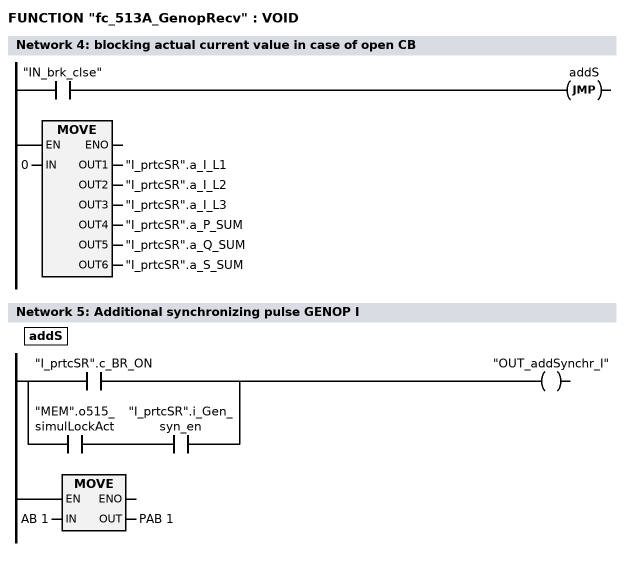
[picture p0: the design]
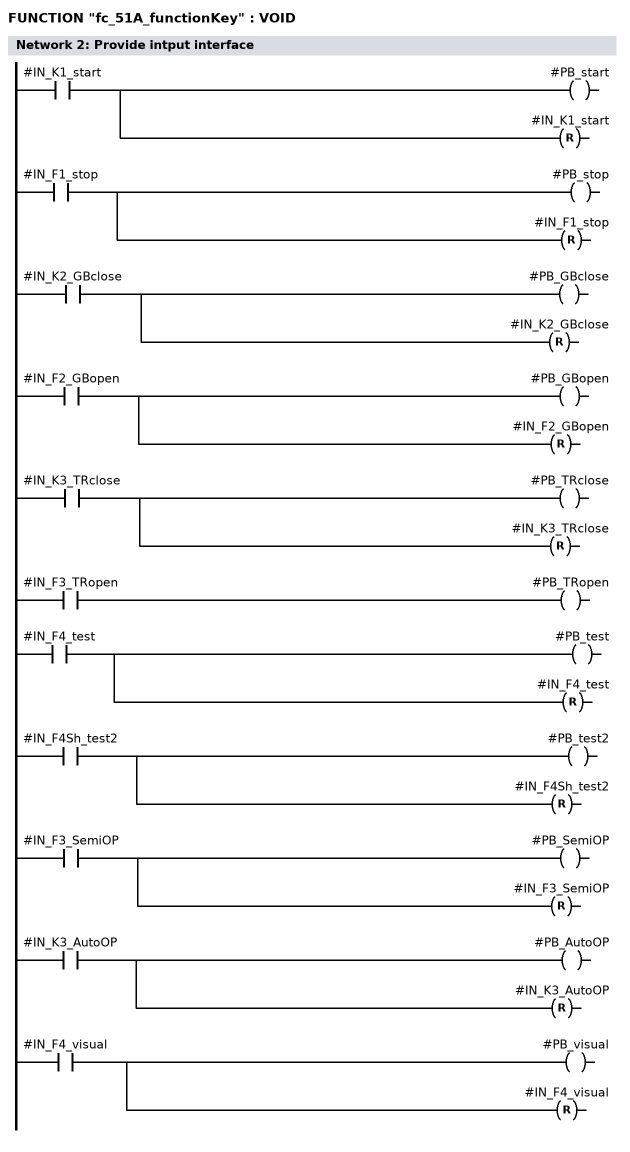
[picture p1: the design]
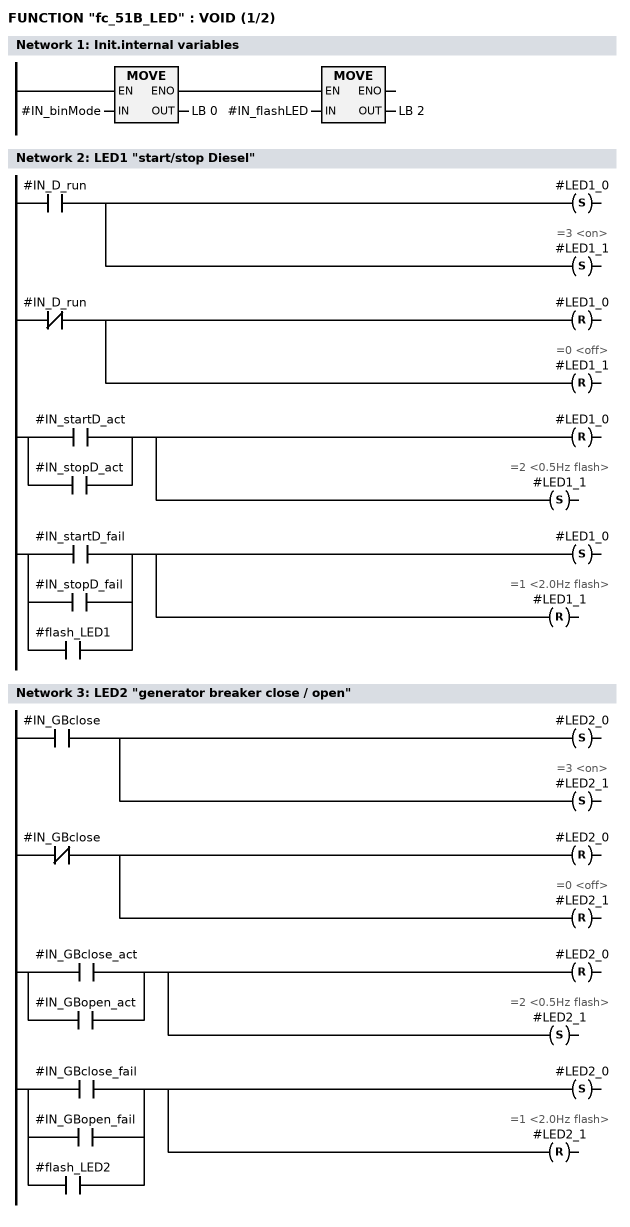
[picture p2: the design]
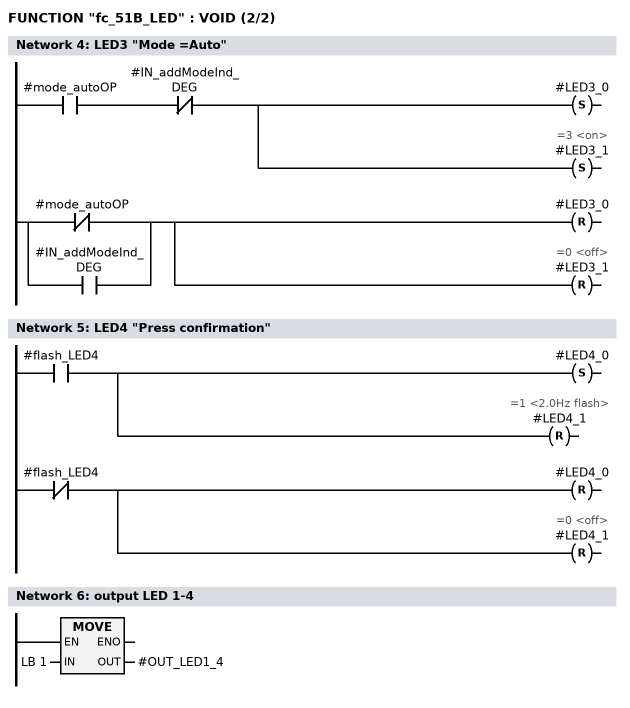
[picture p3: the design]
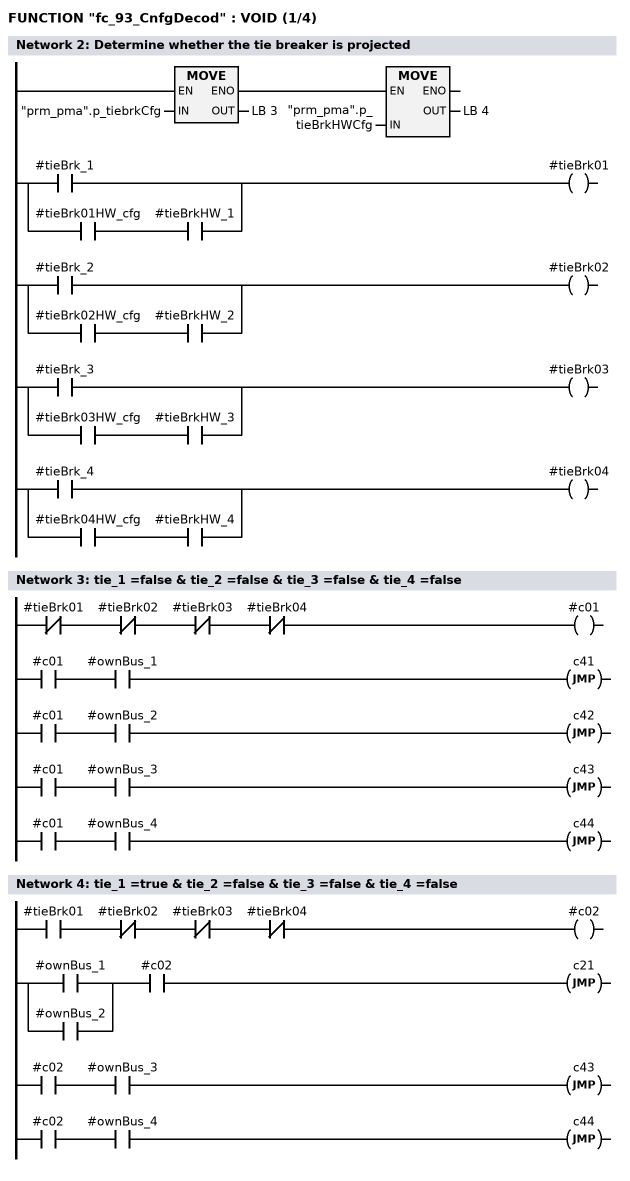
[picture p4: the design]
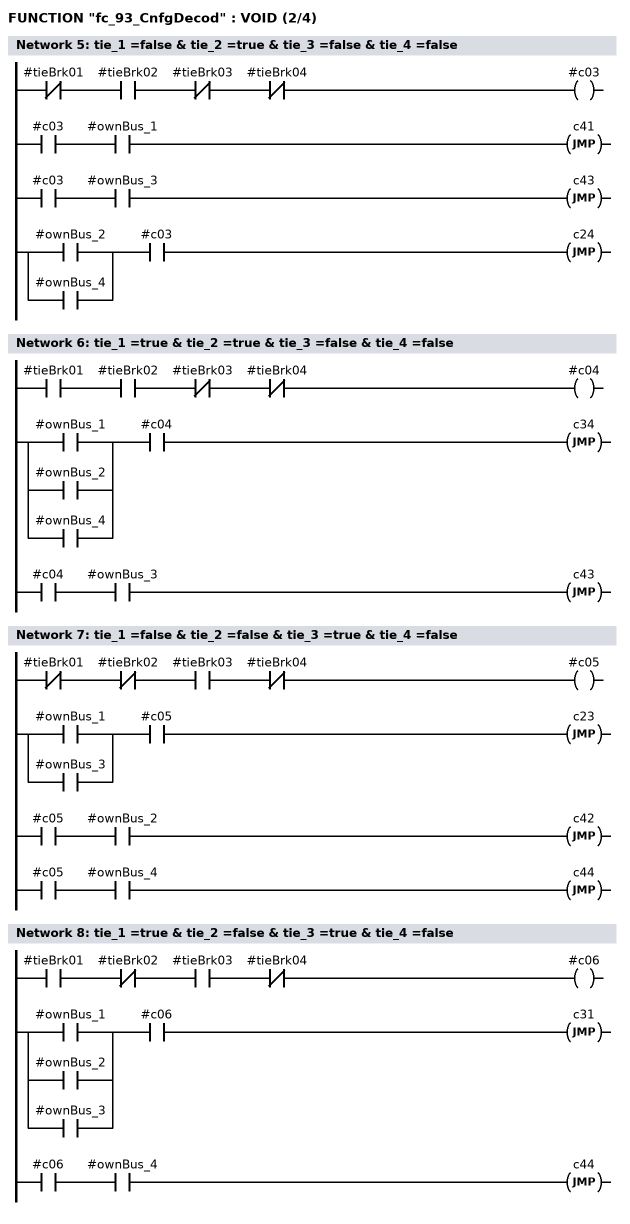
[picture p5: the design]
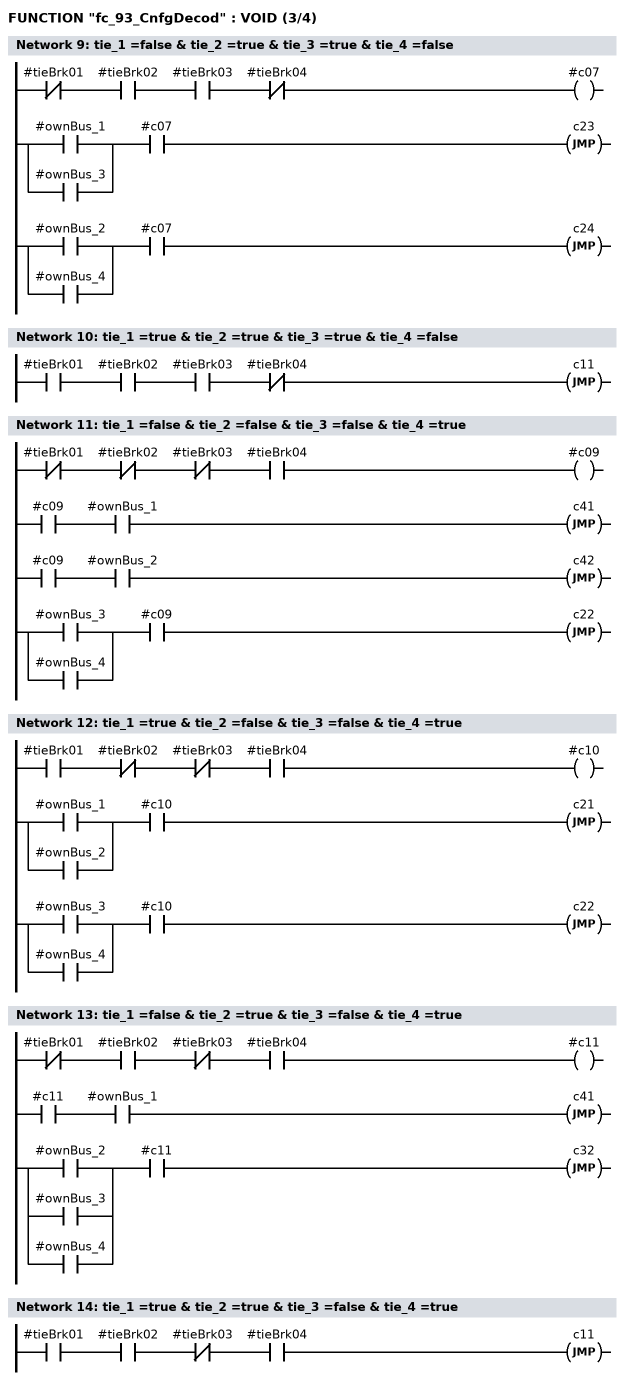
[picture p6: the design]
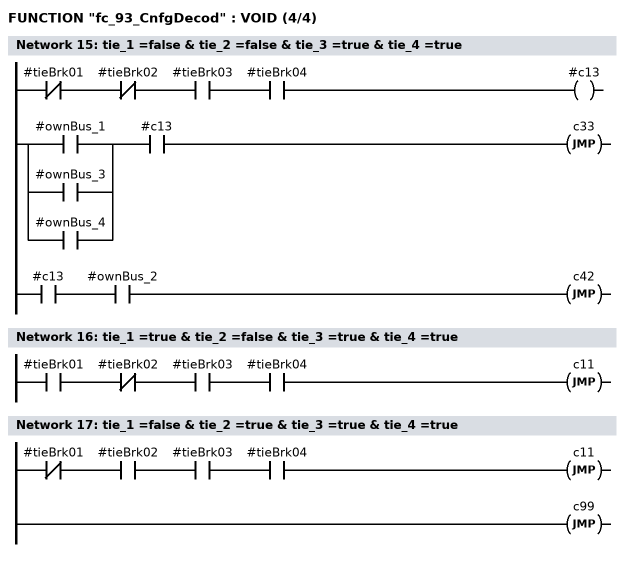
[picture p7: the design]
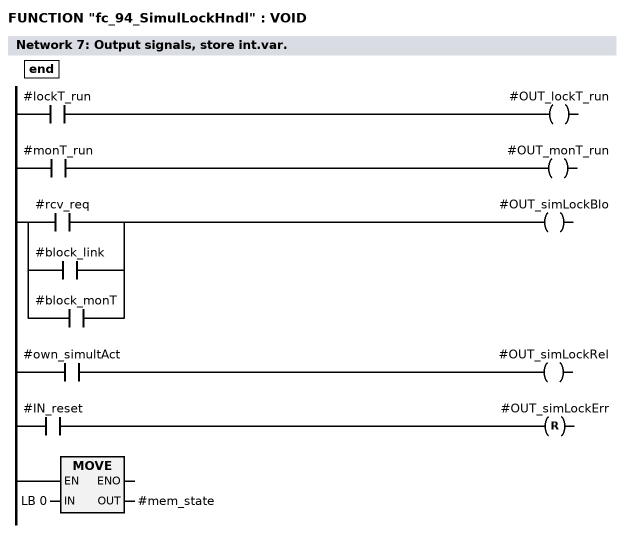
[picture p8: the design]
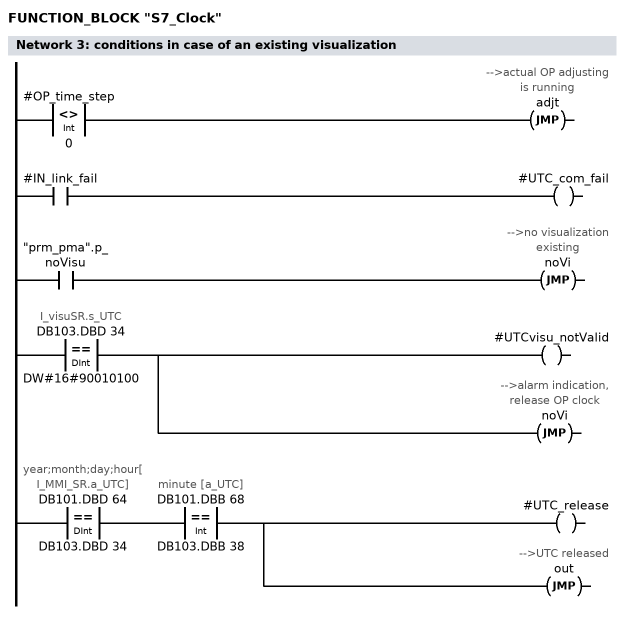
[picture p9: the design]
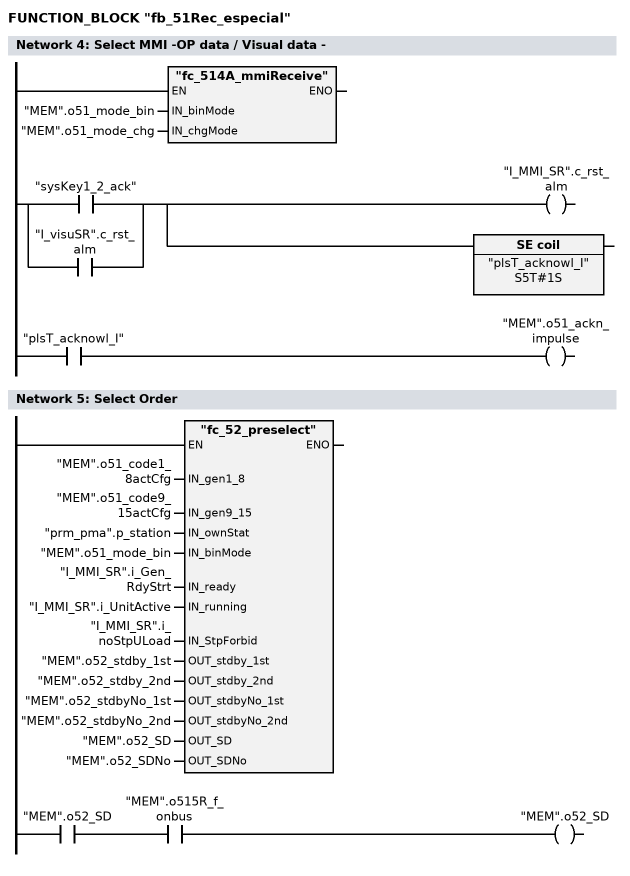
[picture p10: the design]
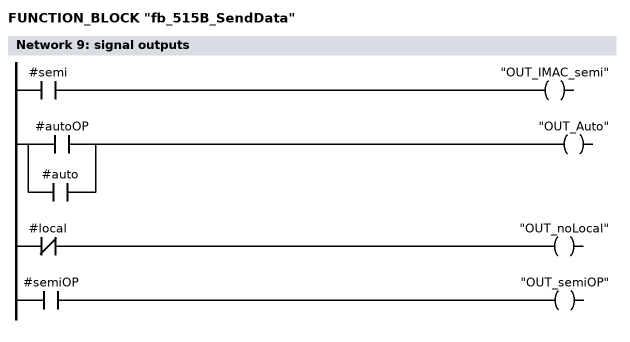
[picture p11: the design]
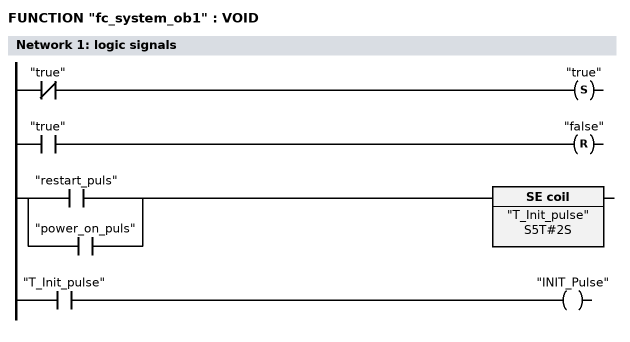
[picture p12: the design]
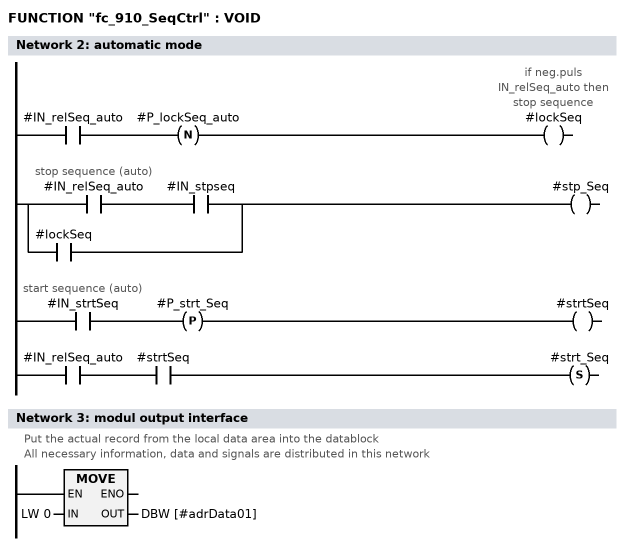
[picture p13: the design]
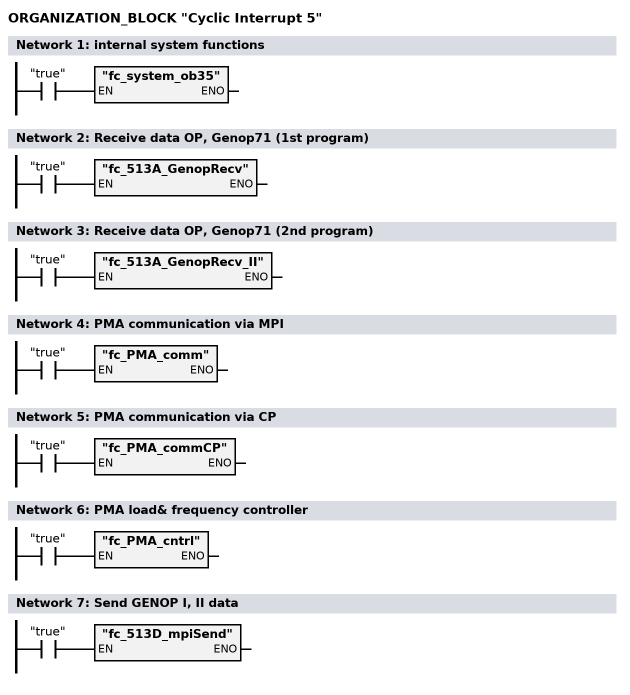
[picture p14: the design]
DATA_BLOCK "DB     35"
TITLE =Internal data:  Step (sequence) contoller
//                                                                                      !
//This data block is the internal data area for the following functions:
//- step controller (FC119)
//- sequence controller (FC120)
//- transition indicator (FC121)
AUTHOR : Kahle
FAMILY : PMA71
NAME : stepCtrl
VERSION : 1.1


  STRUCT    //record 1.sequence
   sequence_1 : STRUCT
    strt_Seq : BOOL ;   //start sequence (preStepNo =1) --system interface--
    stp_Seq : BOOL ;    //stop sequence (reset, delete all register) --system interface--
    var2 : BOOL ;   // var 2
    var3 : BOOL ;   // var 3
    var4 : BOOL ;   // var 4
    var5 : BOOL ;   // var 5
    var6 : BOOL ;   // var 6
    var7 : BOOL ;   // var 7
    var8 : BOOL ;   // var 8
    var9 : BOOL ;   // var 9
    var10 : BOOL ;  // var 10
    var11 : BOOL ;  // var 11
    var12 : BOOL ;  // var 12
    var13 : BOOL ;  // var 13
    var14 : BOOL ;  // var 14
    var15 : BOOL ;   // var 15
    P_cntWait : BOOL ;  // puls flag "counter start waiting time"(.0)
    P_cntMon : BOOL ;   // puls flag "counter start monitoring time"(.1)
    P_nextAct : BOOL ;  // puls flag "out_next" active(.2)
    P_IN_trans : BOOL ; // puls flag "in_trans" (.3)
    preStepNo : BYTE ;  // number of the pre step
    actStepNo : BYTE ;  // actual step
    postStepNo : BYTE ; // number of the post step
    actwaitT : INT ;    // actual waiting time
    actmonT : INT ; // actual monitoring time
    failStep : INT ;    // number of the faulty step
    failTrans : INT ;   // transition condition of the faulty step
   END_STRUCT ;
   sequence_2 : STRUCT
    strt_Seq : BOOL ;   //start sequence (preStepNo =1) --system interface--
    stp_Seq : BOOL ;    //stop sequence (reset, delete all register) --system interface--
    var2 : BOOL ;   // var 2
    var3 : BOOL ;   // var 3
    var4 : BOOL ;   // var 4
    var5 : BOOL ;   // var 5
    var6 : BOOL ;   // var 6
    var7 : BOOL ;   // var 7
    var8 : BOOL ; // var 8
    var9 : BOOL ;   // var 9
    var10 : BOOL ;  // var 10
    var11 : BOOL ;  // var 11
    var12 : BOOL ;  // var 12
    var13 : BOOL ;  // var 13
    var14 : BOOL ;  // var 14
    var15 : BOOL ;  // var 15
    P_cntWait : BOOL ;  // puls flag "counter start waiting time"(.0)
    P_cntMon : BOOL ;   // puls flag "counter start monitoring time"(.1)
    P_nextAct : BOOL ;  // puls flag "out_next" active(.2)
    P_IN_trans : BOOL ; // puls flag "in_trans" (.3)
    preStepNo : BYTE ;  // number of the pre step
    actStepNo : BYTE ;  // actual step
    postStepNo : BYTE ; // number of the post step
    actwaitT : INT ;    // actual waiting time
    actmonT : INT ; // actual monitoring time
    failStep : INT ;    // number of the faulty step
    failTrans : INT ;   // transition condition of the faulty step
   END_STRUCT ;
   sequence_3 : STRUCT
    strt_Seq : BOOL ;   //start sequence (preStepNo =1) --system interface--
    stp_Seq : BOOL ;    //stop sequence (reset, delete all register) --system interface--
    var2 : BOOL ;   // var 2
    var3 : BOOL ;   // var 3
    var4 : BOOL ;   // var 4
    var5 : BOOL ;   // var 5
    var6 : BOOL ;   // var 6
    var7 : BOOL ;   // var 7
    var8 : BOOL ;   // var 8
    var9 : BOOL ;   // var 9
    var10 : BOOL ;  // var 10
    var11 : BOOL ;  // var 11
    var12 : BOOL ;  // var 12
    var13 : BOOL ;  // var 13
    var14 : BOOL ;  // var 14
    var15 : BOOL ;  // var 15
    P_cntWait : BOOL ;  // puls flag "counter start waiting time"(.0)
    P_cntMon : BOOL ;   // puls flag "counter start monitoring time"(.1)
    P_nextAct : BOOL ;  // puls flag "out_next" active(.2)
    P_IN_trans : BOOL ; // puls flag "in_trans" (.3)
    preStepNo : BYTE ;  // number of the pre step
    actStepNo : BYTE ;  // actual step
    postStepNo : BYTE ; // number of the post step
    actwaitT : INT ;    // actual waiting time
    actmonT : INT ; // actual monitoring time
    failStep : INT ;    // number of the faulty step
    failTrans : INT ;   // transition condition of the faulty step
   END_STRUCT ;
   sequence_4 : STRUCT
    strt_Seq : BOOL ;   //start sequence (preStepNo =1) --system interface--
    stp_Seq : BOOL ;    //stop sequence (reset, delete all register) --system interface--
    var2 : BOOL ;   // var 2
    var3 : BOOL ;   // var 3
    var4 : BOOL ;   // var 4
    var5 : BOOL ;   // var 5
    var6 : BOOL ;   // var 6
    var7 : BOOL ;   // var 7
    var8 : BOOL ;   // var 8
    var9 : BOOL ;   // var 9
    var10 : BOOL ;  // var 10
    var11 : BOOL ;  // var 11
    var12 : BOOL ;  // var 12
    var13 : BOOL ;  // var 13
    var14 : BOOL ;  // var 14
    var15 : BOOL ;  // var 15
    P_cntWait : BOOL ;  // puls flag "counter start waiting time"(.0)
    P_cntMon : BOOL ;   // puls flag "counter start monitoring time"(.1)
    P_nextAct : BOOL ;  // puls flag "out_next" active(.2)
    P_IN_trans : BOOL ; // puls flag "in_trans" (.3)
    preStepNo : BYTE ;  // number of the pre step
    actStepNo : BYTE ;  // actual step
    postStepNo : BYTE ; // number of the post step
    actwaitT : INT ;  // actual waiting time
    actmonT : INT ; // actual monitoring time
    failStep : INT ;    // number of the faulty step
    failTrans : INT ;   // transition condition of the faulty step
   END_STRUCT ;
   sequence_5 : STRUCT
    strt_Seq : BOOL ;   //start sequence (preStepNo =1) --system interface--
    stp_Seq : BOOL ;    //stop sequence (reset, delete all register) --system interface--
    var2 : BOOL ;   // var 2
    var3 : BOOL ;   // var 3
    var4 : BOOL ;   // var 4
    var5 : BOOL ;   // var 5
    var6 : BOOL ;   // var 6
    var7 : BOOL ;   // var 7
    var8 : BOOL ;   // var 8
    var9 : BOOL ;   // var 9
    var10 : BOOL ;  // var 10
    var11 : BOOL ;  // var 11
    var12 : BOOL ;  // var 12
    var13 : BOOL ;  // var 13
    var14 : BOOL ;  // var 14
    var15 : BOOL ;  // var 15
    P_cntWait : BOOL ;  // puls flag "counter start waiting time"(.0)
    P_cntMon : BOOL ;   // puls flag "counter start monitoring time"(.1)
    P_nextAct : BOOL ;  // puls flag "out_next" active(.2)
    P_IN_trans : BOOL ; // puls flag "in_trans" (.3)
    preStepNo : BYTE ;  // number of the pre step
    actStepNo : BYTE ;  // actual step
    postStepNo : BYTE ; // number of the post step
    actwaitT : INT ;    // actual waiting time
    actmonT : INT ; // actual monitoring time
    failStep : INT ;    // number of the faulty step
    failTrans : INT ;   // transition condition of the faulty step
   END_STRUCT ;
   sequence_6 : STRUCT
    strt_Seq : BOOL ;   //start sequence (preStepNo =1) --system interface--
    stp_Seq : BOOL ;    //stop sequence (reset, delete all register) --system interface--
    var2 : BOOL ;   // var 2
    var3 : BOOL ;   // var 3
    var4 : BOOL ;   // var 4
    var5 : BOOL ;   // var 5
    var6 : BOOL ;   // var 6
    var7 : BOOL ;   // var 7
    var8 : BOOL ;   // var 8
    var9 : BOOL ;   // var 9
    var10 : BOOL ;  // var 10
    var11 : BOOL ;  // var 11
    var12 : BOOL ;  // var 12
    var13 : BOOL ;  // var 13
    var14 : BOOL ;  // var 14
    var15 : BOOL ;  // var 15
    P_cntWait : BOOL ;   // puls flag "counter start waiting time"(.0)
    P_cntMon : BOOL ;   // puls flag "counter start monitoring time"(.1)
    P_nextAct : BOOL ;  // puls flag "out_next" active(.2)
    P_IN_trans : BOOL ; // puls flag "in_trans" (.3)
    preStepNo : BYTE ;  // number of the pre step
    actStepNo : BYTE ;  // actual step
    postStepNo : BYTE ; // number of the post step
    actwaitT : INT ;    // actual waiting time
    actmonT : INT ; // actual monitoring time
    failStep : INT ;    // number of the faulty step
    failTrans : INT ;   // transition condition of the faulty step
   END_STRUCT ;
   sequence_7 : STRUCT
    strt_Seq : BOOL ;   //start sequence (preStepNo =1) --system interface--
    stp_Seq : BOOL ;    //stop sequence (reset, delete all register) --system interface--
    var2 : BOOL ;   // var 2
    var3 : BOOL ;   // var 3
    var4 : BOOL ;   // var 4
    var5 : BOOL ;   // var 5
    var6 : BOOL ;   // var 6
    var7 : BOOL ;   // var 7
    var8 : BOOL ;   // var 8
    var9 : BOOL ;   // var 9
    var10 : BOOL ;    // var 10
    var11 : BOOL ;  // var 11
    var12 : BOOL ;  // var 12
    var13 : BOOL ;  // var 13
    var14 : BOOL ;  // var 14
    var15 : BOOL ;  // var 15
    P_cntWait : BOOL ;  // puls flag "counter start waiting time"(.0)
    P_cntMon : BOOL ;   // puls flag "counter start monitoring time"(.1)
    P_nextAct : BOOL ;  // puls flag "out_next" active(.2)
    P_IN_trans : BOOL ; // puls flag "in_trans" (.3)
    preStepNo : BYTE ;  // number of the pre step
    actStepNo : BYTE ;  // actual step
    postStepNo : BYTE ; // number of the post step
    actwaitT : INT ;    // actual waiting time
    actmonT : INT ; // actual monitoring time
    failStep : INT ;    // number of the faulty step
    failTrans : INT ;   // transition condition of the faulty step
   END_STRUCT ;
   sequence_8 : STRUCT
    strt_Seq : BOOL ;   //start sequence (preStepNo =1) --system interface--
    stp_Seq : BOOL ;    //stop sequence (reset, delete all register) --system interface--
    var2 : BOOL ;   // var 2
    var3 : BOOL ; // var 3
    var4 : BOOL ;   // var 4
    var5 : BOOL ;   // var 5
    var6 : BOOL ;   // var 6
    var7 : BOOL ;   // var 7
    var8 : BOOL ;   // var 8
    var9 : BOOL ;   // var 9
    var10 : BOOL ;  // var 10
    var11 : BOOL ;  // var 11
    var12 : BOOL ;  // var 12
    var13 : BOOL ;  // var 13
    var14 : BOOL ;  // var 14
    var15 : BOOL ;  // var 15
    P_cntWait : BOOL ;  // puls flag "counter start waiting time"(.0)
    P_cntMon : BOOL ;   // puls flag "counter start monitoring time"(.1)
    P_nextAct : BOOL ;  // puls flag "out_next" active(.2)
    P_IN_trans : BOOL ; // puls flag "in_trans" (.3)
    preStepNo : BYTE ;  // number of the pre step
    actStepNo : BYTE ;  // actual step
    postStepNo : BYTE ; // number of the post step
    actwaitT : INT ;    // actual waiting time
    actmonT : INT ; // actual monitoring time
    failStep : INT ;    // number of the faulty step
    failTrans : INT ;   // transition condition of the faulty step
   END_STRUCT ;
   sequence_9 : STRUCT
    strt_Seq : BOOL ;   //start sequence (preStepNo =1) --system interface--
    stp_Seq : BOOL ;    //stop sequence (reset, delete all register) --system interface--
    var2 : BOOL ;   // var 2
    var3 : BOOL ;   // var 3
    var4 : BOOL ;   // var 4
    var5 : BOOL ;   // var 5
    var6 : BOOL ;   // var 6
    var7 : BOOL ;   // var 7
    var8 : BOOL ;   // var 8
    var9 : BOOL ;   // var 9
    var10 : BOOL ;  // var 10
    var11 : BOOL ;  // var 11
    var12 : BOOL ;  // var 12
    var13 : BOOL ;  // var 13
    var14 : BOOL ;  // var 14
    var15 : BOOL ;  // var 15
    P_cntWait : BOOL ;  // puls flag "counter start waiting time"(.0)
    P_cntMon : BOOL ;   // puls flag "counter start monitoring time"(.1)
    P_nextAct : BOOL ;  // puls flag "out_next" active(.2)
    P_IN_trans : BOOL ; // puls flag "in_trans" (.3)
    preStepNo : BYTE ;  // number of the pre step
    actStepNo : BYTE ;  // actual step
    postStepNo : BYTE ; // number of the post step
    actwaitT : INT ;    // actual waiting time
    actmonT : INT ; // actual monitoring time
    failStep : INT ;    // number of the faulty step
    failTrans : INT ;   // transition condition of the faulty step
   END_STRUCT ;
  END_STRUCT ;
BEGIN
   sequence_1.strt_Seq := FALSE;
   sequence_1.stp_Seq := FALSE;
   sequence_1.var2 := FALSE;
   sequence_1.var3 := FALSE;
   sequence_1.var4 := FALSE;
   sequence_1.var5 := FALSE;
   sequence_1.var6 := FALSE;
   sequence_1.var7 := FALSE;
   sequence_1.var8 := FALSE;
   sequence_1.var9 := FALSE;
   sequence_1.var10 := FALSE;
   sequence_1.var11 := FALSE;
   sequence_1.var12 := FALSE;
   sequence_1.var13 := FALSE;
   sequence_1.var14 := FALSE;
   sequence_1.var15 := FALSE;
   sequence_1.P_cntWait := FALSE;
   sequence_1.P_cntMon := FALSE;
   sequence_1.P_nextAct := FALSE;
   sequence_1.P_IN_trans := FALSE;
   sequence_1.preStepNo := B#16#0;
   sequence_1.actStepNo := B#16#0;
   sequence_1.postStepNo := B#16#0;
   sequence_1.actwaitT := 0;
   sequence_1.actmonT := 0;
   sequence_1.failStep := 0;
   sequence_1.failTrans := 0;
   sequence_2.strt_Seq := FALSE;
   sequence_2.stp_Seq := FALSE;
   sequence_2.var2 := FALSE;
   sequence_2.var3 := FALSE;
   sequence_2.var4 := FALSE;
   sequence_2.var5 := FALSE;
   sequence_2.var6 := FALSE;
   sequence_2.var7 := FALSE;
   sequence_2.var8 := FALSE;
   sequence_2.var9 := FALSE;
   sequence_2.var10 := FALSE;
   sequence_2.var11 := FALSE;
   sequence_2.var12 := FALSE;
   sequence_2.var13 := FALSE;
   sequence_2.var14 := FALSE;
   sequence_2.var15 := FALSE;
   sequence_2.P_cntWait := FALSE;
   sequence_2.P_cntMon := FALSE;
   sequence_2.P_nextAct := FALSE;
   sequence_2.P_IN_trans := FALSE;
   sequence_2.preStepNo := B#16#0;
   sequence_2.actStepNo := B#16#0;
   sequence_2.postStepNo := B#16#0;
   sequence_2.actwaitT := 0;
   sequence_2.actmonT := 0;
   sequence_2.failStep := 0;
   sequence_2.failTrans := 0;
   sequence_3.strt_Seq := FALSE;
   sequence_3.stp_Seq := FALSE;
   sequence_3.var2 := FALSE;
   sequence_3.var3 := FALSE;
   sequence_3.var4 := FALSE;
   sequence_3.var5 := FALSE;
   sequence_3.var6 := FALSE;
   sequence_3.var7 := FALSE;
   sequence_3.var8 := FALSE;
   sequence_3.var9 := FALSE;
   sequence_3.var10 := FALSE;
   sequence_3.var11 := FALSE;
   sequence_3.var12 := FALSE;
   sequence_3.var13 := FALSE;
   sequence_3.var14 := FALSE;
   sequence_3.var15 := FALSE;
   sequence_3.P_cntWait := FALSE;
   sequence_3.P_cntMon := FALSE;
   sequence_3.P_nextAct := FALSE;
   sequence_3.P_IN_trans := FALSE;
   sequence_3.preStepNo := B#16#0;
   sequence_3.actStepNo := B#16#0;
   sequence_3.postStepNo := B#16#0;
   sequence_3.actwaitT := 0;
   sequence_3.actmonT := 0;
   sequence_3.failStep := 0;
   sequence_3.failTrans := 0;
   sequence_4.strt_Seq := FALSE;
   sequence_4.stp_Seq := FALSE;
   sequence_4.var2 := FALSE;
   sequence_4.var3 := FALSE;
   sequence_4.var4 := FALSE;
   sequence_4.var5 := FALSE;
   sequence_4.var6 := FALSE;
   sequence_4.var7 := FALSE;
   sequence_4.var8 := FALSE;
   sequence_4.var9 := FALSE;
   sequence_4.var10 := FALSE;
   sequence_4.var11 := FALSE;
   sequence_4.var12 := FALSE;
   sequence_4.var13 := FALSE;
   sequence_4.var14 := FALSE;
   sequence_4.var15 := FALSE;
   sequence_4.P_cntWait := FALSE;
   sequence_4.P_cntMon := FALSE;
   sequence_4.P_nextAct := FALSE;
   sequence_4.P_IN_trans := FALSE;
   sequence_4.preStepNo := B#16#0;
   sequence_4.actStepNo := B#16#0;
   sequence_4.postStepNo := B#16#0;
   sequence_4.actwaitT := 0;
   sequence_4.actmonT := 0;
   sequence_4.failStep := 0;
   sequence_4.failTrans := 0;
   sequence_5.strt_Seq := FALSE;
   sequence_5.stp_Seq := FALSE;
   sequence_5.var2 := FALSE;
   sequence_5.var3 := FALSE;
   sequence_5.var4 := FALSE;
   sequence_5.var5 := FALSE;
   sequence_5.var6 := FALSE;
   sequence_5.var7 := FALSE;
   sequence_5.var8 := FALSE;
   sequence_5.var9 := FALSE;
   sequence_5.var10 := FALSE;
   sequence_5.var11 := FALSE;
   sequence_5.var12 := FALSE;
   sequence_5.var13 := FALSE;
   sequence_5.var14 := FALSE;
   sequence_5.var15 := FALSE;
   sequence_5.P_cntWait := FALSE;
   sequence_5.P_cntMon := FALSE;
   sequence_5.P_nextAct := FALSE;
   sequence_5.P_IN_trans := FALSE;
   sequence_5.preStepNo := B#16#0;
   sequence_5.actStepNo := B#16#0;
   sequence_5.postStepNo := B#16#0;
   sequence_5.actwaitT := 0;
   sequence_5.actmonT := 0;
   sequence_5.failStep := 0;
   sequence_5.failTrans := 0;
   sequence_6.strt_Seq := FALSE;
   sequence_6.stp_Seq := FALSE;
   sequence_6.var2 := FALSE;
   sequence_6.var3 := FALSE;
   sequence_6.var4 := FALSE;
   sequence_6.var5 := FALSE;
   sequence_6.var6 := FALSE;
   sequence_6.var7 := FALSE;
   sequence_6.var8 := FALSE;
   sequence_6.var9 := FALSE;
   sequence_6.var10 := FALSE;
   sequence_6.var11 := FALSE;
   sequence_6.var12 := FALSE;
   sequence_6.var13 := FALSE;
   sequence_6.var14 := FALSE;
   sequence_6.var15 := FALSE;
   sequence_6.P_cntWait := FALSE;
   sequence_6.P_cntMon := FALSE;
   sequence_6.P_nextAct := FALSE;
   sequence_6.P_IN_trans := FALSE;
   sequence_6.preStepNo := B#16#0;
   sequence_6.actStepNo := B#16#0;
   sequence_6.postStepNo := B#16#0;
   sequence_6.actwaitT := 0;
   sequence_6.actmonT := 0;
   sequence_6.failStep := 0;
   sequence_6.failTrans := 0;
   sequence_7.strt_Seq := FALSE;
   sequence_7.stp_Seq := FALSE;
   sequence_7.var2 := FALSE;
   sequence_7.var3 := FALSE;
   sequence_7.var4 := FALSE;
   sequence_7.var5 := FALSE;
   sequence_7.var6 := FALSE;
   sequence_7.var7 := FALSE;
   sequence_7.var8 := FALSE;
   sequence_7.var9 := FALSE;
   sequence_7.var10 := FALSE;
   sequence_7.var11 := FALSE;
   sequence_7.var12 := FALSE;
   sequence_7.var13 := FALSE;
   sequence_7.var14 := FALSE;
   sequence_7.var15 := FALSE;
   sequence_7.P_cntWait := FALSE;
   sequence_7.P_cntMon := FALSE;
   sequence_7.P_nextAct := FALSE;
   sequence_7.P_IN_trans := FALSE;
   sequence_7.preStepNo := B#16#0;
   sequence_7.actStepNo := B#16#0;
   sequence_7.postStepNo := B#16#0;
   sequence_7.actwaitT := 0;
   sequence_7.actmonT := 0;
   sequence_7.failStep := 0;
   sequence_7.failTrans := 0;
   sequence_8.strt_Seq := FALSE;
   sequence_8.stp_Seq := FALSE;
   sequence_8.var2 := FALSE;
   sequence_8.var3 := FALSE;
   sequence_8.var4 := FALSE;
   sequence_8.var5 := FALSE;
   sequence_8.var6 := FALSE;
   sequence_8.var7 := FALSE;
   sequence_8.var8 := FALSE;
   sequence_8.var9 := FALSE;
   sequence_8.var10 := FALSE;
   sequence_8.var11 := FALSE;
   sequence_8.var12 := FALSE;
   sequence_8.var13 := FALSE;
   sequence_8.var14 := FALSE;
   sequence_8.var15 := FALSE;
   sequence_8.P_cntWait := FALSE;
   sequence_8.P_cntMon := FALSE;
   sequence_8.P_nextAct := FALSE;
   sequence_8.P_IN_trans := FALSE;
   sequence_8.preStepNo := B#16#0;
   sequence_8.actStepNo := B#16#0;
   sequence_8.postStepNo := B#16#0;
   sequence_8.actwaitT := 0;
   sequence_8.actmonT := 0;
   sequence_8.failStep := 0;
   sequence_8.failTrans := 0;
   sequence_9.strt_Seq := FALSE;
   sequence_9.stp_Seq := FALSE;
   sequence_9.var2 := FALSE;
   sequence_9.var3 := FALSE;
   sequence_9.var4 := FALSE;
   sequence_9.var5 := FALSE;
   sequence_9.var6 := FALSE;
   sequence_9.var7 := FALSE;
   sequence_9.var8 := FALSE;
   sequence_9.var9 := FALSE;
   sequence_9.var10 := FALSE;
   sequence_9.var11 := FALSE;
   sequence_9.var12 := FALSE;
   sequence_9.var13 := FALSE;
   sequence_9.var14 := FALSE;
   sequence_9.var15 := FALSE;
   sequence_9.P_cntWait := FALSE;
   sequence_9.P_cntMon := FALSE;
   sequence_9.P_nextAct := FALSE;
   sequence_9.P_IN_trans := FALSE;
   sequence_9.preStepNo := B#16#0;
   sequence_9.actStepNo := B#16#0;
   sequence_9.postStepNo := B#16#0;
   sequence_9.actwaitT := 0;
   sequence_9.actmonT := 0;
   sequence_9.failStep := 0;
   sequence_9.failTrans := 0;
END_DATA_BLOCK

DATA_BLOCK "prm_pma"
TITLE =Configuration data: PMA71 without GENOP71 data
//
//V 2.2 28.09.00 Kahle -last vaild version
//V 2.3 05.10.00 Kahle -DBX602.6, DBX602.7 new description
//                                  -DBW490 p_LimCurrMonit
//                                  -DBW650 p_dlyT_GenBrkTrip
//                                  -DBW652 p_dlyT_TrsBrkTrip
//                                  -DBW654 p_dlyT_GenBrkReady
//                                  -DBW656 p_dlyT_TrsBrkReady
//V 2.4 10.10.00 Kahle -DBX42.4 p_3Tie_cycle
//V 2.5 17.10.00 Kahle -DBW890&892 move to DBW900&902
//V 2.6 05.12.00 Kahle -DBB600    p_TrsBrk_No
//                                  -DBX601.0 p_2ndGenBrkON_auto
//                                  -DBX660.5 p_blackout_BrkOff
//                                  -DBX904.0 p_TrsLine
//V2.7 13.02.01 Kahle -DBX366.5 p_noStpCmd-SD2
//                                 -DBX395.0 p_uploadLatch
//                                 -DBX67.7 p_MonitPrLubPress
//                                 -DBX77.0 p_NoPreLub_Blackout
//                                 -DBW94 p_VoltMiss
//                                 -DBX536.0 p_wood_Isochron
//                                - DBX536.1 p_wood_IsochronAuto
//                                 -DBX536.2 p_wood_IsochronExt
//                                 -DBX536.3 p_wood_IsochronLowAct
//V2.11 23.10.03 Kahle -DBW910 p_SG_Deexcit_Under_Frec
AUTHOR : Kahle
FAMILY : PMA71
NAME : prm_pma
VERSION : 2.11


  STRUCT
   p_station : BYTE  := B#16#5; //PMA station
   p_bus_part : BYTE  := B#16#1;    //Corresponding busbar of the station and tie breaker
   p_stat_add : BYTE ;  //Station addition =0:DieselGen/=1:Shaft Gen/=2:EG/=3:DEG/=4:TB/=5:SC)
   p_tiebrkCfg : BYTE ; //Tie breaker (x.0=TieBrk1... x.3=TieBrk4/ x.5=2nd TieBrk2... x.7=2nd TieBrk4)
   p_tieBrkHWCfg : BYTE ;   //Tie breaker as binary input (x.0 =TieBrk1 ... x.3 =TieBrk4)
   p_cfg11 : WORD  := W#16#3007;    //Bus Config 11 (x.0 =stat.1 ...x.12 =stat.13, x.13 =emerg, x.14,15 =shore1, 2)
   p_cfg21 : WORD ; //Bus Config 21 (x.0 =stat.1 ...x.12 =stat.13, x.13 =emerg, x.14,15 =shore1, 2)
   p_cfg22 : WORD ; //Bus Config 22 (x.0 =stat.1 ...x.12 =stat.13, x.13 =emerg, x.14,15 =shore1, 2)
   p_cfg23 : WORD ; //Bus Config 23 (x.0 =stat.1 ...x.12 =stat.13, x.13 =emerg, x.14,15 =shore1, 2)
   p_cfg24 : WORD ; //Bus Config 24 (x.0 =stat.1 ...x.12 =stat.13, x.13 =emerg, x.14,15 =shore1, 2)
   p_cfg31 : WORD ; //Bus Config 31 (x.0 =stat.1 ...x.12 =stat.13, x.13 =emerg, x.14,15 =shore1, 2)
   p_cfg32 : WORD ; //Bus Config 32 (x.0 =stat.1 ...x.12 =stat.13, x.13 =emerg, x.14,15 =shore1, 2)
   p_cfg33 : WORD ; //Bus Config 33 (x.0 =stat.1 ...x.12 =stat.13, x.13 =emerg, x.14,15 =shore1, 2)
   p_cfg34 : WORD ; //Bus Config 34 (x.0 =stat.1 ...x.12 =stat.13, x.13 =emerg, x.14,15 =shore1, 2)
   p_cfg41 : WORD  := W#16#1007;    //Bus Config 41 (x.0 =stat.1 ...x.12 =stat.13, x.13 =emerg, x.14,15 =shore1, 2)
   p_cfg42 : WORD  := W#16#2000;    //Bus Config 42 (x.0 =stat.1 ...x.12 =stat.13, x.13 =emerg, x.14,15 =shore1, 2)
   p_cfg43 : WORD ; //Bus Config 43 (x.0 =stat.1 ...x.12 =stat.13, x.13 =emerg, x.14,15 =shore1, 2)
   p_cfg44 : WORD ; //Bus Config 44 (x.0 =stat.1 ...x.12 =stat.13, x.13 =emerg, x.14,15 =shore1, 2)
   p_moniTimeMPI : S5TIME  := S5T#2S;   //Monitoring time MPI link
   p_cfgUness : WORD  := W#16#2000; //non essential MPI participants -don't set uncond.semi auto in case of failure-
   p_CP_add : WORD  := W#16#16E;    //Start adress of the CP for the internal communication -option-
   p_CPU_Typ : INT ;    //CPU Type 15 =315 / 16=316 / 18=318 <detected automatically by program>
   p_No_perCall : BYTE  := B#16#1;  //The number of stations per call to which data are sent
   p_GENOP_Ver : BYTE  := B#16#12;  //Version of the Genop71
   p_OLM_err : BOOL ;   //OLM -failure input
   p_local_alarm : BOOL ;   //Local alarm indication
   p_MPIfail_auto : BOOL  := TRUE;  //OPTION: Further in automatic in case of one fault MPI station
   p_manTieBrk : BOOL ; //OPTION: Manually tie breaker, signal comes via MPI
   p_3Tie_cycle : BOOL ;    //OPTION: Three tie breaker configuration in a cycle
   p_fullFct_auto : BOOL ;  //OPTION: Full functionality of the OP in automatic (=1)
   p_invAllocation : BOOL ; //OPTION: Tie breaker invert allocation between busbar and transferline
   var11 : BOOL ;
   p_OP_notExist : BOOL ;   //OP not exist (local  semi automatic' locked)
   p_OP_rel_auto : BOOL ;   //Mode automatic via OP released -start/stop by operator-
   p_OP_confirm : BOOL ;    //OP operation with confirmation
   p_Opfail_visu : BOOL ;   //Force operating via IMAC in case of an OP failure
   p_InalrmStore : BOOL ;   //Store failure, reset with the acknowledge button
   p_InemgLocal : BOOL ;    //signal "emergency local" available
   p_visuNoOperat : BOOL  := TRUE;  //OPTION: Operation via Visu not possible
   p_visuToAuto : BOOL ;    //OPTION: If control position switched to Visu the mode switched to Auto
   p_noMSB_Auto : BOOL ;    //OPTION: Signal "MSB_Auto" not available
   p_noShoreOff : BOOL ;    //OPTION: Signal "shore connection off" not available
   p_noVisu : BOOL ; //OPTION: no visualisation existing
   p_noCtrl : BOOL ;    //OPTION: Frequency- & Load-Controller are locked (=1: lock)
   p_UBLoff_tooLow : BOOL ; //OPTION: UBL switch off if the UBLmax value is to low
   p_common_alarm : BOOL ;  //OPTION: common alarm (=1), system o.k. indication only (=0)
   p_noLoad_SemiIMAC : BOOL ;   //OPTION: no loadsharing if semi-IMAC mode isactive (=1)
   p_2ndGenop_oneOP : BOOL ;    //OPTION: 2nd GENOP, but only one OP
   p_TwofixFreq : BOOL  := TRUE;    //OPTION: Two different generator frequency [0 =no], [1 =yes]
   var23 : BOOL ;
   var24 : BOOL ;
   var25 : BOOL ;
   var26 : BOOL ;
   var27 : BOOL ;
   var28 : BOOL ;
   var29 : BOOL ;
   p_OUTbrkOff : BOOL ; //Additional output "Generator breaker off"
   p_InbrkOff : BOOL ;  //Feedback "Generator breaker off" available
   p_InbrkTest : BOOL ; //Feedback "GenBrk, TieBrk, ShoreCon" in test position available
   p_InshoreOn : BOOL ; //Feedback "Shore connection breaker on" available
   p_INShore2On : BOOL ;    //Feedback "Second shore connection breaker on" available
   p_INShore2Off : BOOL ;   //Feedback "Second shore connection breaker off" available
   p_brkChkLock : BOOL ;    //Plausibility check generator breaker lock
   var30 : BOOL ;
   var31 : BOOL ;
   var32 : BOOL ;
   var33 : BOOL ;
   var34 : BOOL ;
   var35 : BOOL ;
   var36 : BOOL ;
   var37 : BOOL ;
   var38 : BOOL ;
   IN_0_0 : BOOL ;  //I 0.0  : mask =0: input '1' =high / mask =1: input '0' =high
   IN_0_1 : BOOL ;  //I 0.1  : mask =0: input '1' =high / mask =1: input '0' =high
   IN_0_2 : BOOL ;  //I 0.2  : mask =0: input '1' =high / mask =1: input '0' =high
   IN_0_3 : BOOL ;  //I 0.3  : mask =0: input '1' =high / mask =1: input '0' =high
   IN_0_4 : BOOL ;  //I 0.4  : mask =0: input '1' =high / mask =1: input '0' =high
   IN_0_5 : BOOL ;  //I 0.5  : mask =0: input '1' =high / mask =1: input '0' =high
   IN_0_6 : BOOL ;  //I 0.6  : mask =0: input '1' =high / mask =1: input '0' =high
   IN_0_7 : BOOL ;  //I 0.7  : mask =0: input '1' =high / mask =1: input '0' =high
   IN_1_0 : BOOL ;  //I 1.0  : mask =0: input '1' =high / mask =1: input '0' =high
   IN_1_1 : BOOL ;  //I 1.1  : mask =0: input '1' =high / mask =1: input '0' =high
   IN_1_2 : BOOL ;  //I 1.2  : mask =0: input '1' =high / mask =1: input '0' =high
   IN_1_3 : BOOL ;  //I 1.3  : mask =0: input '1' =high / mask =1: input '0' =high
   IN_1_4 : BOOL ;  //I 1.4  : mask =0: input '1' =high / mask =1: input '0' =high
   IN_1_5 : BOOL ;  //I 1.5  : mask =0: input '1' =high / mask =1: input '0' =high
   IN_1_6 : BOOL ;  //I 1.6  : mask =0: input '1' =high / mask =1: input '0' =high
   IN_1_7 : BOOL ;  //I 1.7  : mask =0: input '1' =high / mask =1: input '0' =high
   IN_2_0 : BOOL ;  //I 2.0  : mask =0: input '1' =high / mask =1: input '0' =high
   IN_2_1 : BOOL ;  //I 2.1  : mask =0: input '1' =high / mask =1: input '0' =high
   IN_2_2 : BOOL ;  //I 2.2  : mask =0: input '1' =high / mask =1: input '0' =high
   IN_2_3 : BOOL ;  //I 2.3  : mask =0: input '1' =high / mask =1: input '0' =high
   IN_2_4 : BOOL ;  //I 2.4  : mask =0: input '1' =high / mask =1: input '0' =high
   IN_2_5 : BOOL ;  //I 2.5  : mask =0: input '1' =high / mask =1: input '0' =high
   IN_2_6 : BOOL ;  //I 2.6  : mask =0: input '1' =high / mask =1: input '0' =high
   IN_2_7 : BOOL ;  //I 2.7  : mask =0: input '1' =high / mask =1: input '0' =high
   IN_3_0 : BOOL ;  //I 3.0  : mask =0: input '1' =high / mask =1: input '0' =high
   IN_3_1 : BOOL ;  //I 3.1  : mask =0: input '1' =high / mask =1: input '0' =high
   IN_3_2 : BOOL ;  //I 3.2  : mask =0: input '1' =high / mask =1: input '0' =high
   IN_3_3 : BOOL ;  //I 3.3  : mask =0: input '1' =high / mask =1: input '0' =high
   IN_3_4 : BOOL ;  //I 3.4  : mask =0: input '1' =high / mask =1: input '0' =high
   IN_3_5 : BOOL ;  //I 3.5  : mask =0: input '1' =high / mask =1: input '0' =high
   IN_3_6 : BOOL ;  //I 3.6  : mask =0: input '1' =high / mask =1: input '0' =high
   IN_3_7 : BOOL ;  //I 3.7  : mask =0: input '1' =high / mask =1: input '0' =high
   IN_4_0 : BOOL ;  //I 4.0  : mask =0: input '1' =high / mask =1: input '0' =high
   IN_4_1 : BOOL ;  //I 4.1  : mask =0: input '1' =high / mask =1: input '0' =high
   IN_4_2 : BOOL ;  //I 4.2  : mask =0: input '1' =high / mask =1: input '0' =high
   IN_4_3 : BOOL ;  //I 4.3  : mask =0: input '1' =high / mask =1: input '0' =high
   IN_4_4 : BOOL ;  //I 4.4  : mask =0: input '1' =high / mask =1: input '0' =high
   IN_4_5 : BOOL ;  //I 4.5  : mask =0: input '1' =high / mask =1: input '0' =high
   IN_4_6 : BOOL ;  //I 4.6  : mask =0: input '1' =high / mask =1: input '0' =high
   IN_4_7 : BOOL ;  //I 4.7  : mask =0: input '1' =high / mask =1: input '0' =high
   IN_5_0 : BOOL ;  //I 5.0  : mask =0: input '1' =high / mask =1: input '0' =high
   IN_5_1 : BOOL ;  //I 5.1  : mask =0: input '1' =high / mask =1: input '0' =high
   IN_5_2 : BOOL ;  //I 5.2  : mask =0: input '1' =high / mask =1: input '0' =high
   IN_5_3 : BOOL ;  //I 5.3  : mask =0: input '1' =high / mask =1: input '0' =high
   IN_5_4 : BOOL ;  //I 5.4  : mask =0: input '1' =high / mask =1: input '0' =high
   IN_5_5 : BOOL ;  //I 5.5  : mask =0: input '1' =high / mask =1: input '0' =high
   IN_5_6 : BOOL ;  //I 5.6  : mask =0: input '1' =high / mask =1: input '0' =high
   IN_5_7 : BOOL ;  //I 5.7  : mask =0: input '1' =high / mask =1: input '0' =high
   IN_6_0 : BOOL ;  //I 6.0  : mask =0: input '1' =high / mask =1: input '0' =high
   IN_6_1 : BOOL ;  //I 6.1  : mask =0: input '1' =high / mask =1: input '0' =high
   IN_6_2 : BOOL ;  //I 6.2  : mask =0: input '1' =high / mask =1: input '0' =high
   IN_6_3 : BOOL ;  //I 6.3  : mask =0: input '1' =high / mask =1: input '0' =high
   IN_6_4 : BOOL ;  //I 6.4  : mask =0: input '1' =high / mask =1: input '0' =high
   IN_6_5 : BOOL ;  //I 6.5  : mask =0: input '1' =high / mask =1: input '0' =high
   IN_6_6 : BOOL ;  //I 6.6  : mask =0: input '1' =high / mask =1: input '0' =high
   IN_6_7 : BOOL ;  //I 6.7  : mask =0: input '1' =high / mask =1: input '0' =high
   IN_7_0 : BOOL ;  //I 7.0  : mask =0: input '1' =high / mask =1: input '0' =high
   IN_7_1 : BOOL ;  //I 7.1  : mask =0: input '1' =high / mask =1: input '0' =high
   IN_7_2 : BOOL ;  //I 7.2  : mask =0: input '1' =high / mask =1: input '0' =high
   IN_7_3 : BOOL ;  //I 7.3  : mask =0: input '1' =high / mask =1: input '0' =high
   IN_7_4 : BOOL ;  //I 7.4  : mask =0: input '1' =high / mask =1: input '0' =high
   IN_7_5 : BOOL ;  //I 7.5  : mask =0: input '1' =high / mask =1: input '0' =high
   IN_7_6 : BOOL ;  //I 7.6  : mask =0: input '1' =high / mask =1: input '0' =high
   IN_7_7 : BOOL ;  //I 7.7  : mask =0: input '1' =high / mask =1: input '0' =high
   IN_8_0 : BOOL ;  //I 8.0  : mask =0: input '1' =high / mask =1: input '0' =high
   IN_8_1 : BOOL ;  //I 8.1  : mask =0: input '1' =high / mask =1: input '0' =high
   IN_8_2 : BOOL ;  //I 8.2  : mask =0: input '1' =high / mask =1: input '0' =high
   IN_8_3 : BOOL ;  //I 8.3  : mask =0: input '1' =high / mask =1: input '0' =high
   IN_8_4 : BOOL ;  //I 8.4  : mask =0: input '1' =high / mask =1: input '0' =high
   IN_8_5 : BOOL ;  //I 8.5  : mask =0: input '1' =high / mask =1: input '0' =high
   IN_8_6 : BOOL ;  //I 8.6  : mask =0: input '1' =high / mask =1: input '0' =high
   IN_8_7 : BOOL ;  //I 8.7  : mask =0: input '1' =high / mask =1: input '0' =high
   IN_9_0 : BOOL ;  //I 9.0  : mask =0: input '1' =high / mask =1: input '0' =high
   IN_9_1 : BOOL ;  //I 9.1  : mask =0: input '1' =high / mask =1: input '0' =high
   IN_9_2 : BOOL ;  //I 9.2  : mask =0: input '1' =high / mask =1: input '0' =high
   IN_9_3 : BOOL ;  //I 9.3  : mask =0: input '1' =high / mask =1: input '0' =high
   IN_9_4 : BOOL ;  //I 9.4  : mask =0: input '1' =high / mask =1: input '0' =high
   IN_9_5 : BOOL ;  //I 9.5  : mask =0: input '1' =high / mask =1: input '0' =high
   IN_9_6 : BOOL ;  //I 9.6  : mask =0: input '1' =high / mask =1: input '0' =high
   IN_9_7 : BOOL ;  //I 9.7  : mask =0: input '1' =high / mask =1: input '0' =high
   OUT_0_0 : BOOL ; //O 0.0  : mask =0: output '1' =high / mask =1: output '0' =high
   OUT_0_1 : BOOL ; //O 0.1  : mask =0: output '1' =high / mask =1: output '0' =high
   OUT_0_2 : BOOL ; //O 0.2  : mask =0: output '1' =high / mask =1: output '0' =high
   OUT_0_3 : BOOL ; //O 0.3  : mask =0: output '1' =high / mask =1: output '0' =high
   OUT_0_4 : BOOL ; //O 0.4  : mask =0: output '1' =high / mask =1: output '0' =high
   OUT_0_5 : BOOL ; //O 0.5  : mask =0: output '1' =high / mask =1: output '0' =high
   OUT_0_6 : BOOL ; //O 0.6  : mask =0: output '1' =high / mask =1: output '0' =high
   OUT_0_7 : BOOL ; //O 0.7  : mask =0: output '1' =high / mask =1: output '0' =high
   OUT_1_0 : BOOL ; //O 1.0  : mask =0: output '1' =high / mask =1: output '0' =high
   OUT_1_1 : BOOL ; //O 1.1  : mask =0: output '1' =high / mask =1: output '0' =high
   OUT_1_2 : BOOL ; //O 1.2  : mask =0: output '1' =high / mask =1: output '0' =high
   OUT_1_3 : BOOL ; //O 1.3  : mask =0: output '1' =high / mask =1: output '0' =high
   OUT_1_4 : BOOL ; //O 1.4  : mask =0: output '1' =high / mask =1: output '0' =high
   OUT_1_5 : BOOL ; //O 1.5  : mask =0: output '1' =high / mask =1: output '0' =high
   OUT_1_6 : BOOL ; //O 1.6  : mask =0: output '1' =high / mask =1: output '0' =high
   OUT_1_7 : BOOL ; //O 1.7  : mask =0: output '1' =high / mask =1: output '0' =high
   OUT_2_0 : BOOL ; //O 2.0  : mask =0: output '1' =high / mask =1: output '0' =high
   OUT_2_1 : BOOL ; //O 2.1  : mask =0: output '1' =high / mask =1: output '0' =high
   OUT_2_2 : BOOL ; //O 2.2  : mask =0: output '1' =high / mask =1: output '0' =high
   OUT_2_3 : BOOL ; //O 2.3  : mask =0: output '1' =high / mask =1: output '0' =high
   OUT_2_4 : BOOL ; //O 2.4  : mask =0: output '1' =high / mask =1: output '0' =high
   OUT_2_5 : BOOL ; //O 2.5  : mask =0: output '1' =high / mask =1: output '0' =high
   OUT_2_6 : BOOL ; //O 2.6  : mask =0: output '1' =high / mask =1: output '0' =high
   OUT_2_7 : BOOL ; //O 2.7  : mask =0: output '1' =high / mask =1: output '0' =high
   OUT_3_0 : BOOL ; //O 3.0  : mask =0: output '1' =high / mask =1: output '0' =high
   OUT_3_1 : BOOL ; //O 3.1  : mask =0: output '1' =high / mask =1: output '0' =high
   OUT_3_2 : BOOL ; //O 3.2  : mask =0: output '1' =high / mask =1: output '0' =high
   OUT_3_3 : BOOL ; //O 3.3  : mask =0: output '1' =high / mask =1: output '0' =high
   OUT_3_4 : BOOL ; //O 3.4  : mask =0: output '1' =high / mask =1: output '0' =high
   OUT_3_5 : BOOL ; //O 3.5  : mask =0: output '1' =high / mask =1: output '0' =high
   OUT_3_6 : BOOL ; //O 3.6  : mask =0: output '1' =high / mask =1: output '0' =high
   OUT_3_7 : BOOL ; //O 3.7  : mask =0: output '1' =high / mask =1: output '0' =high
   p_TStopMonit : INT  := 600;  //Monitoring time for DG standstill after stop command [0.1s]
   p_Rel_DieselContr : INT  := 5;   //Pulse time for release of diesel engine controller [0.1s]
   p_NoLoadRun : BOOL  := TRUE; //Running without load before stopping the engine (DG) (0= No, 1= Yes)
   p_GenBrk_LoadRed : BOOL  := TRUE;    //Open. of the gen. breaker in semi OP with load reduction (0=without, 1=with)
   p_LoadRed_Auto : BOOL  := TRUE;  //Unloading of gen. set in semi OP before open. of gen. breaker (0=man., 1=auto)
   p_PrelubOil_Blocking : BOOL ;    //"Low prelub oil pressure" is blocking criterion (0=no blocking, 1=blocking)
   p_PrelubOil_Blackout : BOOL ;    //Blocking by "Low prelub oil pressure" in case of blackout (0=no, 1=yes)
   p_NoUndS_SGonly : BOOL ; //No underload shutdown if this diesel the only one in addition to the SG
   p_StpShC_semi : BOOL  := TRUE;   //Stop Diesel from shore connection in semi also
   p_StpShC_loadRed : BOOL ;    //Stop Diesel with deloading
   p_Rel_WBrk_StartV : BOOL  := TRUE;   //Release of start valve wire break monitoring [0=no monit., 1=monit.]
   p_Rel_WBrk_StopV : BOOL  := TRUE;    //Release of stop valve wire break monitoring [0=no monit., 1=monit.]
   p_Rel_WBrk_EmStopV : BOOL  := TRUE;  //Release of emergency stop valve wire break monitoring [0=no monit., 1=monit.]
   p_Rel_WBrk_SuppressV : BOOL ;    //Release of suppression valve wire break monitoring [0=no monit., 1=monit.]
   p_local_remote : BOOL ;    //Local remote switch [=0: only Local switch / =1: Local and remote switch]
   p_BrkOpnShC : BOOL  := TRUE; //Only breaker open instead of diesel stop if shore connection is closed
   p_noLocalSwtch : BOOL ;  //No local switch, start/stop diesel in parallel to OP [=1: yes]
   p_MonitPrelubPress : BOOL  := TRUE;  //Monitoring of prelubricat. oil press. for diesel start [0=no monit., 1=monit.]
   p_Tstart : INT  := 50;   //Starting time DG [0.1s]
   p_Tpause : INT  := 150;  //Pausing time between two start attempts [0.1s]
   p_Tstop : INT  := 400;   //Stopping time DG after "Ignition speed" has disappeared [0.1s]
   p_TsuppValve : INT  := 100;  //Delay time for suppression valve [0.1s]
   p_NoStartAtte : BYTE  := B#16#3; //Number of start attempts  [Minimum: 1]
   p_NoPreLub_Blackout : BOOL  := TRUE; //No prelubrication in case of blackout [1=no prelubrication]
   p_DlyStpNoCool : BOOL  := TRUE;  //No cool down in case of a delayed shutdown
   var912 : BOOL ;
   var913 : BOOL ;
   var914 : BOOL ;
   var915 : BOOL ;
   var916 : BOOL ;
   var917 : BOOL ;
   p_TnoLoadRun : INT  := 1800; //Time for running without load before stopping the engine [0.1s]
   p_PreLubKind : BYTE ;    //Prelubrication (0=No, 1=Contin., 2=Cyclic, 3=Cyclic+bef. start, 4=Before start)
   p_PreLubAct : BYTE  := B#16#3;   //Prelubrication (0=No prelubr., 1=In standby only, 2=In auto, 3=In auto+semi)
   p_TpreLub1 : INT  := 5;  //Cyclic prelubrication: Prelubrication time [s]
   p_TpreLub2 : INT  := 10; //Cyclic prelubrication: Pausing time [s]
   p_TpreLub3 : INT  := 300;    //Prelubrication before start: Prelubrication time [s]
   p_TpreLub4 : INT  := 3000;   //Prelubrication before start: Max. time for start without prelubrication [s]
   p_PreHeatAct : BYTE ;    //Preheating (0=No preheating, 1=In standby only, 2=In auto, 3=In auto+semi)
   var92 : BYTE ;   //Spare
   p_SloTurnKind : BYTE ;   //Slow turn (0=No, 2=Cyclic, 3=Cyclic+bef.start, 4=Before start, 5=After prelub.)
   p_SlowTurnAct : BYTE ;   //Slow turn (0=No slow turn, 1=In standby only, 2=In auto, 3=In auto+semi)
   p_VoltMiss : INT  := 50; //Delay time alarm "voltage missing" [0.1s]
   var93 : INT ;
   p_TslowTurn3 : INT ; //Slow turn before start: Slow turn time [s]
   p_TslowTurn4 : INT ; //Slow turn before start: Max. time for start without slow turn [s]
   p_TSDDelay : INT  := 600;    //Waiting time bef. undel. shutdown, if delayed shutdown did not work [0.1s]
   p_TPrelub_Block : INT  := 3000;  //Waiting time before start blocking because of "Low prelub oil pressure" [0.1s]
   var950 : BOOL ;
   p_GenBrk_LoadRed_SG : BOOL ; //Open. of the gen. breaker in semi OP with load reduct. SG (0=without, 1=with)
   p_LoadRed_Auto_SG : BOOL ;   //Unloading of SG in semi OP before opening of gen. breaker (0=man., 1=auto)
   var953 : BOOL ;
   var954 : BOOL ;
   var955 : BOOL ;
   var956 : BOOL ;
   var957 : BYTE ;
   p_TStart_Comm_SG : INT  := 10;   //Pulse duration of start command for SG [0.1s]
   p_TStartFail_SG : INT  := 1200;  //Waiting time before start failure of SG [0.1s]
   p_TStop_SG : INT  := 200;    //Stopping time SG after "Gen. voltage" has disappeared [0.1s]
   p_TStop_Comm_SG : INT  := 10;    //Pulse duration of stop command for SG [0.1s]
   p_TSDDelay_SG : INT  := 600; //Waiting time bef. undel. shutdown, if delayed shutdown did not work [0.1s]
   p_Tmonit1_SG : INT  := 150;  //Monitoring time 1 SG [0.1s]
   var102 : INT ;
   var103 : INT ;
   var104 : BYTE ;
   var1041 : BOOL ;
   p_SD_StdbySt2_SG : BOOL ;    //2nd standby set to be started in case of shaft generator shutdown (0=no, 1=yes)
   var10412 : BOOL ;
   var10413 : BOOL ;
   var10414 : BOOL ;
   var10415 : BOOL ;
   var10416 : BOOL ;
   var10417 : BOOL ;
   p_SD1_Used_SG : BOOL  := TRUE;   //Alarm/SD function 1 (ME slow down) used for SG [=not used, 1=used]
   p_SD2_Used_SG : BOOL  := TRUE;   //Alarm/SD function 2 (ME shut down) used for SG [=not used, 1=used]
   p_SD3_Used_SG : BOOL  := TRUE;   //Alarm/SD function 3 (DG request from SG) used for SG [=not used, 1=used]
   p_SD4_Used_SG : BOOL  := TRUE;   //Alarm/SD function 4 (SG delayed SD) used for SG [=not used, 1=used]
   p_SD5_Used_SG : BOOL  := TRUE;   //Alarm/SD function 5 (SG undelayed SD) used for SG [=not used, 1=used]
   p_SD6_Used_SG : BOOL  := TRUE;   //Alarm/SD function 6 (ET < min.) used for SG [=not used, 1=used]
   p_SD7_Used_SG : BOOL ;   //Alarm/SD function 7 (spare) used for SG [=not used, 1=used]
   p_SD8_Used_SG : BOOL ;   //Alarm/SD function 8 (spare) used for SG [=not used, 1=used]
   p_SD1_Delay_SG : BOOL  := TRUE;  //Alarm/SD 1 for SG delayed or undelayed [0=undel., 1=delayed]
   p_SD2_Delay_SG : BOOL  := TRUE;  //Alarm/SD 2 for SG delayed or undelayed [0=undel., 1=delayed]
   p_SD3_Delay_SG : BOOL ;  //Alarm 3 for SG (Bit not used, no shutdown, only standby request)
   p_SD4_Delay_SG : BOOL  := TRUE;  //Alarm/SD 4 for SG delayed or undelayed [0=undel., 1=delayed]
   p_SD5_Delay_SG : BOOL ;  //Alarm/SD 5 for SG delayed or undelayed [0=undel., 1=delayed]
   p_SD6_Delay_SG : BOOL  := TRUE;  //Alarm/SD 6 for SG delayed or undelayed [0=undel., 1=delayed]
   p_SD7_Delay_SG : BOOL  := TRUE;  //Alarm/SD 7 for SG delayed or undelayed [0=undel., 1=delayed]
   p_SD8_Delay_SG : BOOL ;  //Alarm/SD 8 for SG delayed or undelayed [0=undel., 1=delayed]
   p_TSD1_SG : INT  := 10;  //Stabilization time for SG shutdown No. 1 [0.1s], ME slow down
   p_TSD2_SG : INT  := 10;  //Stabilization time for SG shutdown No. 2 [0.1s], ME shutdown
   p_TSD3_SG : INT  := 10;  //Stabilization time for SG shutdown No. 3 [0.1s], Standby DG request from SG
   p_TSD4_SG : INT  := 10;  //Stabilization time for SG shutdown No. 4 [0.1s], SG delayed shutdown
   p_TSD5_SG : INT  := 10;  //Stabilization time for SG shutdown No. 5 [0.1s], SG undelayed shutdown
   p_TSD6_SG : INT  := 10;  //Stabilization time for SG shutdown No. 6 [0.1s], ET < min.
   p_TSD7_SG : INT  := 10;  //Stabilization time for SG shutdown No. 7 [0.1s], spare
   p_TSD8_SG : INT  := 10;  //Stabilization time for SG shutdown No. 8 [0.1s], spare
   var107 : INT ;
   p_PgenBrkPMin : INT  := 500;   //Reference value for generator breaker OFF after load reduction [0.01%]
   p_Monit_BrkReady : BOOL  := TRUE;    //Monitoring of signal "Generator breaker ready"  (0=No monit., 1=Monitor.)
   P_Monit_BrkPosNorm : BOOL  := TRUE;  //Monitoring of signal "Generator breaker in norm position" (0=No monit, 1=Monit)
   p_Monit_BrkPosTest : BOOL  := TRUE;  //Monitoring of signal "Generator breaker in test position" (0=No monit, 1=Monit)
   p_noBrkOffSign : BOOL ;  //OPTION: Signal "Generator breaker off" not available (=1), (=0: available)
   p_GenBrk_ShoreBlock : BOOL  := TRUE; //Gen. breaker blocked by shore conn. (no synchron.) (0=No blocking, 1=Blocking)
   p_GenBrk_OUTviaGENOP : BOOL  := TRUE;    //Command "Generator breaker OFF" via GENOP [0=OFF-->DO,1=OFF-->DO+GENOP]
   p_BlockMonitBrkTrip : BOOL  := TRUE; //Blocking of monitoring of signal "Generator breaker tripped" (0=monit./1=block)
   p_noBrkONSign : BOOL  := TRUE;   //OPTION: Signal "Generator breaker on" not available (=1), (=0: available)
   p_GenBrk_Type : BYTE ;  //Type of generator breaker (=0: 3WN6, =1: 3WN1, =2: 3VF)
   p_TgenBrkReady : INT  := 50; //Waiting time for failure signal "Generator breaker not ready" [0.1s]
   p_TgenBrkSimOn : INT  := 1;  //Waiting time for gen. breaker ON comm. after rel. from simult.locking [0.1s]
   p_TgenBrkRel : INT  := 50;   //Waiting time after run-up bef. request to simult.locking/synchroniz. [0.1s]
   P_TgenBrkSyn : INT  := 600;  //Monitoring time for synchronizing of generator breaker [0.1s]
   p_TgenBrkLoadOff : INT  := 3000; //Delay time before gen. breaker OFF, if load reduction did not work [0.1s]
   p_TgenBrkTrip : INT  := 1;   //Waiting time for failure signal "Generator breaker tripped" [0.1s]
   p_TgenBrkOn : INT  := 10;    //Pulse time for generator breaker ON command [0.1s]
   p_TgenBrkOff : INT  := 40;   //Pulse time for generator breaker OFF command [0.1s]
   p_TgenBrkFbOn : INT  := 10;  //Monitoring time for feedback signal "Generator breaker ON" [0.1s]
   p_TgenBrkFbOff : INT  := 10; //Monitoring time for feedback signal "Generator breaker OFF" [0.1s]
   p_TgenBrkFbOffOn : INT  := 20;   //Waiting time for plausibility control feedback "Gen. breaker OFF/ON" [0.1s]
   p_GBprepExpShore : BOOL ;    //Generatorbreaker ready for close in case of shore conn. on and export mode
   var1152 : BOOL ;
   var1153 : BOOL ;
   var1154 : BOOL ;
   var1155 : BOOL ;
   var1156 : BOOL ;
   var1157 : BOOL ;
   var1158 : BOOL ;
   p_Prtc_uness1_lock : BOOL ;  //Blocked unessential consumer I off
   p_Prtc_uness2_lock : BOOL ;  //Blocked unessential consumer II off
   p_Prtc_uness3_lock : BOOL ;  //Blocked unessential consumer III off
   var1733 : BOOL ;
   var1734 : BOOL ;
   var1735 : BOOL ;
   var1736 : BOOL ;
   var1737 : BOOL ;
   p_dlyT_SC : S5TIME ; //Delayed short circuit signal
   p_Prtc_i1lock : BOOL ;   //Overcurrent 1st limit blocked (GENOP71)
   p_Prtc_i2lock : BOOL ;   //Overcurrent 2nd limit blocked (GENOP71)
   p_Prtc_i3lock : BOOL ;   //Overcurrent 3th limit blocked (GENOP71)
   p_Prtc_i4lock : BOOL ;    //Overcurrent 4th limit blocked (GENOP71)
   p_Prtc_Plock : BOOL ;    //Reverse power blocked (GENOP71)
   p_Prtc_Sclock : BOOL ;   //Short circuit blocked (GENOP71)
   p_UBL_ShdPos : BOOL  := TRUE;    //No Shutdown because of underload possible in case of UBL mode (=1)
   var118 : BOOL ;
   var119 : BYTE ;
   var120 : BYTE ;
   p_Prtct_i_1_Active : BOOL  := TRUE;  //Generator current limit 1 monitoring active [1=active]
   p_Prtct_i_2_Active : BOOL  := TRUE;  //Generator current limit 2 monitoring active [1=active]
   p_Prtct_i_3_Active : BOOL ;  //Generator current limit 3 monitoring active [not connected]
   p_Prtct_i_4_Active : BOOL ;  //Generator current limit 4 monitoring active [not connected]
   p_Prtct_i_5_Active : BOOL ;  //Generator current limit 5 monitoring active [not connected]
   p_Prtct_i_6_Active : BOOL ;  //Generator current limit 6 monitoring active [not connected]
   p_Prtct_i_7_Active : BOOL ;  //Generator current limit 7 monitoring active [1=active]
   var1201 : BOOL ;
   var121 : BYTE ;
   p_Prtct_P_1_Active : BOOL  := TRUE;  //Generator load limit 1 monitoring active [1=active]
   p_Prtct_P_2_Active : BOOL  := TRUE;  //Generator load limit 2 monitoring active [1=active]
   p_Prtct_P_3_Active : BOOL  := TRUE;  //Generator load limit 3 monitoring active [1=active]
   p_Prtct_P_4_Active : BOOL  := TRUE;  //Generator load limit 4 monitoring active [1=active]
   p_Prtct_P_5_Active : BOOL  := TRUE;  //Generator load limit 5 monitoring active [1=active]
   p_Prtct_P_6_Active : BOOL  := TRUE;  //Generator load limit 6 monitoring active [1=active]
   p_Prtct_P_7_Active : BOOL ;  //Generator load limit 7 monitoring active [1=active]
   p_Prtct_P_8_Active : BOOL ;  //Generator load limit 8 monitoring active [not connected]
   var122 : BYTE ;
   p_Prtct_f_1_Active : BOOL  := TRUE;  //Busbar frequency limit 1 monitoring active [1=active]
   p_Prtct_f_2_Active : BOOL  := TRUE;  //Busbar frequency limit 2 monitoring active [1=active]
   p_Prtct_f_3_Active : BOOL  := TRUE;  //Busbar frequency limit 3 monitoring active [1=active]
   p_Prtct_f_4_Active : BOOL  := TRUE;  //Busbar frequency limit 4 monitoring active [1=active]
   p_Prtct_f_5_Active : BOOL  := TRUE;  //Busbar frequency limit 5 monitoring active [1=active]
   p_Prtct_f_6_Active : BOOL  := TRUE;  //Busbar frequency limit 6 monitoring active [1=active]
   p_Prtct_f_7_Active : BOOL  := TRUE;  //Busbar frequency limit 7 monitoring active [1=active]
   p_Prtct_f_8_Active : BOOL  := TRUE;  //Busbar frequency limit 8 monitoring active [1=active]
   var123 : BYTE ;
   p_Prtct_V_1_Active : BOOL  := TRUE;  //Busbar voltage limit 1 monitoring active [1=active]
   p_Prtct_V_2_Active : BOOL  := TRUE;  //Busbar voltage limit 2 monitoring active [1=active]
   p_Prtct_V_3_Active : BOOL  := TRUE;  //Busbar voltage limit 3 monitoring active [1=active]
   p_Prtct_V_4_Active : BOOL  := TRUE;  //Busbar voltage limit 4 monitoring active [1=active]
   var1231 : BOOL ;
   var1232 : BOOL ;
   var1233 : BOOL ;
   var1234 : BOOL ;
   p_Prtct_i_1L : INT  := 9500;   //Generator current limit 1 [0.01% of nominal value]
   p_Prtct_i_1T : S5TIME  := S5T#30S;   //Generator current limit 1, delay time  [0.1s]
   p_Prtct_i_1H : INT  := 200;  //Generator current limit 1, hysteresis  [0.01%]
   p_Prtct_i_2L : INT  := 10000;    //Generator current limit 2 [0.01% of nominal value]
   p_Prtct_i_2T : S5TIME  := S5T#5S;    //Generator current limit 2, delay time  [0.1s]
   p_Prtct_i_2H : INT  := 200;  //Generator current limit 2, hysteresis  [0.01%]
   p_Prtct_i_3L : INT  := 10000;    //Generator current limit 3 [0.01% of nominal value]
   p_Prtct_i_3T : S5TIME  := S5T#5S;    //Generator current limit 3, delay time  [0.1s]
   p_Prtct_i_3H : INT  := 200;  //Generator current limit 3, hysteresis  [0.01%]
   p_Prtct_i_4L : INT  := 10000;    //Generator current limit 4 [0.01% of nominal value]
   p_Prtct_i_4T : S5TIME  := S5T#10S;   //Generator current limit 4, delay time  [0.1s]
   p_Prtct_i_4H : INT  := 200;  //Generator current limit 4, hysteresis  [0.01%]
   p_Prtct_i_5L : INT  := 10000;  //Generator current limit 5 [0.01% of nominal value]
   p_Prtct_i_5T : S5TIME  := S5T#15S;   //Generator current limit 5, delay time  [0.1s]
   p_Prtct_i_5H : INT  := 200;  //Generator current limit 5, hysteresis  [0.01%]
   p_Prtct_i_6L : INT  := 12000;    //Generator current limit 6 [0.01% of nominal value]
   p_Prtct_i_6T : S5TIME  := S5T#1S;    //Generator current limit 6, delay time  [0.1s]
   p_Prtct_i_6H : INT  := 200;  //Generator current limit 6, hysteresis  [0.01%]
   p_Prtct_i_7L : INT  := 16500;    //Generator current limit 7 [0.01% of nominal value]
   p_Prtct_i_7T : S5TIME  := S5T#30S;   //Generator current limit 7, delay time  [0.1s]
   p_Prtct_i_7H : INT  := 200;  //Generator current limit 7, hysteresis  [0.01%]
   p_Prtct_P_1L : INT  := 9500; //Generator load limit 1 [0.01% of nominal value]
   p_Prtct_P_1T : S5TIME  := S5T#30S;   //Generator load limit 1, delay time  [0.1s]
   p_Prtct_P_1H : INT  := 200;  //Generator load limit 1, hysteresis  [0.01%]
   p_Prtct_P_2L : INT  := 10500; //Generator load limit 2 [0.01% of nominal value]
   p_Prtct_P_2T : S5TIME  := S5T#5S;    //Generator load limit 2, delay time  [0.1s]
   p_Prtct_P_2H : INT  := 200;  //Generator load limit 2, hysteresis  [0.01%]
   p_Prtct_P_3L : INT  := 10500;    //Generator load limit 3 [0.01% of nominal value]
   p_Prtct_P_3T : S5TIME  := S5T#5S;    //Generator load limit 3, delay time  [0.1s]
   p_Prtct_P_3H : INT  := 200;  //Generator load limit 3, hysteresis  [0.01%]
   p_Prtct_P_4L : INT  := 10500;    //Generator load limit 4 [0.01% of nominal value]
   p_Prtct_P_4T : S5TIME  := S5T#10S;   //Generator load limit 4, delay time  [0.1s]
   p_Prtct_P_4H : INT  := 200;  //Generator load limit 4, hysteresis  [0.01%]
   p_Prtct_P_5L : INT  := 10500;    //Generator load limit 5 [0.01% of nominal value]
   p_Prtct_P_5T : S5TIME  := S5T#15S;   //Generator load limit 5, delay time  [0.1s]
   p_Prtct_P_5H : INT  := 200;  //Generator load limit 5, hysteresis  [0.01%]
   p_Prtct_P_6L : INT  := 11000;    //Generator load limit 6 [0.01% of nominal value]
   p_Prtct_P_6T : S5TIME  := S5T#1S;    //Generator load limit 6, delay time  [0.1s]
   p_Prtct_P_6H : INT  := 200;  //Generator load limit 6, hysteresis  [0.01%]
   p_Prtct_P_7L : INT  := -1000;    //Generator load limit 7 [0.01% of nominal value]
   p_Prtct_P_7T : S5TIME  := S5T#6S;    //Generator load limit 7, delay time  [0.1s]
   p_Prtct_P_7H : INT  := 200;  //Generator load limit 7, hysteresis  [0.01%]
   p_Prtct_f_1L : INT  := 9750; //Busbar frequency limit 1 [0.01% of nominal value]
   p_Prtct_f_1T : S5TIME  := S5T#1M;    //Busbar frequency limit 1, delay time  [0.1s]
   p_Prtct_f_1H : INT  := 40;   //Busbar frequency limit 1, hysteresis  [0.01%]
   p_Prtct_f_2L : INT  := 9500; //Busbar frequency limit 2 [0.01% of nominal value]
   p_Prtct_f_2T : S5TIME  := S5T#8S;    //Busbar frequency limit 2, delay time  [0.1s]
   p_Prtct_f_2H : INT  := 40;   //Busbar frequency limit 2, hysteresis  [0.01%]
   p_Prtct_f_3L : INT  := 9500; //Busbar frequency limit 3 [0.01% of nominal value]
   p_Prtct_f_3T : S5TIME  := S5T#6S;   //Busbar frequency limit 3, delay time  [0.1s]
   p_Prtct_f_3H : INT  := 40;   //Busbar frequency limit 3, hysteresis  [0.01%]
   p_Prtct_f_4L : INT  := 9500; //Busbar frequency limit 4 [0.01% of nominal value]
   p_Prtct_f_4T : S5TIME  := S5T#10S;   //Busbar frequency limit 4, delay time  [0.1s]
   p_Prtct_f_4H : INT  := 40;   //Busbar frequency limit 4, hysteresis  [0.01%]
   p_Prtct_f_5L : INT  := 9500; //Busbar frequency limit 5 [0.01% of nominal value]
   p_Prtct_f_5T : S5TIME  := S5T#15S;   //Busbar frequency limit 5, delay time  [0.1s]
   p_Prtct_f_5H : INT  := 40;   //Busbar frequency limit 5, hysteresis  [0.01%]
   p_Prtct_f_6L : INT  := 9000; //Busbar frequency limit 6 [0.01% of nominal value]
   p_Prtct_f_6T : S5TIME  := S5T#1S;    //Busbar frequency limit 6, delay time  [0.1s]
   p_Prtct_f_6H : INT  := 40;   //Busbar frequency limit 6, hysteresis  [0.01%]
   p_Prtct_f_7L : INT  := 9000; //Busbar frequency limit 7 [0.01% of nominal value]
   p_Prtct_f_7T : S5TIME  := S5T#15S;   //Busbar frequency limit 7, delay time  [0.1s]
   p_Prtct_f_7H : INT  := 40;   //Busbar frequency limit 7, hysteresis  [0.01%]
   p_Prtct_f_8L : INT  := 10500;    //Busbar frequency limit 8 [0.01% of nominal value]
   p_Prtct_f_8T : S5TIME  := S5T#2S;    //Busbar frequency limit 8, delay time  [0.1s]
   p_Prtct_f_8H : INT  := 40;   //Busbar frequency limit 8, hysteresis  [0.01%]
   p_Prtct_V_1L : INT  := 9000; //Busbar voltage limit 1 [0.01% of nominal value]
   p_Prtct_V_1T : S5TIME  := S5T#5S;    //Busbar voltage limit 1, delay time  [0.1s]
   p_Prtct_V_1H : INT  := 150;  //Busbar voltage limit 1, hysteresis  [0.01%]
   p_Prtct_V_2L : INT  := 6875; //Busbar voltage limit 2 [0.01% of nominal value]
   p_Prtct_V_2T : S5TIME  := S5T#1S;    //Busbar voltage limit 2, delay time  [0.1s]
   p_Prtct_V_2H : INT  := 150;  //Busbar voltage limit 2, hysteresis  [0.01%]
   p_Prtct_V_3L : INT  := 10500;    //Busbar voltage limit 3 [0.01% of nominal value]
   p_Prtct_V_3T : S5TIME  := S5T#2S;    //Busbar voltage limit 3, delay time  [0.1s]
   p_Prtct_V_3H : INT  := 150;  //Busbar voltage limit 3, hysteresis  [0.01%]
   p_DifCurrent : INT  := 7500; //Limit for mean val. (in 0.01% of extreme value) f. current measuring fail.
   P_TFCurrent : S5TIME  := S5T#10S;    //Delay time for detecting current measuring failure
   p_Vblackout : INT  := 1500;  //Busbar voltage limit for detecting blackout (in 0.01% of nominal voltage)
   p_Tblackout : S5TIME  := S5T#1S; //Delay time for detecting blackout
   p_TFBusbar : S5TIME  := S5T#200MS;   //Delay time for detecting busbar monitoring failure
   p_VgenVolt : INT  := 8500;   //Busbar voltage limit for normal gen. functions (in 0.01% of nominal voltage)
   p_TPulse_sc : S5TIME  := S5T#5S; //Pulse time for short circuit signal to other generator set
   p_Underload_1 : INT  := 3500;    //Generator underload, limit 1 [0.01%], 2 gen. sets in load sharing mode
   p_Underload_2 : INT  := 4500;    //Generator underload, limit 2 [0.01%], 3 gen. sets in load sharing mode
   p_Underload_3 : INT  := 5000;    //Generator underload, limit 3 [0.01%], 4 gen. sets in load sharing mode
   p_Tunderl_Ind : S5TIME  := S5T#30S;  //Automatic underload shut down, delay time for annunciation [0.1s]
   p_Tunderl_Shd : S5TIME  := S5T#1M;   //Automatic underload shut down, delay time for shutdown [0.1s]
   p_Underload_H : INT  := 200; //Generator underload, hysteresis [0.01%] (actually not used)
   p_Underl_Rel : BOOL  := TRUE;    //Release of automatic underload shutdown
   p_ShD_Overcurr : BOOL ;  //DG/SG/EG stop command in case of "Gen. breaker trip by overcurrent"
   p_ShD_RevPower : BOOL ;  //DG/SG/EG stop command in case of "Gen. breaker trip by reverse power"
   p_ShD_Underfrequ : BOOL  := TRUE;    //DG/SG/EG stop command in case of "Gen. breaker trip by underfrequency"
   p_ShD_Undervolt : BOOL  := TRUE; //DG/SG/EG stop command in case of "Gen. breaker trip by undervoltage"
   p_Blackout_StdbySt2 : BOOL ; //2nd standby set to be started in case of blackout (0=no, 1=yes)
   p_ShortCirc_Block : BOOL ;   //Blocking after short circuit of other gen. set (0=after 1st, 1=after 2nd sh.c.)
   p_SC_Device_Avail : BOOL ;   //Short circuit tripping device in the generator breaker available (0=No, 1=Yes)
   p_ChOver_BlOut_f2 : BOOL ;   //Change over to new started set via blackout in case of busbar frequency limit 2
   p_ChOver_BlOut_f6 : BOOL  := TRUE;   //Change over to new started set via blackout in case of busbar frequency limit 6
   p_ChOver_BlOut_U1 : BOOL  := TRUE;   //Change over to new started set via blackout in case of busbar voltage limit 1
   p_ChOver_BlOut_U3 : BOOL  := TRUE;   //Change over to new started set via blackout in case of busbar voltage limit 3
   var1304 : BOOL ;
   var1305 : BOOL ;
   var1306 : BOOL ;
   p_DiffProt_Avail : BOOL ;    //Differential protection available (0=No, 1=Yes)
   var130a : BYTE ;
   p_Rel_WBrk_SD1 : BOOL ;  //Release of wire break monitoring for SD1 [0=no monit., 1=monit.]
   p_Rel_WBrk_SD2 : BOOL ;  //Release of wire break monitoring for SD2 [0=no monit., 1=monit.]
   p_Rel_WBrk_SD3 : BOOL ;  //Release of wire break monitoring for SD3 [0=no monit., 1=monit.]
   p_Rel_WBrk_SD4 : BOOL ;  //Release of wire break monitoring for SD4 [0=no monit., 1=monit.]
   p_Rel_WBrk_SD5 : BOOL ;  //Release of wire break monitoring for SD5 [0=no monit., 1=monit.]
   p_Rel_WBrk_SD6 : BOOL ;  //Release of wire break monitoring for SD6 [0=no monit., 1=monit.]
   p_Rel_WBrk_SD7 : BOOL ;  //Release of wire break monitoring for SD7 [0=no monit., 1=monit.]
   p_Rel_WBrk_SD8 : BOOL ;  //Release of wire break monitoring for SD8 [0=no monit., 1=monit.]
   p_Prealarm : BOOL ;  //Function of "Prealarm" (0=Set will be stopped, 1=Set will remain running)
   p_SD_StdbySt2 : BOOL ;   //2nd standby set to be started in case of diesel engine shutdown (0=no, 1=yes)
   p_Sensor_SD2 : BOOL  := TRUE;    //Sensor monitoring for shutdown channel 2 (Low lub oil pressure)[0=no, 1=yes]
   p_GenBrkOff_OvSpeed : BOOL ; //Gen. breaker Off command after overspeed signal has disappeared [0=no, 1=yes]
   p_EmergStp_OvSpeed : BOOL  := TRUE;  //Valve 'emergency stop' is active in case of overspeed only [0=no, 1=yes]
   p_noStpCmd_SD2 : BOOL ;  //Shutdown channel 2 is allways valid, also without stop command [0=no, 1=yes]
   p_BlackExp_Alrm : BOOL ; //Alarm"Blackout expecting" if delayed stop on the last diesel active [1=yes]
   var129 : BOOL ;
   p_SD1_Used_DG : BOOL  := TRUE;   //Shutdown function 1 for DG used [0=not used, 1=used]
   p_SD2_Used_DG : BOOL  := TRUE;   //Shutdown function 2 for DG used [0=not used, 1=used]
   p_SD3_Used_DG : BOOL  := TRUE;   //Shutdown function 3 for DG used [0=not used, 1=used]
   p_SD4_Used_DG : BOOL ;   //Shutdown function 4 for DG used [0=not used, 1=used]
   p_SD5_Used_DG : BOOL ;   //Shutdown function 5 for DG used [0=not used, 1=used]
   p_SD6_Used_DG : BOOL ;   //Shutdown function 6 for DG used [0=not used, 1=used]
   p_SD7_Used_DG : BOOL ;   //Shutdown function 7 for DG used [0=not used, 1=used]
   p_SD8_Used_DG : BOOL ;   //Shutdown function 8 for DG used [0=not used, 1=used]
   p_SD1_Delay_DG : BOOL ;  //Shutdown 1 for DG delayed or undelayed [0=undelayed, 1=delayed]
   p_SD2_Delay_DG : BOOL ;  //Shutdown 2 for DG delayed or undelayed [0=undelayed, 1=delayed]
   p_SD3_Delay_DG : BOOL  := TRUE;  //Shutdown 3 for DG delayed or undelayed [0=undelayed, 1=delayed]
   p_SD4_Delay_DG : BOOL ;  //Shutdown 4 for DG delayed or undelayed [0=undelayed, 1=delayed]
   p_SD5_Delay_DG : BOOL ;  //Shutdown 5 for DG delayed or undelayed [0=undelayed, 1=delayed]
   p_SD6_Delay_DG : BOOL ;  //Shutdown 6 for DG delayed or undelayed [0=undelayed, 1=delayed]
   p_SD7_Delay_DG : BOOL ;  //Shutdown 7 for DG delayed or undelayed [0=undelayed, 1=delayed]
   p_SD8_Delay_DG : BOOL ;  //Shutdown 8 for DG delayed or undelayed [0=undelayed, 1=delayed]
   p_SD1_Mon1_DG : BOOL ;   //Release of SD1 for DG without/with monitor. time 1 [0=without, 1=with]
   p_SD2_Mon1_DG : BOOL  := TRUE;   //Release of SD2 for DG without/with monitor. time 1 [0=without, 1=with]
   p_SD3_Mon1_DG : BOOL ;   //Release of SD3 for DG without/with monitor. time 1 [0=without, 1=with]
   p_SD4_Mon1_DG : BOOL ;   //Release of SD4 for DG without/with monitor. time 1 [0=without, 1=with]
   p_SD5_Mon1_DG : BOOL ;   //Release of SD5 for DG without/with monitor. time 1 [0=without, 1=with]
   p_SD6_Mon1_DG : BOOL ;   //Release of SD6 for DG without/with monitor. time 1 [0=without, 1=with]
   p_SD7_Mon1_DG : BOOL ;   //Release of SD7 for DG without/with monitor. time 1 [0=without, 1=with]
   p_SD8_Mon1_DG : BOOL ;   //Release of SD8 for DG without/with monitor. time 1 [0=without, 1=with]
   p_SD1_Mon2_DG : BOOL ;   //Release of SD1 for DG with monitoring time 1/1+2 [0=with t. 1, 1=with t. 2]
   p_SD2_Mon2_DG : BOOL ;   //Release of SD2 for DG with monitoring time 1/1+2 [0=with t. 1, 1=with t. 2]
   p_SD3_Mon2_DG : BOOL ;   //Release of SD3 for DG with monitoring time 1/1+2 [0=with t. 1, 1=with t. 2]
   p_SD4_Mon2_DG : BOOL ;   //Release of SD4 for DG with monitoring time 1/1+2 [0=with t. 1, 1=with t. 2]
   p_SD5_Mon2_DG : BOOL ;   //Release of SD5 for DG with monitoring time 1/1+2 [0=with t. 1, 1=with t. 2]
   p_SD6_Mon2_DG : BOOL ;   //Release of SD6 for DG with monitoring time 1/1+2 [0=with t. 1, 1=with t. 2]
   p_SD7_Mon2_DG : BOOL ;   //Release of SD7 for DG with monitoring time 1/1+2 [0=with t. 1, 1=with t. 2]
   p_SD8_Mon2_DG : BOOL ;   //Release of SD8 for DG with monitoring time 1/1+2 [0=with t. 1, 1=with t. 2]
   p_Tmonit1_DG : INT  := 150;  //Monitoring time 1 DG [0.1s]
   p_Tmonit2_DG : INT  := 50;   //Monitoring time 2 DG [0.1s]
   p_TSD1_DG : INT ;    //Stabilization time for DG shutdown No. 1 [0.1s]
   p_TSD2_DG : INT  := 10;  //Stabilization time for DG shutdown No. 2 [0.1s]
   p_TSD3_DG : INT  := 10;  //Stabilization time for DG shutdown No. 3 [0.1s]
   p_TSD4_DG : INT  := 10;  //Stabilization time for DG shutdown No. 4 [0.1s]
   p_TSD5_DG : INT  := 10;  //Stabilization time for DG shutdown No. 5 [0.1s]
   p_TSD6_DG : INT  := 10;  //Stabilization time for DG shutdown No. 6 [0.1s]
   p_TSD7_DG : INT  := 10;  //Stabilization time for DG shutdown No. 7 [0.1s]
   p_TSD8_DG : INT  := 10;  //Stabilization time for DG shutdown No. 8 [0.1s]
   p_TSensor_SD2 : INT  := 200; //Waiting time for sensor monitoring SD channel 2 (Low lub oil press.) [0.1s]
   var132 : BYTE ;  //Spare
   p_uploadLatch : BOOL ;   //The command "upload" is stored. Reset by a separte signal [0 =no, 1 =yes]
   var13212 : BOOL ;    //Spare
   var13213 : BOOL ;    //Spare
   var13214 : BOOL ;    //Spare
   var13215 : BOOL ;    //Spare
   var13216 : BOOL ;    //Spare
   var13217 : BOOL ;    //Spare
   var1321 : BOOL ; //Spare
   p_runupLoad : REAL  := 1.000000e+000;    //Run-up time load balance
   p_rundownLoad : REAL  := 1.000000e+000;  //Run-down time load balance
   p_period_deload : INT  := 40;    //deload pulse: period time in 0.1sec
   p_puls_deload : INT  := 10;  //deload pulse: pulse time in 0.1sec
   p_f_static_zero : REAL  := 5.000000e+001;    //Frequency static: zero percent point [Hz]
   p_f_static_hund : REAL  := 5.000000e+001;    //Frequency static: hundert percent point [Hz]
   p_Ctrl_Kp : REAL  := 1.000000e+000;  //Controller: Gain factor [Kp]
   p_Ctrl_FreqQuality : REAL  := 2.000000e+000; //Controller: frequency quality factor
   p_Ctrl_dead_lim : REAL  := 1.000000e+000;    //Controller: Deadband limit [%]
   f_Ctrl_shortP_lim : REAL  := 5.000000e+000;  //Controller: short pulse limit [%]
   f_Ctrl_limSet : REAL  := 3.000000e+001;  //Limit frequency setpoint (+- Hz)
   p_Ctrl_longP_lim : REAL  := 2.000000e+001;   //Controller: long pulse limit [%]
   p_Ctrl_sP_pulse : INT  := 1; //Controller: short pulse length [x0.5s]
   p_Ctrl_sP_period : INT  := 20;   //Controller: short period length [x0.5s]
   p_Ctrl_lP_pulse : INT  := 6; //Controller: long pulse length [x0.5s]
   p_Ctrl_lP_period : INT  := 20;   //Controller: long period length [x0.5s]
   p_GBoff_Load : INT  := 20;   //Generatorbreaker off Load limit [in kW]
   p_setLoad_G1 : INT  := 940;  //Nominal load generator 1
   p_setLoad_G2 : INT  := 940;  //Nominal load generator 2
   p_setLoad_G3 : INT  := 1090; //Nominal load generator 3 (for load sharing)
   p_setLoad_G4 : INT ; //Nominal load generator 4
   p_setLoad_G5 : INT ; //Nominal load generator 5
   p_setLoad_G6 : INT ; //Nominal load generator 6
   p_setLoad_G7 : INT ; //Nominal load generator 7
   p_setLoad_G8 : INT ; //Nominal load generator 8
   p_setLoad_G9 : INT ; //Nominal load generator 9
   p_setLoad_G10 : INT ;    //Nominal load generator 10
   p_setLoad_G11 : INT ;    //Nominal load generator 11
   p_setLoad_G12 : INT ;    //Nominal load generator 12
   p_setLoad_G13 : INT ;    //Nominal load generator 13
   p_setLoad_EG : INT  := 180;  //Nominal load emergency generator
   p_OUTconCtrl : INT ; //Output address 'continuous contoller (4 ..20)'
   p_nomFreq : INT  := 500; //Nominal frequency [0.1Hz]
   p_nomVolt : INT  := 400; //Nominal voltage [V]
   p_nomCurr : INT  := 1692;    //Nominal current [A]
   p_minLoad : INT  := 282; //minimum load generator set [kW]
   p_NomPower_Gen : INT  := 940;    //Nominal power of generator set (for generator protection) [kW]
   p_LimCurrMonit : INT  := 300;    //Minimum limit current monitoring [1/100%  ->1% =100]
   var151 : DWORD ;
   var152 : DWORD ;
   p_runUBLmin : REAL  := 1.000000e+000;    //rundown time UBLmin Mode
   p_Prtct_V_4L : INT  := 11000;    //Busbar voltage limit 4 [0.01% of nominal value]
   p_Prtct_V_4T : S5TIME  := S5T#1S;    //Busbar voltage limit 4, delay time  [0.1s]
   p_Prtct_V_4H : INT  := 150;  //Busbar voltage limit 4, hysteresis  [0.01%]
   p_TInd_Blackout : S5TIME  := S5T#1M; //Delay time for indication "Blackout"
   p_TRevPower_Warn : S5TIME  := S5T#1S;    //Delay time for reverse power warning
   p_TWinD_Overtemp : S5TIME  := S5T#10S;   //Delay time for indication "Blackout"
   p_TShCirc_OtherGen : S5TIME  := S5T#1S;  //Delay time for sending the signal "Short circuit" to other generator sets
   p_TShC_OtherGen_Reset : S5TIME  := S5T#1M20S;    //Delay time for automatic reset of short circuit from other generator sets
   p_UBLmax_prcDef : INT  := 8000;  //Default UBL max value in 0.01%
   p_UBLmin_prcDef : INT  := 3000;  //Default UBL min value in 0.01%
   p_dlyDeviAlrm : S5TIME  := S5T#10M;    //Delay time for deviation alarm
   p_TIgnSpeed_Off : INT  := 10;    //Delay time "Igni.speed Off" (for detection of diesel engine failure) [0.1s]
   p_deviMax : REAL  := 2.500000e+001;  //Maximal aceptable deviation between setpoint and actual value (load or freq.)
   var156 : INT ;
   var157 : INT ;
   p_wood_Isochron : BOOL ; //External speedcontroller =Isochronous mode [1 =yes]
   p_wood_IsochronAuto : BOOL ; //External speedcontroller =Isochronous mode in automatic only [1 =yes]
   p_wood_IsochronExt : BOOL ;  //External speedcontroller =Isochronous mode selectable [1 =yes]
   p_wood_IsochronLowAct : BOOL ;   //External speedcontroller =Isochronous mode low active [1 =yes]
   var1584 : BOOL ;
   var1585 : BOOL ;
   var1586 : BOOL ;
   var1587 : BOOL ;
   var1588 : BYTE ;
   var159 : INT ;
   p_heavyConsumer_1 : INT ;    //Setpoint load heavy consumer 1
   p_heavyConsumer_2 : INT ;    //Setpoint load heavy consumer 2
   p_heavyConsumer_3 : INT ;    //Setpoint load heavy consumer 3
   p_heavyConsumer_4 : INT ;    //Setpoint load heavy consumer 4
   p_heavyConsumer_5 : INT ;    //Setpoint load heavy consumer 5
   p_heavyConsumer_6 : INT ;    //Setpoint load heavy consumer 6
   p_heavyConsumer_7 : INT ;    //Setpoint load heavy consumer 7
   p_heavyConsumer_8 : INT ;    //Setpoint load heavy consumer 8
   var168 : INT ;   //+++ Begin emergency generator data (DBW558) +++
   p_TTrLBrk_Voltl : S5TIME  := S5T#20S;
   c_GW1_BLO_E : BOOL  := TRUE; //Emerg mode: -->GENOP71: Blocking of I_GW1
   c_GW2_BLO_E : BOOL ; //Emerg mode: -->GENOP71: Blocking of I_GW2 -- not used --
   c_GW3_BLO_E : BOOL  := TRUE; //Emerg mode: -->GENOP71: Blocking of I_GW3
   c_GW4_BLO_E : BOOL  := TRUE; //Emerg mode: -->GENOP71: Blocking of I_GW4
   c_GW5_BLO_E : BOOL  := TRUE; //Emerg mode: -->GENOP71: Blocking of P_GW1
   c_GW6_BLO_E : BOOL ; //Emerg mode: -->GENOP71: Blocking of I>>_GW1
   var169a : BOOL ;
   var169b : BOOL ;
   c_GW1_BLO_H : BOOL ; //Harbour mode: -->GENOP71: Blocking of I_GW1
   c_GW2_BLO_H : BOOL ;  //Harbour mode: -->GENOP71: Blocking of I_GW2 -- not used --
   c_GW3_BLO_H : BOOL ; //Harbour mode: -->GENOP71: Blocking of I_GW3
   c_GW4_BLO_H : BOOL ; //Harbour mode: -->GENOP71: Blocking of I_GW4
   c_GW5_BLO_H : BOOL ; //Harbour mode: -->GENOP71: Blocking of P_GW1
   c_GW6_BLO_H : BOOL ; //Harbour mode: -->GENOP71: Blocking of I>>_GW1
   var169c : BOOL ;
   var169d : BOOL ;
   c_GW1_BLO_F : BOOL ; //Feedb mode: -->GENOP71: Blocking of I_GW1
   c_GW2_BLO_F : BOOL ; //Feedb mode: -->GENOP71: Blocking of I_GW2 -- not used --
   c_GW3_BLO_F : BOOL ; //Feedb mode: -->GENOP71: Blocking of I_GW3
   c_GW4_BLO_F : BOOL ; //Feedb mode: -->GENOP71: Blocking of I_GW4
   c_GW5_BLO_F : BOOL ; //Feedb mode: -->GENOP71: Blocking of P_GW1
   c_GW6_BLO_F : BOOL ; //Feedb mode: -->GENOP71: Blocking of I>>_GW1
   var169e : BOOL ;
   var169f : BOOL ;
   var170a : BYTE ;
   var171 : BYTE ;
   p_Prtct_i_1_Active_E : BOOL  := TRUE;    //Emerg. mode: Generator current limit 1 monitoring active [1=active]
   p_Prtct_i_2_Active_E : BOOL  := TRUE;    //Emerg. mode: Generator current limit 2 monitoring active [1=active]
   p_Prtct_i_3_Active_E : BOOL ;    //Emerg. mode: Generator current limit 3 monitoring active [not connected]
   p_Prtct_i_4_Active_E : BOOL ;    //Emerg. mode: Generator current limit 4 monitoring active [not connected]
   p_Prtct_i_5_Active_E : BOOL ;    //Emerg. mode: Generator current limit 5 monitoring active [not connected]
   p_Prtct_i_6_Active_E : BOOL ;    //Emerg. mode: Generator current limit 6 monitoring active [not connected]
   p_Prtct_i_7_Active_E : BOOL  := TRUE;    //Emerg. mode: Generator current limit 7 monitoring active [1=active]
   var1711 : BOOL ;
   var172 : BYTE ;
   p_Prtct_P_1_Active_E : BOOL  := TRUE;    //Emerg. mode: Generator load limit 1 monitoring active [1=active]
   p_Prtct_P_2_Active_E : BOOL  := TRUE;    //Emerg. mode: Generator load limit 2 monitoring active [1=active]
   p_Prtct_P_3_Active_E : BOOL ;    //Emerg. mode: Generator load limit 3 monitoring active [1=active]
   p_Prtct_P_4_Active_E : BOOL ;    //Emerg. mode: Generator load limit 4 monitoring active [1=active]
   p_Prtct_P_5_Active_E : BOOL ;    //Emerg. mode: Generator load limit 5 monitoring active [1=active]
   p_Prtct_P_6_Active_E : BOOL ;    //Emerg. mode: Generator load limit 6 monitoring active [1=active]
   p_Prtct_P_7_Active_E : BOOL ;    //Emerg. mode: Generator load limit 7 monitoring active [1=active]
   p_Prtct_P_8_Active_E : BOOL ;    //Emerg. mode: Generator load limit 8 monitoring active [not connected]
   var173 : BYTE ;
   p_Prtct_f_1_Active_E : BOOL  := TRUE;    //Emerg. mode: Busbar frequency limit 1 monitoring active [1=active]
   p_Prtct_f_2_Active_E : BOOL  := TRUE;    //Emerg. mode: Busbar frequency limit 2 monitoring active [1=active]
   p_Prtct_f_3_Active_E : BOOL ;    //Emerg. mode: Busbar frequency limit 3 monitoring active [1=active]
   p_Prtct_f_4_Active_E : BOOL ;    //Emerg. mode: Busbar frequency limit 4 monitoring active [1=active]
   p_Prtct_f_5_Active_E : BOOL ;    //Emerg. mode: Busbar frequency limit 5 monitoring active [1=active]
   p_Prtct_f_6_Active_E : BOOL ;    //Emerg. mode: Busbar frequency limit 6 monitoring active [1=active]
   p_Prtct_f_7_Active_E : BOOL ;    //Emerg. mode: Busbar frequency limit 7 monitoring active [1=active]
   p_Prtct_f_8_Active_E : BOOL  := TRUE;    //Emerg. mode: Busbar frequency limit 8 monitoring active [1=active]
   var174 : BYTE ;
   p_Prtct_V_1_Active_E : BOOL  := TRUE;    //Emerg. mode: Busbar voltage limit 1 monitoring active [1=active]
   p_Prtct_V_2_Active_E : BOOL ;    //Emerg. mode: Busbar voltage limit 2 monitoring active [1=active]
   p_Prtct_V_3_Active_E : BOOL  := TRUE;    //Emerg. mode: Busbar voltage limit 3 monitoring active [1=active]
   p_Prtct_V_4_Active_E : BOOL ;    //Emerg. mode: Busbar voltage limit 4 monitoring active [1=active]
   var1741 : BOOL ;
   var1742 : BOOL ;
   var1743 : BOOL ;
   var1744 : BOOL ;
   var175 : BYTE ;
   p_Prtct_i_1_Active_H : BOOL  := TRUE;    //Harbour mode: Generator current limit 1 monitoring active [1=active]
   p_Prtct_i_2_Active_H : BOOL  := TRUE;    //Harbour mode: Generator current limit 2 monitoring active [1=active]
   p_Prtct_i_3_Active_H : BOOL ;    //Harbour mode: Generator current limit 3 monitoring active [not connected]
   p_Prtct_i_4_Active_H : BOOL ;    //Harbour mode: Generator current limit 4 monitoring active [not connected]
   p_Prtct_i_5_Active_H : BOOL ;    //Harbour mode: Generator current limit 5 monitoring active [not connected]
   p_Prtct_i_6_Active_H : BOOL ;    //Harbour mode: Generator current limit 6 monitoring active [not connected]
   p_Prtct_i_7_Active_H : BOOL  := TRUE;    //Harbour mode: Generator current limit 7 monitoring active [1=active]
   var1751 : BOOL ;
   var176 : BYTE ;
   p_Prtct_P_1_Active_H : BOOL  := TRUE;    //Harbour mode: Generator load limit 1 monitoring active [1=active]
   p_Prtct_P_2_Active_H : BOOL  := TRUE;    //Harbour mode: Generator load limit 2 monitoring active [1=active]
   p_Prtct_P_3_Active_H : BOOL  := TRUE;    //Harbour mode: Generator load limit 3 monitoring active [1=active]
   p_Prtct_P_4_Active_H : BOOL  := TRUE;    //Harbour mode: Generator load limit 4 monitoring active [1=active]
   p_Prtct_P_5_Active_H : BOOL  := TRUE;    //Harbour mode: Generator load limit 5 monitoring active [1=active]
   p_Prtct_P_6_Active_H : BOOL  := TRUE;    //Harbour mode: Generator load limit 6 monitoring active [1=active]
   p_Prtct_P_7_Active_H : BOOL  := TRUE;    //Harbour mode: Generator load limit 7 monitoring active [1=active]
   p_Prtct_P_8_Active_H : BOOL ;    //Harbour mode: Generator load limit 8 monitoring active [not connected]
   var177 : BYTE ;
   p_Prtct_f_1_Active_H : BOOL  := TRUE;    //Harbour mode: Busbar frequency limit 1 monitoring active [1=active]
   p_Prtct_f_2_Active_H : BOOL  := TRUE;    //Harbour mode: Busbar frequency limit 2 monitoring active [1=active]
   p_Prtct_f_3_Active_H : BOOL  := TRUE;    //Harbour mode: Busbar frequency limit 3 monitoring active [1=active]
   p_Prtct_f_4_Active_H : BOOL  := TRUE;    //Harbour mode: Busbar frequency limit 4 monitoring active [1=active]
   p_Prtct_f_5_Active_H : BOOL  := TRUE;    //Harbour mode: Busbar frequency limit 5 monitoring active [1=active]
   p_Prtct_f_6_Active_H : BOOL  := TRUE;    //Harbour mode: Busbar frequency limit 6 monitoring active [1=active]
   p_Prtct_f_7_Active_H : BOOL  := TRUE;    //Harbour mode: Busbar frequency limit 7 monitoring active [1=active]
   p_Prtct_f_8_Active_H : BOOL  := TRUE;    //Harbour mode: Busbar frequency limit 8 monitoring active [1=active]
   var178 : BYTE ;
   p_Prtct_V_1_Active_H : BOOL  := TRUE;    //Harbour mode: Busbar voltage limit 1 monitoring active [1=active]
   p_Prtct_V_2_Active_H : BOOL  := TRUE;    //Harbour mode: Busbar voltage limit 2 monitoring active [1=active]
   p_Prtct_V_3_Active_H : BOOL  := TRUE;    //Harbour mode: Busbar voltage limit 3 monitoring active [1=active]
   p_Prtct_V_4_Active_H : BOOL  := TRUE;    //Harbour mode: Busbar voltage limit 4 monitoring active [1=active]
   var1781 : BOOL ;
   var1782 : BOOL ;
   var1783 : BOOL ;
   var1784 : BOOL ;
   var179 : BYTE ;
   p_Prtct_i_1_Active_F : BOOL  := TRUE;    //Feedb. mode: Generator current limit 1 monitoring active [1=active]
   p_Prtct_i_2_Active_F : BOOL  := TRUE;    //Feedb. mode: Generator current limit 2 monitoring active [1=active]
   p_Prtct_i_3_Active_F : BOOL ;    //Feedb. mode: Generator current limit 3 monitoring active [not connected]
   p_Prtct_i_4_Active_F : BOOL ;    //Feedb. mode: Generator current limit 4 monitoring active [not connected]
   p_Prtct_i_5_Active_F : BOOL ;    //Feedb. mode: Generator current limit 5 monitoring active [not connected]
   p_Prtct_i_6_Active_F : BOOL ;    //Feedb. mode: Generator current limit 6 monitoring active [not connected]
   p_Prtct_i_7_Active_F : BOOL  := TRUE;    //Feedb. mode: Generator current limit 7 monitoring active [1=active]
   var1791 : BOOL ;
   var180 : BYTE ;
   p_Prtct_P_1_Active_F : BOOL  := TRUE;    //Feedb. mode: Generator load limit 1 monitoring active [1=active]
   p_Prtct_P_2_Active_F : BOOL  := TRUE;    //Feedb. mode: Generator load limit 2 monitoring active [1=active]
   p_Prtct_P_3_Active_F : BOOL  := TRUE;    //Feedb. mode: Generator load limit 3 monitoring active [1=active]
   p_Prtct_P_4_Active_F : BOOL  := TRUE;    //Feedb. mode: Generator load limit 4 monitoring active [1=active]
   p_Prtct_P_5_Active_F : BOOL  := TRUE;    //Feedb. mode: Generator load limit 5 monitoring active [1=active]
   p_Prtct_P_6_Active_F : BOOL  := TRUE;    //Feedb. mode: Generator load limit 6 monitoring active [1=active]
   p_Prtct_P_7_Active_F : BOOL  := TRUE;    //Feedb. mode: Generator load limit 7 monitoring active [1=active]
   p_Prtct_P_8_Active_F : BOOL ;    //Feedb. mode: Generator load limit 8 monitoring active [not connected]
   var1801 : BYTE ;
   p_Prtct_f_1_Active_F : BOOL  := TRUE;    //Feedb. mode: Busbar frequency limit 1 monitoring active [1=active]
   p_Prtct_f_2_Active_F : BOOL  := TRUE;    //Feedb. mode: Busbar frequency limit 2 monitoring active [1=active]
   p_Prtct_f_3_Active_F : BOOL  := TRUE;    //Feedb. mode: Busbar frequency limit 3 monitoring active [1=active]
   p_Prtct_f_4_Active_F : BOOL  := TRUE;    //Feedb. mode: Busbar frequency limit 4 monitoring active [1=active]
   p_Prtct_f_5_Active_F : BOOL  := TRUE;    //Feedb. mode: Busbar frequency limit 5 monitoring active [1=active]
   p_Prtct_f_6_Active_F : BOOL  := TRUE;    //Feedb. mode: Busbar frequency limit 6 monitoring active [1=active]
   p_Prtct_f_7_Active_F : BOOL  := TRUE;    //Feedb. mode: Busbar frequency limit 7 monitoring active [1=active]
   p_Prtct_f_8_Active_F : BOOL  := TRUE;    //Feedb. mode: Busbar frequency limit 8 monitoring active [1=active]
   var1815 : BYTE ;
   p_Prtct_V_1_Active_F : BOOL  := TRUE;    //Feedb. mode: Busbar voltage limit 1 monitoring active [1=active]
   p_Prtct_V_2_Active_F : BOOL  := TRUE;    //Feedb. mode: Busbar voltage limit 2 monitoring active [1=active]
   p_Prtct_V_3_Active_F : BOOL  := TRUE;    //Feedb. mode: Busbar voltage limit 3 monitoring active [1=active]
   p_Prtct_V_4_Active_F : BOOL  := TRUE;    //Feedb. mode: Busbar voltage limit 4 monitoring active [1=active]
   var18111 : BOOL ;
   var18121 : BOOL ;
   var18131 : BOOL ;
   var18141 : BOOL ;
   p_SD1_Used_EG_E : BOOL  := TRUE; //Emerg. mode: Shutdown function 1 for EG used [0=not used, 1=used]
   p_SD2_Used_EG_E : BOOL  := TRUE; //Emerg. mode: Shutdown function 2 for EG used [0=not used, 1=used]
   p_SD3_Used_EG_E : BOOL  := TRUE; //Emerg. mode: Shutdown function 3 for EG used [0=not used, 1=used]
   p_SD4_Used_EG_E : BOOL  := TRUE; //Emerg. mode: Shutdown function 4 for EG used [0=not used, 1=used]
   p_SD5_Used_EG_E : BOOL ; //Emerg. mode: Shutdown function 5 for EG used [0=not used, 1=used]
   p_SD6_Used_EG_E : BOOL ; //Emerg. mode: Shutdown function 6 for EG used [0=not used, 1=used]
   p_SD7_Used_EG_E : BOOL ; //Emerg. mode: Shutdown function 7 for EG used [0=not used, 1=used]
   p_SD8_Used_EG_E : BOOL ; //Emerg. mode: Shutdown function 8 for EG used [0=not used, 1=used]
   p_SD1_Delay_EG_E : BOOL ;    //Emerg. mode: Shutdown 1 for EG delayed or undelayed [0=undelayed, 1=delayed]
   p_SD2_Delay_EG_E : BOOL ;    //Emerg. mode: Shutdown 2 for EG delayed or undelayed [0=undelayed, 1=delayed]
   p_SD3_Delay_EG_E : BOOL ;    //Emerg. mode: Shutdown 3 for EG delayed or undelayed [0=undelayed, 1=delayed]
   p_SD4_Delay_EG_E : BOOL ;    //Emerg. mode: Shutdown 4 for EG delayed or undelayed [0=undelayed, 1=delayed]
   p_SD5_Delay_EG_E : BOOL ;    //Emerg. mode: Shutdown 5 for EG delayed or undelayed [0=undelayed, 1=delayed]
   p_SD6_Delay_EG_E : BOOL ;    //Emerg. mode: Shutdown 6 for EG delayed or undelayed [0=undelayed, 1=delayed]
   p_SD7_Delay_EG_E : BOOL ;    //Emerg. mode: Shutdown 7 for EG delayed or undelayed [0=undelayed, 1=delayed]
   p_SD8_Delay_EG_E : BOOL ;    //Emerg. mode: Shutdown 8 for EG delayed or undelayed [0=undelayed, 1=delayed]
   p_SD1_Mon1_EG_E : BOOL ; //Emerg. mode: Release of SD1 for EG wo/with monitor. time 1 [0=without, 1=with]
   p_SD2_Mon1_EG_E : BOOL  := TRUE; //Emerg. mode: Release of SD2 for EG wo/with monitor. time 1 [0=without, 1=with]
   p_SD3_Mon1_EG_E : BOOL ; //Emerg. mode: Release of SD3 for EG wo/with monitor. time 1 [0=without, 1=with]
   p_SD4_Mon1_EG_E : BOOL ; //Emerg. mode: Release of SD4 for EG wo/with monitor. time 1 [0=without, 1=with]
   p_SD5_Mon1_EG_E : BOOL ; //Emerg. mode: Release of SD5 for EG wo/with monitor. time 1 [0=without, 1=with]
   p_SD6_Mon1_EG_E : BOOL ; //Emerg. mode: Release of SD6 for EG wo/with monitor. time 1 [0=without, 1=with]
   p_SD7_Mon1_EG_E : BOOL ; //Emerg. mode: Release of SD7 for EG wo/with monitor. time 1 [0=without, 1=with]
   p_SD8_Mon1_EG_E : BOOL ; //Emerg. mode: Release of SD8 for EG wo/with monitor. time 1 [0=without, 1=with]
   p_SD1_Mon2_EG_E : BOOL ; //Emerg. mode: Rel. of SD1 for EG with monitor. time 1/1+2 [0=with 1, 1=with 1+2]
   p_SD2_Mon2_EG_E : BOOL ; //Emerg. mode: Rel. of SD2 for EG with monitor. time 1/1+2 [0=with 1, 1=with 1+2]
   p_SD3_Mon2_EG_E : BOOL ; //Emerg. mode: Rel. of SD3 for EG with monitor. time 1/1+2 [0=with 1, 1=with 1+2]
   p_SD4_Mon2_EG_E : BOOL ; //Emerg. mode: Rel. of SD4 for EG with monitor. time 1/1+2 [0=with 1, 1=with 1+2]
   p_SD5_Mon2_EG_E : BOOL ; //Emerg. mode: Rel. of SD5 for EG with monitor. time 1/1+2 [0=with 1, 1=with 1+2]
   p_SD6_Mon2_EG_E : BOOL ; //Emerg. mode: Rel. of SD6 for EG with monitor. time 1/1+2 [0=with 1, 1=with 1+2]
   p_SD7_Mon2_EG_E : BOOL ; //Emerg. mode: Rel. of SD7 for EG with monitor. time 1/1+2 [0=with 1, 1=with 1+2]
   p_SD8_Mon2_EG_E : BOOL ; //Emerg. mode: Rel. of SD8 for EG with monitor. time 1/1+2 [0=with 1, 1=with 1+2]
   p_SD1_Used_EG_H : BOOL  := TRUE; //Harbour mode: Shutdown function 1 for EG used [0=not used, 1=used]
   p_SD2_Used_EG_H : BOOL  := TRUE; //Harbour mode: Shutdown function 2 for EG used [0=not used, 1=used]
   p_SD3_Used_EG_H : BOOL  := TRUE; //Harbour mode: Shutdown function 3 for EG used [0=not used, 1=used]
   p_SD4_Used_EG_H : BOOL  := TRUE; //Harbour mode: Shutdown function 4 for EG used [0=not used, 1=used]
   p_SD5_Used_EG_H : BOOL ; //Harbour mode: Shutdown function 5 for EG used [0=not used, 1=used]
   p_SD6_Used_EG_H : BOOL ;   //Harbour mode: Shutdown function 6 for EG used [0=not used, 1=used]
   p_SD7_Used_EG_H : BOOL ; //Harbour mode: Shutdown function 7 for EG used [0=not used, 1=used]
   p_SD8_Used_EG_H : BOOL ; //Harbour mode: Shutdown function 8 for EG used [0=not used, 1=used]
   p_SD1_Delay_EG_H : BOOL ;    //Harbour mode: Shutdown 1 for EG delayed or undelayed [0=undelayed, 1=delayed]
   p_SD2_Delay_EG_H : BOOL ;    //Harbour mode: Shutdown 2 for EG delayed or undelayed [0=undelayed, 1=delayed]
   p_SD3_Delay_EG_H : BOOL ;    //Harbour mode: Shutdown 3 for EG delayed or undelayed [0=undelayed, 1=delayed]
   p_SD4_Delay_EG_H : BOOL ;    //Harbour mode: Shutdown 4 for EG delayed or undelayed [0=undelayed, 1=delayed]
   p_SD5_Delay_EG_H : BOOL ;    //Harbour mode: Shutdown 5 for EG delayed or undelayed [0=undelayed, 1=delayed]
   p_SD6_Delay_EG_H : BOOL ;    //Harbour mode: Shutdown 6 for EG delayed or undelayed [0=undelayed, 1=delayed]
   p_SD7_Delay_EG_H : BOOL ;    //Harbour mode: Shutdown 7 for EG delayed or undelayed [0=undelayed, 1=delayed]
   p_SD8_Delay_EG_H : BOOL ;    //Harbour mode: Shutdown 8 for EG delayed or undelayed [0=undelayed, 1=delayed]
   p_SD1_Mon1_EG_H : BOOL ; //Harbour mode: Release of SD1 for EG wo/with monitor. time 1 [0=without, 1=with]
   p_SD2_Mon1_EG_H : BOOL  := TRUE; //Harbour mode: Release of SD2 for EG wo/with monitor. time 1 [0=without, 1=with]
   p_SD3_Mon1_EG_H : BOOL ; //Harbour mode: Release of SD3 for EG wo/with monitor. time 1 [0=without, 1=with]
   p_SD4_Mon1_EG_H : BOOL ; //Harbour mode: Release of SD4 for EG wo/with monitor. time 1 [0=without, 1=with]
   p_SD5_Mon1_EG_H : BOOL ; //Harbour mode: Release of SD5 for EG wo/with monitor. time 1 [0=without, 1=with]
   p_SD6_Mon1_EG_H : BOOL ; //Harbour mode: Release of SD6 for EG wo/with monitor. time 1 [0=without, 1=with]
   p_SD7_Mon1_EG_H : BOOL ; //Harbour mode: Release of SD7 for EG wo/with monitor. time 1 [0=without, 1=with]
   p_SD8_Mon1_EG_H : BOOL ; //Harbour mode: Release of SD8 for EG wo/with monitor. time 1 [0=without, 1=with]
   p_SD1_Mon2_EG_H : BOOL ;  //Harbour mode: Rel. of SD1 for EG with monitor. time 1/1+2 [0=with 1, 1=with 1+2
   p_SD2_Mon2_EG_H : BOOL ; //Harbour mode: Rel. of SD2 for EG with monitor. time 1/1+2 [0=with 1, 1=with 1+2
   p_SD3_Mon2_EG_H : BOOL ; //Harbour mode: Rel. of SD3 for EG with monitor. time 1/1+2 [0=with 1, 1=with 1+2
   p_SD4_Mon2_EG_H : BOOL ; //Harbour mode: Rel. of SD4 for EG with monitor. time 1/1+2 [0=with 1, 1=with 1+2
   p_SD5_Mon2_EG_H : BOOL ; //Harbour mode: Rel. of SD5 for EG with monitor. time 1/1+2 [0=with 1, 1=with 1+2
   p_SD6_Mon2_EG_H : BOOL ; //Harbour mode: Rel. of SD6 for EG with monitor. time 1/1+2 [0=with 1, 1=with 1+2
   p_SD7_Mon2_EG_H : BOOL ; //Harbour mode: Rel. of SD7 for EG with monitor. time 1/1+2 [0=with 1, 1=with 1+2
   p_SD8_Mon2_EG_H : BOOL ; //Harbour mode: Rel. of SD8 for EG with monitor. time 1/1+2 [0=with 1, 1=with 1+2
   p_SD1_Used_EG_F : BOOL  := TRUE; //Feedb. mode: Shutdown function 1 for EG used [0=not used, 1=used]
   p_SD2_Used_EG_F : BOOL  := TRUE;    //Feedb. mode: Shutdown function 2 for EG used [0=not used, 1=used]
   p_SD3_Used_EG_F : BOOL  := TRUE; //Feedb. mode: Shutdown function 3 for EG used [0=not used, 1=used]
   p_SD4_Used_EG_F : BOOL  := TRUE; //Feedb. mode: Shutdown function 4 for EG used [0=not used, 1=used]
   p_SD5_Used_EG_F : BOOL ; //Feedb. mode: Shutdown function 5 for EG used [0=not used, 1=used]
   p_SD6_Used_EG_F : BOOL ; //Feedb. mode: Shutdown function 6 for EG used [0=not used, 1=used]
   p_SD7_Used_EG_F : BOOL ; //Feedb. mode: Shutdown function 7 for EG used [0=not used, 1=used]
   p_SD8_Used_EG_F : BOOL ; //Feedb. mode: Shutdown function 8 for EG used [0=not used, 1=used]
   p_SD1_Delay_EG_F : BOOL ;    //Feedb. mode: Shutdown 1 for EG delayed or undelayed [0=undelayed, 1=delayed]
   p_SD2_Delay_EG_F : BOOL ;    //Feedb. mode: Shutdown 2 for EG delayed or undelayed [0=undelayed, 1=delayed]
   p_SD3_Delay_EG_F : BOOL ;    //Feedb. mode: Shutdown 3 for EG delayed or undelayed [0=undelayed, 1=delayed]
   p_SD4_Delay_EG_F : BOOL ;    //Feedb. mode: Shutdown 4 for EG delayed or undelayed [0=undelayed, 1=delayed]
   p_SD5_Delay_EG_F : BOOL ;    //Feedb. mode: Shutdown 5 for EG delayed or undelayed [0=undelayed, 1=delayed]
   p_SD6_Delay_EG_F : BOOL ;    //Feedb. mode: Shutdown 6 for EG delayed or undelayed [0=undelayed, 1=delayed]
   p_SD7_Delay_EG_F : BOOL ;    //Feedb. mode: Shutdown 7 for EG delayed or undelayed [0=undelayed, 1=delayed]
   p_SD8_Delay_EG_F : BOOL ;    //Feedb. mode: Shutdown 8 for EG delayed or undelayed [0=undelayed, 1=delayed]
   p_SD1_Mon1_EG_F : BOOL ; //Feedb. mode: Release of SD1 for EG wo/with monitor. time 1 [0=without, 1=with]
   p_SD2_Mon1_EG_F : BOOL  := TRUE; //Feedb. mode: Release of SD2 for EG wo/with monitor. time 1 [0=without, 1=with]
   p_SD3_Mon1_EG_F : BOOL ; //Feedb. mode: Release of SD3 for EG wo/with monitor. time 1 [0=without, 1=with]
   p_SD4_Mon1_EG_F : BOOL ; //Feedb. mode: Release of SD4 for EG wo/with monitor. time 1 [0=without, 1=with]
   p_SD5_Mon1_EG_F : BOOL ; //Feedb. mode: Release of SD5 for EG wo/with monitor. time 1 [0=without, 1=with]
   p_SD6_Mon1_EG_F : BOOL ; //Feedb. mode: Release of SD6 for EG wo/with monitor. time 1 [0=without, 1=with]
   p_SD7_Mon1_EG_F : BOOL ; //Feedb. mode: Release of SD7 for EG wo/with monitor. time 1 [0=without, 1=with]
   p_SD8_Mon1_EG_F : BOOL ; //Feedb. mode: Release of SD8 for EG wo/with monitor. time 1 [0=without, 1=with]
   p_SD1_Mon2_EG_F : BOOL ; //Feedb. mode: Rel. of SD1 for EG with monitor. time 1/1+2 [0=with 1, 1=with 1+2
   p_SD2_Mon2_EG_F : BOOL ; //Feedb. mode: Rel. of SD2 for EG with monitor. time 1/1+2 [0=with 1, 1=with 1+2
   p_SD3_Mon2_EG_F : BOOL ; //Feedb. mode: Rel. of SD3 for EG with monitor. time 1/1+2 [0=with 1, 1=with 1+2
   p_SD4_Mon2_EG_F : BOOL ; //Feedb. mode: Rel. of SD4 for EG with monitor. time 1/1+2 [0=with 1, 1=with 1+2
   p_SD5_Mon2_EG_F : BOOL ; //Feedb. mode: Rel. of SD5 for EG with monitor. time 1/1+2 [0=with 1, 1=with 1+2
   p_SD6_Mon2_EG_F : BOOL ; //Feedb. mode: Rel. of SD6 for EG with monitor. time 1/1+2 [0=with 1, 1=with 1+2
   p_SD7_Mon2_EG_F : BOOL ; //Feedb. mode: Rel. of SD7 for EG with monitor. time 1/1+2 [0=with 1, 1=with 1+2
   p_SD8_Mon2_EG_F : BOOL ; //Feedb. mode: Rel. of SD8 for EG with monitor. time 1/1+2 [0=with 1, 1=with 1+2
   p_TrsBrk_No : BYTE ; //Option: in case of a dynamic EG: transfer breaker number (=TB-No [=0: no TB])
   p_2ndGenBrkON_auto : BOOL  := TRUE;  //Option: in case of a dynamic EG: move to auto if 2nd generator on busbar
   var170111 : BOOL ;
   var170121 : BOOL ;
   var170131 : BOOL ;
   var170141 : BOOL ;
   var170151 : BOOL ;
   var170161 : BOOL ;
   var170171 : BOOL ;
   p_SwitchBack_Lock : BOOL ;   //Switching back lock, Autom. gen. CB Off --> transfer line CB On, [0=Yes, 1=No]
   p_unessConsumI_avail : BOOL ;    //unessential consumer I are available
   p_unessConsumII_avail : BOOL ;   //unessential consumer II are available
   p_unessConsumIII_avail : BOOL ;  //unessential consumer III are available
   p_P_F_Cntrl_avail : BOOL ;   //Load- & Frequency controller available -only in habour mode active-
   var6025 : BOOL ;
   p_HarbourMode : BOOL ;   //Harbour mode exist
   p_PowerFdbMode : BOOL ;  //Powerfeedback mode exist
   P_Overcur_WindTempHigh : BOOL ;  //GenBrk off also in normal mode if overcurrent and winding temperature high
   var60281 : BOOL ;
   var60282 : BOOL ;
   var60283 : BOOL ;
   var60284 : BOOL ;
   var60285 : BOOL ;
   var60286 : BOOL ;
   var60287 : BOOL ;
   p_TNoVoltTrL : INT  := 50;   //Waiting time for "No voltage on transfer line" (for EG start) [0.1s]
   p_TPulseTrLGenBrk : INT  := 50;  //Pulse time for Generator breaker On until feedback signal "Transfer line circui
   p_TReturnVoltTrL : INT  := 600;  //Waiting time for switching back (EG operation --> Transfer line) after return o
   p_TGenBrk_TrLBrk : INT  := 30;   //Switching break between Generator breaker Off --> Transfer line circuit breaker
   p_TTrLBrk_GenBrk : INT  := 30;   //Switching break between Transfer line circuit breaker Off --> Generator breaker
   p_TTrLBrkReady : INT  := 100; //Waiting time for failure signal "Transfer line circuit breaker not ready" (in 0
   p_TTrLBrkOn : INT  := 20;    //Pulse time for transfer line circuit breaker ON command [0.1s]
   p_TTrLBrkOff : INT  := 30;   //Pulse time for transfer line circuit breaker OFF command  [0.1s]
   p_TTrLBrkFbOn : INT  := 10;  //Monitoring time for FB signal "Transfer line CB ON" after ON command [0.1s]
   p_TTrLBrkFbOff : INT  := 10; //Monitoring time for FB signal "Transfer line CB OFF" after OFF command [0.1s]
   p_TAuxil : INT  := 600;  //OFF delay for Auxiliaries  after emergency diesel stop [0.1s]
   p_WarnRelCnd_1 : BYTE  := B#16#3;    //Diesel engine alarm: release condition no.1
   p_WarnRelCnd_2 : BYTE  := B#16#4;    //Diesel engine alarm: release condition no.2
   p_WarnRelUncnd : BYTE  := B#16#18;   //Diesel engine alarm: release unconditional
   p_WarnRel_1_T : S5TIME ; //Diesel engine alarm: delay time release 1
   p_WarnRel_2_T : S5TIME ; //Diesel engine alarm: delay time release 2
   p_WarnDly_C1 : S5TIME  := S5T#2S;   //Diesel engine alarm: delay time channel 1
   p_WarnDly_C2 : S5TIME  := S5T#2S;    //Diesel engine alarm: delay time channel 2
   p_WarnDly_C3 : S5TIME  := S5T#2S;    //Diesel engine alarm: delay time channel 3
   p_WarnDly_C4 : S5TIME  := S5T#2S;    //Diesel engine alarm: delay time channel 4
   p_WarnDly_C5 : S5TIME  := S5T#2S;    //Diesel engine alarm: delay time channel 5
   p_WarnDly_C6 : S5TIME  := S5T#2S;    //Diesel engine alarm: delay time channel 6
   p_WarnDly_C7 : S5TIME  := S5T#2S;    //Diesel engine alarm: delay time channel 7
   p_WarnDly_C8 : S5TIME  := S5T#2S;    //Diesel engine alarm: delay time channel 8
   p_dlyT_GenBrkTrip : S5TIME  := S5T#10S;  //Delay time generator breaker tripped
   p_dlyT_TrsBrkTrip : S5TIME  := S5T#3S;   //Delay time transfer breaker tripped
   p_dlyT_GenBrkReady : S5TIME  := S5T#1S;  //Delay time generator breaker ready -undervoltage coil-
   p_dlyT_TrsBrkReady : S5TIME  := S5T#1S;  //Delay time transfer breaker ready
   var192 : INT ;   //+++ Begin tie breaker data (DBW660) +++
   p_noSlaveTie : BOOL ;    //No slave tie breaker (=1)
   p_OnNotShoreOn : BOOL ;  //If the shore connection on it is not permitted to close the tie breaker
   p_TieBrkOffBlack : BOOL ;    //In case of an on side blackout: tie breaker off (=1)
   p_allowGen_Rel : BOOL ;  //Release tie breaker off in case of exceeded numbers of allowed generators
   p_ShoreExpBoth_TBclse : BOOL ;   //if shore connection on of both sides in export mode tie breaker close possible
   p_blackout_BrkOff : BOOL ;   //Option: Open tie breaker in case of blackout
   p_TieBrkOnBlack : BOOL ; //in case of a blackout: tie breaker close (=1)
   p_noStdbyStrt : BOOL ;   //in case of overcurrent or overload no standby start (=1)
   p_allowGen : INT ;   //Allowed numbers of generators on busbar
   p_dlyT_opntiebrk : S5TIME  := S5T#30S;   //delay time befor opening tie breaker in case of 4 running generator sets
   p_SlvBrkCtrl : BOOL ;    //Slave breaker is controlled by the PLC [0=no] [1=yes]
   p_noStdByStart : BOOL  := TRUE; //No standby start in case of overload of the tie breaker [1=yes]
   var210a13 : BOOL ;
   var210a14 : BOOL ;
   var210a15 : BOOL ;
   var210a16 : BOOL ;
   var210a17 : BOOL ;
   var210a18 : BOOL ;
   var210a11 : BYTE ;
   p_diffVolt : INT ;   //Maximum difference voltage between each phase and busbar and shore connection
   p_noVoltAdjust : BOOL  := TRUE;  //no voltage adjusting
   p_noRevP_Prtct : BOOL  := TRUE;  //no reverse power protection
   p_ShCopn_noDeload : BOOL  := TRUE;   //Shore connection breaker open without deloading
   p_noBlackContact_ShC : BOOL  := TRUE;    //OPTION: no blackout contactors available
   p_adjustVolt_untilEq : BOOL ;    //Adjusting voltage until both voltages are equal
   var300f : BOOL ;
   var300g : BOOL ;
   var300h : BOOL ;
   var3011 : BYTE ;
   p_monT_adjustVolt : S5TIME  := S5T#20S;  //Monitoring time adusting voltage
   p_monT_stpGenSet : S5TIME  := S5T#2M;    //Monitoring time stop generator set
   p_monT_takeLoad : S5TIME  := S5T#2M; //Monitoring time take over load generator set
   p_pulse_stpGenSet : S5TIME  := S5T#5S;   //Pulse time "stop generator sets"
   p_dlyT_adjustVolt : S5TIME  := S5T#10S;  //Delay time adjusting voltage, befor voltage difference will be checked
   p_allowVoltDiff : INT  := 5; //Allowed voltage difference between busbar and shore connection[V]
   p_monT_GenSetOnBus : S5TIME  := S5T#1M;  //Monitoring time until generator set on busbar
   p_monT_SlvBrk : INT  := 50;  //Monitoring time close / open slave breaker
   p_pulse_SlvBrk : INT  := 20; //Pulse time close / open slave breaker
   p_GenBrk_LoadRed_2nd : BOOL  := TRUE;    //Open.2nd GenBrk in semiOP load reduc(0=without,1=with) +++ Begin data second br
   var400b : BOOL ;
   var400c : BOOL ;
   var400d : BOOL ;
   var400e : BOOL ;
   var400f : BOOL ;
   var400g : BOOL ;
   var400h : BOOL ;
   p_Monit_BrkReady_2nd : BOOL  := TRUE;    //Monitoring of signal "2nd Generator breaker ready"  (0=No monit., 1=Monitor.)
   P_Monit_BrkPosNorm_2nd : BOOL ;  //Monitoring of signal "2nd Generator brk in norm position" (0=No monit, 1=Monit)
   p_Monit_BrkPosTest_2nd : BOOL ;  //Monitoring of signal "2nd Generator brk in test position" (0=No monit, 1=Monit)
   p_noBrkOffSign_2nd : BOOL ;  //OPTION: Signal "2nd Generator breaker off" not available (=1), (=0: available)
   p_GenBrk_ShoreBlock_2nd : BOOL ; //2nd Gen.brk blocked by shore conn. (no synchron.) (0=No blocking, 1=Blocking)
   p_GenBrk_OUTviaGENOP_2nd : BOOL  := TRUE;    //Command "2nd Generator breaker OFF" via GENOP
   p_BlockMonitBrkTrip_2nd : BOOL  := TRUE; //Blocking of monitoring of signal "2nd Gen.breaker tripped" (0=monit./1=block)
   p_noBrkONSign_2nd : BOOL  := TRUE;   //OPTION: Signal "2nd Generator breaker on" not available (=1), (=0: available)
   p_TgenBrkReady_2nd : INT  := 100;    //Waiting time for failure signal "Generator breaker not ready" [0.1s]
   p_TgenBrkSimOn_2nd : INT  := 20; //Waiting time for gen. breaker ON comm. after rel. from simult.locking [0.1s]
   p_TgenBrkRel_2nd : INT  := 50;   //Waiting time after run-up bef. request to simult.locking/synchroniz. [0.1s]
   P_TgenBrkSyn_2nd : INT  := 600;  //Monitoring time for synchronizing of generator breaker [0.1s]
   p_TgenBrkLoadOff_2nd : INT  := 3000; //Delay time before gen. breaker OFF, if load reduction did not work [0.1s]
   p_TgenBrkTrip_2nd : INT  := 1;   //Waiting time for failure signal "Generator breaker tripped" [0.1s]
   p_TgenBrkOn_2nd : INT  := 10;    //Pulse time for generator breaker ON command [0.1s]
   p_TgenBrkOff_2nd : INT  := 40;   //Pulse time for generator breaker OFF command [0.1s]
   p_TgenBrkFbOn_2nd : INT  := 10;  //Monitoring time for feedback signal "Generator breaker ON" [0.1s]
   p_TgenBrkFbOff_2nd : INT  := 10; //Monitoring time for feedback signal "Generator breaker OFF" [0.1s]
   p_TgenBrkFbOffOn_2nd : INT  := 20;   //Waiting time for plausibility control feedback "Gen. breaker OFF/ON" [0.1s]
   p_dlyT_adj_V_swon : S5TIME  := S5T#100MS;    //delayed switch off voltage adjust during switch on s.c.
   p_dlyT_adj_V_swoff : S5TIME  := S5T#100MS;    //delayed switch off voltage adjust during switch off s.c.
   var404 : WORD ;
   p_Tunderl_Ind_2nd : S5TIME  := S5T#30S;  //Automatic underload shut down, delay time for annunciation [0.1s] GenBrk II
   p_Tunderl_Shd_2nd : S5TIME  := S5T#1M;   //Automatic underload shut down, delay time for shutdown [0.1s] GenBrk II
   p_Underload_H_2nd : INT  := 200; //Generator underload, hysteresis [0.01%] (actually not used) GenBrk II
   p_Underl_Rel_2nd : BOOL  := TRUE;    //Release of automatic underload shutdown GenBrk II
   p_ShD_Overcurr_2nd : BOOL ;  //DG/SG/EG stop command in case of "Gen. breaker trip by overcurrent" GenBrk II
   p_ShD_RevPower_2nd : BOOL ;  //DG/SG/EG stop command in case of "Gen. breaker trip by reverse power" GenBrk II
   p_ShD_Underfrequ_2nd : BOOL ;    //DG/SG/EG stop command in case of "Gen. breaker trip by underfrequency"GenBrk II
   p_ShD_Undervolt_2nd : BOOL ; //DG/SG/EG stop command in case of "Gen. breaker trip by undervoltage" GenBrk II
   p_Blackout_StdbySt2_2nd : BOOL ;   //2nd standby set to be started in case of blackout (0=no, 1=yes) GenBrk II
   p_ShortCirc_Block_2nd : BOOL ;   //Block.after short circ.of other gen.(0=after 1st, 1=after 2nd sh.c.)GenBrk II
   p_SC_Device_Avail_2nd : BOOL ;   //Short circuit tripping device in the generator brk II available (0=No, 1=Yes)
   p_ChOver_BlOut_f2_2nd : BOOL ;   //Change over to new set via blackout in case of busbar freq.limit 2 -GenBrk II-
   p_ChOver_BlOut_f6_2nd : BOOL  := TRUE;   //Change over to new set via blackout in case of busbar freq.limit 6 -GenBrk II-
   p_ChOver_BlOut_U1_2nd : BOOL  := TRUE;   //Change over to new set via blackout in case of busbar volt.limit 1 -GenBrk II-
   p_ChOver_BlOut_U3_2nd : BOOL  := TRUE;   //Change over to new set via blackout in case of busbar volt.limit 3 -GenBrk II-
   var405e : BOOL ;
   var405f : BOOL ;
   var405g : BOOL ;
   p_DiffProt_Avail_2nd : BOOL ;    //Differential protection available (0=No, 1=Yes) -GenBrk II-
   p_Prtct_i_1L_2nd : INT  := 9500; //Generator current limit 1 [0.01% of nominal value] -GenBrk II-
   p_Prtct_i_1T_2nd : S5TIME  := S5T#30S;   //Generator current limit 1, delay time  [0.1s] -GenBrk II-
   p_Prtct_i_1H_2nd : INT  := 200;  //Generator current limit 1, hysteresis  [0.01%] -GenBrk II-
   p_Prtct_i_2L_2nd : INT  := 10000;    //Generator current limit 2 [0.01% of nominal value] -GenBrk II-
   p_Prtct_i_2T_2nd : S5TIME  := S5T#5S;    //Generator current limit 2, delay time  [0.1s] -GenBrk II-
   p_Prtct_i_2H_2nd : INT  := 200;  //Generator current limit 2, hysteresis  [0.01%] -GenBrk II-
   p_Prtct_i_6L_2nd : INT  := 12000;    //Generator current limit 6 [0.01% of nominal value] -GenBrk II-
   p_Prtct_i_6T_2nd : S5TIME  := S5T#1S;    //Generator current limit 6, delay time  [0.1s] -GenBrk II-
   p_Prtct_i_6H_2nd : INT  := 200;  //Generator current limit 6, hysteresis  [0.01%] -GenBrk II-
   p_Prtct_i_7L_2nd : INT  := 11000;    //Generator current limit 7 [0.01% of nominal value] -GenBrk II-
   p_Prtct_i_7T_2nd : S5TIME  := S5T#30S;   //Generator current limit 7, delay time  [0.1s] -GenBrk II-
   p_Prtct_i_7H_2nd : INT  := 200;  //Generator current limit 7, hysteresis  [0.01%] -GenBrk II-
   p_Prtct_P_1L_2nd : INT  := 9500; //Generator load limit 1 [0.01% of nominal value] -GenBrk II-
   p_Prtct_P_1T_2nd : S5TIME  := S5T#30S;   //Generator load limit 1, delay time  [0.1s] -GenBrk II-
   p_Prtct_P_1H_2nd : INT  := 200;  //Generator load limit 1, hysteresis  [0.01%] -GenBrk II-
   p_Prtct_P_2L_2nd : INT  := 10500;    //Generator load limit 2 [0.01% of nominal value] -GenBrk II-
   p_Prtct_P_2T_2nd : S5TIME  := S5T#5S;    //Generator load limit 2, delay time  [0.1s] -GenBrk II-
   p_Prtct_P_2H_2nd : INT  := 200;  //Generator load limit 2, hysteresis  [0.01%] -GenBrk II-
   p_Prtct_P_3L_2nd : INT  := 10500;    //Generator load limit 3 [0.01% of nominal value] -GenBrk II-
   p_Prtct_P_3T_2nd : S5TIME  := S5T#5S;    //Generator load limit 3, delay time  [0.1s] -GenBrk II-
   p_Prtct_P_3H_2nd : INT  := 200;  //Generator load limit 3, hysteresis  [0.01%] -GenBrk II-
   p_Prtct_P_4L_2nd : INT  := 10500; //Generator load limit 4 [0.01% of nominal value] -GenBrk II-
   p_Prtct_P_4T_2nd : S5TIME  := S5T#10S;   //Generator load limit 4, delay time  [0.1s] -GenBrk II-
   p_Prtct_P_4H_2nd : INT  := 200;  //Generator load limit 4, hysteresis  [0.01%] -GenBrk II-
   p_Prtct_P_5L_2nd : INT  := 10500;    //Generator load limit 5 [0.01% of nominal value] -GenBrk II-
   p_Prtct_P_5T_2nd : S5TIME  := S5T#15S;   //Generator load limit 5, delay time  [0.1s] -GenBrk II-
   p_Prtct_P_5H_2nd : INT  := 200;  //Generator load limit 5, hysteresis  [0.01%] -GenBrk II-
   p_Prtct_P_6L_2nd : INT  := 11000;    //Generator load limit 6 [0.01% of nominal value] -GenBrk II-
   p_Prtct_P_6T_2nd : S5TIME  := S5T#1S;    //Generator load limit 6, delay time  [0.1s] -GenBrk II-
   p_Prtct_P_6H_2nd : INT  := 200;  //Generator load limit 6, hysteresis  [0.01%] -GenBrk II-
   p_Prtct_f_1L_2nd : INT  := 9750; //Busbar frequency limit 1 [0.01% of nominal value] -GenBrk II-
   p_Prtct_f_1T_2nd : S5TIME  := S5T#1M;    //Busbar frequency limit 1, delay time  [0.1s] -GenBrk II-
   p_Prtct_f_1H_2nd : INT  := 40;   //Busbar frequency limit 1, hysteresis  [0.01%] -GenBrk II-
   p_Prtct_f_2L_2nd : INT  := 9500; //Busbar frequency limit 2 [0.01% of nominal value] -GenBrk II-
   p_Prtct_f_2T_2nd : S5TIME  := S5T#8S;    //Busbar frequency limit 2, delay time  [0.1s] -GenBrk II-
   p_Prtct_f_2H_2nd : INT  := 40;   //Busbar frequency limit 2, hysteresis  [0.01%] -GenBrk II-
   p_Prtct_f_3L_2nd : INT  := 9500; //Busbar frequency limit 3 [0.01% of nominal value] -GenBrk II-
   p_Prtct_f_3T_2nd : S5TIME  := S5T#6S;    //Busbar frequency limit 3, delay time  [0.1s] -GenBrk II-
   p_Prtct_f_3H_2nd : INT  := 40;   //Busbar frequency limit 3, hysteresis  [0.01%] -GenBrk II-
   p_Prtct_f_4L_2nd : INT  := 9500; //Busbar frequency limit 4 [0.01% of nominal value] -GenBrk II-
   p_Prtct_f_4T_2nd : S5TIME  := S5T#10S;   //Busbar frequency limit 4, delay time  [0.1s] -GenBrk II-
   p_Prtct_f_4H_2nd : INT  := 40;   //Busbar frequency limit 4, hysteresis  [0.01%] -GenBrk II-
   p_Prtct_f_5L_2nd : INT  := 9500; //Busbar frequency limit 5 [0.01% of nominal value] -GenBrk II-
   p_Prtct_f_5T_2nd : S5TIME  := S5T#15S;   //Busbar frequency limit 5, delay time  [0.1s] -GenBrk II-
   p_Prtct_f_5H_2nd : INT  := 40;   //Busbar frequency limit 5, hysteresis  [0.01%] -GenBrk II-
   p_Prtct_f_6L_2nd : INT  := 9000; //Busbar frequency limit 6 [0.01% of nominal value] -GenBrk II-
   p_Prtct_f_6T_2nd : S5TIME  := S5T#1S;    //Busbar frequency limit 6, delay time  [0.1s] -GenBrk II-
   p_Prtct_f_6H_2nd : INT  := 40;   //Busbar frequency limit 6, hysteresis  [0.01%] -GenBrk II-
   p_Prtct_f_7L_2nd : INT  := 9000; //Busbar frequency limit 7 [0.01% of nominal value] -GenBrk II-
   p_Prtct_f_7T_2nd : S5TIME  := S5T#15S;   //Busbar frequency limit 7, delay time  [0.1s] -GenBrk II-
   p_Prtct_f_7H_2nd : INT  := 40;   //Busbar frequency limit 7, hysteresis  [0.01%] -GenBrk II-
   p_Prtct_f_8L_2nd : INT  := 10500;    //Busbar frequency limit 8 [0.01% of nominal value] -GenBrk II-
   p_Prtct_f_8T_2nd : S5TIME  := S5T#2S;   //Busbar frequency limit 8, delay time  [0.1s] -GenBrk II-
   p_Prtct_f_8H_2nd : INT  := 40;   //Busbar frequency limit 8, hysteresis  [0.01%] -GenBrk II-
   p_Prtct_V_1L_2nd : INT  := 9000; //Busbar voltage limit 1 [0.01% of nominal value] -GenBrk II-
   p_Prtct_V_1T_2nd : S5TIME  := S5T#5S;    //Busbar voltage limit 1, delay time  [0.1s] -GenBrk II-
   p_Prtct_V_1H_2nd : INT  := 150;  //Busbar voltage limit 1, hysteresis  [0.01%] -GenBrk II-
   p_Prtct_V_2L_2nd : INT  := 6875; //Busbar voltage limit 2 [0.01% of nominal value] -GenBrk II-
   p_Prtct_V_2T_2nd : S5TIME  := S5T#1S;    //Busbar voltage limit 2, delay time  [0.1s] -GenBrk II-
   p_Prtct_V_2H_2nd : INT  := 150;  //Busbar voltage limit 2, hysteresis  [0.01%] -GenBrk II-
   p_Prtct_V_3L_2nd : INT  := 10500;    //Busbar voltage limit 3 [0.01% of nominal value] -GenBrk II-
   p_Prtct_V_3T_2nd : S5TIME  := S5T#2S;    //Busbar voltage limit 3, delay time  [0.1s] -GenBrk II-
   p_Prtct_V_3H_2nd : INT  := 150;  //Busbar voltage limit 3, hysteresis  [0.01%] -GenBrk II-
   p_Prtct_V_4L_2nd : INT  := 11000;    //Busbar voltage limit 4 [0.01% of nominal value] -GenBrk II-
   p_Prtct_V_4T_2nd : S5TIME  := S5T#1S;    //Busbar voltage limit 4, delay time  [0.1s] -GenBrk II-
   p_Prtct_V_4H_2nd : INT  := 150;  //Busbar voltage limit 4, hysteresis  [0.01%] -GenBrk II-
   p_DifCurrent_2nd : INT  := 7500; //Limit for mean val(in 0.01% of extreme value) current measuring fail.-GenBrkII-
   P_TFCurrent_2nd : S5TIME  := S5T#10S;    //Delay time for detecting current measuring failure -GenBrk II-
   p_Vblackout_2nd : INT  := 1500;  //Busbar volt.limit f.detecting blackout (in 0.01% of nominal voltage) -GenBrkII-
   p_Tblackout_2nd : S5TIME  := S5T#1S; //Delay time for detecting blackout -GenBrk II-
   p_TFBusbar_2nd : S5TIME  := S5T#200MS;   //Delay time for detecting busbar monitoring failure -GenBrk II-
   p_VgenVolt_2nd : INT  := 8500;   //Busbar volt.limit f.normal gen.functions (in 0.01% of nominal volt.) -GenBrkII-
   p_TgenVolt_2nd : S5TIME  := S5T#10S;  //Delay time f.undervolt.2 (no signal "Generator voltage available") -GenBrk II-
   p_Underload_1_2nd : INT  := 3500;    //Gen.underload, limit 1 [0.01%], 2 gen. sets in load sharing mode -GenBrk II-
   p_Underload_2_2nd : INT  := 4500;    //Gen.underload, limit 2 [0.01%], 3 gen. sets in load sharing mode -GenBrk II-
   p_Underload_3_2nd : INT  := 5000;    //Gen.underload, limit 3 [0.01%], 4 gen. sets in load sharing mode -GenBrk II-
   p_TWinD_Overtemp_2nd : S5TIME  := S5T#10S;   //Delay time for indication "Blackout"
   p_TShCirc_OtherGen_2nd : S5TIME  := S5T#1S;  //Delay time for sending the signal "Short circuit" to other generator sets
   p_TShC_OtherGen_Rst_2nd : S5TIME  := S5T#1M20S;  //Delay time for automatic reset of short circuit from other generator sets
   p_nomFreq_2nd : INT  := 500; //Nominal frequency [0.1Hz] -GenBrk II-
   p_nomVolt_2nd : INT  := 400; //Nominal voltage [V] -GenBrk II-
   p_nomCurr_2nd : INT  := 1692;    //Nominal current [A] -GenBrk II-
   p_NomPower_Gen_2nd : INT  := 940;    //Nominal power of generator set (for generator protection) [kW] -GenBrk II-
   p_var8864 : WORD ;
   p_var8865 : WORD ;
   p_var888 : WORD ;    //+++ Begin data option restore tie breaker (DBW900) +++
   p_waitT_blackout_MSB : S5TIME  := S5T#100MS; //Waiting time blackout detecting MSB
   p_monT_restoreTieBrk : S5TIME  := S5T#5M;    //Monitoring time restore tie breaker state after blackout
   p_TrsLine : BOOL  := TRUE;   //TieBreaker:transfer breaker between MSB and ESB ->no autom.close if EG mode act
   p_var09060 : INT ;
   p_var09080 : INT ;   //+++ Begin data PTO shaftgenerator (DBW910) +++
   p_SG_Deexcit_Under_Frec : INT  := 480;   //Deexcitation SG because underfrecuency (0.1 Hz)
  END_STRUCT ;
BEGIN
   p_station := B#16#5;
   p_bus_part := B#16#1;
   p_stat_add := B#16#0;
   p_tiebrkCfg := B#16#0;
   p_tieBrkHWCfg := B#16#0;
   p_cfg11 := W#16#3007;
   p_cfg21 := W#16#0;
   p_cfg22 := W#16#0;
   p_cfg23 := W#16#0;
   p_cfg24 := W#16#0;
   p_cfg31 := W#16#0;
   p_cfg32 := W#16#0;
   p_cfg33 := W#16#0;
   p_cfg34 := W#16#0;
   p_cfg41 := W#16#1007;
   p_cfg42 := W#16#2000;
   p_cfg43 := W#16#0;
   p_cfg44 := W#16#0;
   p_moniTimeMPI := S5T#2S;
   p_cfgUness := W#16#2000;
   p_CP_add := W#16#16E;
   p_CPU_Typ := 0;
   p_No_perCall := B#16#1;
   p_GENOP_Ver := B#16#12;
   p_OLM_err := FALSE;
   p_local_alarm := FALSE;
   p_MPIfail_auto := TRUE;
   p_manTieBrk := FALSE;
   p_3Tie_cycle := FALSE;
   p_fullFct_auto := FALSE;
   p_invAllocation := FALSE;
   var11 := FALSE;
   p_OP_notExist := FALSE;
   p_OP_rel_auto := FALSE;
   p_OP_confirm := FALSE;
   p_Opfail_visu := FALSE;
   p_InalrmStore := FALSE;
   p_InemgLocal := FALSE;
   p_visuNoOperat := TRUE;
   p_visuToAuto := FALSE;
   p_noMSB_Auto := FALSE;
   p_noShoreOff := FALSE;
   p_noVisu := FALSE;
   p_noCtrl := FALSE;
   p_UBLoff_tooLow := FALSE;
   p_common_alarm := FALSE;
   p_noLoad_SemiIMAC := FALSE;
   p_2ndGenop_oneOP := FALSE;
   p_TwofixFreq := TRUE;
   var23 := FALSE;
   var24 := FALSE;
   var25 := FALSE;
   var26 := FALSE;
   var27 := FALSE;
   var28 := FALSE;
   var29 := FALSE;
   p_OUTbrkOff := FALSE;
   p_InbrkOff := FALSE;
   p_InbrkTest := FALSE;
   p_InshoreOn := FALSE;
   p_INShore2On := FALSE;
   p_INShore2Off := FALSE;
   p_brkChkLock := FALSE;
   var30 := FALSE;
   var31 := FALSE;
   var32 := FALSE;
   var33 := FALSE;
   var34 := FALSE;
   var35 := FALSE;
   var36 := FALSE;
   var37 := FALSE;
   var38 := FALSE;
   IN_0_0 := FALSE;
   IN_0_1 := FALSE;
   IN_0_2 := FALSE;
   IN_0_3 := FALSE;
   IN_0_4 := FALSE;
   IN_0_5 := FALSE;
   IN_0_6 := FALSE;
   IN_0_7 := FALSE;
   IN_1_0 := FALSE;
   IN_1_1 := FALSE;
   IN_1_2 := FALSE;
   IN_1_3 := FALSE;
   IN_1_4 := FALSE;
   IN_1_5 := FALSE;
   IN_1_6 := FALSE;
   IN_1_7 := FALSE;
   IN_2_0 := FALSE;
   IN_2_1 := FALSE;
   IN_2_2 := FALSE;
   IN_2_3 := FALSE;
   IN_2_4 := FALSE;
   IN_2_5 := FALSE;
   IN_2_6 := FALSE;
   IN_2_7 := FALSE;
   IN_3_0 := FALSE;
   IN_3_1 := FALSE;
   IN_3_2 := FALSE;
   IN_3_3 := FALSE;
   IN_3_4 := FALSE;
   IN_3_5 := FALSE;
   IN_3_6 := FALSE;
   IN_3_7 := FALSE;
   IN_4_0 := FALSE;
   IN_4_1 := FALSE;
   IN_4_2 := FALSE;
   IN_4_3 := FALSE;
   IN_4_4 := FALSE;
   IN_4_5 := FALSE;
   IN_4_6 := FALSE;
   IN_4_7 := FALSE;
   IN_5_0 := FALSE;
   IN_5_1 := FALSE;
   IN_5_2 := FALSE;
   IN_5_3 := FALSE;
   IN_5_4 := FALSE;
   IN_5_5 := FALSE;
   IN_5_6 := FALSE;
   IN_5_7 := FALSE;
   IN_6_0 := FALSE;
   IN_6_1 := FALSE;
   IN_6_2 := FALSE;
   IN_6_3 := FALSE;
   IN_6_4 := FALSE;
   IN_6_5 := FALSE;
   IN_6_6 := FALSE;
   IN_6_7 := FALSE;
   IN_7_0 := FALSE;
   IN_7_1 := FALSE;
   IN_7_2 := FALSE;
   IN_7_3 := FALSE;
   IN_7_4 := FALSE;
   IN_7_5 := FALSE;
   IN_7_6 := FALSE;
   IN_7_7 := FALSE;
   IN_8_0 := FALSE;
   IN_8_1 := FALSE;
   IN_8_2 := FALSE;
   IN_8_3 := FALSE;
   IN_8_4 := FALSE;
   IN_8_5 := FALSE;
   IN_8_6 := FALSE;
   IN_8_7 := FALSE;
   IN_9_0 := FALSE;
   IN_9_1 := FALSE;
   IN_9_2 := FALSE;
   IN_9_3 := FALSE;
   IN_9_4 := FALSE;
   IN_9_5 := FALSE;
   IN_9_6 := FALSE;
   IN_9_7 := FALSE;
   OUT_0_0 := FALSE;
   OUT_0_1 := FALSE;
   OUT_0_2 := FALSE;
   OUT_0_3 := FALSE;
   OUT_0_4 := FALSE;
   OUT_0_5 := FALSE;
   OUT_0_6 := FALSE;
   OUT_0_7 := FALSE;
   OUT_1_0 := FALSE;
   OUT_1_1 := FALSE;
   OUT_1_2 := FALSE;
   OUT_1_3 := FALSE;
   OUT_1_4 := FALSE;
   OUT_1_5 := FALSE;
   OUT_1_6 := FALSE;
   OUT_1_7 := FALSE;
   OUT_2_0 := FALSE;
   OUT_2_1 := FALSE;
   OUT_2_2 := FALSE;
   OUT_2_3 := FALSE;
   OUT_2_4 := FALSE;
   OUT_2_5 := FALSE;
   OUT_2_6 := FALSE;
   OUT_2_7 := FALSE;
   OUT_3_0 := FALSE;
   OUT_3_1 := FALSE;
   OUT_3_2 := FALSE;
   OUT_3_3 := FALSE;
   OUT_3_4 := FALSE;
   OUT_3_5 := FALSE;
   OUT_3_6 := FALSE;
   OUT_3_7 := FALSE;
   p_TStopMonit := 600;
   p_Rel_DieselContr := 5;
   p_NoLoadRun := TRUE;
   p_GenBrk_LoadRed := TRUE;
   p_LoadRed_Auto := TRUE;
   p_PrelubOil_Blocking := FALSE;
   p_PrelubOil_Blackout := FALSE;
   p_NoUndS_SGonly := FALSE;
   p_StpShC_semi := TRUE;
   p_StpShC_loadRed := FALSE;
   p_Rel_WBrk_StartV := TRUE;
   p_Rel_WBrk_StopV := TRUE;
   p_Rel_WBrk_EmStopV := TRUE;
   p_Rel_WBrk_SuppressV := FALSE;
   p_local_remote := FALSE;
   p_BrkOpnShC := TRUE;
   p_noLocalSwtch := FALSE;
   p_MonitPrelubPress := TRUE;
   p_Tstart := 50;
   p_Tpause := 150;
   p_Tstop := 400;
   p_TsuppValve := 100;
   p_NoStartAtte := B#16#3;
   p_NoPreLub_Blackout := TRUE;
   p_DlyStpNoCool := TRUE;
   var912 := FALSE;
   var913 := FALSE;
   var914 := FALSE;
   var915 := FALSE;
   var916 := FALSE;
   var917 := FALSE;
   p_TnoLoadRun := 1800;
   p_PreLubKind := B#16#0;
   p_PreLubAct := B#16#3;
   p_TpreLub1 := 5;
   p_TpreLub2 := 10;
   p_TpreLub3 := 300;
   p_TpreLub4 := 3000;
   p_PreHeatAct := B#16#0;
   var92 := B#16#0;
   p_SloTurnKind := B#16#0;
   p_SlowTurnAct := B#16#0;
   p_VoltMiss := 50;
   var93 := 0;
   p_TslowTurn3 := 0;
   p_TslowTurn4 := 0;
   p_TSDDelay := 600;
   p_TPrelub_Block := 3000;
   var950 := FALSE;
   p_GenBrk_LoadRed_SG := FALSE;
   p_LoadRed_Auto_SG := FALSE;
   var953 := FALSE;
   var954 := FALSE;
   var955 := FALSE;
   var956 := FALSE;
   var957 := B#16#0;
   p_TStart_Comm_SG := 10;
   p_TStartFail_SG := 1200;
   p_TStop_SG := 200;
   p_TStop_Comm_SG := 10;
   p_TSDDelay_SG := 600;
   p_Tmonit1_SG := 150;
   var102 := 0;
   var103 := 0;
   var104 := B#16#0;
   var1041 := FALSE;
   p_SD_StdbySt2_SG := FALSE;
   var10412 := FALSE;
   var10413 := FALSE;
   var10414 := FALSE;
   var10415 := FALSE;
   var10416 := FALSE;
   var10417 := FALSE;
   p_SD1_Used_SG := TRUE;
   p_SD2_Used_SG := TRUE;
   p_SD3_Used_SG := TRUE;
   p_SD4_Used_SG := TRUE;
   p_SD5_Used_SG := TRUE;
   p_SD6_Used_SG := TRUE;
   p_SD7_Used_SG := FALSE;
   p_SD8_Used_SG := FALSE;
   p_SD1_Delay_SG := TRUE;
   p_SD2_Delay_SG := TRUE;
   p_SD3_Delay_SG := FALSE;
   p_SD4_Delay_SG := TRUE;
   p_SD5_Delay_SG := FALSE;
   p_SD6_Delay_SG := TRUE;
   p_SD7_Delay_SG := TRUE;
   p_SD8_Delay_SG := FALSE;
   p_TSD1_SG := 10;
   p_TSD2_SG := 10;
   p_TSD3_SG := 10;
   p_TSD4_SG := 10;
   p_TSD5_SG := 10;
   p_TSD6_SG := 10;
   p_TSD7_SG := 10;
   p_TSD8_SG := 10;
   var107 := 0;
   p_PgenBrkPMin := 500;
   p_Monit_BrkReady := TRUE;
   P_Monit_BrkPosNorm := TRUE;
   p_Monit_BrkPosTest := TRUE;
   p_noBrkOffSign := FALSE;
   p_GenBrk_ShoreBlock := TRUE;
   p_GenBrk_OUTviaGENOP := TRUE;
   p_BlockMonitBrkTrip := TRUE;
   p_noBrkONSign := TRUE;
   p_GenBrk_Type := B#16#0;
   p_TgenBrkReady := 50;
   p_TgenBrkSimOn := 1;
   p_TgenBrkRel := 50;
   P_TgenBrkSyn := 600;
   p_TgenBrkLoadOff := 3000;
   p_TgenBrkTrip := 1;
   p_TgenBrkOn := 10;
   p_TgenBrkOff := 40;
   p_TgenBrkFbOn := 10;
   p_TgenBrkFbOff := 10;
   p_TgenBrkFbOffOn := 20;
   p_GBprepExpShore := FALSE;
   var1152 := FALSE;
   var1153 := FALSE;
   var1154 := FALSE;
   var1155 := FALSE;
   var1156 := FALSE;
   var1157 := FALSE;
   var1158 := FALSE;
   p_Prtc_uness1_lock := FALSE;
   p_Prtc_uness2_lock := FALSE;
   p_Prtc_uness3_lock := FALSE;
   var1733 := FALSE;
   var1734 := FALSE;
   var1735 := FALSE;
   var1736 := FALSE;
   var1737 := FALSE;
   p_dlyT_SC := S5T#0MS;
   p_Prtc_i1lock := FALSE;
   p_Prtc_i2lock := FALSE;
   p_Prtc_i3lock := FALSE;
   p_Prtc_i4lock := FALSE;
   p_Prtc_Plock := FALSE;
   p_Prtc_Sclock := FALSE;
   p_UBL_ShdPos := TRUE;
   var118 := FALSE;
   var119 := B#16#0;
   var120 := B#16#0;
   p_Prtct_i_1_Active := TRUE;
   p_Prtct_i_2_Active := TRUE;
   p_Prtct_i_3_Active := FALSE;
   p_Prtct_i_4_Active := FALSE;
   p_Prtct_i_5_Active := FALSE;
   p_Prtct_i_6_Active := FALSE;
   p_Prtct_i_7_Active := FALSE;
   var1201 := FALSE;
   var121 := B#16#0;
   p_Prtct_P_1_Active := TRUE;
   p_Prtct_P_2_Active := TRUE;
   p_Prtct_P_3_Active := TRUE;
   p_Prtct_P_4_Active := TRUE;
   p_Prtct_P_5_Active := TRUE;
   p_Prtct_P_6_Active := TRUE;
   p_Prtct_P_7_Active := FALSE;
   p_Prtct_P_8_Active := FALSE;
   var122 := B#16#0;
   p_Prtct_f_1_Active := TRUE;
   p_Prtct_f_2_Active := TRUE;
   p_Prtct_f_3_Active := TRUE;
   p_Prtct_f_4_Active := TRUE;
   p_Prtct_f_5_Active := TRUE;
   p_Prtct_f_6_Active := TRUE;
   p_Prtct_f_7_Active := TRUE;
   p_Prtct_f_8_Active := TRUE;
   var123 := B#16#0;
   p_Prtct_V_1_Active := TRUE;
   p_Prtct_V_2_Active := TRUE;
   p_Prtct_V_3_Active := TRUE;
   p_Prtct_V_4_Active := TRUE;
   var1231 := FALSE;
   var1232 := FALSE;
   var1233 := FALSE;
   var1234 := FALSE;
   p_Prtct_i_1L := 9500;
   p_Prtct_i_1T := S5T#30S;
   p_Prtct_i_1H := 200;
   p_Prtct_i_2L := 10000;
   p_Prtct_i_2T := S5T#5S;
   p_Prtct_i_2H := 200;
   p_Prtct_i_3L := 10000;
   p_Prtct_i_3T := S5T#5S;
   p_Prtct_i_3H := 200;
   p_Prtct_i_4L := 10000;
   p_Prtct_i_4T := S5T#10S;
   p_Prtct_i_4H := 200;
   p_Prtct_i_5L := 10000;
   p_Prtct_i_5T := S5T#15S;
   p_Prtct_i_5H := 200;
   p_Prtct_i_6L := 12000;
   p_Prtct_i_6T := S5T#1S;
   p_Prtct_i_6H := 200;
   p_Prtct_i_7L := 16500;
   p_Prtct_i_7T := S5T#30S;
   p_Prtct_i_7H := 200;
   p_Prtct_P_1L := 9500;
   p_Prtct_P_1T := S5T#30S;
   p_Prtct_P_1H := 200;
   p_Prtct_P_2L := 10500;
   p_Prtct_P_2T := S5T#5S;
   p_Prtct_P_2H := 200;
   p_Prtct_P_3L := 10500;
   p_Prtct_P_3T := S5T#5S;
   p_Prtct_P_3H := 200;
   p_Prtct_P_4L := 10500;
   p_Prtct_P_4T := S5T#10S;
   p_Prtct_P_4H := 200;
   p_Prtct_P_5L := 10500;
   p_Prtct_P_5T := S5T#15S;
   p_Prtct_P_5H := 200;
   p_Prtct_P_6L := 11000;
   p_Prtct_P_6T := S5T#1S;
   p_Prtct_P_6H := 200;
   p_Prtct_P_7L := -1000;
   p_Prtct_P_7T := S5T#6S;
   p_Prtct_P_7H := 200;
   p_Prtct_f_1L := 9750;
   p_Prtct_f_1T := S5T#1M;
   p_Prtct_f_1H := 40;
   p_Prtct_f_2L := 9500;
   p_Prtct_f_2T := S5T#8S;
   p_Prtct_f_2H := 40;
   p_Prtct_f_3L := 9500;
   p_Prtct_f_3T := S5T#6S;
   p_Prtct_f_3H := 40;
   p_Prtct_f_4L := 9500;
   p_Prtct_f_4T := S5T#10S;
   p_Prtct_f_4H := 40;
   p_Prtct_f_5L := 9500;
   p_Prtct_f_5T := S5T#15S;
   p_Prtct_f_5H := 40;
   p_Prtct_f_6L := 9000;
   p_Prtct_f_6T := S5T#1S;
   p_Prtct_f_6H := 40;
   p_Prtct_f_7L := 9000;
   p_Prtct_f_7T := S5T#15S;
   p_Prtct_f_7H := 40;
   p_Prtct_f_8L := 10500;
   p_Prtct_f_8T := S5T#2S;
   p_Prtct_f_8H := 40;
   p_Prtct_V_1L := 9000;
   p_Prtct_V_1T := S5T#5S;
   p_Prtct_V_1H := 150;
   p_Prtct_V_2L := 6875;
   p_Prtct_V_2T := S5T#1S;
   p_Prtct_V_2H := 150;
   p_Prtct_V_3L := 10500;
   p_Prtct_V_3T := S5T#2S;
   p_Prtct_V_3H := 150;
   p_DifCurrent := 7500;
   P_TFCurrent := S5T#10S;
   p_Vblackout := 1500;
   p_Tblackout := S5T#1S;
   p_TFBusbar := S5T#200MS;
   p_VgenVolt := 8500;
   p_TPulse_sc := S5T#5S;
   p_Underload_1 := 3500;
   p_Underload_2 := 4500;
   p_Underload_3 := 5000;
   p_Tunderl_Ind := S5T#30S;
   p_Tunderl_Shd := S5T#1M;
   p_Underload_H := 200;
   p_Underl_Rel := TRUE;
   p_ShD_Overcurr := FALSE;
   p_ShD_RevPower := FALSE;
   p_ShD_Underfrequ := TRUE;
   p_ShD_Undervolt := TRUE;
   p_Blackout_StdbySt2 := FALSE;
   p_ShortCirc_Block := FALSE;
   p_SC_Device_Avail := FALSE;
   p_ChOver_BlOut_f2 := FALSE;
   p_ChOver_BlOut_f6 := TRUE;
   p_ChOver_BlOut_U1 := TRUE;
   p_ChOver_BlOut_U3 := TRUE;
   var1304 := FALSE;
   var1305 := FALSE;
   var1306 := FALSE;
   p_DiffProt_Avail := FALSE;
   var130a := B#16#0;
   p_Rel_WBrk_SD1 := FALSE;
   p_Rel_WBrk_SD2 := FALSE;
   p_Rel_WBrk_SD3 := FALSE;
   p_Rel_WBrk_SD4 := FALSE;
   p_Rel_WBrk_SD5 := FALSE;
   p_Rel_WBrk_SD6 := FALSE;
   p_Rel_WBrk_SD7 := FALSE;
   p_Rel_WBrk_SD8 := FALSE;
   p_Prealarm := FALSE;
   p_SD_StdbySt2 := FALSE;
   p_Sensor_SD2 := TRUE;
   p_GenBrkOff_OvSpeed := FALSE;
   p_EmergStp_OvSpeed := TRUE;
   p_noStpCmd_SD2 := FALSE;
   p_BlackExp_Alrm := FALSE;
   var129 := FALSE;
   p_SD1_Used_DG := TRUE;
   p_SD2_Used_DG := TRUE;
   p_SD3_Used_DG := TRUE;
   p_SD4_Used_DG := FALSE;
   p_SD5_Used_DG := FALSE;
   p_SD6_Used_DG := FALSE;
   p_SD7_Used_DG := FALSE;
   p_SD8_Used_DG := FALSE;
   p_SD1_Delay_DG := FALSE;
   p_SD2_Delay_DG := FALSE;
   p_SD3_Delay_DG := TRUE;
   p_SD4_Delay_DG := FALSE;
   p_SD5_Delay_DG := FALSE;
   p_SD6_Delay_DG := FALSE;
   p_SD7_Delay_DG := FALSE;
   p_SD8_Delay_DG := FALSE;
   p_SD1_Mon1_DG := FALSE;
   p_SD2_Mon1_DG := TRUE;
   p_SD3_Mon1_DG := FALSE;
   p_SD4_Mon1_DG := FALSE;
   p_SD5_Mon1_DG := FALSE;
   p_SD6_Mon1_DG := FALSE;
   p_SD7_Mon1_DG := FALSE;
   p_SD8_Mon1_DG := FALSE;
   p_SD1_Mon2_DG := FALSE;
   p_SD2_Mon2_DG := FALSE;
   p_SD3_Mon2_DG := FALSE;
   p_SD4_Mon2_DG := FALSE;
   p_SD5_Mon2_DG := FALSE;
   p_SD6_Mon2_DG := FALSE;
   p_SD7_Mon2_DG := FALSE;
   p_SD8_Mon2_DG := FALSE;
   p_Tmonit1_DG := 150;
   p_Tmonit2_DG := 50;
   p_TSD1_DG := 0;
   p_TSD2_DG := 10;
   p_TSD3_DG := 10;
   p_TSD4_DG := 10;
   p_TSD5_DG := 10;
   p_TSD6_DG := 10;
   p_TSD7_DG := 10;
   p_TSD8_DG := 10;
   p_TSensor_SD2 := 200;
   var132 := B#16#0;
   p_uploadLatch := FALSE;
   var13212 := FALSE;
   var13213 := FALSE;
   var13214 := FALSE;
   var13215 := FALSE;
   var13216 := FALSE;
   var13217 := FALSE;
   var1321 := FALSE;
   p_runupLoad := 1.000000e+000;
   p_rundownLoad := 1.000000e+000;
   p_period_deload := 40;
   p_puls_deload := 10;
   p_f_static_zero := 5.000000e+001;
   p_f_static_hund := 5.000000e+001;
   p_Ctrl_Kp := 1.000000e+000;
   p_Ctrl_FreqQuality := 2.000000e+000;
   p_Ctrl_dead_lim := 1.000000e+000;
   f_Ctrl_shortP_lim := 5.000000e+000;
   f_Ctrl_limSet := 3.000000e+001;
   p_Ctrl_longP_lim := 2.000000e+001;
   p_Ctrl_sP_pulse := 1;
   p_Ctrl_sP_period := 20;
   p_Ctrl_lP_pulse := 6;
   p_Ctrl_lP_period := 20;
   p_GBoff_Load := 20;
   p_setLoad_G1 := 940;
   p_setLoad_G2 := 940;
   p_setLoad_G3 := 1090;
   p_setLoad_G4 := 0;
   p_setLoad_G5 := 0;
   p_setLoad_G6 := 0;
   p_setLoad_G7 := 0;
   p_setLoad_G8 := 0;
   p_setLoad_G9 := 0;
   p_setLoad_G10 := 0;
   p_setLoad_G11 := 0;
   p_setLoad_G12 := 0;
   p_setLoad_G13 := 0;
   p_setLoad_EG := 180;
   p_OUTconCtrl := 0;
   p_nomFreq := 500;
   p_nomVolt := 400;
   p_nomCurr := 1692;
   p_minLoad := 282;
   p_NomPower_Gen := 940;
   p_LimCurrMonit := 300;
   var151 := DW#16#0;
   var152 := DW#16#0;
   p_runUBLmin := 1.000000e+000;
   p_Prtct_V_4L := 11000;
   p_Prtct_V_4T := S5T#1S;
   p_Prtct_V_4H := 150;
   p_TInd_Blackout := S5T#1M;
   p_TRevPower_Warn := S5T#1S;
   p_TWinD_Overtemp := S5T#10S;
   p_TShCirc_OtherGen := S5T#1S;
   p_TShC_OtherGen_Reset := S5T#1M20S;
   p_UBLmax_prcDef := 8000;
   p_UBLmin_prcDef := 3000;
   p_dlyDeviAlrm := S5T#10M;
   p_TIgnSpeed_Off := 10;
   p_deviMax := 2.500000e+001;
   var156 := 0;
   var157 := 0;
   p_wood_Isochron := FALSE;
   p_wood_IsochronAuto := FALSE;
   p_wood_IsochronExt := FALSE;
   p_wood_IsochronLowAct := FALSE;
   var1584 := FALSE;
   var1585 := FALSE;
   var1586 := FALSE;
   var1587 := FALSE;
   var1588 := B#16#0;
   var159 := 0;
   p_heavyConsumer_1 := 0;
   p_heavyConsumer_2 := 0;
   p_heavyConsumer_3 := 0;
   p_heavyConsumer_4 := 0;
   p_heavyConsumer_5 := 0;
   p_heavyConsumer_6 := 0;
   p_heavyConsumer_7 := 0;
   p_heavyConsumer_8 := 0;
   var168 := 0;
   p_TTrLBrk_Voltl := S5T#20S;
   c_GW1_BLO_E := TRUE;
   c_GW2_BLO_E := FALSE;
   c_GW3_BLO_E := TRUE;
   c_GW4_BLO_E := TRUE;
   c_GW5_BLO_E := TRUE;
   c_GW6_BLO_E := FALSE;
   var169a := FALSE;
   var169b := FALSE;
   c_GW1_BLO_H := FALSE;
   c_GW2_BLO_H := FALSE;
   c_GW3_BLO_H := FALSE;
   c_GW4_BLO_H := FALSE;
   c_GW5_BLO_H := FALSE;
   c_GW6_BLO_H := FALSE;
   var169c := FALSE;
   var169d := FALSE;
   c_GW1_BLO_F := FALSE;
   c_GW2_BLO_F := FALSE;
   c_GW3_BLO_F := FALSE;
   c_GW4_BLO_F := FALSE;
   c_GW5_BLO_F := FALSE;
   c_GW6_BLO_F := FALSE;
   var169e := FALSE;
   var169f := FALSE;
   var170a := B#16#0;
   var171 := B#16#0;
   p_Prtct_i_1_Active_E := TRUE;
   p_Prtct_i_2_Active_E := TRUE;
   p_Prtct_i_3_Active_E := FALSE;
   p_Prtct_i_4_Active_E := FALSE;
   p_Prtct_i_5_Active_E := FALSE;
   p_Prtct_i_6_Active_E := FALSE;
   p_Prtct_i_7_Active_E := TRUE;
   var1711 := FALSE;
   var172 := B#16#0;
   p_Prtct_P_1_Active_E := TRUE;
   p_Prtct_P_2_Active_E := TRUE;
   p_Prtct_P_3_Active_E := FALSE;
   p_Prtct_P_4_Active_E := FALSE;
   p_Prtct_P_5_Active_E := FALSE;
   p_Prtct_P_6_Active_E := FALSE;
   p_Prtct_P_7_Active_E := FALSE;
   p_Prtct_P_8_Active_E := FALSE;
   var173 := B#16#0;
   p_Prtct_f_1_Active_E := TRUE;
   p_Prtct_f_2_Active_E := TRUE;
   p_Prtct_f_3_Active_E := FALSE;
   p_Prtct_f_4_Active_E := FALSE;
   p_Prtct_f_5_Active_E := FALSE;
   p_Prtct_f_6_Active_E := FALSE;
   p_Prtct_f_7_Active_E := FALSE;
   p_Prtct_f_8_Active_E := TRUE;
   var174 := B#16#0;
   p_Prtct_V_1_Active_E := TRUE;
   p_Prtct_V_2_Active_E := FALSE;
   p_Prtct_V_3_Active_E := TRUE;
   p_Prtct_V_4_Active_E := FALSE;
   var1741 := FALSE;
   var1742 := FALSE;
   var1743 := FALSE;
   var1744 := FALSE;
   var175 := B#16#0;
   p_Prtct_i_1_Active_H := TRUE;
   p_Prtct_i_2_Active_H := TRUE;
   p_Prtct_i_3_Active_H := FALSE;
   p_Prtct_i_4_Active_H := FALSE;
   p_Prtct_i_5_Active_H := FALSE;
   p_Prtct_i_6_Active_H := FALSE;
   p_Prtct_i_7_Active_H := TRUE;
   var1751 := FALSE;
   var176 := B#16#0;
   p_Prtct_P_1_Active_H := TRUE;
   p_Prtct_P_2_Active_H := TRUE;
   p_Prtct_P_3_Active_H := TRUE;
   p_Prtct_P_4_Active_H := TRUE;
   p_Prtct_P_5_Active_H := TRUE;
   p_Prtct_P_6_Active_H := TRUE;
   p_Prtct_P_7_Active_H := TRUE;
   p_Prtct_P_8_Active_H := FALSE;
   var177 := B#16#0;
   p_Prtct_f_1_Active_H := TRUE;
   p_Prtct_f_2_Active_H := TRUE;
   p_Prtct_f_3_Active_H := TRUE;
   p_Prtct_f_4_Active_H := TRUE;
   p_Prtct_f_5_Active_H := TRUE;
   p_Prtct_f_6_Active_H := TRUE;
   p_Prtct_f_7_Active_H := TRUE;
   p_Prtct_f_8_Active_H := TRUE;
   var178 := B#16#0;
   p_Prtct_V_1_Active_H := TRUE;
   p_Prtct_V_2_Active_H := TRUE;
   p_Prtct_V_3_Active_H := TRUE;
   p_Prtct_V_4_Active_H := TRUE;
   var1781 := FALSE;
   var1782 := FALSE;
   var1783 := FALSE;
   var1784 := FALSE;
   var179 := B#16#0;
   p_Prtct_i_1_Active_F := TRUE;
   p_Prtct_i_2_Active_F := TRUE;
   p_Prtct_i_3_Active_F := FALSE;
   p_Prtct_i_4_Active_F := FALSE;
   p_Prtct_i_5_Active_F := FALSE;
   p_Prtct_i_6_Active_F := FALSE;
   p_Prtct_i_7_Active_F := TRUE;
   var1791 := FALSE;
   var180 := B#16#0;
   p_Prtct_P_1_Active_F := TRUE;
   p_Prtct_P_2_Active_F := TRUE;
   p_Prtct_P_3_Active_F := TRUE;
   p_Prtct_P_4_Active_F := TRUE;
   p_Prtct_P_5_Active_F := TRUE;
   p_Prtct_P_6_Active_F := TRUE;
   p_Prtct_P_7_Active_F := TRUE;
   p_Prtct_P_8_Active_F := FALSE;
   var1801 := B#16#0;
   p_Prtct_f_1_Active_F := TRUE;
   p_Prtct_f_2_Active_F := TRUE;
   p_Prtct_f_3_Active_F := TRUE;
   p_Prtct_f_4_Active_F := TRUE;
   p_Prtct_f_5_Active_F := TRUE;
   p_Prtct_f_6_Active_F := TRUE;
   p_Prtct_f_7_Active_F := TRUE;
   p_Prtct_f_8_Active_F := TRUE;
   var1815 := B#16#0;
   p_Prtct_V_1_Active_F := TRUE;
   p_Prtct_V_2_Active_F := TRUE;
   p_Prtct_V_3_Active_F := TRUE;
   p_Prtct_V_4_Active_F := TRUE;
   var18111 := FALSE;
   var18121 := FALSE;
   var18131 := FALSE;
   var18141 := FALSE;
   p_SD1_Used_EG_E := TRUE;
   p_SD2_Used_EG_E := TRUE;
   p_SD3_Used_EG_E := TRUE;
   p_SD4_Used_EG_E := TRUE;
   p_SD5_Used_EG_E := FALSE;
   p_SD6_Used_EG_E := FALSE;
   p_SD7_Used_EG_E := FALSE;
   p_SD8_Used_EG_E := FALSE;
   p_SD1_Delay_EG_E := FALSE;
   p_SD2_Delay_EG_E := FALSE;
   p_SD3_Delay_EG_E := FALSE;
   p_SD4_Delay_EG_E := FALSE;
   p_SD5_Delay_EG_E := FALSE;
   p_SD6_Delay_EG_E := FALSE;
   p_SD7_Delay_EG_E := FALSE;
   p_SD8_Delay_EG_E := FALSE;
   p_SD1_Mon1_EG_E := FALSE;
   p_SD2_Mon1_EG_E := TRUE;
   p_SD3_Mon1_EG_E := FALSE;
   p_SD4_Mon1_EG_E := FALSE;
   p_SD5_Mon1_EG_E := FALSE;
   p_SD6_Mon1_EG_E := FALSE;
   p_SD7_Mon1_EG_E := FALSE;
   p_SD8_Mon1_EG_E := FALSE;
   p_SD1_Mon2_EG_E := FALSE;
   p_SD2_Mon2_EG_E := FALSE;
   p_SD3_Mon2_EG_E := FALSE;
   p_SD4_Mon2_EG_E := FALSE;
   p_SD5_Mon2_EG_E := FALSE;
   p_SD6_Mon2_EG_E := FALSE;
   p_SD7_Mon2_EG_E := FALSE;
   p_SD8_Mon2_EG_E := FALSE;
   p_SD1_Used_EG_H := TRUE;
   p_SD2_Used_EG_H := TRUE;
   p_SD3_Used_EG_H := TRUE;
   p_SD4_Used_EG_H := TRUE;
   p_SD5_Used_EG_H := FALSE;
   p_SD6_Used_EG_H := FALSE;
   p_SD7_Used_EG_H := FALSE;
   p_SD8_Used_EG_H := FALSE;
   p_SD1_Delay_EG_H := FALSE;
   p_SD2_Delay_EG_H := FALSE;
   p_SD3_Delay_EG_H := FALSE;
   p_SD4_Delay_EG_H := FALSE;
   p_SD5_Delay_EG_H := FALSE;
   p_SD6_Delay_EG_H := FALSE;
   p_SD7_Delay_EG_H := FALSE;
   p_SD8_Delay_EG_H := FALSE;
   p_SD1_Mon1_EG_H := FALSE;
   p_SD2_Mon1_EG_H := TRUE;
   p_SD3_Mon1_EG_H := FALSE;
   p_SD4_Mon1_EG_H := FALSE;
   p_SD5_Mon1_EG_H := FALSE;
   p_SD6_Mon1_EG_H := FALSE;
   p_SD7_Mon1_EG_H := FALSE;
   p_SD8_Mon1_EG_H := FALSE;
   p_SD1_Mon2_EG_H := FALSE;
   p_SD2_Mon2_EG_H := FALSE;
   p_SD3_Mon2_EG_H := FALSE;
   p_SD4_Mon2_EG_H := FALSE;
   p_SD5_Mon2_EG_H := FALSE;
   p_SD6_Mon2_EG_H := FALSE;
   p_SD7_Mon2_EG_H := FALSE;
   p_SD8_Mon2_EG_H := FALSE;
   p_SD1_Used_EG_F := TRUE;
   p_SD2_Used_EG_F := TRUE;
   p_SD3_Used_EG_F := TRUE;
   p_SD4_Used_EG_F := TRUE;
   p_SD5_Used_EG_F := FALSE;
   p_SD6_Used_EG_F := FALSE;
   p_SD7_Used_EG_F := FALSE;
   p_SD8_Used_EG_F := FALSE;
   p_SD1_Delay_EG_F := FALSE;
   p_SD2_Delay_EG_F := FALSE;
   p_SD3_Delay_EG_F := FALSE;
   p_SD4_Delay_EG_F := FALSE;
   p_SD5_Delay_EG_F := FALSE;
   p_SD6_Delay_EG_F := FALSE;
   p_SD7_Delay_EG_F := FALSE;
   p_SD8_Delay_EG_F := FALSE;
   p_SD1_Mon1_EG_F := FALSE;
   p_SD2_Mon1_EG_F := TRUE;
   p_SD3_Mon1_EG_F := FALSE;
   p_SD4_Mon1_EG_F := FALSE;
   p_SD5_Mon1_EG_F := FALSE;
   p_SD6_Mon1_EG_F := FALSE;
   p_SD7_Mon1_EG_F := FALSE;
   p_SD8_Mon1_EG_F := FALSE;
   p_SD1_Mon2_EG_F := FALSE;
   p_SD2_Mon2_EG_F := FALSE;
   p_SD3_Mon2_EG_F := FALSE;
   p_SD4_Mon2_EG_F := FALSE;
   p_SD5_Mon2_EG_F := FALSE;
   p_SD6_Mon2_EG_F := FALSE;
   p_SD7_Mon2_EG_F := FALSE;
   p_SD8_Mon2_EG_F := FALSE;
   p_TrsBrk_No := B#16#0;
   p_2ndGenBrkON_auto := TRUE;
   var170111 := FALSE;
   var170121 := FALSE;
   var170131 := FALSE;
   var170141 := FALSE;
   var170151 := FALSE;
   var170161 := FALSE;
   var170171 := FALSE;
   p_SwitchBack_Lock := FALSE;
   p_unessConsumI_avail := FALSE;
   p_unessConsumII_avail := FALSE;
   p_unessConsumIII_avail := FALSE;
   p_P_F_Cntrl_avail := FALSE;
   var6025 := FALSE;
   p_HarbourMode := FALSE;
   p_PowerFdbMode := FALSE;
   P_Overcur_WindTempHigh := FALSE;
   var60281 := FALSE;
   var60282 := FALSE;
   var60283 := FALSE;
   var60284 := FALSE;
   var60285 := FALSE;
   var60286 := FALSE;
   var60287 := FALSE;
   p_TNoVoltTrL := 50;
   p_TPulseTrLGenBrk := 50;
   p_TReturnVoltTrL := 600;
   p_TGenBrk_TrLBrk := 30;
   p_TTrLBrk_GenBrk := 30;
   p_TTrLBrkReady := 100;
   p_TTrLBrkOn := 20;
   p_TTrLBrkOff := 30;
   p_TTrLBrkFbOn := 10;
   p_TTrLBrkFbOff := 10;
   p_TAuxil := 600;
   p_WarnRelCnd_1 := B#16#3;
   p_WarnRelCnd_2 := B#16#4;
   p_WarnRelUncnd := B#16#18;
   p_WarnRel_1_T := S5T#0MS;
   p_WarnRel_2_T := S5T#0MS;
   p_WarnDly_C1 := S5T#2S;
   p_WarnDly_C2 := S5T#2S;
   p_WarnDly_C3 := S5T#2S;
   p_WarnDly_C4 := S5T#2S;
   p_WarnDly_C5 := S5T#2S;
   p_WarnDly_C6 := S5T#2S;
   p_WarnDly_C7 := S5T#2S;
   p_WarnDly_C8 := S5T#2S;
   p_dlyT_GenBrkTrip := S5T#10S;
   p_dlyT_TrsBrkTrip := S5T#3S;
   p_dlyT_GenBrkReady := S5T#1S;
   p_dlyT_TrsBrkReady := S5T#1S;
   var192 := 0;
   p_noSlaveTie := FALSE;
   p_OnNotShoreOn := FALSE;
   p_TieBrkOffBlack := FALSE;
   p_allowGen_Rel := FALSE;
   p_ShoreExpBoth_TBclse := FALSE;
   p_blackout_BrkOff := FALSE;
   p_TieBrkOnBlack := FALSE;
   p_noStdbyStrt := FALSE;
   p_allowGen := 0;
   p_dlyT_opntiebrk := S5T#30S;
   p_SlvBrkCtrl := FALSE;
   p_noStdByStart := TRUE;
   var210a13 := FALSE;
   var210a14 := FALSE;
   var210a15 := FALSE;
   var210a16 := FALSE;
   var210a17 := FALSE;
   var210a18 := FALSE;
   var210a11 := B#16#0;
   p_diffVolt := 0;
   p_noVoltAdjust := TRUE;
   p_noRevP_Prtct := TRUE;
   p_ShCopn_noDeload := TRUE;
   p_noBlackContact_ShC := TRUE;
   p_adjustVolt_untilEq := FALSE;
   var300f := FALSE;
   var300g := FALSE;
   var300h := FALSE;
   var3011 := B#16#0;
   p_monT_adjustVolt := S5T#20S;
   p_monT_stpGenSet := S5T#2M;
   p_monT_takeLoad := S5T#2M;
   p_pulse_stpGenSet := S5T#5S;
   p_dlyT_adjustVolt := S5T#10S;
   p_allowVoltDiff := 5;
   p_monT_GenSetOnBus := S5T#1M;
   p_monT_SlvBrk := 50;
   p_pulse_SlvBrk := 20;
   p_GenBrk_LoadRed_2nd := TRUE;
   var400b := FALSE;
   var400c := FALSE;
   var400d := FALSE;
   var400e := FALSE;
   var400f := FALSE;
   var400g := FALSE;
   var400h := FALSE;
   p_Monit_BrkReady_2nd := TRUE;
   P_Monit_BrkPosNorm_2nd := FALSE;
   p_Monit_BrkPosTest_2nd := FALSE;
   p_noBrkOffSign_2nd := FALSE;
   p_GenBrk_ShoreBlock_2nd := FALSE;
   p_GenBrk_OUTviaGENOP_2nd := TRUE;
   p_BlockMonitBrkTrip_2nd := TRUE;
   p_noBrkONSign_2nd := TRUE;
   p_TgenBrkReady_2nd := 100;
   p_TgenBrkSimOn_2nd := 20;
   p_TgenBrkRel_2nd := 50;
   P_TgenBrkSyn_2nd := 600;
   p_TgenBrkLoadOff_2nd := 3000;
   p_TgenBrkTrip_2nd := 1;
   p_TgenBrkOn_2nd := 10;
   p_TgenBrkOff_2nd := 40;
   p_TgenBrkFbOn_2nd := 10;
   p_TgenBrkFbOff_2nd := 10;
   p_TgenBrkFbOffOn_2nd := 20;
   p_dlyT_adj_V_swon := S5T#100MS;
   p_dlyT_adj_V_swoff := S5T#100MS;
   var404 := W#16#0;
   p_Tunderl_Ind_2nd := S5T#30S;
   p_Tunderl_Shd_2nd := S5T#1M;
   p_Underload_H_2nd := 200;
   p_Underl_Rel_2nd := TRUE;
   p_ShD_Overcurr_2nd := FALSE;
   p_ShD_RevPower_2nd := FALSE;
   p_ShD_Underfrequ_2nd := FALSE;
   p_ShD_Undervolt_2nd := FALSE;
   p_Blackout_StdbySt2_2nd := FALSE;
   p_ShortCirc_Block_2nd := FALSE;
   p_SC_Device_Avail_2nd := FALSE;
   p_ChOver_BlOut_f2_2nd := FALSE;
   p_ChOver_BlOut_f6_2nd := TRUE;
   p_ChOver_BlOut_U1_2nd := TRUE;
   p_ChOver_BlOut_U3_2nd := TRUE;
   var405e := FALSE;
   var405f := FALSE;
   var405g := FALSE;
   p_DiffProt_Avail_2nd := FALSE;
   p_Prtct_i_1L_2nd := 9500;
   p_Prtct_i_1T_2nd := S5T#30S;
   p_Prtct_i_1H_2nd := 200;
   p_Prtct_i_2L_2nd := 10000;
   p_Prtct_i_2T_2nd := S5T#5S;
   p_Prtct_i_2H_2nd := 200;
   p_Prtct_i_6L_2nd := 12000;
   p_Prtct_i_6T_2nd := S5T#1S;
   p_Prtct_i_6H_2nd := 200;
   p_Prtct_i_7L_2nd := 11000;
   p_Prtct_i_7T_2nd := S5T#30S;
   p_Prtct_i_7H_2nd := 200;
   p_Prtct_P_1L_2nd := 9500;
   p_Prtct_P_1T_2nd := S5T#30S;
   p_Prtct_P_1H_2nd := 200;
   p_Prtct_P_2L_2nd := 10500;
   p_Prtct_P_2T_2nd := S5T#5S;
   p_Prtct_P_2H_2nd := 200;
   p_Prtct_P_3L_2nd := 10500;
   p_Prtct_P_3T_2nd := S5T#5S;
   p_Prtct_P_3H_2nd := 200;
   p_Prtct_P_4L_2nd := 10500;
   p_Prtct_P_4T_2nd := S5T#10S;
   p_Prtct_P_4H_2nd := 200;
   p_Prtct_P_5L_2nd := 10500;
   p_Prtct_P_5T_2nd := S5T#15S;
   p_Prtct_P_5H_2nd := 200;
   p_Prtct_P_6L_2nd := 11000;
   p_Prtct_P_6T_2nd := S5T#1S;
   p_Prtct_P_6H_2nd := 200;
   p_Prtct_f_1L_2nd := 9750;
   p_Prtct_f_1T_2nd := S5T#1M;
   p_Prtct_f_1H_2nd := 40;
   p_Prtct_f_2L_2nd := 9500;
   p_Prtct_f_2T_2nd := S5T#8S;
   p_Prtct_f_2H_2nd := 40;
   p_Prtct_f_3L_2nd := 9500;
   p_Prtct_f_3T_2nd := S5T#6S;
   p_Prtct_f_3H_2nd := 40;
   p_Prtct_f_4L_2nd := 9500;
   p_Prtct_f_4T_2nd := S5T#10S;
   p_Prtct_f_4H_2nd := 40;
   p_Prtct_f_5L_2nd := 9500;
   p_Prtct_f_5T_2nd := S5T#15S;
   p_Prtct_f_5H_2nd := 40;
   p_Prtct_f_6L_2nd := 9000;
   p_Prtct_f_6T_2nd := S5T#1S;
   p_Prtct_f_6H_2nd := 40;
   p_Prtct_f_7L_2nd := 9000;
   p_Prtct_f_7T_2nd := S5T#15S;
   p_Prtct_f_7H_2nd := 40;
   p_Prtct_f_8L_2nd := 10500;
   p_Prtct_f_8T_2nd := S5T#2S;
   p_Prtct_f_8H_2nd := 40;
   p_Prtct_V_1L_2nd := 9000;
   p_Prtct_V_1T_2nd := S5T#5S;
   p_Prtct_V_1H_2nd := 150;
   p_Prtct_V_2L_2nd := 6875;
   p_Prtct_V_2T_2nd := S5T#1S;
   p_Prtct_V_2H_2nd := 150;
   p_Prtct_V_3L_2nd := 10500;
   p_Prtct_V_3T_2nd := S5T#2S;
   p_Prtct_V_3H_2nd := 150;
   p_Prtct_V_4L_2nd := 11000;
   p_Prtct_V_4T_2nd := S5T#1S;
   p_Prtct_V_4H_2nd := 150;
   p_DifCurrent_2nd := 7500;
   P_TFCurrent_2nd := S5T#10S;
   p_Vblackout_2nd := 1500;
   p_Tblackout_2nd := S5T#1S;
   p_TFBusbar_2nd := S5T#200MS;
   p_VgenVolt_2nd := 8500;
   p_TgenVolt_2nd := S5T#10S;
   p_Underload_1_2nd := 3500;
   p_Underload_2_2nd := 4500;
   p_Underload_3_2nd := 5000;
   p_TWinD_Overtemp_2nd := S5T#10S;
   p_TShCirc_OtherGen_2nd := S5T#1S;
   p_TShC_OtherGen_Rst_2nd := S5T#1M20S;
   p_nomFreq_2nd := 500;
   p_nomVolt_2nd := 400;
   p_nomCurr_2nd := 1692;
   p_NomPower_Gen_2nd := 940;
   p_var8864 := W#16#0;
   p_var8865 := W#16#0;
   p_var888 := W#16#0;
   p_waitT_blackout_MSB := S5T#100MS;
   p_monT_restoreTieBrk := S5T#5M;
   p_TrsLine := TRUE;
   p_var09060 := 0;
   p_var09080 := 0;
   p_SG_Deexcit_Under_Frec := 480;
END_DATA_BLOCK




DATA_BLOCK "diagn"
TITLE =Diagnostic data: link state
AUTHOR : Kahle
FAMILY : PMA71
NAME : DiagDP
VERSION : 1.0


  STRUCT
   DP_Diag : ARRAY  [1 .. 3 ] OF //=1:Master 315DP, =2:Slave Genop71, =3:Master OP7
   STRUCT
    StationState1 : BYTE ;
    StationState2 : BYTE ;
    StationState3 : BYTE ;
    MasterNo : BYTE ;
    VendorID : WORD ;
    res01 : DWORD ;
    res02 : DWORD ;
    res03 : DWORD ;
    res04 : WORD ;
   END_STRUCT ;
   BinErrMPI : DWORD ;  //binary errorcode MPI (.0-.3:T1-4/.4-.16:G1-13/.17:EG/.18-.19:S1-2)
   ErrCodeMPI : ARRAY  [1 .. 20 ] OF //=1..=4:T1-4/=5..=17:G1-13/=18:EG/=19..=20:S1-2
   INT ;
   DP_Diag2 : ARRAY  [1 .. 3 ] OF //=1: ---, =2:Slave Genop71 unit 2, =3:Master OP7 unit 2
   STRUCT
    StationState1 : BYTE ;
    StationState2 : BYTE ;
    StationState3 : BYTE ;
    MasterNo : BYTE ;
    VendorID : WORD ;
    res01 : DWORD ;
    res02 : DWORD ;
    res03 : DWORD ;
    res04 : WORD ;
   END_STRUCT ;
  END_STRUCT ;
BEGIN
   DP_Diag[1].StationState1 := B#16#0;
   DP_Diag[1].StationState2 := B#16#0;
   DP_Diag[1].StationState3 := B#16#0;
   DP_Diag[1].MasterNo := B#16#0;
   DP_Diag[1].VendorID := W#16#0;
   DP_Diag[1].res01 := DW#16#0;
   DP_Diag[1].res02 := DW#16#0;
   DP_Diag[1].res03 := DW#16#0;
   DP_Diag[1].res04 := W#16#0;
   DP_Diag[2].StationState1 := B#16#0;
   DP_Diag[2].StationState2 := B#16#0;
   DP_Diag[2].StationState3 := B#16#0;
   DP_Diag[2].MasterNo := B#16#0;
   DP_Diag[2].VendorID := W#16#0;
   DP_Diag[2].res01 := DW#16#0;
   DP_Diag[2].res02 := DW#16#0;
   DP_Diag[2].res03 := DW#16#0;
   DP_Diag[2].res04 := W#16#0;
   DP_Diag[3].StationState1 := B#16#0;
   DP_Diag[3].StationState2 := B#16#0;
   DP_Diag[3].StationState3 := B#16#0;
   DP_Diag[3].MasterNo := B#16#0;
   DP_Diag[3].VendorID := W#16#0;
   DP_Diag[3].res01 := DW#16#0;
   DP_Diag[3].res02 := DW#16#0;
   DP_Diag[3].res03 := DW#16#0;
   DP_Diag[3].res04 := W#16#0;
   BinErrMPI := DW#16#0;
   ErrCodeMPI[1] := 0;
   ErrCodeMPI[2] := 0;
   ErrCodeMPI[3] := 0;
   ErrCodeMPI[4] := 0;
   ErrCodeMPI[5] := 0;
   ErrCodeMPI[6] := 0;
   ErrCodeMPI[7] := 0;
   ErrCodeMPI[8] := 0;
   ErrCodeMPI[9] := 0;
   ErrCodeMPI[10] := 0;
   ErrCodeMPI[11] := 0;
   ErrCodeMPI[12] := 0;
   ErrCodeMPI[13] := 0;
   ErrCodeMPI[14] := 0;
   ErrCodeMPI[15] := 0;
   ErrCodeMPI[16] := 0;
   ErrCodeMPI[17] := 0;
   ErrCodeMPI[18] := 0;
   ErrCodeMPI[19] := 0;
   ErrCodeMPI[20] := 0;
   DP_Diag2[1].StationState1 := B#16#0;
   DP_Diag2[1].StationState2 := B#16#0;
   DP_Diag2[1].StationState3 := B#16#0;
   DP_Diag2[1].MasterNo := B#16#0;
   DP_Diag2[1].VendorID := W#16#0;
   DP_Diag2[1].res01 := DW#16#0;
   DP_Diag2[1].res02 := DW#16#0;
   DP_Diag2[1].res03 := DW#16#0;
   DP_Diag2[1].res04 := W#16#0;
   DP_Diag2[2].StationState1 := B#16#0;
   DP_Diag2[2].StationState2 := B#16#0;
   DP_Diag2[2].StationState3 := B#16#0;
   DP_Diag2[2].MasterNo := B#16#0;
   DP_Diag2[2].VendorID := W#16#0;
   DP_Diag2[2].res01 := DW#16#0;
   DP_Diag2[2].res02 := DW#16#0;
   DP_Diag2[2].res03 := DW#16#0;
   DP_Diag2[2].res04 := W#16#0;
   DP_Diag2[3].StationState1 := B#16#0;
   DP_Diag2[3].StationState2 := B#16#0;
   DP_Diag2[3].StationState3 := B#16#0;
   DP_Diag2[3].MasterNo := B#16#0;
   DP_Diag2[3].VendorID := W#16#0;
   DP_Diag2[3].res01 := DW#16#0;
   DP_Diag2[3].res02 := DW#16#0;
   DP_Diag2[3].res03 := DW#16#0;
   DP_Diag2[3].res04 := W#16#0;
END_DATA_BLOCK

DATA_BLOCK "S_visuSR"
TITLE =Store previous value's of the visualization interface
//
//                                                                                                   !
// I_MMI_SR
// Sende-/Empfangsfach MMI
//  Im 1.Teil des DB's liegt das Sendefach, während das Empfangsfach sich im zweiten Teil
//  befindet.
//
//  Der DB ist die zentrale Schnittstelle zwischen Bediener und PMA-Steuerung. Die Daten des
//  Sendefaches werden in Abhängigkeit des Bedienortes (OP, BuB) in die entsprechenden
//  Ausgangsfächer transferiert, während umgekehrt die Daten in das Empfangsfach kopiert werden.
//
//  Die Parameter werden nicht über diese Schnittstelle (I_MMI_SR) geführt, sondern direkt in den
//  Parameter-DB der PMA (prm_pma) transferiert, bzw. von dort abgeholt.
//
//  Daten, die das Generatorschutzgerät (Genop71) betreffen werden ebenfalls direkt in dessen
//  Sendefach (I_prtcSR)geschrieben bzw. werden direkt aus dessen Empfangsfach(I_prtcSR) ausgelesen.
//
//  Siemens AG ATD IS3T, Kahle +494028892022, jens.kahle@hbg.siemens.de
//  PMA71
//  =Internal Modul Memory
//  Datum aktuelle Version: 20.02.99
//  Version,Änd-Datum, Bearbeiter, geänderte Variablen
//  1.01   ,31.01.99 , Kahle     , 1.Version
//  1.02   ,20.02.99 , Kahle     , Anwahl Konfigurationen
//
//KNOW_HOW_PROTECT
// (If specified, no more changes can be made once the block is generated)
//UNLINKED
// (If specified, the generated block is only available in the PLC load
//  memory)
//READ_ONLY
// (If specified, the generated block cannot be changed in the programmable
//  controller)
AUTHOR : Kahle
FAMILY : PMA71
NAME : I_OP_SR
VERSION : 1.2


  STRUCT
   var01 : BOOL ;
   var02 : BOOL ;
   var03 : BOOL ;
   var04 : BOOL ;
   var05 : BOOL ;
   var06 : BOOL ;
   var07 : BOOL ;
   var08 : BOOL ;
   i_Dstrt : BOOL ; //Meldung: Diesel läuft
   i_Dstp : BOOL ;  //Meldung: Diesel steht
   var09 : BOOL ;
   var10 : BOOL ;
   var11 : BOOL ;
   var12 : BOOL ;
   var13 : BOOL ;
   var14 : BOOL ;
   i_brkClse : BOOL ;   //Meldung: GenSch geschlossen
   i_brkOpn : BOOL ;    //Meldung: GenSch geöffnet
   i_UnitActive : BOOL ;    //Meldung: Aggregat am Netz
   i_UnitDeactiv : BOOL ;   //Meldung: Aggregat steht
   i_1UnitOnBus : BOOL ;    //Meldung: nur ein Aggregat am (Teil-)netz
   var15 : BOOL ;
   var16 : BOOL ;
   var17 : BOOL ;
   var18 : BOOL ;
   var19 : BOOL ;
   var20 : BOOL ;
   var21 : BOOL ;
   var22 : BOOL ;
   var23 : BOOL ;
   var24 : BOOL ;
   var25 : BOOL ;
   var26 : BOOL ;
   var27 : BOOL ;
   var28 : BOOL ;
   var29 : BOOL ;
   var30 : BOOL ;
   var31 : BOOL ;
   var32 : BOOL ;
   var33 : BOOL ;
   i_LFCtrlOn : BOOL ;  //Meldung: Wirklast-/Frequenzregler aktiv
   i_FCtrlLock : BOOL ; //Meldung: Frequenzregler gesperrt
   i_LCtrlLock : BOOL ; //Meldung: Wirklastregler gesperrt
   i_UBLOn : BOOL ; //Meldung: UBL Mode aktiv
   i_UBLMin : BOOL ;    //Meldung: Aggregat auf Mindestlast
   i_UBL_Unit : BOOL ;  //Meldung: Aggregat auf Schieflast
   var34 : BOOL ;
   var35 : BOOL ;
   var36 : BOOL ;
   var37 : BOOL ;
   var38 : BOOL ;
   var39 : BOOL ;
   var40 : BOOL ;
   var41 : BOOL ;
   var42 : BOOL ;
   var43 : BOOL ;
   var44 : BOOL ;
   var45 : BOOL ;
   var46 : BOOL ;
   var47 : BOOL ;
   var48 : BOOL ;
   var49 : BOOL ;
   var50 : BOOL ;
   var51 : BOOL ;
   i_Mod2GenOn : BOOL ; //Meldung: Mode '2 Generatoren am Netz'
   i_Mod3GenOn : BOOL ; //Meldung: Mode '3 Generatoren am Netz'
   i_Mod4GenOn : BOOL ; //Meldung: Mode '4 Generatoren am Netz'
   i_Mod5GenOn : BOOL ; //Meldung: Mode '5 Generatoren am Netz'
   i_Mod6GenOn : BOOL ; //Meldung: Mode '6 Generatoren am Netz'
   i_Mod7GenOn : BOOL ; //Meldung: Mode '7 Generatoren am Netz'
   i_Mod8GenOn : BOOL ; //Meldung: Mode '8 Generatoren am Netz'
   i_ModPreGen : BOOL ; //Meldung: Mode 'Anwahl n Generatoren' angewählt
   var52 : BOOL ;
   var53 : BOOL ;
   var54 : BOOL ;
   var55 : BOOL ;
   var56 : BOOL ;
   var57 : BOOL ;
   var58 : BOOL ;
   var59 : BOOL ;
   i_tieA_noUnit : BOOL ; //Meldung: Kuppelschalter: Teilnetz A -kein Aggregat am Netz
   i_tieB_noUnit : BOOL ;   //Meldung: Kuppelschalter: Teilnetz B -kein Aggregat am Netz
   i_tie_A_i_SC : BOOL ;    //Meldung: Kuppelschalter: Kurzschluß Teilnetz A
   i_tie_B_i_SC : BOOL ;    //Meldung: Kuppelschalter: Kurzschluß Teilnetz B
   i_tieNoAnyAut : BOOL ;   //Meldung: Kuppelschalter: Nicht alle Aggregat in Automatik
   var60 : BOOL ;
   var61 : BOOL ;
   var62 : BOOL ;
   i_shoreMode : BOOL ; //Meldung: Landanschlußbetrieb
   i_shore_clse : BOOL ;    //Meldung: Landanschlußschalter geschlossen
   i_shore_opn : BOOL ; //Meldung: Landanschlußschalter geöffnet
   i_shore_avail : BOOL ;   //Meldung: Landanschluß verfügbar
   var63 : BOOL ;
   var64 : BOOL ;
   var65 : BOOL ;
   var66 : BOOL ;
   var67 : BOOL ;
   var68 : BOOL ;
   var69 : BOOL ;
   var70 : BOOL ;
   var71 : BOOL ;
   var72 : BOOL ;
   var73 : BOOL ;
   var74 : BOOL ;
   e_local : BOOL ; //Alarm: Aggregat auf Hand
   e_OP_err : BOOL ;    //Alarm: Störung OP
   e_visu_err : BOOL ;  //Alarm: B&B ausgefallen
   e_unackn_fail : BOOL ;   //Alarm: min. ein unquittierter  Alarm
   e_ackn_fail : BOOL ; //Alarm: min. ein quittierter Alarm
   var75 : BOOL ;
   var76 : BOOL ;
   var77 : BOOL ;
   e_Dstrt_err : BOOL ; //Alarm: Dieselstart-Fehler
   e_Dstp_err : BOOL ;  //Alarm: Dieselstopp-Fehler
   var78 : BOOL ;
   var79 : BOOL ;
   var80 : BOOL ;
   var81 : BOOL ;
   var82 : BOOL ;
   var83 : BOOL ;
   e_brk_trip : BOOL ;  //Alarm: GenSch ausgelöst
   e_brk_on_err : BOOL ;    //Alarm: GenSch Einschaltfehler
   e_brk_off_err : BOOL ;   //Alarm: GenSch Ausschaltfehler
   e_brk_fdb_err : BOOL ;   //Alarm: Rückmeldungsfehler
   e_Ustrt_err : BOOL ; //Alarm: Aggregat Startfehler
   e_Ustp_err : BOOL ;  //Alarm: Aggregat Stoppfehler
   e_Uabn_err : BOOL ;  //Alarm: Aggregat Startfehler 'Zuschalt.abnormal.Netz'
   var84 : BOOL ;
   e_blackout : BOOL ;  //Alarm: Blackout
   e_i_SC : BOOL ;  //Alarm: Kurzschluß
   e_Prtct_err : BOOL ; //Alarm: Generatorschutz ausgefallen
   e_DstpPrtct : BOOL ; //Alarm: Schutzauslösung Dieselstopp
   e_NEconsu1off : BOOL ;   //Alarm: Schutzauslösung Abschaltung unwicht.Verbr.Stufe 1
   e_NEconsu2off : BOOL ;   //Alarm: Schutzauslösung Abschaltung unwicht.Stufe 2
   e_NEconsu3off : BOOL ;   //Alarm: Schutzauslösung Abschaltung unwicht.Stufe 3
   e_brkOffPrtct : BOOL ;   //Alarm: Schutzauslösung GenSch öffnen
   var85 : BOOL ;
   var86 : BOOL ;
   var87 : BOOL ;
   var88 : BOOL ;
   var89 : BOOL ;
   var90 : BOOL ;
   var91 : BOOL ;
   var92 : BOOL ;
   e_SD_C1 : BOOL ; //Alarm: Shutdown Kanal 1
   e_SD_C2 : BOOL ; //Alarm: Shutdown Kanal 2
   e_SD_C3 : BOOL ; //Alarm: Shutdown Kanal 3
   e_SD_C4 : BOOL ; //Alarm: Shutdown Kanal 4
   e_SD_C5 : BOOL ; //Alarm: Shutdown Kanal 5
   e_SD_C6 : BOOL ; //Alarm: Shutdown Kanal 6
   e_SD_C7 : BOOL ; //Alarm: Shutdown Kanal 7
   e_SD_C8 : BOOL ; //Alarm: Shutdown Kanal 8
   e_wirebrkC1 : BOOL ; //Alarm: Drahtbruch Kanal 1
   e_wirebrkC2 : BOOL ; //Alarm: Drahtbruch Kanal 2
   e_wirebrkC3 : BOOL ; //Alarm: Drahtbruch Kanal 3
   e_wirebrkC4 : BOOL ; //Alarm: Drahtbruch Kanal 4
   e_wirebrkC5 : BOOL ; //Alarm: Drahtbruch Kanal 5
   e_wirebrkC6 : BOOL ; //Alarm: Drahtbruch Kanal 6
   e_wirebrkC7 : BOOL ; //Alarm: Drahtbruch Kanal 7
   e_wirebrkC8 : BOOL ; //Alarm: Drahtbruch Kanal 8
   e_SDWarnC1 : BOOL ;  //Warnung: Shutdown Kanal 1
   e_SDWarnC2 : BOOL ;  //Warnung: Shutdown Kanal 1
   e_SDWarnC3 : BOOL ;  //Warnung: Shutdown Kanal 1
   e_SDWarnC4 : BOOL ;  //Warnung: Shutdown Kanal 1
   e_SDWarnC5 : BOOL ;  //Warnung: Shutdown Kanal 1
   e_SDWarnC6 : BOOL ;  //Warnung: Shutdown Kanal 1
   e_SDWarnC7 : BOOL ;  //Warnung: Shutdown Kanal 1
   e_SDWarnC8 : BOOL ;  //Warnung: Shutdown Kanal 1
   e_SD_lock : BOOL ;   //Alarm-Blockierung Shutdown aktiv
   e_SD_over : BOOL ;   //Override Shutdown aktiv
   var93 : BOOL ;
   var94 : BOOL ;
   var95 : BOOL ;
   var96 : BOOL ;
   var97 : BOOL ;
   var98 : BOOL ;
   var99 : BOOL ;
   var100 : BOOL ;
   var101 : BOOL ;
   var102 : BOOL ;
   var103 : BOOL ;
   var104 : BOOL ;
   var105 : BOOL ;
   var106 : BOOL ;
   var107 : BOOL ;
   var108 : BOOL ;
   var109 : BOOL ;
   var110 : BOOL ;
   var111 : BOOL ;
   var112 : BOOL ;
   var113 : BOOL ;
   var114 : BOOL ;
   e_noAvailPreG : BOOL ;   //Alarm: Gewünschte Anzahl Generatoren nicht zur Verfüg.
   var115 : BOOL ;
   var116 : BOOL ;
   var117 : BOOL ;
   var118 : BOOL ;
   var119 : BOOL ;
   var120 : BOOL ;
   var121 : BOOL ;
   var122 : BOOL ;
   var123 : BOOL ;
   var124 : BOOL ;
   var125 : BOOL ;
   var126 : BOOL ;
   var127 : BOOL ;
   var128 : BOOL ;
   var129 : BOOL ;
   e_shorBrkTrip : BOOL ;   //Alarm: Landanschlußschalter ausgelöst
   e_shore_P : BOOL ;   //Alarm: Belastung Landanschlußschalter zu groß
   var130 : BOOL ;
   var131 : BOOL ;
   var132 : BOOL ;
   var133 : BOOL ;
   var134 : BOOL ;
   var135 : BOOL ;
   e_OP_errE : BOOL ;   //Alarm: Störung OP
   e_visu_errE : BOOL ; //Alarm: B&B ausgefallen
   e_unack_failE : BOOL ;   //Alarm: min. ein unquittierter  Alarm
   e_ackn_failE : BOOL ;    //Alarm: min. ein quittierter Alarm
   var136 : BOOL ;
   var137 : BOOL ;
   var138 : BOOL ;
   var139 : BOOL ;
   var140 : INT ;
   a_OrdSeq1_8 : ARRAY  [1 .. 8 ] OF BYTE ; //Start-Reihenfolge - (1. -8.Generator) -
   a_OrdSeq9_15 : ARRAY  [1 .. 8 ] OF BYTE ;    //Start-Reihenfolge - (9. -15.Generator) -
   a_pmaMode : BYTE ;   //Aktuelle Betriebsart  -local manual
   act_dutyPos : BYTE ; //Aktueller Bedienort -vor Ort (Schalttafel)-Fern (B&B)
   a_preUBL_set : BYTE ;    //Vorgewählter Schieflast-Sollwert
   var141 : BYTE ;
   var142 : INT ;
   var143 : INT ;
   a_Dstrt_stat : BYTE ;    //Dieselstart / WG Zustand
   a_Dstp_stat : BYTE ; //Dieselstopp/ WG Zustand
   a_DstrtSqNo : BYTE ; //Diesel-/ WG-Start: Aktueller Schritt
   a_DstptSqNo : BYTE ; //Diesel-/ WG-Stopp: Aktueller Schritt
   a_DstrtSqCond : INT ;    //Diesel-/ WG-Start: Aktuelle Schritt -Kriterien 1 -16
   a_DstpSqcond : INT ; //Diesel-/ WG-Stopp: Aktuelle Schritt -Kriterien 1 -16
  END_STRUCT ;
BEGIN
   var01 := FALSE;
   var02 := FALSE;
   var03 := FALSE;
   var04 := FALSE;
   var05 := FALSE;
   var06 := FALSE;
   var07 := FALSE;
   var08 := FALSE;
   i_Dstrt := FALSE;
   i_Dstp := FALSE;
   var09 := FALSE;
   var10 := FALSE;
   var11 := FALSE;
   var12 := FALSE;
   var13 := FALSE;
   var14 := FALSE;
   i_brkClse := FALSE;
   i_brkOpn := FALSE;
   i_UnitActive := FALSE;
   i_UnitDeactiv := FALSE;
   i_1UnitOnBus := FALSE;
   var15 := FALSE;
   var16 := FALSE;
   var17 := FALSE;
   var18 := FALSE;
   var19 := FALSE;
   var20 := FALSE;
   var21 := FALSE;
   var22 := FALSE;
   var23 := FALSE;
   var24 := FALSE;
   var25 := FALSE;
   var26 := FALSE;
   var27 := FALSE;
   var28 := FALSE;
   var29 := FALSE;
   var30 := FALSE;
   var31 := FALSE;
   var32 := FALSE;
   var33 := FALSE;
   i_LFCtrlOn := FALSE;
   i_FCtrlLock := FALSE;
   i_LCtrlLock := FALSE;
   i_UBLOn := FALSE;
   i_UBLMin := FALSE;
   i_UBL_Unit := FALSE;
   var34 := FALSE;
   var35 := FALSE;
   var36 := FALSE;
   var37 := FALSE;
   var38 := FALSE;
   var39 := FALSE;
   var40 := FALSE;
   var41 := FALSE;
   var42 := FALSE;
   var43 := FALSE;
   var44 := FALSE;
   var45 := FALSE;
   var46 := FALSE;
   var47 := FALSE;
   var48 := FALSE;
   var49 := FALSE;
   var50 := FALSE;
   var51 := FALSE;
   i_Mod2GenOn := FALSE;
   i_Mod3GenOn := FALSE;
   i_Mod4GenOn := FALSE;
   i_Mod5GenOn := FALSE;
   i_Mod6GenOn := FALSE;
   i_Mod7GenOn := FALSE;
   i_Mod8GenOn := FALSE;
   i_ModPreGen := FALSE;
   var52 := FALSE;
   var53 := FALSE;
   var54 := FALSE;
   var55 := FALSE;
   var56 := FALSE;
   var57 := FALSE;
   var58 := FALSE;
   var59 := FALSE;
   i_tieA_noUnit := FALSE;
   i_tieB_noUnit := FALSE;
   i_tie_A_i_SC := FALSE;
   i_tie_B_i_SC := FALSE;
   i_tieNoAnyAut := FALSE;
   var60 := FALSE;
   var61 := FALSE;
   var62 := FALSE;
   i_shoreMode := FALSE;
   i_shore_clse := FALSE;
   i_shore_opn := FALSE;
   i_shore_avail := FALSE;
   var63 := FALSE;
   var64 := FALSE;
   var65 := FALSE;
   var66 := FALSE;
   var67 := FALSE;
   var68 := FALSE;
   var69 := FALSE;
   var70 := FALSE;
   var71 := FALSE;
   var72 := FALSE;
   var73 := FALSE;
   var74 := FALSE;
   e_local := FALSE;
   e_OP_err := FALSE;
   e_visu_err := FALSE;
   e_unackn_fail := FALSE;
   e_ackn_fail := FALSE;
   var75 := FALSE;
   var76 := FALSE;
   var77 := FALSE;
   e_Dstrt_err := FALSE;
   e_Dstp_err := FALSE;
   var78 := FALSE;
   var79 := FALSE;
   var80 := FALSE;
   var81 := FALSE;
   var82 := FALSE;
   var83 := FALSE;
   e_brk_trip := FALSE;
   e_brk_on_err := FALSE;
   e_brk_off_err := FALSE;
   e_brk_fdb_err := FALSE;
   e_Ustrt_err := FALSE;
   e_Ustp_err := FALSE;
   e_Uabn_err := FALSE;
   var84 := FALSE;
   e_blackout := FALSE;
   e_i_SC := FALSE;
   e_Prtct_err := FALSE;
   e_DstpPrtct := FALSE;
   e_NEconsu1off := FALSE;
   e_NEconsu2off := FALSE;
   e_NEconsu3off := FALSE;
   e_brkOffPrtct := FALSE;
   var85 := FALSE;
   var86 := FALSE;
   var87 := FALSE;
   var88 := FALSE;
   var89 := FALSE;
   var90 := FALSE;
   var91 := FALSE;
   var92 := FALSE;
   e_SD_C1 := FALSE;
   e_SD_C2 := FALSE;
   e_SD_C3 := FALSE;
   e_SD_C4 := FALSE;
   e_SD_C5 := FALSE;
   e_SD_C6 := FALSE;
   e_SD_C7 := FALSE;
   e_SD_C8 := FALSE;
   e_wirebrkC1 := FALSE;
   e_wirebrkC2 := FALSE;
   e_wirebrkC3 := FALSE;
   e_wirebrkC4 := FALSE;
   e_wirebrkC5 := FALSE;
   e_wirebrkC6 := FALSE;
   e_wirebrkC7 := FALSE;
   e_wirebrkC8 := FALSE;
   e_SDWarnC1 := FALSE;
   e_SDWarnC2 := FALSE;
   e_SDWarnC3 := FALSE;
   e_SDWarnC4 := FALSE;
   e_SDWarnC5 := FALSE;
   e_SDWarnC6 := FALSE;
   e_SDWarnC7 := FALSE;
   e_SDWarnC8 := FALSE;
   e_SD_lock := FALSE;
   e_SD_over := FALSE;
   var93 := FALSE;
   var94 := FALSE;
   var95 := FALSE;
   var96 := FALSE;
   var97 := FALSE;
   var98 := FALSE;
   var99 := FALSE;
   var100 := FALSE;
   var101 := FALSE;
   var102 := FALSE;
   var103 := FALSE;
   var104 := FALSE;
   var105 := FALSE;
   var106 := FALSE;
   var107 := FALSE;
   var108 := FALSE;
   var109 := FALSE;
   var110 := FALSE;
   var111 := FALSE;
   var112 := FALSE;
   var113 := FALSE;
   var114 := FALSE;
   e_noAvailPreG := FALSE;
   var115 := FALSE;
   var116 := FALSE;
   var117 := FALSE;
   var118 := FALSE;
   var119 := FALSE;
   var120 := FALSE;
   var121 := FALSE;
   var122 := FALSE;
   var123 := FALSE;
   var124 := FALSE;
   var125 := FALSE;
   var126 := FALSE;
   var127 := FALSE;
   var128 := FALSE;
   var129 := FALSE;
   e_shorBrkTrip := FALSE;
   e_shore_P := FALSE;
   var130 := FALSE;
   var131 := FALSE;
   var132 := FALSE;
   var133 := FALSE;
   var134 := FALSE;
   var135 := FALSE;
   e_OP_errE := FALSE;
   e_visu_errE := FALSE;
   e_unack_failE := FALSE;
   e_ackn_failE := FALSE;
   var136 := FALSE;
   var137 := FALSE;
   var138 := FALSE;
   var139 := FALSE;
   var140 := 0;
   a_OrdSeq1_8[1] := B#16#0;
   a_OrdSeq1_8[2] := B#16#0;
   a_OrdSeq1_8[3] := B#16#0;
   a_OrdSeq1_8[4] := B#16#0;
   a_OrdSeq1_8[5] := B#16#0;
   a_OrdSeq1_8[6] := B#16#0;
   a_OrdSeq1_8[7] := B#16#0;
   a_OrdSeq1_8[8] := B#16#0;
   a_OrdSeq9_15[1] := B#16#0;
   a_OrdSeq9_15[2] := B#16#0;
   a_OrdSeq9_15[3] := B#16#0;
   a_OrdSeq9_15[4] := B#16#0;
   a_OrdSeq9_15[5] := B#16#0;
   a_OrdSeq9_15[6] := B#16#0;
   a_OrdSeq9_15[7] := B#16#0;
   a_OrdSeq9_15[8] := B#16#0;
   a_pmaMode := B#16#0;
   act_dutyPos := B#16#0;
   a_preUBL_set := B#16#0;
   var141 := B#16#0;
   var142 := 0;
   var143 := 0;
   a_Dstrt_stat := B#16#0;
   a_Dstp_stat := B#16#0;
   a_DstrtSqNo := B#16#0;
   a_DstptSqNo := B#16#0;
   a_DstrtSqCond := 0;
   a_DstpSqcond := 0;
END_DATA_BLOCK

DATA_BLOCK "MEM"
TITLE =Internal interface between the software moduls
//V 1.8 20.08.00 Kahle -last vaild version
//V 1.9 17.10.00 Kahle -DBX100.6 o515_i_floatFreq
//V 2.0 05.12.00 Kahle -DBX45.1 o57_extBlock generator breaker
//                                  -DBX61.4 o513_i_isochron                                                            -DBX101.0 o515_c_isochron
//                                  -DBX101.1 o515_c_take_isochron
//                                  -DBX125.0 o515R_c_isochron
//                                  -DBX125.1 o515R_c_take_isochron            V2.1 13.02.01Kahle -DBX61.5 o513_c_upload
//                                 -DBX61.6 o513_i_extRelCtrl
//                                 -DBX61.7 o513_i_Backup
//                                 -DBX86.0 o515_f_EB_busbar
//                                 -DBX110.0 o515R_f_EB_busbar
//                                 -DBX37.3 o53_GenBrkTrip
//                                 -DBX37.4 o53_extBlockDG
//                                 -DBX38.0 o50_In_fail
//                                 -DBX38.1 o50_Out_fail
//                                 -DBX70.0 o513_c_isochron
//
// !
//
//
//MEM
//  Interne Modul-Schnittstellen-Signale
//  Alle Module (5.xx) und die Toolbox-Module verquellen ihre Ausgangssignale
//  ausschließlich auf diesen DB.
//
//  Die Daten stehen den anderen Module als Eingangssignale zur Verfügung.
//
//  Siemens AG ATD IS3T, Kahle +494028892022, jens.kahle@hbg.siemens.de
//  PMA71
//  =Internal Modul Memory
//  Datum aktuelle Version: 03.05.99
//  Version, Änd-Datum, Bearbeiter, geänderte Variablen
//  01.01,   31.01.99,  Kahle,      erste Version
//  01.02,   21.03.99,  Kahle,      o51_xxxx new, o515_xxxx new
//                                  o513_xxxx new
//  01.03,   28.04.99,  Kahle,      o513_xxxx erweitert
//  01.04,   03.05.99,  Kahle,      komplette Überarbeitung
//  01.08,   13.10.00,  Kahle,      DBX87.5 o515_f_2ndTieBrk_on
//                                  DBX87.6 o515_f_2ndTieBrkTrip
//KNOW_HOW_PROTECT
// (If specified, no more changes can be made once the block is generated)
//UNLINKED
// (If specified, the generated block is only available in the PLC load
//  memory)
//READ_ONLY
// (If specified, the generated block cannot be changed in the programmable
//  controller)
AUTHOR : Kahle
FAMILY : PMA71
NAME : MEM
VERSION : 2.3


  STRUCT
   o51_dutyPos : BYTE ; //active control position
   o51_OperatMode : BYTE ;  //active mode
   o51_mode_bin : BYTE ;    //vaild mode binary outputs
   o51_mode_chg : BYTE ;    //mode changed to =local
   o51_lockOrdChg : BOOL ;  //lock order change
   o51_orderFail : BOOL ;   //order failure
   o51_blockD_OP : BOOL ;   //block Diesel via OP
   o51_forceLocalGENOP : BOOL ; //force local mode because of faulty GENOP
   o51_forceVisuOP : BOOL ; //force control position visualization because of faulty OP
   o51_ackn_impulse : BOOL ;    //A impulse from the push button were set for 1 sec
   o51_UBL_OP : BOOL ; //UBL mode active via OP
   o51_i_pressCnfrm : BOOL ;    //Indication: press confirmation
   o51_mode_ind : BYTE ;    //indication "active mode"
   o51_code1_8 : DINT ; //order code 1.up to 8.gen
   o51_code9_15 : DINT ;    //order code 9.up to 15.gen
   o51_code1_8actCfg : DINT ;   //order act config 1. -8 generator
   o51_code9_15actCfg : DINT ;  //order act config 9. -15 generator
   o51_actCfgNo : BYTE ;    //actual bus configuration No
   o51_actCfgNo_rel : BYTE ;    //actual bus relative configuration No.
   o51_act_partBus : BYTE ; //actual vaild bus
   o51_actCfg : WORD ;  //actual bus configuration
   o51_actTieCfg : BYTE ;   //actual tie breaker configuration
   o51_flashLED : BYTE ;    //flash LED1-4 on OP in case of waiting to push  the enter button
   o52_stdby_1st : BOOL ;   //own station =1st standby gen.
   o52_stdby_2nd : BOOL ;   //own station =2nd standby gen.
   o52_SD : BOOL ;  //own station =shutdown release
   o51_blockF_reset : BOOL ;    //Reset of blocking by fault
   o52_lockSD_OP : BOOL ; //Lock shutdown because of underload from OP
   o51_newStation : BOOL ;  //New station or faulty active again
   o51_test2_act : BOOL ;   //Test 2 is active, emergency diesel only
   o51_uncond_SemiS : BOOL ;    //force semi mode because of a link failure
   o52_stdbyNo_1st : BYTE ; //number of the 1st standby gen.
   o52_stdbyNo_2nd : BYTE ; //number of the 2nd standby gen.
   o52_SDNo : BYTE ;    //number of shutdown gen.
   o52_No_ofRunGen : BYTE ; //Anzahl laufender Gen. in akt.Konfig
   o52_Rel_Stp2ndDG : BOOL ;    //Release stop 2nd diesel in case of shutdown
   o51_fSemi_TBerr : BOOL ; //Force Semi, no simultaneous lock in case of tie breaker failure
   o51_rel_ownTB : BOOL ;   //Release own tie breaker, if this station is a tie breaker controller
   var053 : BOOL ;
   var054 : BOOL ;
   var055 : BOOL ;
   var056 : BOOL ;
   var057 : BOOL ;
   o53_Gen_Available : BOOL ;   //DG/SG/EG available for start (FB47/49-->)
   o53_Gen_Running : BOOL ; //DG/SG/EG running (FB47/49-->)
   o53_Gen_Blocked : BOOL ;    //DG/SG/EG generator blocked (FB47/49-->)
   o53_req_Ustrt : BOOL ;   //Request of standby start (FB47/49-->)
   o53_ChOver_Semi : BOOL ; //Forced change over from "Automatic" to "Semi automatic" mode (FB47/49-->)
   o53_LoadRed : BOOL ; //Command "load reduction" (FB51-->FB58, frequency/load controller)
   o53_GenBrkOff_LoadRed : BOOL ;   //Generator breaker off after load reduction (FB47/49-->FB51)
   o53_GenBrkOff : BOOL ;   //Generator breaker off command, without previous load reduction (FB47/49-->FB51)
   o53_Gen_Starting : BOOL ;    //DG/SG/EG starting (FB47/49-->)
   o53_Blocked_Fault : BOOL ;   //DG/SG/EG blocked by fault (FB47/49 -->)
   o53_Blocked_Switch : BOOL ;  //DG/SG/EG blocked by local switch
   o53_GenBrkTrip : BOOL ;  //DG/EG GenBrk tripped because of faulty delay stop
   o53_extBlockDG : BOOL ;  //DG is blocked by external conditions
   var19 : BOOL ;
   var20 : BOOL ;
   var21 : BOOL ;
   o50_In_fail : BOOL ; //input card failure
   o50_Out_fail : BOOL ;    //output card failure
   var133 : BOOL ;
   var134 : BOOL ;
   var135 : BOOL ;
   var136 : BOOL ;
   var137 : BOOL ;
   var138 : BOOL ;
   var22 : BYTE ;
   var23 : BOOL ;
   var24 : BOOL ;
   var25 : BOOL ;
   var26 : BOOL ;
   var27 : BOOL ;
   var28 : BOOL ;
   var29 : BOOL ;
   var30 : BOOL ;
   var31 : BYTE ;
   o53_ExtStrtCmd : BOOL ;  //External Diesel start command
   var33 : BOOL ;
   var34 : BOOL ;
   var35 : BOOL ;
   var36 : BOOL ;
   var37 : BOOL ;
   var38 : BOOL ;
   var39 : BOOL ;
   var40 : BYTE ;
   o57_req_simulLock : BOOL ;   //Request for release from simultaneous locking (FB51-->)
   o57_Brk_Ready_Standby : BOOL ;   //Generator breaker ready for standby function (FB51-->FB53)
   o57_Brk_Ready_Closing : BOOL ;   //Generator breaker ready for closing (FB51-->)
   o57_DelayStop : BOOL ;   //Delayed stop command (FB51-->FB47/49)
   o57_ChOver_Semi : BOOL ; //Forced change over from "Automatic" to "Semi automatic" mode (FB51-->)
   o57_req_Ustrt : BOOL ;   //Request of standby start (FB51-->)
   o57_UndelayStop : BOOL ; //Undelayed stop command (FB51-->FB47/49)
   o57_GenBrk_Failure : BOOL ;  //Generator breaker general failure (FB51 -->)
   o57_Blocking : BOOL ;    //Blocking of generator set (FB51-->FB47/49)
   o57_extBlock : BOOL ;    //External blocking of the generator breaker
   o57_ExtCBopenCmd : BOOL ;    //External generator breaker off command
   var483 : BOOL ;
   var484 : BOOL ;
   var485 : BOOL ;
   var486 : BOOL ;
   var487 : BOOL ;
   var49 : BOOL ;
   var50 : BOOL ;
   var51 : BOOL ;
   var52 : BOOL ;
   var53 : BOOL ;
   var54 : BOOL ;
   var55 : BOOL ;
   var56 : BOOL ;
   var57 : BYTE ;
   o59_Start_Comm : BOOL ;  //Start command to own set (FB53-->FB47/49)
   o59_Stop_Comm : BOOL ;   //Stop command to own set (FB53-->FB47/49)
   o59_Synchr_On : BOOL ;   //Command "Synchronizing On" (FB53-->FB51) ?
   o59_Synchr_Off : BOOL ;  //Command "Synchronizing Off" (FB53-->FB51) ?
   o59_GenBrk_Off : BOOL ;  //Generator breaker OFF Command (FB53-->FB51)
   o59_LoadBal_On : BOOL ;  //Command "Load balancing ON" (FB53-->FB58)
   var58a : BOOL ;
   var58 : BOOL ;
   var60 : BYTE ;
   o59A_DStrtAbn : BOOL ;   //Start Diesel
   o59A_BrkOpnAbn : BOOL ;  //GenSch öffnen
   o59A_BrkClseAbn : BOOL ; //GenSch schließen, Lastverteil.
   var61 : BOOL ;
   var62 : BOOL ;
   var63 : BOOL ;
   var64 : BOOL ;
   var65 : BOOL ;
   var66 : BYTE ;
   o510_DstpAuto : BOOL ;   //Diesel Stop
   o510_BrkOpnAuto : BOOL ; //GenSch öffnen
   o510_loadLock : BOOL ;   //Lastverteilung sperren
   var67 : BOOL ;
   var68 : BOOL ;
   var69 : BOOL ;
   var70 : BOOL ;
   var71 : BOOL ;
   var72 : BYTE ;
   o511_Blackout : BOOL ;   //Blackout (FB56-->)
   o511_GenVolt_avail : BOOL ;  //Generator voltage available (standard U>85%) (FB56-->)
   o511_req_Ustrt : BOOL ;  //Request of standby start (FB56-->)
   o511_Blocking : BOOL ;   //Blocking of generator set (FB56-->FB47/49)
   o511_GenBrk_Off : BOOL ; //Generator breaker trip command (FB56-->FB51)
   o511_ChOver_Blackout : BOOL ;    //Change over to new started set via blackout (no synchronizing) (FB56-->)
   o511_Underload_Shd : BOOL ;  //Shutdown by underload (FB56-->)
   o511_UndelayStop : BOOL ;    //Undelayed stop command (FB56-->FB47/49)
   o511_DstpE : BOOL ;  //Diesel Stop
   o511_Underload_Limit : BOOL ;    //Load < limit for underload (FB56-->)
   o511_UnitLock : BOOL ;   //Blocking of generator set ?
   o511_ChOver_Semi : BOOL ;    //Forced change over from "Automatic" to "Semi automatic" mode (FB56-->)
   o511_BusVolt_avail : BOOL ;  //Busbar voltage available (standard U>85%) (FB56-->)
   o511_ProtWarning : BOOL ;    //Protection warning (EG only) (FB56-->)
   o511_TrLBrk_Off : BOOL ; //Transfer line circuit breaker trip from generator protection (EG) (FB56-->FB92)
   var77 : BOOL ;
   var78 : INT ;
   o512_req_Ustrt : BOOL ;  //Request of standby start (FB57/50-->)
   o512_req_Ustrt2 : BOOL ; //Request of 2nd standby start (FB57/50-->)
   o512_UndelayStop : BOOL ;    //Undelayed stop command (FB57/50-->)
   o512_DelayStop : BOOL ;  //Delayed stop command (FB57/50-->)
   o512_MonitTime1 : BOOL ; //Monitoring time 1 active (FB57-->)
   o512_MonitTime2 : BOOL ; //Monitoring time 2 active (FB57-->)
   o512_EmergencyStop : BOOL ;  //Emergency stop command (FB57-->)
   o512_Chover_Semi : BOOL ;    //Forced change over from "Automatic" to "Semi automatic" mode (FB57/50-->)
   o512_Blocking : BOOL ;   //Blocking of generator set (FB57-->FB47/49)
   o512_uness_1 : BOOL ;    //Unessential consumer 1 off (external command)
   o512_uness_2 : BOOL ;    //Unessential consumer 2 off (external command)
   o512_uness_3 : BOOL ;    //Unessential consumer 3 off (external command)
   o512_genBrk_off : BOOL ; //generator breaker off (at overspeed if overspeed signal is gone)
   var855 : BOOL ;
   var856 : BOOL ;
   var857 : BOOL ;
   o513_c_deload : BOOL ;   //command deload generator set
   o513_c_lock_L_Ctrl : BOOL ;  //lock load controller part
   o513_c_lock_F_Ctrl : BOOL ;  //lock frequency controller part
   o513_c_UBLmin : BOOL ; //command UBLmin mode
   o513_c_UBLmode : BOOL ;  //command UBLset mode
   o513_i_UBLmin : BOOL ;   //UBL_minLoad active
   o513_i_UBLmode : BOOL ;  //UBLset active (memory flag for FC59)
   o513_c_stpPunder : BOOL ;    //Stop Diesel because underload
   o513_f_deload : BOOL ;   //feedback generator set are deloaded
   o513_i_PBstpPos : BOOL ; //Generatorset stop by the operator via MMI possible [in auto only]
   o513_i_SGonly : BOOL ;   //Shaft generator on busbar only
   o513_c_UBLoff_tooL : BOOL ;  //UBL off if the UBL max value too low
   o513_i_isochron : BOOL ; //Isochron mode on speedcontroller is active
   o513_c_upload : BOOL ;   //command upload generator set
   o513_i_extRel_Ctrl : BOOL ;  //external release load-& frequency controller
   o513_i_Backup : BOOL ;   //Backup controller is activated
   o513_s_UBL_load : INT ;  //UBL load setpoint
   o513_expLoadOwn : INT ;  //Expected load of the actual generator set [kW]
   o513_NoActGen : INT ;    //Number of generators with active loadsharing without the own one
   o513_s_actGen : INT ;    //Nominal power of the actual generator set [kW]
   o513_c_isochron : BOOL ; //Isochron mode is select by external conditions (e.g. HMI)
   o513_c_up_speed : BOOL ; //Command up speed
   o513_c_down_speed : BOOL ;   //Command down speed
   var964 : BOOL ;
   var965 : BOOL ;
   var966 : BOOL ;
   var967 : BOOL ;
   var968 : BOOL ;
   var961 : BYTE ;
   var97 : INT ;
   var98 : INT ;
   var99 : INT ;
   var100 : INT ;
   var101 : INT ;
   o515_c_reqStrt : BOOL ;  //Command: Request next generator set
   o515_c_req2Strt : BOOL ; //Command: Request second generator set
   o515_c_reqEStrt : BOOL ; //Command: Emergency request next generator set
   o515_c_req2EStrt : BOOL ;    //Command: Emergency request second generator set
   o515_c_genBrkOpn : BOOL ;    //Command: Generator breaker open by protection
   var105 : BOOL ;
   o515_c_lockCtrl : BOOL ; //Command: Lock foreign controller commands up/down
   var107 : BOOL ;
   o515_c_unitLock : BOOL ;   //Command: Block generator set
   o515_c_simulLock : BOOL ;    //Command: Simultaneous lock activating
   o515_c_uncUBLoff : BOOL ;    //Command: force UBL mode off
   o515_c_shoreOn : BOOL ;  //Command: Shore connection on, stop generator set
   o515_c_takeLoad : BOOL ; //Command: Shore connection off, take over load
   o515_c_takePreSeOrd : BOOL ; //Command: Take over pre select order via MPI
   o515_c_preSeLock : BOOL ;    //Command: Preselection lock activating
   o515_c_life : BOOL ; //Life-Flag
   o515_f_auto : BOOL ; //Feedback: Generator set in automatic
   o515_f_rdyStandby : BOOL ;   //Feedback: Generator set ready for standby
   o515_f_brk_clse : BOOL ; //Feedback: Generator breaker closed
   o515_f_onbus : BOOL ;    //Feedback: Generator set on busbar in automatic
   o515_f_lock : BOOL ; //Feedback: Generator set blocked
   o515_f_run : BOOL ;  //Feedback: Diesel is running
   o515_f_blackout : BOOL ; //Feedback: Blackout
   o515_f_SGonbus : BOOL ;  //Feedback: Shaft generator is on busbar in automatic mode
   var109 : BOOL ;
   o515_f_preSeLock : BOOL ;    //Feedback: Preselection lock activating
   o515_f_i_SC : BOOL ; //Feedback: Generator breaker was opened becauce of short circuit
   o515_f_busy_Gset : BOOL ;    //Feedback: Preselection lock request not possible in the moment
   o515_f_UBL_on : BOOL ;   //Feedback: UBL-Mode is activated
   o515_f_shoreMode : BOOL ;    //Feedback: Shore connection mode is activated
   o515_f_rdy_swtchOn : BOOL ;  //Feedback: Generator set ready for switch on
   o515_f_shore_disconn : BOOL ;    //Feedback: Disconnecting Shore connection is activing
   o515_f_EB_busbar : BOOL ;    //Feedback: Diesel is in emergency mode on busbar
   var110 : BOOL ;
   o515_f_UBLmax_act : BOOL ;   //Feedback: UBLmax is active at least a generator set
   o515_c_unessOff : BOOL ; //Command: unessential consumer off
   o515_c_UBL_MinLck : BOOL ;   //Command:  UBL mode lock because of minimum load
   o515_c_lockShtdwn : BOOL ;   //Command:  no stop in case of underload (=1)
   o515_c_takeLckShtdn : BOOL ;  //Command:  take over 'no stop in case of underload'
   o515_f_allTieBrkOn : BOOL ;  //Feedback: one or all tie breakers are closed
   o515_c_LckCtrl : BOOL ;  //Command:  Lock controller (load & frequency)
   o515_c_takeLckCtrl : BOOL ;  //Command:  take over 'lock controller'
   o515_f_tieBrkOn : BOOL ; //Feedback: tie breaker on
   o515_f_tieBrkTrip : BOOL ;   //Feedback: tie breaker tripped
   o515_f_exp_shr : BOOL ;  //Feedback: direction =export shore connection
   o515_f_2ndTieBrkOn : BOOL ;  //Feedback: 2nd tie breaker on
   o515_f_2ndtieBrkTrip : BOOL ;    //Feedback: 2nd tie breaker tripped
   var116c : BOOL ;
   o515_a_load : INT ;  // Actual value: Active power
   o515_s_ordSq1_8 : DINT ; //setpoint: Start/stop sequence of the actual configuration - (Gen.1 -8) -
   o515_s_ordSq9_15 : DINT ;    //Setpoint: Start/stop sequence of the actual configuration - (Gen.9 -15) -
   o15_a_busFreq : INT ;    //Actual value: busbar frequency
   o515_c_cont_up : BOOL ;  //command: contineous up command on foreign speed controller
   o515_c_long_up : BOOL ;  //command: long pulse up command on foreign speed controller
   o515_c_short_up : BOOL ; //command: short pulse up command on foreign speed controller
   o515_c_cont_down : BOOL ;    //command: contineous down command on foreign speed controller
   o515_c_long_down : BOOL ;    //command: long pulse down command on foreign speed controller
   o515_c_short_down : BOOL ;   //command: short pulse dwon command on foreign speed controller
   o515_i_floatFreq : BOOL ;    //indication: floating frequency mode is active
   var1187 : BOOL ;
   o515_c_isochron : BOOL ; //command: isochron mode active
   o515_c_take_isochron : BOOL ;    //command: take over 'isochron mode'
   var1192 : BOOL ;
   var1193 : BOOL ;
   var1194 : BOOL ;
   var1195 : BOOL ;
   var1196 : BOOL ;
   var1197 : BOOL ;
   var120 : INT ;
   var121 : INT ;
   o515R_c_reqStrt : BOOL ; //Command: Request next generator set
   o515R_c_req2Strt : BOOL ;    //Command: Request second generator set
   o515R_c_reqEStrt : BOOL ;    //Command: Emergency request next generator set
   o515R_c_req2EStrt : BOOL ;   //Command: Emergency request second generator set
   o515R_c_genBrkOpn : BOOL ;   //Command: Generator breaker open by protection
   o515R_c_strtSet : BOOL ; //Command: Start generator set
   o515R_c_lock_Ctrl : BOOL ;   //Command: Lock up/down commands from the own controller
   var124 : BOOL ;
   o515R_c_unitLock : BOOL ;    //Command: Block generator set
   o515R_c_simulLock : BOOL ;   //Command: Simultaneous lock activating
   o515R_c_uncUBLoff : BOOL ;   //Command: force UBL mode off
   o515R_c_shoreOn : BOOL ; //Command: Shore connection on, stop generator set
   o515R_c_takeLoad : BOOL ;    //Command: Shore connection off, take over load
   o515R_c_takePreSeOrd : BOOL ;    //Command: Take over pre select order via MPI
   o515R_c_preSeLock : BOOL ;   //Command: Preselection lock activating
   var127 : BOOL ;
   o515R_f_auto : BOOL ;    //Feedback: Generator set in automatic
   var129 : BOOL ;
   o515R_f_brk_clse : BOOL ;    //Feedback: Generator breaker close
   o515R_f_onbus : BOOL ;   //Feedback: At least on generator set in automatic
   var132 : BOOL ;
   o515R_f_run : BOOL ; //Feedback: At least one diesel is running
   o515R_f_blackout : BOOL ;    //Feedback: Blackout
   o515R_f_SGonbus : BOOL ; //Feedback: Shaft generator is on busbar in automatic mode
   var135a : BOOL ;
   o515R_f_preSeLock : BOOL ;   //Feedback: Preselection lock activating
   o515R_f_i_SC : BOOL ;    //Feedback: Generator breaker was opend because of short circuit
   o515R_f_busy_Gset : BOOL ;   //Feedback: Preselection lock request not possible in the moment
   var135b : BOOL ; //
   o515R_f_shoreMode : BOOL ;   //Feedback: Shore connection mode is activated
   o515R_f_rdy_swtchOn : BOOL ; //Feedback: Generator set ready for switch on
   o515R_f_shore_dis : BOOL ;   //Feedback: Disconneting Shore connection is active (one or more)
   o515R_f_EB_busbar : BOOL ;   //Feedback: Diesel is in emergency mode on busbar
   var1101 : BOOL ;
   var139a : BOOL ;
   o515R_c_unessOff : BOOL ;    //Command: unessential consumer off
   o515R_c_UBL_MinLck : BOOL ;  //Command:  UBL mode lock because of minimum load
   o515R_c_lockShtdwn : BOOL ;  //Command:  no stop in case of underload (=1)
   o515R_c_takeLckShtdn : BOOL ;    //Command:  take over command 'no stop in case of underload'
   o515R_f_AllTieBrkOn : BOOL ; //Feedback: one or all bus tie breakers are closed
   o515R_c_LckCtrl : BOOL ; //Command:  Lock controller (load & frequency)
   o515R_c_takeLckCtrl : BOOL ; //Command:  take over 'lock controller'
   o515R_f_tieBrkOn : BOOL ;    //Feedback: tie breaker on
   o515R_f_tieBrkTrip : BOOL ;  //Feedback: tie breaker tripped
   o515R_f_shoreExp : BOOL ;    //Feedback: shore connection mode =export/ synchronization
   o515R_f_2ndTieBrkOn : BOOL ; //Feedback: 2nd tie breaker on
   o515R_f_2ndtieBrkTrip : BOOL ;   //Feedback: 2nd tie breaker tripped
   var140d : BOOL ;
   var147 : INT ;
   o515R_s_ordSq1_8 : DINT ;  //Setpoint: Start/stop sequence of actual configuration -(Gen.1 -8)-
   o515R_s_ordSq9_15 : DINT ;   //Setpoint: Start/stop sequence of actual configuration -(Gen.9 -15)-
   o515R_a_busFreq : INT ;  //Actual value: busbar frequency
   o515R_c_cont_up : BOOL ; //command: contineous up command on foreign speed controller
   o515R_c_long_up : BOOL ; //command: long pulse up command on foreign speed controller
   o515R_c_short_up : BOOL ;    //command: short pulse up command on foreign speed controller
   o515R_c_cont_down : BOOL ;   //command: contineous down command on foreign speed controller
   o515R_c_long_down : BOOL ;   //command: long pulse down command on foreign speed controller
   o515R_c_short_down : BOOL ;  //command: short pulse dwon command on foreign speed controller
   o515R_i_floatFreq : BOOL ;   //indication: floating frequency mode is active
   var1497 : BOOL ;
   o515R_c_isochron : BOOL ;    //command: isochron mode active
   o515R_c_take_isochron : BOOL ;   //command: take over 'isochron mode'
   var1502 : BOOL ;
   var1503 : BOOL ;
   var1504 : BOOL ;
   var1505 : BOOL ;
   var1506 : BOOL ;
   var1507 : BOOL ;
   var151 : INT ;
   var152 : BOOL ;
   var1521 : BOOL ;
   var1522 : BOOL ;
   var1523 : BOOL ;
   var1524 : BOOL ;
   var1525 : BOOL ;
   var1526 : BOOL ;
   var1527 : BOOL ;
   var1528 : BOOL ;
   var1529 : BOOL ;
   var15210 : BOOL ;
   var15211 : BOOL ;
   var15212 : BOOL ;
   var15213 : BOOL ;
   var15214 : BOOL ;
   o515_LockShtdwnLoad : BOOL ; //Lock shutdown because of underload controlled by program
   o515_noCnfrm : BOOL ;    //simultaneous lock: no confirm foreign request
   o515_ownBlock : BOOL ;   //simultaneous lock: own unit blocked
   o515_monT_run : BOOL ;   //simultaneous lock: monitoring time is running
   o515_lockT_run : BOOL ;  //simultaneous lock: lock time is running
   o515_simulLockAct : BOOL ;   //simultaneous lock: lock is activated
   o515_simulLockErr : BOOL ;   //simultaneous lock: failure
   o515_moreFaultyEssMPI : BOOL ; //more than one essential MPI stations faulty (1/1 configuration)
   o515_FaultyEssMPI : BOOL ;   //At least one essential MPI station faulty (1/1 configuration)
   o515_unessStation : DWORD ;  //dynamic unessential stations
   var200 : ARRAY  [1 .. 8 ] OF BYTE ;
   var210 : ARRAY  [1 .. 10 ] OF //+++ tie breaker control +++
   BYTE ;
   var220 : ARRAY  [1 .. 6 ] OF //+++ shore connection control +++
   BYTE ;
   o523_Harbour_Mode : BOOL ;   //EG: Harbour mode is active
   o523_PowerFeedb_Mode : BOOL ;    //EG: Power feedback mode is active
   o523_EmergGen_Mode : BOOL ;  //EG: Emergency generator mode is active
   o523_ChOver_Test_Auto : BOOL ;   //EG: Forced change over from test mode to automatic mode
   o523_Start : BOOL ;  //Diesel engine start command (FB92-->FB47)
   o523_DelStop : BOOL ;    //Diesel engine delayed stop command (FB92-->FB47)
   o523_GenBrk_On : BOOL ;  //Generator breaker ON command (FB92-->FB51)
   o523_GenBrk_Off : BOOL ; //Generator breaker OFF command (FB92-->FB51)
   o523_GenBrk_Synchr : BOOL ;  //Generator breaker Synchronizing command (FB92-->FB51)
   var3009 : BOOL ;
   var30010 : BOOL ;
   var30011 : BOOL ;
   var30012 : BOOL ;
   var30013 : BOOL ;
   var30014 : BOOL ;
   var30015 : BOOL ;
   o520_closeBrk_A : BOOL ; //Restore after blackout close tie breaker A
   o520_closeBrk_B : BOOL ; //Restore after blackout close tie breaker B
   o520_simLock_fail : BOOL ;   //Simultaneous lock failure
   o520_clsPrcBrk_A : BOOL ;
   o520_clsPrcBrk_B : BOOL ;
   o520_blockTBopn : BOOL ;
   var1626 : BOOL ;
   var1627 : BOOL ;
   o57_CBopen_ext_2nd : BOOL ;
  END_STRUCT ;
BEGIN
   o51_dutyPos := B#16#0;
   o51_OperatMode := B#16#0;
   o51_mode_bin := B#16#0;
   o51_mode_chg := B#16#0;
   o51_lockOrdChg := FALSE;
   o51_orderFail := FALSE;
   o51_blockD_OP := FALSE;
   o51_forceLocalGENOP := FALSE;
   o51_forceVisuOP := FALSE;
   o51_ackn_impulse := FALSE;
   o51_UBL_OP := FALSE;
   o51_i_pressCnfrm := FALSE;
   o51_mode_ind := B#16#0;
   o51_code1_8 := L#0;
   o51_code9_15 := L#0;
   o51_code1_8actCfg := L#0;
   o51_code9_15actCfg := L#0;
   o51_actCfgNo := B#16#0;
   o51_actCfgNo_rel := B#16#0;
   o51_act_partBus := B#16#0;
   o51_actCfg := W#16#0;
   o51_actTieCfg := B#16#0;
   o51_flashLED := B#16#0;
   o52_stdby_1st := FALSE;
   o52_stdby_2nd := FALSE;
   o52_SD := FALSE;
   o51_blockF_reset := FALSE;
   o52_lockSD_OP := FALSE;
   o51_newStation := FALSE;
   o51_test2_act := FALSE;
   o51_uncond_SemiS := FALSE;
   o52_stdbyNo_1st := B#16#0;
   o52_stdbyNo_2nd := B#16#0;
   o52_SDNo := B#16#0;
   o52_No_ofRunGen := B#16#0;
   o52_Rel_Stp2ndDG := FALSE;
   o51_fSemi_TBerr := FALSE;
   o51_rel_ownTB := FALSE;
   var053 := FALSE;
   var054 := FALSE;
   var055 := FALSE;
   var056 := FALSE;
   var057 := FALSE;
   o53_Gen_Available := FALSE;
   o53_Gen_Running := FALSE;
   o53_Gen_Blocked := FALSE;
   o53_req_Ustrt := FALSE;
   o53_ChOver_Semi := FALSE;
   o53_LoadRed := FALSE;
   o53_GenBrkOff_LoadRed := FALSE;
   o53_GenBrkOff := FALSE;
   o53_Gen_Starting := FALSE;
   o53_Blocked_Fault := FALSE;
   o53_Blocked_Switch := FALSE;
   o53_GenBrkTrip := FALSE;
   o53_extBlockDG := FALSE;
   var19 := FALSE;
   var20 := FALSE;
   var21 := FALSE;
   o50_In_fail := FALSE;
   o50_Out_fail := FALSE;
   var133 := FALSE;
   var134 := FALSE;
   var135 := FALSE;
   var136 := FALSE;
   var137 := FALSE;
   var138 := FALSE;
   var22 := B#16#0;
   var23 := FALSE;
   var24 := FALSE;
   var25 := FALSE;
   var26 := FALSE;
   var27 := FALSE;
   var28 := FALSE;
   var29 := FALSE;
   var30 := FALSE;
   var31 := B#16#0;
   o53_ExtStrtCmd := FALSE;
   var33 := FALSE;
   var34 := FALSE;
   var35 := FALSE;
   var36 := FALSE;
   var37 := FALSE;
   var38 := FALSE;
   var39 := FALSE;
   var40 := B#16#0;
   o57_req_simulLock := FALSE;
   o57_Brk_Ready_Standby := FALSE;
   o57_Brk_Ready_Closing := FALSE;
   o57_DelayStop := FALSE;
   o57_ChOver_Semi := FALSE;
   o57_req_Ustrt := FALSE;
   o57_UndelayStop := FALSE;
   o57_GenBrk_Failure := FALSE;
   o57_Blocking := FALSE;
   o57_extBlock := FALSE;
   o57_ExtCBopenCmd := FALSE;
   var483 := FALSE;
   var484 := FALSE;
   var485 := FALSE;
   var486 := FALSE;
   var487 := FALSE;
   var49 := FALSE;
   var50 := FALSE;
   var51 := FALSE;
   var52 := FALSE;
   var53 := FALSE;
   var54 := FALSE;
   var55 := FALSE;
   var56 := FALSE;
   var57 := B#16#0;
   o59_Start_Comm := FALSE;
   o59_Stop_Comm := FALSE;
   o59_Synchr_On := FALSE;
   o59_Synchr_Off := FALSE;
   o59_GenBrk_Off := FALSE;
   o59_LoadBal_On := FALSE;
   var58a := FALSE;
   var58 := FALSE;
   var60 := B#16#0;
   o59A_DStrtAbn := FALSE;
   o59A_BrkOpnAbn := FALSE;
   o59A_BrkClseAbn := FALSE;
   var61 := FALSE;
   var62 := FALSE;
   var63 := FALSE;
   var64 := FALSE;
   var65 := FALSE;
   var66 := B#16#0;
   o510_DstpAuto := FALSE;
   o510_BrkOpnAuto := FALSE;
   o510_loadLock := FALSE;
   var67 := FALSE;
   var68 := FALSE;
   var69 := FALSE;
   var70 := FALSE;
   var71 := FALSE;
   var72 := B#16#0;
   o511_Blackout := FALSE;
   o511_GenVolt_avail := FALSE;
   o511_req_Ustrt := FALSE;
   o511_Blocking := FALSE;
   o511_GenBrk_Off := FALSE;
   o511_ChOver_Blackout := FALSE;
   o511_Underload_Shd := FALSE;
   o511_UndelayStop := FALSE;
   o511_DstpE := FALSE;
   o511_Underload_Limit := FALSE;
   o511_UnitLock := FALSE;
   o511_ChOver_Semi := FALSE;
   o511_BusVolt_avail := FALSE;
   o511_ProtWarning := FALSE;
   o511_TrLBrk_Off := FALSE;
   var77 := FALSE;
   var78 := 0;
   o512_req_Ustrt := FALSE;
   o512_req_Ustrt2 := FALSE;
   o512_UndelayStop := FALSE;
   o512_DelayStop := FALSE;
   o512_MonitTime1 := FALSE;
   o512_MonitTime2 := FALSE;
   o512_EmergencyStop := FALSE;
   o512_Chover_Semi := FALSE;
   o512_Blocking := FALSE;
   o512_uness_1 := FALSE;
   o512_uness_2 := FALSE;
   o512_uness_3 := FALSE;
   o512_genBrk_off := FALSE;
   var855 := FALSE;
   var856 := FALSE;
   var857 := FALSE;
   o513_c_deload := FALSE;
   o513_c_lock_L_Ctrl := FALSE;
   o513_c_lock_F_Ctrl := FALSE;
   o513_c_UBLmin := FALSE;
   o513_c_UBLmode := FALSE;
   o513_i_UBLmin := FALSE;
   o513_i_UBLmode := FALSE;
   o513_c_stpPunder := FALSE;
   o513_f_deload := FALSE;
   o513_i_PBstpPos := FALSE;
   o513_i_SGonly := FALSE;
   o513_c_UBLoff_tooL := FALSE;
   o513_i_isochron := FALSE;
   o513_c_upload := FALSE;
   o513_i_extRel_Ctrl := FALSE;
   o513_i_Backup := FALSE;
   o513_s_UBL_load := 0;
   o513_expLoadOwn := 0;
   o513_NoActGen := 0;
   o513_s_actGen := 0;
   o513_c_isochron := FALSE;
   o513_c_up_speed := FALSE;
   o513_c_down_speed := FALSE;
   var964 := FALSE;
   var965 := FALSE;
   var966 := FALSE;
   var967 := FALSE;
   var968 := FALSE;
   var961 := B#16#0;
   var97 := 0;
   var98 := 0;
   var99 := 0;
   var100 := 0;
   var101 := 0;
   o515_c_reqStrt := FALSE;
   o515_c_req2Strt := FALSE;
   o515_c_reqEStrt := FALSE;
   o515_c_req2EStrt := FALSE;
   o515_c_genBrkOpn := FALSE;
   var105 := FALSE;
   o515_c_lockCtrl := FALSE;
   var107 := FALSE;
   o515_c_unitLock := FALSE;
   o515_c_simulLock := FALSE;
   o515_c_uncUBLoff := FALSE;
   o515_c_shoreOn := FALSE;
   o515_c_takeLoad := FALSE;
   o515_c_takePreSeOrd := FALSE;
   o515_c_preSeLock := FALSE;
   o515_c_life := FALSE;
   o515_f_auto := FALSE;
   o515_f_rdyStandby := FALSE;
   o515_f_brk_clse := FALSE;
   o515_f_onbus := FALSE;
   o515_f_lock := FALSE;
   o515_f_run := FALSE;
   o515_f_blackout := FALSE;
   o515_f_SGonbus := FALSE;
   var109 := FALSE;
   o515_f_preSeLock := FALSE;
   o515_f_i_SC := FALSE;
   o515_f_busy_Gset := FALSE;
   o515_f_UBL_on := FALSE;
   o515_f_shoreMode := FALSE;
   o515_f_rdy_swtchOn := FALSE;
   o515_f_shore_disconn := FALSE;
   o515_f_EB_busbar := FALSE;
   var110 := FALSE;
   o515_f_UBLmax_act := FALSE;
   o515_c_unessOff := FALSE;
   o515_c_UBL_MinLck := FALSE;
   o515_c_lockShtdwn := FALSE;
   o515_c_takeLckShtdn := FALSE;
   o515_f_allTieBrkOn := FALSE;
   o515_c_LckCtrl := FALSE;
   o515_c_takeLckCtrl := FALSE;
   o515_f_tieBrkOn := FALSE;
   o515_f_tieBrkTrip := FALSE;
   o515_f_exp_shr := FALSE;
   o515_f_2ndTieBrkOn := FALSE;
   o515_f_2ndtieBrkTrip := FALSE;
   var116c := FALSE;
   o515_a_load := 0;
   o515_s_ordSq1_8 := L#0;
   o515_s_ordSq9_15 := L#0;
   o15_a_busFreq := 0;
   o515_c_cont_up := FALSE;
   o515_c_long_up := FALSE;
   o515_c_short_up := FALSE;
   o515_c_cont_down := FALSE;
   o515_c_long_down := FALSE;
   o515_c_short_down := FALSE;
   o515_i_floatFreq := FALSE;
   var1187 := FALSE;
   o515_c_isochron := FALSE;
   o515_c_take_isochron := FALSE;
   var1192 := FALSE;
   var1193 := FALSE;
   var1194 := FALSE;
   var1195 := FALSE;
   var1196 := FALSE;
   var1197 := FALSE;
   var120 := 0;
   var121 := 0;
   o515R_c_reqStrt := FALSE;
   o515R_c_req2Strt := FALSE;
   o515R_c_reqEStrt := FALSE;
   o515R_c_req2EStrt := FALSE;
   o515R_c_genBrkOpn := FALSE;
   o515R_c_strtSet := FALSE;
   o515R_c_lock_Ctrl := FALSE;
   var124 := FALSE;
   o515R_c_unitLock := FALSE;
   o515R_c_simulLock := FALSE;
   o515R_c_uncUBLoff := FALSE;
   o515R_c_shoreOn := FALSE;
   o515R_c_takeLoad := FALSE;
   o515R_c_takePreSeOrd := FALSE;
   o515R_c_preSeLock := FALSE;
   var127 := FALSE;
   o515R_f_auto := FALSE;
   var129 := FALSE;
   o515R_f_brk_clse := FALSE;
   o515R_f_onbus := FALSE;
   var132 := FALSE;
   o515R_f_run := FALSE;
   o515R_f_blackout := FALSE;
   o515R_f_SGonbus := FALSE;
   var135a := FALSE;
   o515R_f_preSeLock := FALSE;
   o515R_f_i_SC := FALSE;
   o515R_f_busy_Gset := FALSE;
   var135b := FALSE;
   o515R_f_shoreMode := FALSE;
   o515R_f_rdy_swtchOn := FALSE;
   o515R_f_shore_dis := FALSE;
   o515R_f_EB_busbar := FALSE;
   var1101 := FALSE;
   var139a := FALSE;
   o515R_c_unessOff := FALSE;
   o515R_c_UBL_MinLck := FALSE;
   o515R_c_lockShtdwn := FALSE;
   o515R_c_takeLckShtdn := FALSE;
   o515R_f_AllTieBrkOn := FALSE;
   o515R_c_LckCtrl := FALSE;
   o515R_c_takeLckCtrl := FALSE;
   o515R_f_tieBrkOn := FALSE;
   o515R_f_tieBrkTrip := FALSE;
   o515R_f_shoreExp := FALSE;
   o515R_f_2ndTieBrkOn := FALSE;
   o515R_f_2ndtieBrkTrip := FALSE;
   var140d := FALSE;
   var147 := 0;
   o515R_s_ordSq1_8 := L#0;
   o515R_s_ordSq9_15 := L#0;
   o515R_a_busFreq := 0;
   o515R_c_cont_up := FALSE;
   o515R_c_long_up := FALSE;
   o515R_c_short_up := FALSE;
   o515R_c_cont_down := FALSE;
   o515R_c_long_down := FALSE;
   o515R_c_short_down := FALSE;
   o515R_i_floatFreq := FALSE;
   var1497 := FALSE;
   o515R_c_isochron := FALSE;
   o515R_c_take_isochron := FALSE;
   var1502 := FALSE;
   var1503 := FALSE;
   var1504 := FALSE;
   var1505 := FALSE;
   var1506 := FALSE;
   var1507 := FALSE;
   var151 := 0;
   var152 := FALSE;
   var1521 := FALSE;
   var1522 := FALSE;
   var1523 := FALSE;
   var1524 := FALSE;
   var1525 := FALSE;
   var1526 := FALSE;
   var1527 := FALSE;
   var1528 := FALSE;
   var1529 := FALSE;
   var15210 := FALSE;
   var15211 := FALSE;
   var15212 := FALSE;
   var15213 := FALSE;
   var15214 := FALSE;
   o515_LockShtdwnLoad := FALSE;
   o515_noCnfrm := FALSE;
   o515_ownBlock := FALSE;
   o515_monT_run := FALSE;
   o515_lockT_run := FALSE;
   o515_simulLockAct := FALSE;
   o515_simulLockErr := FALSE;
   o515_moreFaultyEssMPI := FALSE;
   o515_FaultyEssMPI := FALSE;
   o515_unessStation := DW#16#0;
   var200[1] := B#16#0;
   var200[2] := B#16#0;
   var200[3] := B#16#0;
   var200[4] := B#16#0;
   var200[5] := B#16#0;
   var200[6] := B#16#0;
   var200[7] := B#16#0;
   var200[8] := B#16#0;
   var210[1] := B#16#0;
   var210[2] := B#16#0;
   var210[3] := B#16#0;
   var210[4] := B#16#0;
   var210[5] := B#16#0;
   var210[6] := B#16#0;
   var210[7] := B#16#0;
   var210[8] := B#16#0;
   var210[9] := B#16#0;
   var210[10] := B#16#0;
   var220[1] := B#16#0;
   var220[2] := B#16#0;
   var220[3] := B#16#0;
   var220[4] := B#16#0;
   var220[5] := B#16#0;
   var220[6] := B#16#0;
   o523_Harbour_Mode := FALSE;
   o523_PowerFeedb_Mode := FALSE;
   o523_EmergGen_Mode := FALSE;
   o523_ChOver_Test_Auto := FALSE;
   o523_Start := FALSE;
   o523_DelStop := FALSE;
   o523_GenBrk_On := FALSE;
   o523_GenBrk_Off := FALSE;
   o523_GenBrk_Synchr := FALSE;
   var3009 := FALSE;
   var30010 := FALSE;
   var30011 := FALSE;
   var30012 := FALSE;
   var30013 := FALSE;
   var30014 := FALSE;
   var30015 := FALSE;
   o520_closeBrk_A := FALSE;
   o520_closeBrk_B := FALSE;
   o520_simLock_fail := FALSE;
   o520_clsPrcBrk_A := FALSE;
   o520_clsPrcBrk_B := FALSE;
   o520_blockTBopn := FALSE;
   var1626 := FALSE;
   var1627 := FALSE;
   o57_CBopen_ext_2nd := FALSE;
END_DATA_BLOCK



DATA_BLOCK "I_MMI_SR"
TITLE =Interface MMI. The 1. part contains the send area,
//the 2.part the receive area.                                                     !
//
//V 1.7 05.12.00 Kahle -DBX2.7 i_GenBrk_Norm
//                                   DBX21.0 e_CB_ContrVolt
//                                   DBX21.1 e_SF6_GasAlarm
//                                   DBX21.2 e_EarthFault
//                                   DBX21.3 e_VoltTransf_Fault
//                                   DBX21.4 e_CB_Eathed
//                                   DBX195.7 c_block_GenSetOn
//                                   DBX196.0 c_block_GenSetOff
//                                   DBX196.1 c_increase
//                                   DBX196.2 c_decrease
//                                   DBX196.3 c_rstEGmode
//                                   DBX196.4 c_isochron
//                                   DBX196.5 c_droop
//V1.8 14.02.01 Kahle -DBX21.5 e_CB_BlockingRelay
//                                 -DBX21.6 e_CB_OpenPos
//                                 -DBX21.7 e_MinorAlarm
//                                 -DBX30.4 e _InputCard
//                                  DBX30.5 e_OutputCard
//
// I_MMI_SR
// Sende-/Empfangsfach MMI
//  Im 1.Teil des DB's liegt das Sendefach, während das Empfangsfach sich im zweiten Teil
//  befindet.
//
//  Der DB ist die zentrale Schnittstelle zwischen Bediener und PMA-Steuerung. Die Daten des
//  Sendefaches werden in Abhängigkeit des Bedienortes (OP, BuB) in die entsprechenden
//  Ausgangsfächer transferiert, während umgekehrt die Daten in das Empfangsfach kopiert werden.
//
//  Die Parameter werden nicht über diese Schnittstelle (I_MMI_SR) geführt, sondern direkt in den
//  Parameter-DB der PMA (prm_pma) transferiert, bzw. von dort abgeholt.
//
//  Daten, die das Generatorschutzgerät (Genop71) betreffen werden ebenfalls direkt in dessen
//  Sendefach (I_prtcSR)geschrieben bzw. werden direkt aus dessen Empfangsfach(I_prtcSR) ausgelesen.
//
//  Siemens AG ATD IS3T, Kahle +494028892022, jens.kahle@hbg.siemens.de
//  PMA71
//  =Internal Modul Memory
//  Datum aktuelle Version: 02.05.99
//  Version,Änd-Datum, Bearbeiter, geänderte Variablen
//  1.01   ,31.01.99 , Kahle     , 1.Version
//  1.02   ,20.02.99 , Kahle     , Anwahl Konfigurationen
//  1.03   ,10.03.99 , Kahle     , e_orderChg_fail, i_UnitRdyStrt,
//     i_DstrtAct, i_DstpAct, i_D_lock
//  1.04,   02.05.99,  Kahle,      Überarbeitung aller Anzeigen &Alarme
//KNOW_HOW_PROTECT
// (If specified, no more changes can be made once the block is generated)
//UNLINKED
// (If specified, the generated block is only available in the PLC load
//  memory)
//READ_ONLY
// (If specified, the generated block cannot be changed in the programmable
//  controller)
AUTHOR : Kahle
FAMILY : PMA71
NAME : I_MMI_SR
VERSION : 1.9


  STRUCT
   i_noStpULoad : BOOL ;    //Indication: No stop in case of underload
   var01 : BOOL ;
   var02 : BOOL ;
   var03 : BOOL ;
   var04 : BOOL ;
   var05 : BOOL ;
   var06 : BOOL ;
   var07 : BOOL ;
   i_Gen_run : BOOL ;   //Indication: DG/SG/EG running
   i_Gen_stp : BOOL ;   //Indication: DG/SG/EG not running
   i_Gen_strtAct : BOOL ;   //Indication: DG/SG/EG starting
   i_Gen_stpAct : BOOL ;    //Indication: DG/SG/EG stopping
   i_Gen_lock : BOOL ;
   i_Gen_RdyStrt : BOOL ;   //Indication: DG/SG/EG ready for start
   var16 : BOOL ;
   var17 : BOOL ;
   i_GenBrkClse : BOOL ;    //Indication: Generator breaker closed
   i_GenBrkOpn : BOOL ; //Indication: Generator breaker open
   i_GenBrkClseAct : BOOL ; //Indication: Generator breaker closing active
   i_GenBrkOpnAct : BOOL ;  //Indication: Generator breaker opening active
   i_UnitActive : BOOL ;    //Indication: Generator set in Automatic on busbar
   var25 : BOOL ;
   i_GenBrk_rdy : BOOL ;    //Indication: Generator breaker ready
   i_GenBrk_Norm : BOOL ;   //Indication: Generator breaker in position "Normal"
   var30 : BOOL ;
   var31 : BOOL ;
   var32 : BOOL ;
   var33 : BOOL ;
   var34 : BOOL ;
   var35 : BOOL ;
   var36 : BOOL ;
   var37 : BOOL ;
   var40 : BOOL ;
   var41 : BOOL ;
   var42 : BOOL ;
   var43 : BOOL ;
   var44 : BOOL ;
   var45 : BOOL ;
   var46 : BOOL ;
   var47 : BOOL ;
   var50 : BOOL ;
   var51 : BOOL ;
   var52 : BOOL ;
   var53 : BOOL ;
   var54 : BOOL ;
   var55 : BOOL ;
   var56 : BOOL ;
   var57 : BOOL ;
   var60 : BOOL ;
   var61 : BOOL ;
   var62 : BOOL ;
   var63 : BOOL ;
   var64 : BOOL ;
   var65 : BOOL ;
   var66 : BOOL ;
   var67 : BOOL ;
   var70 : BOOL ;
   var71 : BOOL ;
   var72 : BOOL ;
   var73 : BOOL ;
   var74 : BOOL ;
   var75 : BOOL ;
   var76 : BOOL ;
   var77 : BOOL ;
   var80 : BOOL ;
   var81 : BOOL ;
   var82 : BOOL ;
   var83 : BOOL ;
   var84 : BOOL ;
   var85 : BOOL ;
   var86 : BOOL ;
   var87 : BOOL ;
   var90 : BOOL ;
   var91 : BOOL ;
   var92 : BOOL ;
   var93 : BOOL ;
   var94 : BOOL ;
   var95 : BOOL ;
   var96 : BOOL ;
   var97 : BOOL ;
   var100 : BOOL ;
   var101 : BOOL ;
   var102 : BOOL ;
   var103 : BOOL ;
   var104 : BOOL ;
   var105 : BOOL ;
   var106 : BOOL ;
   var107 : BOOL ;
   var110 : BOOL ;
   var111 : BOOL ;
   var112 : BOOL ;
   var113 : BOOL ;
   var114 : BOOL ;
   var115 : BOOL ;
   var116 : BOOL ;
   var117 : BOOL ;
   i_TrsBrkClse : BOOL ;    //Indication: Transfer line circuit breaker closed [EG]
   i_TrsBrkOpn : BOOL ; //Indication: Transfer line circuit breaker open [EG]
   i_TrsBrkClseAct : BOOL ; //Indication: Transfer line circuit breaker closing active [EG]
   i_TrsBrkOpnAct : BOOL ;  //Indication: Transfer line circuit breaker opening active [EG]
   i_EmergTrfmr1_on : BOOL ;    //Indication: Emergency transformer 1 on [EG]
   i_EmergTrfmr2_on : BOOL ;    //Indication: Emergency transformer 2 on [EG]
   i_SupEmgTrfmr1_on : BOOL ;   //Indication: Supply emergency transformer 1 on [EG]
   i_SupEmgTrfmr2_on : BOOL ;   //Indication: Supply emergency transformer 2 on [EG]
   e_local : BOOL ; //Alarm: Generator set in Manual/Local
   e_OP_err : BOOL ;    //Alarm: OP Failure
   e_visu_err : BOOL ;  //Alarm: Visualization failure
   var133 : BOOL ;
   var134 : BOOL ;
   e_SqChg : BOOL ; //Alarm: Change Start/Stop Sequence not possible
   e_batt_fail : BOOL ; //Alarm: PLC battery low
   e_noUTC : BOOL ; //Alarm: ULC not vaild
   e_Start_Fail : BOOL ;    //Alarm: DG/SG/EG start failure
   e_Stop_Fail : BOOL ; //Alarm: DG/SG/EG stopping failure
   e_IgnSp_RelGenBrk_Fail : BOOL ;  //Alarm: Signal "Ignit. speed"/"Release gen. breaker" missing (but gen. volt. On)
   e_GenVolt_Fail : BOOL ;  //Alarm: Generator voltage missing (but "Ignit. speed"/"Release gen. breaker" On)
   var144 : BOOL ;
   var145 : BOOL ;
   e_Block_PreLubOil : BOOL ;   //Alarm: DG/EG blocked by "Low prelubrication oil pressure"
   e_DiesEngine_Fail : BOOL ;   //Alarm: Diesel engine failure [DG,EG]
   e_brk_trip : BOOL ;  //Alarm: Generator breaker tripped
   e_Changeov_Blackout : BOOL ; //Alarm: Generator breaker tripped for changeover via blackout
   e_brk_on_fail : BOOL ;   //Alarm: Generator breaker closing failure
   e_brk_off_fail : BOOL ;  //Alarm: Generator breaker opening failure
   e_brk_onOff_fail : BOOL ;    //Alarm: Plausibility failure generator breaker On / Off
   e_brk_ready_fail : BOOL ;    //Alarm: Generator breaker not ready
   e_SimLock_Fail : BOOL ;  //Alarm: Simultaneous lock time exceeded (Feedback from other gen. set missing)
   e_SynchrTime_Fail : BOOL ;   //Alarm: Synchronizing time exceeded
   e_blackout : BOOL ;  //Alarm: Blackout
   e_BusBar_Monit_Fail : BOOL ; //Alarm: Busbar monitoring failure
   e_i_SC : BOOL ;  //Alarm: Short circuit
   e_Prtct_fail : BOOL ;    //Alarm: Generator protection unit failure
   e_Curr_Monit_Fail : BOOL ;   //Alarm: Current monitoring failure
   e_UnderlShd_Ann : BOOL ; //Alarm: Underload shutdown, annunciation
   e_UnderlShd_Act : BOOL ; //Alarm: Underload shutdown, activation
   e_ShCirc_OtherSet : BOOL ;   //Alarm: Short circuit of other generator set (blocking of own set)
   e_StStart : BOOL ;   //Alarm: Standby start by overcurrent, overload, etc.
   e_NEconsu1off : BOOL ;   //Alarm: Trip of unessential consumers step 1
   e_NEconsu2off : BOOL ;   //Alarm: Trip of unessential consumers step 2
   e_NEconsu3off : BOOL ;   //Alarm: Trip of unessential consumers step 3
   e_GenBrkOff_Prtct : BOOL ;   //Alarm: Trip of generator breaker by overcurrent
   e_RevPower : BOOL ;  //Alarm: Trip of generator breaker by reverse power
   e_Underfrequ1 : BOOL ;   //Alarm: Underfrequency 1
   e_Underfrequ2 : BOOL ;   //Alarm: Underfrequency 2
   e_Underfrequ3 : BOOL ;   //Alarm: Underfrequency 3
   e_Overfrequ : BOOL ; //Alarm: Overfrequency
   e_Undervolt1 : BOOL ;    //Alarm: Undervoltage 1
   e_Undervolt2 : BOOL ;    //Alarm: Undervoltage 2
   e_warnDiffProtect : BOOL ;   //Warning: Differential protection
   e_Overvolt1 : BOOL ; //Alarm: Overvoltage 1
   e_BlackoutExp : BOOL ;   //Alarm: Blackout expected
   e_WindOvertemp : BOOL ;  //Alarm: Generator winding overtemperature
   e_DiffProt_Failure : BOOL ;  //Alarm: Failure of differential protection device
   e_DiffProt_Trip : BOOL ; //Alarm: Trip of generator breaker by differential protection
   e_StopNotPermit : BOOL ; //Alarm: Stop via pushbutton in automatic not permitted
   e_GenBrk_TestPos : BOOL ;    //Alarm: Generator breaker in test position
   e_GenBrk_ShoreConn : BOOL ;  //Alarm: Generator breaker blocked by shore connection
   e_LoadTooLow : BOOL ;    //Alarm: Load too low for generator set
   var196 : BOOL ;
   var197 : BOOL ;
   e_loadTooHigh_shore : BOOL ; //Alarm: Load too high -shore connection-
   e_adjustVolt_shore : BOOL ;  //Alarm: Adjusting voltage not correct -shore connection-
   e_warnBlackout_shore : BOOL ;    //Warning: Blackout because of standby start but no set in automatic -shore conne
   e_Blackout_shore : BOOL ;    //Alarm: Blackout becauce of standby start but no set in automatic -shore connect
   e_warnCurrent1 : BOOL ;  //Warning: current limit 1 exceeded
   e_warnCurrent2 : BOOL ; //Warning: current limit 2 exceeded
   e_warnload1 : BOOL ; //Warning: load limit 1 exceeded
   e_warnload2 : BOOL ; //Warning: load limit 2 exceeded
   e_CB_ContrVolt : BOOL ;  //Alarm: CB control voltage fault
   e_SF6_GasAlarm : BOOL ;  //Alarm: SF6 Gas pressure alarm
   e_EarthFault : BOOL ;    //Alarm: Earth fault
   e_VoltTransf_Fault : BOOL ;  //Alarm: Voltage transformer fault
   e_CB_Earthed : BOOL ;    //Alarm: CB earthed
   e_CB_BlockingRelay : BOOL ;  //Alarm: CB blocking relay activated (short circuit)
   e_CB_TestPos : BOOL ;    //Alarm: CB in test position
   e_MinorAlarm : BOOL ;    //Alarm: Woodward Minor alarm
   e_BusBar_Monit_Fail_Tie : BOOL ; //Alarm: Busbar monitoring failure [tie breaker]
   var221 : BOOL ;
   var222 : BOOL ;
   var223 : BOOL ;
   var224 : BOOL ;
   var225 : BOOL ;
   var226 : BOOL ;
   var227 : BOOL ;
   e_SD_C1 : BOOL ; //Alarm: Shutdown Channel 1
   e_SD_C2 : BOOL ; //Alarm: Shutdown Channel 2
   e_SD_C3 : BOOL ; //Alarm: Shutdown Channel 3
   e_SD_C4 : BOOL ; //Alarm: Shutdown Channel 4
   e_SD_C5 : BOOL ; //Alarm: Shutdown Channel 5
   e_SD_C6 : BOOL ; //Alarm: Shutdown Channel 6
   e_SD_C7 : BOOL ; //Alarm: Shutdown Channel 7
   e_SD_C8 : BOOL ; //Alarm: Shutdown Channel 8
   e_wirebrk_C1 : BOOL ;    //Alarm: Wire breakage SD channel 1
   e_wirebrk_C2 : BOOL ;    //Alarm: Wire breakage SD channel 2
   e_wirebrk_C3 : BOOL ;    //Alarm: Wire breakage SD channel 3
   e_wirebrk_C4 : BOOL ;    //Alarm: Wire breakage SD channel 4
   e_wirebrk_C5 : BOOL ;    //Alarm: Wire breakage SD channel 5
   e_wirebrk_C6 : BOOL ;    //Alarm: Wire breakage SD channel 6
   e_wirebrk_C7 : BOOL ;    //Alarm: Wire breakage SD channel 7
   e_wirebrk_C8 : BOOL ;    //Alarm: Wire breakage SD channel 8
   e_EMStpMan : BOOL ;  //Alarm: Emergency stop manual [DG,EG]
   e_Prealarm : BOOL ;  //Alarm: Prealarm [DG,EG]
   e_Sensor_SD_C2 : BOOL ;  //Alarm: Sensor failure SD channel 2 (Low lub oil pressure) [DG,EG]
   var253 : BOOL ;
   e_wirebrk_V1 : BOOL ;    //Alarm: Wire breakage start valve [DG,EG]
   e_wirebrk_V2 : BOOL ;    //Alarm: Wire breakage stop valve [DG,EG]
   e_wirebrk_V3 : BOOL ;    //Alarm: Wire breakage emergency stop valve [DG,EG]
   e_wirebrk_V4 : BOOL ;    //Alarm: Wire breakage suppression valve [DG,EG]
   var260 : BOOL ;
   var261 : BOOL ;
   var262 : BOOL ;
   var263 : BOOL ;
   e_deviL_FCtrl : BOOL ;   //Alarm: Not aceptable deviation Load-/Frequency controller
   e_UBLmax_tooLow : BOOL ; //Alarm: UBL max value is too low
   var266 : BOOL ;
   var267 : BOOL ;
   e_linkT1 : BOOL ;    //Alarm: Link to tie breaker 1 faulty
   e_linkT2 : BOOL ;    //Alarm: Link to tie breaker 2 faulty
   e_linkT3 : BOOL ;    //Alarm: Link to tie breaker 3 faulty
   e_linkT4 : BOOL ;    //Alarm: Link to tie breaker 4 faulty
   e_linkG1 : BOOL ;    //Alarm: Link to generator 1 faulty
   e_linkG2 : BOOL ;    //Alarm: Link to generator 2 faulty
   e_linkG3 : BOOL ;    //Alarm: Link to generator 3 faulty
   e_linkG4 : BOOL ;    //Alarm: Link to generator 4 faulty
   e_linkG5 : BOOL ;    //Alarm: Link to generator 5 faulty
   e_linkG6 : BOOL ;    //Alarm: Link to generator 6 faulty
   e_linkG7 : BOOL ;    //Alarm: Link to generator 7 faulty
   e_linkG8 : BOOL ;    //Alarm: Link to generator 8 faulty
   e_linkG9 : BOOL ;    //Alarm: Link to generator 9 faulty
   e_linkG10 : BOOL ;   //Alarm: Link to generator 10 faulty
   e_linkG11 : BOOL ;   //Alarm: Link to generator 11 faulty
   e_linkG12 : BOOL ;   //Alarm: Link to generator 12 faulty
   e_linkG13 : BOOL ;   //Alarm: Link to generator 13 faulty
   e_linkEG : BOOL ;    //Alarm: Link to emergency generator faulty
   e_linkS1 : BOOL ;    //Alarm: Link to shore connection 1 faulty
   e_linkS2 : BOOL ;    //Alarm: Link to shore connection 2 faulty
   e_noStpDiesel : BOOL ;
   e_standByStart : BOOL ;
   e_takeOverLoad : BOOL ;
   e_OLM : BOOL ;   //Alarm: OLM failure
   e_MCB24_trip : BOOL ;    //Alarm: MCB DC 24V Control voltage tripped
   e_CB440G_trip : BOOL ;   //Alarm: CB AC 440V Generator voltage tripped
   e_CB440B_trip : BOOL ;   //Alarm: CB AC 440V Busbar voltage tripped
   e_TieBrkOpn : BOOL ; //Alarm: Bus tie breaker open
   e_InputCard : BOOL ; //Alarm: input card failure
   e_OutputCard : BOOL ;    //Alarm: output card failure
   e_brkTripExt : BOOL ;    //Alarm: shore connection breaker is tripped
   e_noLoadheavyCon : BOOL ;    //Warning: not enough load for heavy consumer
   w_takeOverLoad : BOOL ;
   e_Overvolt2 : BOOL ; //Alarm: Overvoltage 2 (Blocking of voltage controller, deexitation)
   e_Al_Low_LubOil_Press : BOOL ;   //Alarm: Low lub oil pressure or shutdown channel 2 [EG]
   e_Al_High_LubOil_Temp : BOOL ;   //Alarm: High lub oil temperature [EG]
   e_Al_High_CoolW_Temp : BOOL ;    //Alarm: High cooling water temperature or shutdown channel 3 [EG]
   e_Al_Low_CoolW_Level : BOOL ;    //Alarm: Low cooling water level [EG]
   e_Al_Leak_Fuel_Pipe : BOOL ; //Alarm: Leak in fuel pipe [EG]
   e_WindOvertemp_Warn : BOOL ; //Warning: winding overtemperature
   e_Al_SD_Channel_4 : BOOL ;   //Alarm: Shutdown channel 4 [EG]
   var321 : BOOL ;
   var322 : BOOL ;
   var323 : BOOL ;
   w_Gen_I_E : BOOL ;   //Warning: Generator current [EG]
   w_Gen_P_E : BOOL ;   //Warning: Generator power [EG]
   w_Bus_f_E : BOOL ;   //Warning: Busbar frequency [EG]
   w_Bus_V_E : BOOL ;   //Warning: Busbar voltage [EG]
   e_TrBrk_tripI_E : BOOL ; //Alarm: Transfer line circuit breaker tripped by current [EG]
   e_TrBrk_tripP_E : BOOL ; //Alarm: Transfer line circuit breaker tripped by power [EG]
   e_TrBrk_tripf_E : BOOL ; //Alarm: Transfer line circuit breaker tripped by frequency [EG]
   e_TrBrk_triprP_E : BOOL ;    //Alarm: Transfer line circuit breaker tripped by reverse power [EG]
   e_CB440T_trip_E : BOOL ; //Alarm: CB AC 440V Transfer line voltage tripped
   e_I_SC_TrBrk_E : BOOL ;  //Alarm: Short circuit transfer line circuit breaker [EG]
   e_NoCycleBrkFail_E : BOOL ;  //Alarm: Number of permisseble operating cycles of generator breaker reached [EG]
   e_TrBrk_trip_E : BOOL ;  //Alarm: Transfer line circuit breaker tripped [EG]
   e_TrBrk_on_fail_E : BOOL ;   //Alarm: Transfer line circuit breaker closing failure [EG]
   e_TrBrk_off_fail_E : BOOL ;  //Alarm: Transfer line circuit breaker opening failure [EG]
   e_TrBrk_onOff_fail_E : BOOL ;    //Alarm: Plausibility failure transfer line circuit breaker On/Off [EG]
   e_TrBrk_ready_fail_E : BOOL ;    //Alarm: Transfer line circuit breaker not ready [EG]
   e_TrBrk_tripV_E : BOOL ; //Alarm: Transfer line circuit breaker tripped by voltage [EG]
   var345 : BOOL ;
   var346 : BOOL ;
   var347 : BOOL ;
   e_alarm_SD5_EG : BOOL ;  //Alarm: Shutdown 5 [EG]
   e_alarm_SD6_EG : BOOL ;  //Alarm: Shutdown 6 [EG]
   e_alarm_SD7_EG : BOOL ;  //Alarm: Shutdown 7 [EG]
   e_alarm_SD8_EG : BOOL ;  //Alarm: Shutdown 8 [EG]
   var354 : BOOL ;
   var355 : BOOL ;
   var356 : BOOL ;
   var357 : BOOL ;
   a_OrdSeq1_8 : ARRAY  [1 .. 8 ] OF //Selected start-/stop sequence -part 1-
   BYTE ;   //Start-Reihenfolge - (1. -8.Generator) -
   a_OrdSeq9_15 : ARRAY  [1 .. 8 ] OF //Selected start-/stop sequence -part 2-
   BYTE ;   //Start-Reihenfolge - (9. -15.Generator) -
   a_pmaMode : BYTE ;   //Active operating mode -local, semi, auto
   act_dutyPos : BYTE ; //Active operating position -OP, visualization
   var540 : BYTE ;
   var550 : BYTE ;
   var560 : INT ;
   var580 : INT ;
   a_GenSet_stat_ind : INT ;    //Generator set state 1/2 -ind-
   a_GenSet_stat_var : INT ;    //Generator set state 2/2 -var-
   a_UTC : DATE_AND_TIME ;  //actual value UTC
   var720 : INT ;
   var740 : BYTE ;
   var760 : INT ;
   var780 : INT ;
   var800 : INT ;
   var820 : INT ;
   a_GclseCriteria : BYTE ; //GenBrk close: ready criteria for OP indication
   var850 : BYTE ;
   var860 : INT ;
   var880 : INT ;
   var900 : BYTE ;
   var910 : BYTE ;
   var920 : BYTE ;
   var930 : BYTE ;
   var940 : INT ;
   var960 : INT ;
   var980 : INT ;
   var1000 : INT ;
   var1020 : BYTE ;
   var1030 : BYTE ;
   var1040 : INT ;
   var1060 : INT ;
   var1080 : INT ;
   var1100 : INT ;
   var1120 : INT ;
   var1140 : INT ;
   a_UBLmax : INT ;   //actual value setpoint UBL max
   a_UBLmin : INT ; //actual value setpoint UBL min
   var1200 : INT ;
   var1220 : INT ;
   var1240 : INT ;
   var1260 : INT ;
   var1280 : INT ;
   var1300 : INT ;
   var1320 : INT ;
   var1340 : INT ;
   var1360 : INT ;
   var1380 : INT ;
   var1400 : INT ;
   var1420 : INT ;
   var1440 : INT ;
   var1460 : INT ;
   var1480 : INT ;
   var1500 : INT ;
   var1520 : INT ;
   var1540 : INT ;
   var1560 : INT ;
   var1580 : INT ;
   var1600 : INT ;
   var1620 : INT ;
   var1640 : INT ;
   var1660 : INT ;
   var1680 : INT ;
   var1700 : INT ;
   var1720 : INT ;
   var1740 : INT ;
   var1760 : INT ;
   var1780 : INT ;
   var1800 : INT ;
   var1820 : INT ;
   var1840 : INT ;
   var1860 : INT ;
   var1880 : INT ;
   var1900 : INT ;
   var1920 : INT ;  //++++ last Send Var ++++
   c_rst_alm : BOOL ;   //Alarm reset
   var1941 : BOOL ;
   var1942 : BOOL ;
   var1943 : BOOL ;
   c_Dstrt : BOOL ;   //Diesel start by the operator
   c_Dstp : BOOL ;  //Diesel stop by the operator
   var1946 : BOOL ;
   var1947 : BOOL ;
   c_genBrk_clse : BOOL ;   //Generator breaker close by the operator
   var1951 : BOOL ;
   c_genBrk_opn : BOOL ;    //Generator breaker open by the operator
   var1953 : BOOL ;
   var1954 : BOOL ;
   c_Ustrt : BOOL ; //Generator set start by the operator
   c_Ustp : BOOL ;  //Generator set stop by the operator
   c_block_GenSetOn : BOOL ;    //Block generator set on by operator
   c_block_GenSetOff : BOOL ;   //Block generator set off by operator
   c_increase : BOOL ;  //Increase load
   c_decrease : BOOL ;  //Decrease load
   c_rstEGmode : BOOL ; //Command: Reset EG mode
   c_isochron : BOOL ;  //Command: isochron mode
   c_droop : BOOL ; //Command: droop mode
   var1966 : BOOL ;
   var1967 : BOOL ;
   c_UBLon : BOOL ; //Command: Activate the UBL mode
   c_UBLoff : BOOL ;    //Command: Deactivate the UBL mode
   var1972 : BOOL ;
   var1973 : BOOL ;
   c_noStpULoad : BOOL ;  //Command: no stop in case of underload
   c_rstnoStpULoad : BOOL ; //Command: reset no stop in case of underload
   var1976 : BOOL ;
   e_linkfail : BOOL ;  //link to the monitoring system faulty
   var1980 : BOOL ;
   var1981 : BOOL ;
   var1982 : BOOL ;
   var1983 : BOOL ;
   var1984 : BOOL ;
   var1985 : BOOL ;
   var1986 : BOOL ;
   var1987 : BOOL ;
   c_strtStandby : BOOL ;   //Start of the generator set which are standing in standby
   var1991 : BOOL ;
   var1992 : BOOL ;
   var1993 : BOOL ;
   var1994 : BOOL ;
   var1995 : BOOL ;
   var1996 : BOOL ;
   var1997 : BOOL ;
   var2000 : BOOL ;
   var2001 : BOOL ;
   var2002 : BOOL ;
   var2003 : BOOL ;
   c_TrBrk_clse : BOOL ;    //Command: Transfer breaker close [EG only]
   c_TrBrk_opn : BOOL ; //Command: Transfer breaker open [EG only]
   var2006 : BOOL ;
   var2007 : BOOL ;
   var2010 : BOOL ;
   var2011 : BOOL ;
   var2012 : BOOL ;
   var2013 : BOOL ;
   var2014 : BOOL ;
   var2015 : BOOL ;
   var2016 : BOOL ;
   var2017 : BOOL ;
   var2020 : BYTE ;
   var2030 : BYTE ;
   s_OrdSeq1_8 : ARRAY  [1 .. 8 ] OF //New selected start-/stop sequence -part 1-
   BYTE ;   //Start-Reihenfolge - (1. -8.Generator) -
   s_OrdSeq9_15 : ARRAY  [1 .. 8 ] OF //New selected start-/stop sequence -part 2-
   BYTE ;   //Start-Reihenfolge - (9. -15.Generator) -
   s_PreMode : BYTE ;   //Preselected operating mode
   var2210 : BYTE ;
   s_UBLmax : INT ; //setpoint UBLmax value [in KW]
   s_UBLmin : INT ; //setpoint UBLmin value [in kW]
   var2260 : INT ;
   s_UTC : DATE_AND_TIME ;  //setpoint UTC
   var2360 : INT ;
   var2380 : INT ;
   var2400 : INT ;
   var2420 : INT ;
   var2440 : INT ;
   var2460 : INT ;
  END_STRUCT ;
BEGIN
   i_noStpULoad := FALSE;
   var01 := FALSE;
   var02 := FALSE;
   var03 := FALSE;
   var04 := FALSE;
   var05 := FALSE;
   var06 := FALSE;
   var07 := FALSE;
   i_Gen_run := FALSE;
   i_Gen_stp := FALSE;
   i_Gen_strtAct := FALSE;
   i_Gen_stpAct := FALSE;
   i_Gen_lock := FALSE;
   i_Gen_RdyStrt := FALSE;
   var16 := FALSE;
   var17 := FALSE;
   i_GenBrkClse := FALSE;
   i_GenBrkOpn := FALSE;
   i_GenBrkClseAct := FALSE;
   i_GenBrkOpnAct := FALSE;
   i_UnitActive := FALSE;
   var25 := FALSE;
   i_GenBrk_rdy := FALSE;
   i_GenBrk_Norm := FALSE;
   var30 := FALSE;
   var31 := FALSE;
   var32 := FALSE;
   var33 := FALSE;
   var34 := FALSE;
   var35 := FALSE;
   var36 := FALSE;
   var37 := FALSE;
   var40 := FALSE;
   var41 := FALSE;
   var42 := FALSE;
   var43 := FALSE;
   var44 := FALSE;
   var45 := FALSE;
   var46 := FALSE;
   var47 := FALSE;
   var50 := FALSE;
   var51 := FALSE;
   var52 := FALSE;
   var53 := FALSE;
   var54 := FALSE;
   var55 := FALSE;
   var56 := FALSE;
   var57 := FALSE;
   var60 := FALSE;
   var61 := FALSE;
   var62 := FALSE;
   var63 := FALSE;
   var64 := FALSE;
   var65 := FALSE;
   var66 := FALSE;
   var67 := FALSE;
   var70 := FALSE;
   var71 := FALSE;
   var72 := FALSE;
   var73 := FALSE;
   var74 := FALSE;
   var75 := FALSE;
   var76 := FALSE;
   var77 := FALSE;
   var80 := FALSE;
   var81 := FALSE;
   var82 := FALSE;
   var83 := FALSE;
   var84 := FALSE;
   var85 := FALSE;
   var86 := FALSE;
   var87 := FALSE;
   var90 := FALSE;
   var91 := FALSE;
   var92 := FALSE;
   var93 := FALSE;
   var94 := FALSE;
   var95 := FALSE;
   var96 := FALSE;
   var97 := FALSE;
   var100 := FALSE;
   var101 := FALSE;
   var102 := FALSE;
   var103 := FALSE;
   var104 := FALSE;
   var105 := FALSE;
   var106 := FALSE;
   var107 := FALSE;
   var110 := FALSE;
   var111 := FALSE;
   var112 := FALSE;
   var113 := FALSE;
   var114 := FALSE;
   var115 := FALSE;
   var116 := FALSE;
   var117 := FALSE;
   i_TrsBrkClse := FALSE;
   i_TrsBrkOpn := FALSE;
   i_TrsBrkClseAct := FALSE;
   i_TrsBrkOpnAct := FALSE;
   i_EmergTrfmr1_on := FALSE;
   i_EmergTrfmr2_on := FALSE;
   i_SupEmgTrfmr1_on := FALSE;
   i_SupEmgTrfmr2_on := FALSE;
   e_local := FALSE;
   e_OP_err := FALSE;
   e_visu_err := FALSE;
   var133 := FALSE;
   var134 := FALSE;
   e_SqChg := FALSE;
   e_batt_fail := FALSE;
   e_noUTC := FALSE;
   e_Start_Fail := FALSE;
   e_Stop_Fail := FALSE;
   e_IgnSp_RelGenBrk_Fail := FALSE;
   e_GenVolt_Fail := FALSE;
   var144 := FALSE;
   var145 := FALSE;
   e_Block_PreLubOil := FALSE;
   e_DiesEngine_Fail := FALSE;
   e_brk_trip := FALSE;
   e_Changeov_Blackout := FALSE;
   e_brk_on_fail := FALSE;
   e_brk_off_fail := FALSE;
   e_brk_onOff_fail := FALSE;
   e_brk_ready_fail := FALSE;
   e_SimLock_Fail := FALSE;
   e_SynchrTime_Fail := FALSE;
   e_blackout := FALSE;
   e_BusBar_Monit_Fail := FALSE;
   e_i_SC := FALSE;
   e_Prtct_fail := FALSE;
   e_Curr_Monit_Fail := FALSE;
   e_UnderlShd_Ann := FALSE;
   e_UnderlShd_Act := FALSE;
   e_ShCirc_OtherSet := FALSE;
   e_StStart := FALSE;
   e_NEconsu1off := FALSE;
   e_NEconsu2off := FALSE;
   e_NEconsu3off := FALSE;
   e_GenBrkOff_Prtct := FALSE;
   e_RevPower := FALSE;
   e_Underfrequ1 := FALSE;
   e_Underfrequ2 := FALSE;
   e_Underfrequ3 := FALSE;
   e_Overfrequ := FALSE;
   e_Undervolt1 := FALSE;
   e_Undervolt2 := FALSE;
   e_warnDiffProtect := FALSE;
   e_Overvolt1 := FALSE;
   e_BlackoutExp := FALSE;
   e_WindOvertemp := FALSE;
   e_DiffProt_Failure := FALSE;
   e_DiffProt_Trip := FALSE;
   e_StopNotPermit := FALSE;
   e_GenBrk_TestPos := FALSE;
   e_GenBrk_ShoreConn := FALSE;
   e_LoadTooLow := FALSE;
   var196 := FALSE;
   var197 := FALSE;
   e_loadTooHigh_shore := FALSE;
   e_adjustVolt_shore := FALSE;
   e_warnBlackout_shore := FALSE;
   e_Blackout_shore := FALSE;
   e_warnCurrent1 := FALSE;
   e_warnCurrent2 := FALSE;
   e_warnload1 := FALSE;
   e_warnload2 := FALSE;
   e_CB_ContrVolt := FALSE;
   e_SF6_GasAlarm := FALSE;
   e_EarthFault := FALSE;
   e_VoltTransf_Fault := FALSE;
   e_CB_Earthed := FALSE;
   e_CB_BlockingRelay := FALSE;
   e_CB_TestPos := FALSE;
   e_MinorAlarm := FALSE;
   e_BusBar_Monit_Fail_Tie := FALSE;
   var221 := FALSE;
   var222 := FALSE;
   var223 := FALSE;
   var224 := FALSE;
   var225 := FALSE;
   var226 := FALSE;
   var227 := FALSE;
   e_SD_C1 := FALSE;
   e_SD_C2 := FALSE;
   e_SD_C3 := FALSE;
   e_SD_C4 := FALSE;
   e_SD_C5 := FALSE;
   e_SD_C6 := FALSE;
   e_SD_C7 := FALSE;
   e_SD_C8 := FALSE;
   e_wirebrk_C1 := FALSE;
   e_wirebrk_C2 := FALSE;
   e_wirebrk_C3 := FALSE;
   e_wirebrk_C4 := FALSE;
   e_wirebrk_C5 := FALSE;
   e_wirebrk_C6 := FALSE;
   e_wirebrk_C7 := FALSE;
   e_wirebrk_C8 := FALSE;
   e_EMStpMan := FALSE;
   e_Prealarm := FALSE;
   e_Sensor_SD_C2 := FALSE;
   var253 := FALSE;
   e_wirebrk_V1 := FALSE;
   e_wirebrk_V2 := FALSE;
   e_wirebrk_V3 := FALSE;
   e_wirebrk_V4 := FALSE;
   var260 := FALSE;
   var261 := FALSE;
   var262 := FALSE;
   var263 := FALSE;
   e_deviL_FCtrl := FALSE;
   e_UBLmax_tooLow := FALSE;
   var266 := FALSE;
   var267 := FALSE;
   e_linkT1 := FALSE;
   e_linkT2 := FALSE;
   e_linkT3 := FALSE;
   e_linkT4 := FALSE;
   e_linkG1 := FALSE;
   e_linkG2 := FALSE;
   e_linkG3 := FALSE;
   e_linkG4 := FALSE;
   e_linkG5 := FALSE;
   e_linkG6 := FALSE;
   e_linkG7 := FALSE;
   e_linkG8 := FALSE;
   e_linkG9 := FALSE;
   e_linkG10 := FALSE;
   e_linkG11 := FALSE;
   e_linkG12 := FALSE;
   e_linkG13 := FALSE;
   e_linkEG := FALSE;
   e_linkS1 := FALSE;
   e_linkS2 := FALSE;
   e_noStpDiesel := FALSE;
   e_standByStart := FALSE;
   e_takeOverLoad := FALSE;
   e_OLM := FALSE;
   e_MCB24_trip := FALSE;
   e_CB440G_trip := FALSE;
   e_CB440B_trip := FALSE;
   e_TieBrkOpn := FALSE;
   e_InputCard := FALSE;
   e_OutputCard := FALSE;
   e_brkTripExt := FALSE;
   e_noLoadheavyCon := FALSE;
   w_takeOverLoad := FALSE;
   e_Overvolt2 := FALSE;
   e_Al_Low_LubOil_Press := FALSE;
   e_Al_High_LubOil_Temp := FALSE;
   e_Al_High_CoolW_Temp := FALSE;
   e_Al_Low_CoolW_Level := FALSE;
   e_Al_Leak_Fuel_Pipe := FALSE;
   e_WindOvertemp_Warn := FALSE;
   e_Al_SD_Channel_4 := FALSE;
   var321 := FALSE;
   var322 := FALSE;
   var323 := FALSE;
   w_Gen_I_E := FALSE;
   w_Gen_P_E := FALSE;
   w_Bus_f_E := FALSE;
   w_Bus_V_E := FALSE;
   e_TrBrk_tripI_E := FALSE;
   e_TrBrk_tripP_E := FALSE;
   e_TrBrk_tripf_E := FALSE;
   e_TrBrk_triprP_E := FALSE;
   e_CB440T_trip_E := FALSE;
   e_I_SC_TrBrk_E := FALSE;
   e_NoCycleBrkFail_E := FALSE;
   e_TrBrk_trip_E := FALSE;
   e_TrBrk_on_fail_E := FALSE;
   e_TrBrk_off_fail_E := FALSE;
   e_TrBrk_onOff_fail_E := FALSE;
   e_TrBrk_ready_fail_E := FALSE;
   e_TrBrk_tripV_E := FALSE;
   var345 := FALSE;
   var346 := FALSE;
   var347 := FALSE;
   e_alarm_SD5_EG := FALSE;
   e_alarm_SD6_EG := FALSE;
   e_alarm_SD7_EG := FALSE;
   e_alarm_SD8_EG := FALSE;
   var354 := FALSE;
   var355 := FALSE;
   var356 := FALSE;
   var357 := FALSE;
   a_OrdSeq1_8[1] := B#16#0;
   a_OrdSeq1_8[2] := B#16#0;
   a_OrdSeq1_8[3] := B#16#0;
   a_OrdSeq1_8[4] := B#16#0;
   a_OrdSeq1_8[5] := B#16#0;
   a_OrdSeq1_8[6] := B#16#0;
   a_OrdSeq1_8[7] := B#16#0;
   a_OrdSeq1_8[8] := B#16#0;
   a_OrdSeq9_15[1] := B#16#0;
   a_OrdSeq9_15[2] := B#16#0;
   a_OrdSeq9_15[3] := B#16#0;
   a_OrdSeq9_15[4] := B#16#0;
   a_OrdSeq9_15[5] := B#16#0;
   a_OrdSeq9_15[6] := B#16#0;
   a_OrdSeq9_15[7] := B#16#0;
   a_OrdSeq9_15[8] := B#16#0;
   a_pmaMode := B#16#0;
   act_dutyPos := B#16#0;
   var540 := B#16#0;
   var550 := B#16#0;
   var560 := 0;
   var580 := 0;
   a_GenSet_stat_ind := 0;
   a_GenSet_stat_var := 0;
   a_UTC := DT#90-1-1-0:0:0.000;
   var720 := 0;
   var740 := B#16#0;
   var760 := 0;
   var780 := 0;
   var800 := 0;
   var820 := 0;
   a_GclseCriteria := B#16#0;
   var850 := B#16#0;
   var860 := 0;
   var880 := 0;
   var900 := B#16#0;
   var910 := B#16#0;
   var920 := B#16#0;
   var930 := B#16#0;
   var940 := 0;
   var960 := 0;
   var980 := 0;
   var1000 := 0;
   var1020 := B#16#0;
   var1030 := B#16#0;
   var1040 := 0;
   var1060 := 0;
   var1080 := 0;
   var1100 := 0;
   var1120 := 0;
   var1140 := 0;
   a_UBLmax := 0;
   a_UBLmin := 0;
   var1200 := 0;
   var1220 := 0;
   var1240 := 0;
   var1260 := 0;
   var1280 := 0;
   var1300 := 0;
   var1320 := 0;
   var1340 := 0;
   var1360 := 0;
   var1380 := 0;
   var1400 := 0;
   var1420 := 0;
   var1440 := 0;
   var1460 := 0;
   var1480 := 0;
   var1500 := 0;
   var1520 := 0;
   var1540 := 0;
   var1560 := 0;
   var1580 := 0;
   var1600 := 0;
   var1620 := 0;
   var1640 := 0;
   var1660 := 0;
   var1680 := 0;
   var1700 := 0;
   var1720 := 0;
   var1740 := 0;
   var1760 := 0;
   var1780 := 0;
   var1800 := 0;
   var1820 := 0;
   var1840 := 0;
   var1860 := 0;
   var1880 := 0;
   var1900 := 0;
   var1920 := 0;
   c_rst_alm := FALSE;
   var1941 := FALSE;
   var1942 := FALSE;
   var1943 := FALSE;
   c_Dstrt := FALSE;
   c_Dstp := FALSE;
   var1946 := FALSE;
   var1947 := FALSE;
   c_genBrk_clse := FALSE;
   var1951 := FALSE;
   c_genBrk_opn := FALSE;
   var1953 := FALSE;
   var1954 := FALSE;
   c_Ustrt := FALSE;
   c_Ustp := FALSE;
   c_block_GenSetOn := FALSE;
   c_block_GenSetOff := FALSE;
   c_increase := FALSE;
   c_decrease := FALSE;
   c_rstEGmode := FALSE;
   c_isochron := FALSE;
   c_droop := FALSE;
   var1966 := FALSE;
   var1967 := FALSE;
   c_UBLon := FALSE;
   c_UBLoff := FALSE;
   var1972 := FALSE;
   var1973 := FALSE;
   c_noStpULoad := FALSE;
   c_rstnoStpULoad := FALSE;
   var1976 := FALSE;
   e_linkfail := FALSE;
   var1980 := FALSE;
   var1981 := FALSE;
   var1982 := FALSE;
   var1983 := FALSE;
   var1984 := FALSE;
   var1985 := FALSE;
   var1986 := FALSE;
   var1987 := FALSE;
   c_strtStandby := FALSE;
   var1991 := FALSE;
   var1992 := FALSE;
   var1993 := FALSE;
   var1994 := FALSE;
   var1995 := FALSE;
   var1996 := FALSE;
   var1997 := FALSE;
   var2000 := FALSE;
   var2001 := FALSE;
   var2002 := FALSE;
   var2003 := FALSE;
   c_TrBrk_clse := FALSE;
   c_TrBrk_opn := FALSE;
   var2006 := FALSE;
   var2007 := FALSE;
   var2010 := FALSE;
   var2011 := FALSE;
   var2012 := FALSE;
   var2013 := FALSE;
   var2014 := FALSE;
   var2015 := FALSE;
   var2016 := FALSE;
   var2017 := FALSE;
   var2020 := B#16#0;
   var2030 := B#16#0;
   s_OrdSeq1_8[1] := B#16#0;
   s_OrdSeq1_8[2] := B#16#0;
   s_OrdSeq1_8[3] := B#16#0;
   s_OrdSeq1_8[4] := B#16#0;
   s_OrdSeq1_8[5] := B#16#0;
   s_OrdSeq1_8[6] := B#16#0;
   s_OrdSeq1_8[7] := B#16#0;
   s_OrdSeq1_8[8] := B#16#0;
   s_OrdSeq9_15[1] := B#16#0;
   s_OrdSeq9_15[2] := B#16#0;
   s_OrdSeq9_15[3] := B#16#0;
   s_OrdSeq9_15[4] := B#16#0;
   s_OrdSeq9_15[5] := B#16#0;
   s_OrdSeq9_15[6] := B#16#0;
   s_OrdSeq9_15[7] := B#16#0;
   s_OrdSeq9_15[8] := B#16#0;
   s_PreMode := B#16#0;
   var2210 := B#16#0;
   s_UBLmax := 0;
   s_UBLmin := 0;
   var2260 := 0;
   s_UTC := DT#90-1-1-0:0:0.000;
   var2360 := 0;
   var2380 := 0;
   var2400 := 0;
   var2420 := 0;
   var2440 := 0;
   var2460 := 0;
END_DATA_BLOCK

DATA_BLOCK "I_OP_SR"
TITLE =Interface Visualization. The 1. part contains the send area,
//the 2.part the receive area.                                                     !
//
//
//
//I_MMI_SR
// Sende-/Empfangsfach MMI
//  Im 1.Teil des DB's liegt das Sendefach, während das Empfangsfach sich im zweiten Teil
//  befindet.
//
//  Der DB ist die zentrale Schnittstelle zwischen Bediener und PMA-Steuerung. Die Daten des
//  Sendefaches werden in Abhängigkeit des Bedienortes (OP, BuB) in die entsprechenden
//  Ausgangsfächer transferiert, während umgekehrt die Daten in das Empfangsfach kopiert werden.
//
//  Die Parameter werden nicht über diese Schnittstelle (I_MMI_SR) geführt, sondern direkt in den
//  Parameter-DB der PMA (prm_pma) transferiert, bzw. von dort abgeholt.
//
//  Daten, die das Generatorschutzgerät (Genop71) betreffen werden ebenfalls direkt in dessen
//  Sendefach (I_prtcSR)geschrieben bzw. werden direkt aus dessen Empfangsfach(I_prtcSR) ausgelesen.
//
//  Siemens AG ATD IS3T, Kahle +494028892022, jens.kahle@hbg.siemens.de
//  PMA71
//  =Internal Modul Memory
//  Datum aktuelle Version: 20.02.99
//  Version,Änd-Datum, Bearbeiter, geänderte Variablen
//  1.01   ,31.01.99 , Kahle     , 1.Version
//  1.02   ,20.02.99 , Kahle     , Anwahl Konfigurationen
//
//KNOW_HOW_PROTECT
// (If specified, no more changes can be made once the block is generated)
//UNLINKED
// (If specified, the generated block is only available in the PLC load
//  memory)
//READ_ONLY
// (If specified, the generated block cannot be changed in the programmable
//  controller)
AUTHOR : Kahle
FAMILY : PMA71
NAME : I_OP_SR
VERSION : 2.0


  STRUCT
   c_rst_alm : BOOL ; //Alarm reset
   var1941 : BOOL ;
   var1942 : BOOL ;
   var1943 : BOOL ;
   c_Dstrt : BOOL ; //Diesel start by the operator
   c_Dstp : BOOL ;  //Diesel stop by the operator
   var1946 : BOOL ;
   var1947 : BOOL ;
   c_genBrk_clse : BOOL ;   //Generator breaker close by the operator
   var1951 : BOOL ;
   c_genBrk_opn : BOOL ;    //Generator breaker open by the operator
   var1953 : BOOL ;
   var1954 : BOOL ;
   c_Ustrt : BOOL ; //Generator set start by the operator
   c_Ustp : BOOL ;  //Generator set stop by the operator
   c_block_GenSetOn : BOOL ;    //Block generator set on by operator
   c_block_GenSetOff : BOOL ;   //Block generator set off by operator
   c_increase : BOOL ;  //Increase load
   c_decrease : BOOL ;  //Decrease load
   c_rstEGmode : BOOL ; //Command: Reset EG mode
   c_isochron : BOOL ;  //Command: isochron mode
   c_droop : BOOL ; //Command: droop mode
   var1966 : BOOL ;
   var1967 : BOOL ;
   c_UBLon : BOOL ; //Command: Activate the UBL mode
   c_UBLoff : BOOL ;  //Command: Deactivate the UBL mode
   var1972 : BOOL ;
   var1973 : BOOL ;
   c_noStpULoad : BOOL ;    //Command: no stop in case of underload
   c_rstnoStpULoad : BOOL ; //Command: reset no stop in case of underload
   var1976 : BOOL ;
   e_linkfail : BOOL ;  //link to the monitoring system faulty
   var1980 : BOOL ;
   var1981 : BOOL ;
   var1982 : BOOL ;
   var1983 : BOOL ;
   var1984 : BOOL ;
   var1985 : BOOL ;
   var1986 : BOOL ;
   var1987 : BOOL ;
   c_strtStandby : BOOL ;   //Start of the generator set which are standing in standby
   var1991 : BOOL ;
   var1992 : BOOL ;
   var1993 : BOOL ;
   var1994 : BOOL ;
   var1995 : BOOL ;
   var1996 : BOOL ;
   var1997 : BOOL ;
   var2000 : BOOL ;
   var2001 : BOOL ;
   var2002 : BOOL ;
   var2003 : BOOL ;
   c_TrBrk_clse : BOOL ;    //Command: Transfer breaker close   [EG only]
   c_TrBrk_opn : BOOL ; //Command: Transfer breaker open [EG only]
   var2006 : BOOL ;
   var2007 : BOOL ;
   var2010 : BOOL ;
   var2011 : BOOL ;
   var2012 : BOOL ;
   var2013 : BOOL ;
   var2014 : BOOL ;
   var2015 : BOOL ;
   var2016 : BOOL ;
   var2017 : BOOL ;
   var2020 : BYTE ;
   var2030 : BYTE ;
   s_OrdSeq1_8 : ARRAY  [1 .. 8 ] OF //New selected start-/stop sequence -part 1-
   BYTE ;
   s_OrdSeq9_15 : ARRAY  [1 .. 8 ] OF //New selected start-/stop sequence -part 2-
   BYTE ;
   s_PreMode : BYTE ;   //Preselected operating mode
   var2210 : BYTE ;
   s_UBLmax : INT ; //setpoint UBLmax value [in KW]
   s_UBLmin : INT ; //setpoint UBLmin value [in kW]
   var2260 : INT ;
   s_UTC : DATE_AND_TIME ;  //setpoint UTC
   var2360 : ARRAY  [0 .. 5 ] OF BYTE ;
   var29 : INT ;    //+++ OP7 RECEIVE buffer: internal data +++
   OP7_Ctrl_Tn : S5TIME ;   //OP7 Parameter: Tn -Load controller-
   OP7_SCtrl_time : S5TIME ;    //OP7 Parameter: time -Step Controller-
   OP7_SCtrl_minP : S5TIME ;    //OP7 Parameter: minP -Step Controller-
   OP7_SCtrl_minB : S5TIME ;    //OP7 Parameter: minB -Step Controller-
   OP7_noStpULoad : INT ;  //OP7 Command: =1: no stop in case of underload
   OP7_FCtrl_TN : S5TIME ;  //OP7 Parameter: Tn -Frequency controller-
   OP7Cmd_block : INT ; //OP7 Command: blocked by OP
   OP7Cmd_UBL : INT ;   //OP7 Command: UBL-Mode active
   s_OrdSeq1_8SET : ARRAY  [1 .. 8 ] OF //OP7 Preselect new start stop sequence
   BYTE ;
   s_OrdSeq9_15SET : ARRAY  [1 .. 8 ] OF //OP7 Preselect new start stop sequence
   BYTE ;
   take_over : INT ;    //=1: accept new select
   a_OrdSeq1_8STOP : ARRAY  [1 .. 8 ] OF //OP7 actual stop sequence
   BYTE ;
   s_OrdSeq9_15STOP : ARRAY  [1 .. 8 ] OF //OP7 actual stop sequence
   BYTE ;
  END_STRUCT ;
BEGIN
   c_rst_alm := FALSE;
   var1941 := FALSE;
   var1942 := FALSE;
   var1943 := FALSE;
   c_Dstrt := FALSE;
   c_Dstp := FALSE;
   var1946 := FALSE;
   var1947 := FALSE;
   c_genBrk_clse := FALSE;
   var1951 := FALSE;
   c_genBrk_opn := FALSE;
   var1953 := FALSE;
   var1954 := FALSE;
   c_Ustrt := FALSE;
   c_Ustp := FALSE;
   c_block_GenSetOn := FALSE;
   c_block_GenSetOff := FALSE;
   c_increase := FALSE;
   c_decrease := FALSE;
   c_rstEGmode := FALSE;
   c_isochron := FALSE;
   c_droop := FALSE;
   var1966 := FALSE;
   var1967 := FALSE;
   c_UBLon := FALSE;
   c_UBLoff := FALSE;
   var1972 := FALSE;
   var1973 := FALSE;
   c_noStpULoad := FALSE;
   c_rstnoStpULoad := FALSE;
   var1976 := FALSE;
   e_linkfail := FALSE;
   var1980 := FALSE;
   var1981 := FALSE;
   var1982 := FALSE;
   var1983 := FALSE;
   var1984 := FALSE;
   var1985 := FALSE;
   var1986 := FALSE;
   var1987 := FALSE;
   c_strtStandby := FALSE;
   var1991 := FALSE;
   var1992 := FALSE;
   var1993 := FALSE;
   var1994 := FALSE;
   var1995 := FALSE;
   var1996 := FALSE;
   var1997 := FALSE;
   var2000 := FALSE;
   var2001 := FALSE;
   var2002 := FALSE;
   var2003 := FALSE;
   c_TrBrk_clse := FALSE;
   c_TrBrk_opn := FALSE;
   var2006 := FALSE;
   var2007 := FALSE;
   var2010 := FALSE;
   var2011 := FALSE;
   var2012 := FALSE;
   var2013 := FALSE;
   var2014 := FALSE;
   var2015 := FALSE;
   var2016 := FALSE;
   var2017 := FALSE;
   var2020 := B#16#0;
   var2030 := B#16#0;
   s_OrdSeq1_8[1] := B#16#0;
   s_OrdSeq1_8[2] := B#16#0;
   s_OrdSeq1_8[3] := B#16#0;
   s_OrdSeq1_8[4] := B#16#0;
   s_OrdSeq1_8[5] := B#16#0;
   s_OrdSeq1_8[6] := B#16#0;
   s_OrdSeq1_8[7] := B#16#0;
   s_OrdSeq1_8[8] := B#16#0;
   s_OrdSeq9_15[1] := B#16#0;
   s_OrdSeq9_15[2] := B#16#0;
   s_OrdSeq9_15[3] := B#16#0;
   s_OrdSeq9_15[4] := B#16#0;
   s_OrdSeq9_15[5] := B#16#0;
   s_OrdSeq9_15[6] := B#16#0;
   s_OrdSeq9_15[7] := B#16#0;
   s_OrdSeq9_15[8] := B#16#0;
   s_PreMode := B#16#0;
   var2210 := B#16#0;
   s_UBLmax := 0;
   s_UBLmin := 0;
   var2260 := 0;
   s_UTC := DT#90-1-1-0:0:0.000;
   var2360[0] := B#16#0;
   var2360[1] := B#16#0;
   var2360[2] := B#16#0;
   var2360[3] := B#16#0;
   var2360[4] := B#16#0;
   var2360[5] := B#16#0;
   var29 := 0;
   OP7_Ctrl_Tn := S5T#0MS;
   OP7_SCtrl_time := S5T#0MS;
   OP7_SCtrl_minP := S5T#0MS;
   OP7_SCtrl_minB := S5T#0MS;
   OP7_noStpULoad := 0;
   OP7_FCtrl_TN := S5T#0MS;
   OP7Cmd_block := 0;
   OP7Cmd_UBL := 0;
   s_OrdSeq1_8SET[1] := B#16#0;
   s_OrdSeq1_8SET[2] := B#16#0;
   s_OrdSeq1_8SET[3] := B#16#0;
   s_OrdSeq1_8SET[4] := B#16#0;
   s_OrdSeq1_8SET[5] := B#16#0;
   s_OrdSeq1_8SET[6] := B#16#0;
   s_OrdSeq1_8SET[7] := B#16#0;
   s_OrdSeq1_8SET[8] := B#16#0;
   s_OrdSeq9_15SET[1] := B#16#0;
   s_OrdSeq9_15SET[2] := B#16#0;
   s_OrdSeq9_15SET[3] := B#16#0;
   s_OrdSeq9_15SET[4] := B#16#0;
   s_OrdSeq9_15SET[5] := B#16#0;
   s_OrdSeq9_15SET[6] := B#16#0;
   s_OrdSeq9_15SET[7] := B#16#0;
   s_OrdSeq9_15SET[8] := B#16#0;
   take_over := 0;
   a_OrdSeq1_8STOP[1] := B#16#0;
   a_OrdSeq1_8STOP[2] := B#16#0;
   a_OrdSeq1_8STOP[3] := B#16#0;
   a_OrdSeq1_8STOP[4] := B#16#0;
   a_OrdSeq1_8STOP[5] := B#16#0;
   a_OrdSeq1_8STOP[6] := B#16#0;
   a_OrdSeq1_8STOP[7] := B#16#0;
   a_OrdSeq1_8STOP[8] := B#16#0;
   s_OrdSeq9_15STOP[1] := B#16#0;
   s_OrdSeq9_15STOP[2] := B#16#0;
   s_OrdSeq9_15STOP[3] := B#16#0;
   s_OrdSeq9_15STOP[4] := B#16#0;
   s_OrdSeq9_15STOP[5] := B#16#0;
   s_OrdSeq9_15STOP[6] := B#16#0;
   s_OrdSeq9_15STOP[7] := B#16#0;
   s_OrdSeq9_15STOP[8] := B#16#0;
END_DATA_BLOCK



DATA_BLOCK "I_visuSR"
TITLE =Interface OP7. The 1. part contains the send area,
//the 2.part the receive area.                                                     !
//
//
//
// I_MMI_SR
// Sende-/Empfangsfach MMI
//  Im 1.Teil des DB's liegt das Sendefach, während das Empfangsfach sich im zweiten Teil
//  befindet.
//
//  Der DB ist die zentrale Schnittstelle zwischen Bediener und PMA-Steuerung. Die Daten des
//  Sendefaches werden in Abhängigkeit des Bedienortes (OP, BuB) in die entsprechenden
//  Ausgangsfächer transferiert, während umgekehrt die Daten in das Empfangsfach kopiert werden.
//
//  Die Parameter werden nicht über diese Schnittstelle (I_MMI_SR) geführt, sondern direkt in den
//  Parameter-DB der PMA (prm_pma) transferiert, bzw. von dort abgeholt.
//
//  Daten, die das Generatorschutzgerät (Genop71) betreffen werden ebenfalls direkt in dessen
//  Sendefach (I_prtcSR)geschrieben bzw. werden direkt aus dessen Empfangsfach(I_prtcSR) ausgelesen.
//
//  Siemens AG ATD IS3T, Kahle +494028892022, jens.kahle@hbg.siemens.de
//  PMA71
//  =Internal Modul Memory
//  Datum aktuelle Version: 20.02.99
//  Version,Änd-Datum, Bearbeiter, geänderte Variablen
//  1.01   ,31.01.99 , Kahle     , 1.Version
//  1.02   ,20.02.99 , Kahle     , Anwahl Konfigurationen
//
//KNOW_HOW_PROTECT
// (If specified, no more changes can be made once the block is generated)
//UNLINKED
// (If specified, the generated block is only available in the PLC load
//  memory)
//READ_ONLY
// (If specified, the generated block cannot be changed in the programmable
//  controller)
AUTHOR : Kahle
FAMILY : PMA71
NAME : I_OP_SR
VERSION : 1.4


  STRUCT
   c_rst_alm : BOOL ;   //Alarm reset
   var1941 : BOOL ;
   var1942 : BOOL ;
   var1943 : BOOL ;
   c_Dstrt : BOOL ; //Diesel start by the operator
   c_Dstp : BOOL ;  //Diesel stop by the operator
   var1946 : BOOL ;
   var1947 : BOOL ;
   c_genBrk_clse : BOOL ;   //Generator breaker close by the operator
   var1951 : BOOL ;
   c_genBrk_opn : BOOL ;    //Generator breaker open by the operator
   var1953 : BOOL ;
   var1954 : BOOL ;
   c_Ustrt : BOOL ; //Generator set start by the operator
   c_Ustp : BOOL ;  //Generator set stop by the operator
   c_block_GenSetOn : BOOL ;    //Block generator set on by operator
   c_block_GenSetOff : BOOL ;   //Block generator set off by operator
   c_increase : BOOL ;  //Increase load
   c_decrease : BOOL ;  //Decrease load
   c_rstEGmode : BOOL ; //Command: Reset EG mode
   c_isochron : BOOL ;  //Command: isochron mode
   c_droop : BOOL ; //Command: droop mode
   var1966 : BOOL ;
   var1967 : BOOL ;
   c_UBLon : BOOL ;   //Command: Activate the UBL mode
   c_UBLoff : BOOL ;    //Command: Deactivate the UBL mode
   var1972 : BOOL ;
   var1973 : BOOL ;
   c_noStpULoad : BOOL ;    //Command: no stop in case of underload
   c_rstnoStpULoad : BOOL ; //Command: reset no stop in case of underload
   var1976 : BOOL ;
   e_linkfail : BOOL ;  //link to the monitoring system faulty
   var1980 : BOOL ;
   var1981 : BOOL ;
   var1982 : BOOL ;
   var1983 : BOOL ;
   var1984 : BOOL ;
   var1985 : BOOL ;
   var1986 : BOOL ;
   var1987 : BOOL ;
   c_strtStandby : BOOL ;   //Start of the generator set which are standing in standby
   var1991 : BOOL ;
   var1992 : BOOL ;
   var1993 : BOOL ;
   var1994 : BOOL ;
   var1995 : BOOL ;
   var1996 : BOOL ;
   var1997 : BOOL ;
   var2000 : BOOL ;
   var2001 : BOOL ;
   var2002 : BOOL ;
   var2003 : BOOL ;
   c_TrBrk_clse : BOOL ;    //Command: Transfer breaker close   [EG only]
   c_TrBrk_opn : BOOL ; //Command: Transfer breaker open [EG only]
   var2006 : BOOL ;
   var2007 : BOOL ;
   var2010 : BOOL ;
   var2011 : BOOL ;
   var2012 : BOOL ;
   var2013 : BOOL ;
   var2014 : BOOL ;
   var2015 : BOOL ;
   var2016 : BOOL ;
   var2017 : BOOL ;
   var2020 : BYTE ;
   var2030 : BYTE ;
   s_OrdSeq1_8 : ARRAY  [1 .. 8 ] OF //New selected start-/stop sequence -part 1-
   BYTE ;
   s_OrdSeq9_15 : ARRAY  [1 .. 8 ] OF //New selected start-/stop sequence -part 2-
   BYTE ;
   s_PreMode : BYTE ;   //Preselected operating mode
   var2210 : BYTE ;
   s_UBLmax : INT ; //setpoint UBLmax value [in KW]
   s_UBLmin : INT ; //setpoint UBLmin value [in kW]
   var2260 : INT ;
   s_UTC : DATE_AND_TIME ;  //setpoint UTC
   var2360 : INT ;
   var2380 : INT ;
   var2400 : INT ;
   var2420 : INT ;
   var2440 : INT ;
   var2460 : INT ;
   var_xxx : ARRAY  [0 .. 14 ] OF BYTE ;
  END_STRUCT ;
BEGIN
   c_rst_alm := FALSE;
   var1941 := FALSE;
   var1942 := FALSE;
   var1943 := FALSE;
   c_Dstrt := FALSE;
   c_Dstp := FALSE;
   var1946 := FALSE;
   var1947 := FALSE;
   c_genBrk_clse := FALSE;
   var1951 := FALSE;
   c_genBrk_opn := FALSE;
   var1953 := FALSE;
   var1954 := FALSE;
   c_Ustrt := FALSE;
   c_Ustp := FALSE;
   c_block_GenSetOn := FALSE;
   c_block_GenSetOff := FALSE;
   c_increase := FALSE;
   c_decrease := FALSE;
   c_rstEGmode := FALSE;
   c_isochron := FALSE;
   c_droop := FALSE;
   var1966 := FALSE;
   var1967 := FALSE;
   c_UBLon := FALSE;
   c_UBLoff := FALSE;
   var1972 := FALSE;
   var1973 := FALSE;
   c_noStpULoad := FALSE;
   c_rstnoStpULoad := FALSE;
   var1976 := FALSE;
   e_linkfail := FALSE;
   var1980 := FALSE;
   var1981 := FALSE;
   var1982 := FALSE;
   var1983 := FALSE;
   var1984 := FALSE;
   var1985 := FALSE;
   var1986 := FALSE;
   var1987 := FALSE;
   c_strtStandby := FALSE;
   var1991 := FALSE;
   var1992 := FALSE;
   var1993 := FALSE;
   var1994 := FALSE;
   var1995 := FALSE;
   var1996 := FALSE;
   var1997 := FALSE;
   var2000 := FALSE;
   var2001 := FALSE;
   var2002 := FALSE;
   var2003 := FALSE;
   c_TrBrk_clse := FALSE;
   c_TrBrk_opn := FALSE;
   var2006 := FALSE;
   var2007 := FALSE;
   var2010 := FALSE;
   var2011 := FALSE;
   var2012 := FALSE;
   var2013 := FALSE;
   var2014 := FALSE;
   var2015 := FALSE;
   var2016 := FALSE;
   var2017 := FALSE;
   var2020 := B#16#0;
   var2030 := B#16#0;
   s_OrdSeq1_8[1] := B#16#0;
   s_OrdSeq1_8[2] := B#16#0;
   s_OrdSeq1_8[3] := B#16#0;
   s_OrdSeq1_8[4] := B#16#0;
   s_OrdSeq1_8[5] := B#16#0;
   s_OrdSeq1_8[6] := B#16#0;
   s_OrdSeq1_8[7] := B#16#0;
   s_OrdSeq1_8[8] := B#16#0;
   s_OrdSeq9_15[1] := B#16#0;
   s_OrdSeq9_15[2] := B#16#0;
   s_OrdSeq9_15[3] := B#16#0;
   s_OrdSeq9_15[4] := B#16#0;
   s_OrdSeq9_15[5] := B#16#0;
   s_OrdSeq9_15[6] := B#16#0;
   s_OrdSeq9_15[7] := B#16#0;
   s_OrdSeq9_15[8] := B#16#0;
   s_PreMode := B#16#0;
   var2210 := B#16#0;
   s_UBLmax := 0;
   s_UBLmin := 0;
   var2260 := 0;
   s_UTC := DT#90-1-1-0:0:0.000;
   var2360 := 0;
   var2380 := 0;
   var2400 := 0;
   var2420 := 0;
   var2440 := 0;
   var2460 := 0;
   var_xxx[0] := B#16#0;
   var_xxx[1] := B#16#0;
   var_xxx[2] := B#16#0;
   var_xxx[3] := B#16#0;
   var_xxx[4] := B#16#0;
   var_xxx[5] := B#16#0;
   var_xxx[6] := B#16#0;
   var_xxx[7] := B#16#0;
   var_xxx[8] := B#16#0;
   var_xxx[9] := B#16#0;
   var_xxx[10] := B#16#0;
   var_xxx[11] := B#16#0;
   var_xxx[12] := B#16#0;
   var_xxx[13] := B#16#0;
   var_xxx[14] := B#16#0;
END_DATA_BLOCK



DATA_BLOCK "I_prtcSR"
TITLE =Interface GENOP71. The 1. part contains the send area,
//the 2.part the receive area.                                                     !
//
//
//
// I_prtcSR
//  Sende-/Empfangsfach Generatorschutz
//  Im ersten Teil befindet sich das Sendefach, im zweiten Teil das Empfangsfach.
//
//  Die MMI_Schnittstelle greift direkt auf diesen DB zu, ebenso erfolgen die
//  Parameteränderungen direkt in diesem DB.
//
//
//  Siemens AG ATD IS3T, Kahle +494028892022, jens.kahle@hbg.siemens.de
//  PMA71
//  = Sende-/Empfangsfach Generatorschutz
//  Datum aktuelle Version: 10.03.99
//  Version, Datum,   Bearbeiter, geänderte Variablen
//   01.01,  31.01.99,  Kahle   , Ersterstellung
//   01.02,  04.02.99,  Kahle     , Min-Max Grenzwerte
//   01.03,  10.03.99,  Kahle     ,Min-Max Grenzwerte entfallen
//KNOW_HOW_PROTECT
// (If specified, no more changes can be made once the block is generated)
//UNLINKED
// (If specified, the generated block is only available in the PLC load
//  memory)
//READ_ONLY
// (If specified, the generated block cannot be changed in the programmable
//  controller)
AUTHOR : Kahle
FAMILY : PMA71
NAME : I_prtcSR
VERSION : 1.5


  STRUCT    // SENDEFACH
   c_A_RES : BOOL ; //-->GENOP71: Alarm reset
   c_F_LOWER : BOOL ;   //-->GENOP71: Speed setting pulse lower
   c_F_HIGHER : BOOL ;  //-->GENOP71: Speed setting pulse higher
   c_SYN_EN : BOOL ;    //-->GENOP71: Release of synchronizing
   c_BR_ON : BOOL ; //-->GENOP71: Generator breaker ON command
   c_BR_OFF : BOOL ;    //-->GENOP71: Generator breaker OFF command
   I_SC_RES : BOOL ;    //-->GENOP71: Generator short circuit reset
   c_AUT_EN : BOOL ;    //-->GENOP71: Automatic operation (Release of control signals from DP)
   var01 : BOOL ;
   var02 : BOOL ;
   var03 : BOOL ;
   var04 : BOOL ;
   var05 : BOOL ;
   var06 : BOOL ;
   i_L_FLAG_S : BOOL ;  //-->GENOP71: Life flag
   var08 : BOOL ;
   c_GW1_BLO : BOOL ;   //-->GENOP71: Blocking of I_GW1
   c_GW2_BLO : BOOL ;   //-->GENOP71: Blocking of I_GW2 -- not used --
   c_GW3_BLO : BOOL ;   //-->GENOP71: Blocking of I_GW3
   c_GW4_BLO : BOOL ;   //-->GENOP71: Blocking of I_GW4
   c_GW5_BLO : BOOL ;   //-->GENOP71: Blocking of P_GW1
   c_GW6_BLO : BOOL ;   //-->GENOP71: Blocking of I>>_GW1
   var09 : BOOL ;
   var10 : BOOL ;
   c_GW1_OUT_ON : BOOL ;    //-->GENOP71: Unessential consumers 1 OFF command
   c_GW2_OUT_ON : BOOL ;    //-->GENOP71: Unessential consumers 2 OFF command
   c_GW3_OUT_ON : BOOL ;    //-->GENOP71: Unessential consumers 3 OFF command
   var11 : BOOL ;
   var12 : BOOL ;
   var13 : BOOL ;
   var14 : BOOL ;
   var15 : BOOL ;
   var16 : DINT ;   //-- not used --
   var17 : DINT ;   //-- not used --
   var18 : DINT ;   //-- not used --
   var19 : DINT ;   //-- not used --
   var20 : DINT ;   //-- not used --
   var21 : DINT ;   //-- not used --
   var22 : DINT ;   //-- not used --
   var23 : DINT ;   //-- not used --
   var24 : DINT ;   //-- not used --
   var25 : DINT ;   //-- not used --
   var26 : DINT ;   //-- not used --
   var27 : INT ;    //-- not used --
   s_GW1_SET : INT  := 1692;    //-->GENOP71: Current limit GW1 [A]: Uness. cons. 1-3, time-graded
   s_GW2_SET : INT  := 1000;    //-->GENOP71: Current limit GW2 [A]: -- not used --
   s_GW3_SET : INT  := 2030;    //-->GENOP71: Current limit GW3 [A]: Uness. cons. 1-3
   s_GW4_SET : INT  := 2792;    //-->GENOP71: Current limit GW4 [A:] Generator breaker Off
   s_GW5_SET : INT  := -94; //-->GENOP71: Reverse power limit GW5 [kW]: Generator breaker Off
   s_GW6_SET : INT  := 5076;    //-->GENOP71: Short-circuit current limit GW6 [A]: Generator breaker Off
   s_T_GW1_SET : INT  := 50;    //-->GENOP71: Delay time GW1 [0.1s]: Uness. consumers 1
   s_T_GW2_SET : INT  := 100;   //-->GENOP71: Delay time GW1 [0.1s]: Uness. consumers 2
   s_T_GW3_SET : INT  := 150;   //-->GENOP71: Delay time GW1 [0.1s]: Uness. consumers 3
   s_T_GW31_SET : INT  := 10;   //-->GENOP71: Delay time GW3 [0.1s]: Uness. consumers 1-3
   s_T_GW4_SET : INT  := 150;   //-->GENOP71: Delay time GW4 [0.1s]: Overcurrent, generator breaker Off
   s_T_GW5_SET : INT  := 60;    //-->GENOP71: Delay time GW5 [0.1s]: Reverse power, generator breaker Off
   s_T_GW6_SET : INT  := 6; //-->GENOP71: Delay time GW6 [0.1s]: Short circuit, generator breaker Off
   s_T_SYNK_SET : INT  := 15;   //-->GENOP71: Synchronizing: Short pulse duration [0.1s]
   s_T_SYNL_SET : INT  := 30;   //-->GENOP71: Synchronizing: Long pulse duration [0.1s]
   s_GW_DL_SET : INT  := 20;   //-->GENOP71: Synchronizing: Limit continuous signal <--> long pulse [0.1Hz]
   s_GW_LK_SET : INT  := 10;    //-->GENOP71: Synchronizing: Limit long pulse <--> short pulse [0.1Hz]
   s_T_SYNDL_SET : INT  := 10;  //-->GENOP71: Synchronizing: Waiting time before frequency detuning [s]
   s_T_SYNV_SET : INT  := 10;   //-->GENOP71: Synchronizing: Pulse duration for frequency detuning [0.1s]
   s_SYN_BLO_SET : INT  := 100; //-->GENOP71: Synchronizing: Frequency limit for enabling [0.1Hz]
   s_U_DIFF_SET : INT  := 20;   //-->GENOP71: Synchronizing: Voltage limit for enabling [V]
   s_SYN_SET : INT  := 5;   //-->GENOP71: Synchronizing: Frequency limit for breaker closing (0.1Hz)
   s_T_VORH_SET : INT  := 80;   //-->GENOP71: Synchronizing: Lead time for generator breaker closing [msec]
   s_T_EIN_SET : INT  := 2; //-->GENOP71: Pulse duration for generator breaker closing command [s]
   s_UPRIM_SET : INT  := 400;   //-->GENOP71: Voltage transformer primary [V]
   s_IPRIM_SET : INT  := 2000;  //-->GENOP71: Current transformer primary [A]
   s_PULS_RELA_S : INT  := 267; //-->GENOP71: Synchronizing: Mark-to-space ratio of short pulse [1-1000%]
   s_PULS_RELA_L : INT  := 33;  //-->GENOP71: Synchronizing: Mark-to-space ratio of long pulse [1-1000%]
   var28 : INT ;
   var29 : INT ;    //    *** RECEIVE MAILBOX (GENOP71-->PLC S7-300) ***
   e_I_GW1UNV : BOOL ;  //GENOP71-->: Current limit GW1 exceeded
   e_I_GW2UNV : BOOL ;  //GENOP71-->: Current limit GW2 exceeded -- not used --
   e_I_GW3UNV : BOOL ;  //GENOP71-->: Current limit GW3 exceeded
   e_I_GW4UNV : BOOL ;  //GENOP71-->: Current limit GW4 exceeded
   e_P_GW1UNV : BOOL ;  //GENOP71-->: Limit for reverse power GW5 exceeded
   e_I_SC_GW1 : BOOL ;  //GENOP71-->: Limit for short-circuit GW6 exceeded
   i_L_FLAG_R : BOOL ;  //GENOP71-->: Life flag
   i_W_DOG : BOOL ; //GENOP71-->: Watchdog flag
   e_I_GW1VER : BOOL ;  //GENOP71-->: Current limit GW1 exceeded +delay time expired (Uness. consumers 1)
   e_I_GW2VER : BOOL ;  //GENOP71-->: Current limit GW1 exceeded +delay time expired (Uness. consumers 2)
   e_I_GW3VER : BOOL ;  //GENOP71-->: Current limit GW1 exceeded +delay time expired (Uness. consumers 3)
   e_I_GW4VER : BOOL ;  //GENOP71-->: Current limit GW4 exceeded +delay time expired (Gen. breaker Off)
   e_P_GW1VER : BOOL ;  //GENOP71-->: Reverse power limit GW5 exceeded +delay time expired(Gen.break.Off)
   e_I_SC_VER : BOOL ;  //GENOP71-->: Short circuit limit GW66 exceeded +delay time expired(GenBrk off)
   e_I_GW31VER : BOOL ; //GENOP71-->: Current limit GW3 exc. + delay time exp. (Uness. cons. 1-3)[>=V1.7]
   i_Gen_syn_en : BOOL ;    //GENOP71-->: Syn. enable from Genop
   i_GW1_BLO : BOOL ;   //GENOP71-->: Feedback signal I_GW1 blocked (GW1)
   i_GW2_BLO : BOOL ;   //GENOP71-->: Feedback signal I_GW2 blocked (GW2) -- not used --
   i_GW3_BLO : BOOL ;   //GENOP71-->: Feedback signal I_GW3 blocked (GW3)
   i_GW4_BLO : BOOL ;   //GENOP71-->: Feedback signal I_GW4 blocked (GW4)
   i_GW5_BLO : BOOL ;   //GENOP71-->: Feedback signal P_GW1 blocked (GW5)
   i_GW6_BLO : BOOL ;    //GENOP71-->: Feedback signal I>>_GW1 blocked (GW6)
   i_BR_ON : BOOL ; //GENOP71-->: Feedback signal generator breaker closing command
   varx05 : BOOL ;
   e_GW1_OUT_ON : BOOL ;    //GENOP71-->: Feedback signal unessential consumers 1 tripped
   e_GW2_OUT_ON : BOOL ;    //GENOP71-->: Feedback signal unessential consumers 2 tripped
   e_GW3_OUT_ON : BOOL ;    //GENOP71-->: Feedback signal unessential consumers 3 tripped
   varx06 : BOOL ;
   varx07 : BOOL ;
   varx08 : BOOL ;
   varx09 : BOOL ;
   varx10 : BOOL ;
   a_BUS_L1_N : INT ;   //GENOP71-->: Busbar voltage between L1-N [V]
   a_BUS_L2_N : INT ;   //GENOP71-->: Busbar voltage between L2-N [V]
   a_BUS_L3_N : INT ;   //GENOP71-->: Busbar voltage between L3-N [V]
   a_BUS_L1_L2 : INT ;  //GENOP71-->: Busbar voltage between L1-L2 [V]
   a_BUS_L1_L3 : INT ;  //GENOP71-->: Busbar voltage between L1-L3 [V]
   a_BUS_L2_L3 : INT ;  //GENOP71-->: Busbar voltage between L2-L3 [V]
   a_GEN_L1_N : INT ;   //GENOP71-->: Generator voltage between L1-N [V]
   a_GEN_L2_N : INT ;   //GENOP71-->: Generator voltage between L2-N [V]
   a_GEN_L3_N : INT ;   //GENOP71-->: Generator voltage between L3-N [V]
   a_GEN_L1_L2 : INT ;  //GENOP71-->: Generator voltage between L1-L2 [V]
   a_GEN_L1_L3 : INT ;  //GENOP71-->: Generator voltage between L1-L3 [V]
   a_GEN_L2_L3 : INT ;  //GENOP71-->: Generator voltage between L2-L3 [V]
   a_I_L1 : INT ;   //GENOP71-->: Current of phase L1 [A]
   a_I_L2 : INT ;   //GENOP71-->: Current of phase L2 [A]
   a_I_L3 : INT ;   //GENOP71-->: Current of phase L3 [A]
   a_P_SUM : INT ;  //GENOP71-->: Active power [kW]
   a_Q_SUM : INT ;  //GENOP71-->: Reactive power [kVAr]
   a_S_SUM : INT ;  //GENOP71-->: Apparent power [kVA]
   a_FREQ_GEN : INT ;   //GENOP71-->: Generator frequency [0.1Hz]
   a_FREQ_BUS : INT ;   //GENOP71-->: Busbar frequency [0.1Hz]
   a_COS_PHI : INT ;    //GENOP71-->: Power factor
   a_PHI_SUM : INT ;    //GENOP71-->: Phase angle
   varx11 : INT ;
   p_GW1_SET : INT ;    //GENOP71-->: Current limit GW1 [A]: Uness. cons. 1-3, time-graded
   p_GW2_SET : INT ;    //GENOP71-->: Current limit GW2 [A]: -- not used --
   p_GW3_SET : INT ;    //GENOP71-->: Current limit GW3 [A]: Uness. cons. 1-3
   p_GW4_SET : INT ;    //GENOP71-->: Current limit GW4 [A]: Overcurrent, generator breaker Off
   p_GW5_SET : INT ;    //GENOP71-->: Reverse power limit GW5 [A]: Generator breaker Off
   p_GW6_SET : INT ;    //GENOP71-->: Short-circuit current limit GW6 [A]: Generator breaker Off
   p_T_GW1_SET : INT ;  //GENOP71-->: Delay time GW1 [0.1s]: Uness. consumers 1
   p_T_GW2_SET : INT ;  //GENOP71-->: Delay time GW1 [0.1s]: Uness. consumers 2
   p_T_GW3_SET : INT ;  //GENOP71-->: Delay time GW1 [0.1s]: Uness. consumers 3
   p_T_GW31_SET : INT ; //GENOP71-->: Delay time GW3 [0.1s]: Uness. consumers 1-3
   p_T_GW4_SET : INT ;  //GENOP71-->: Delay time GW4 [0.1s]: Overcurrent, generator breaker Off
   p_T_GW5_SET : INT ;  //GENOP71-->: Delay time GW5 [0.1s]: Reverse power, generator breaker Off
   p_T_GW6_SET : INT ;  //GENOP71-->: Delay time GW6 [0.1s]: Short circuit, generator breaker Off
   p_T_p_SYNK_SET : INT ;   //GENOP71-->: Synchronizing: Short pulse duration [0.1s]
   p_T_p_SYNL_SET : INT ;   //GENOP71-->: Synchronizing: Long pulse duration [0.1s]
   p_GW_DL_SET : INT ;  //GENOP71-->: Synchronizing: Limit continuous signal <--> long pulse [0.1Hz]
   p_GW_LK_SET : INT ;  //GENOP71-->: Synchronizing: Limit long pulse <--> short pulse [0.1Hz]
   p_T_p_SYNDL_SET : INT ;  //GENOP71-->: Synchronizing: Waiting time before frequency detuning [s]
   p_T_p_SYNV_SET : INT ;   //GENOP71-->: Synchronizing: Pulse duration for frequency detuning [0.1s]
   p_SYN_BLO_SET : INT ;    //GENOP71-->: Synchronizing: Frequency limit for enabling [0.1Hz]
   p_U_DIFF_SET : INT ; //GENOP71-->: Synchronizing: Voltage limit for enabling [V]
   p_SYN_SET : INT ;    //GENOP71-->: Synchronizing: Frequency limit for breaker closing (0.1Hz)
   p_T_VORH_SET : INT ; //GENOP71-->: Synchronizing: Lead time for generator breaker closing [msec]
   p_T_EIN_SET : INT ;  //GENOP71-->: Pulse duration for generator breaker closing command [s]
   p_UPRIM_SET : INT ;  //GENOP71-->: Voltage transformer primary [V]
   p_IPRIM_SET : INT ;  //GENOP71-->: Current transformer primary [A]
   p_PULS_RELA_S : INT ;    //GENOP71-->: Synchronizing: Mark-to-space ratio of short pulse [1-1000%]
   p_PULS_RELA_L : INT ;    //GENOP71-->: Synchronizing: Mark-to-space ratio of long pulse [1-1000%]
   varx12 : INT ;
   varx13 : INT ;
  END_STRUCT ;
BEGIN
   c_A_RES := FALSE;
   c_F_LOWER := FALSE;
   c_F_HIGHER := FALSE;
   c_SYN_EN := FALSE;
   c_BR_ON := FALSE;
   c_BR_OFF := FALSE;
   I_SC_RES := FALSE;
   c_AUT_EN := FALSE;
   var01 := FALSE;
   var02 := FALSE;
   var03 := FALSE;
   var04 := FALSE;
   var05 := FALSE;
   var06 := FALSE;
   i_L_FLAG_S := FALSE;
   var08 := FALSE;
   c_GW1_BLO := FALSE;
   c_GW2_BLO := FALSE;
   c_GW3_BLO := FALSE;
   c_GW4_BLO := FALSE;
   c_GW5_BLO := FALSE;
   c_GW6_BLO := FALSE;
   var09 := FALSE;
   var10 := FALSE;
   c_GW1_OUT_ON := FALSE;
   c_GW2_OUT_ON := FALSE;
   c_GW3_OUT_ON := FALSE;
   var11 := FALSE;
   var12 := FALSE;
   var13 := FALSE;
   var14 := FALSE;
   var15 := FALSE;
   var16 := L#0;
   var17 := L#0;
   var18 := L#0;
   var19 := L#0;
   var20 := L#0;
   var21 := L#0;
   var22 := L#0;
   var23 := L#0;
   var24 := L#0;
   var25 := L#0;
   var26 := L#0;
   var27 := 0;
   s_GW1_SET := 1692;
   s_GW2_SET := 1000;
   s_GW3_SET := 2030;
   s_GW4_SET := 2792;
   s_GW5_SET := -94;
   s_GW6_SET := 5076;
   s_T_GW1_SET := 50;
   s_T_GW2_SET := 100;
   s_T_GW3_SET := 150;
   s_T_GW31_SET := 10;
   s_T_GW4_SET := 150;
   s_T_GW5_SET := 60;
   s_T_GW6_SET := 6;
   s_T_SYNK_SET := 15;
   s_T_SYNL_SET := 30;
   s_GW_DL_SET := 20;
   s_GW_LK_SET := 10;
   s_T_SYNDL_SET := 10;
   s_T_SYNV_SET := 10;
   s_SYN_BLO_SET := 100;
   s_U_DIFF_SET := 20;
   s_SYN_SET := 5;
   s_T_VORH_SET := 80;
   s_T_EIN_SET := 2;
   s_UPRIM_SET := 400;
   s_IPRIM_SET := 2000;
   s_PULS_RELA_S := 267;
   s_PULS_RELA_L := 33;
   var28 := 0;
   var29 := 0;
   e_I_GW1UNV := FALSE;
   e_I_GW2UNV := FALSE;
   e_I_GW3UNV := FALSE;
   e_I_GW4UNV := FALSE;
   e_P_GW1UNV := FALSE;
   e_I_SC_GW1 := FALSE;
   i_L_FLAG_R := FALSE;
   i_W_DOG := FALSE;
   e_I_GW1VER := FALSE;
   e_I_GW2VER := FALSE;
   e_I_GW3VER := FALSE;
   e_I_GW4VER := FALSE;
   e_P_GW1VER := FALSE;
   e_I_SC_VER := FALSE;
   e_I_GW31VER := FALSE;
   i_Gen_syn_en := FALSE;
   i_GW1_BLO := FALSE;
   i_GW2_BLO := FALSE;
   i_GW3_BLO := FALSE;
   i_GW4_BLO := FALSE;
   i_GW5_BLO := FALSE;
   i_GW6_BLO := FALSE;
   i_BR_ON := FALSE;
   varx05 := FALSE;
   e_GW1_OUT_ON := FALSE;
   e_GW2_OUT_ON := FALSE;
   e_GW3_OUT_ON := FALSE;
   varx06 := FALSE;
   varx07 := FALSE;
   varx08 := FALSE;
   varx09 := FALSE;
   varx10 := FALSE;
   a_BUS_L1_N := 0;
   a_BUS_L2_N := 0;
   a_BUS_L3_N := 0;
   a_BUS_L1_L2 := 0;
   a_BUS_L1_L3 := 0;
   a_BUS_L2_L3 := 0;
   a_GEN_L1_N := 0;
   a_GEN_L2_N := 0;
   a_GEN_L3_N := 0;
   a_GEN_L1_L2 := 0;
   a_GEN_L1_L3 := 0;
   a_GEN_L2_L3 := 0;
   a_I_L1 := 0;
   a_I_L2 := 0;
   a_I_L3 := 0;
   a_P_SUM := 0;
   a_Q_SUM := 0;
   a_S_SUM := 0;
   a_FREQ_GEN := 0;
   a_FREQ_BUS := 0;
   a_COS_PHI := 0;
   a_PHI_SUM := 0;
   varx11 := 0;
   p_GW1_SET := 0;
   p_GW2_SET := 0;
   p_GW3_SET := 0;
   p_GW4_SET := 0;
   p_GW5_SET := 0;
   p_GW6_SET := 0;
   p_T_GW1_SET := 0;
   p_T_GW2_SET := 0;
   p_T_GW3_SET := 0;
   p_T_GW31_SET := 0;
   p_T_GW4_SET := 0;
   p_T_GW5_SET := 0;
   p_T_GW6_SET := 0;
   p_T_p_SYNK_SET := 0;
   p_T_p_SYNL_SET := 0;
   p_GW_DL_SET := 0;
   p_GW_LK_SET := 0;
   p_T_p_SYNDL_SET := 0;
   p_T_p_SYNV_SET := 0;
   p_SYN_BLO_SET := 0;
   p_U_DIFF_SET := 0;
   p_SYN_SET := 0;
   p_T_VORH_SET := 0;
   p_T_EIN_SET := 0;
   p_UPRIM_SET := 0;
   p_IPRIM_SET := 0;
   p_PULS_RELA_S := 0;
   p_PULS_RELA_L := 0;
   varx12 := 0;
   varx13 := 0;
END_DATA_BLOCK




DATA_BLOCK "I_tie1SR"
TITLE =Interface tie breaker 1. The 1. part contains the send
//area, the 2.part the receive area.                                                !
//
// I_Tie1SR
// Sende-/Empfangsfach MPI Kuppelschalter 1
// Der Datenaustausch von oder zum Kuppelschalter 1 erfolgt über diesen DB. Das Sendefach liegt im
// ersten Teil, das Empfangsteil liegt im zweiten Teil.
//
// Dieser DB ist für den TYP GENERATOR.
//
//
//  Siemens AG ATD IS3T, Kahle +494028892022, jens.kahle@hbg.siemens.de
//  PMA71
//  = Sende-/Empfangsfach MPI Generator 1
//  Datum aktuelle Version: 04.03.99
//  Version, Änd-Datum, Bearbeiter, geänderte Variablen
//  01.01,   31.01.99,  Kahle,      erste Version
//  01.02,   10.03.99,  Kahle,      Start/StoppReihenfolge,Kommando-
//                                  Spiegel, binäre Signale umsortieren
//
//KNOW_HOW_PROTECT
// (If specified, no more changes can be made once the block is generated)
//UNLINKED
// (If specified, the generated block is only available in the PLC load
//  memory)
//READ_ONLY
// (If specified, the generated block cannot be changed in the programmable
//  controller)
AUTHOR : Kahle
FAMILY : PMA71
NAME : I_Tie1SR
VERSION : 1.3


  STRUCT    // SENDEFACH
   c_reqStrt : BOOL ;   //Command: Request next generator set
   c_req2Strt : BOOL ;  //Command: Request second generator set
   c_reqEStrt : BOOL ;  //Command: Emergency request next generator set
   c_req2EStrt : BOOL ; //Command: Emergency request second generator set
   c_genBrkOpn : BOOL ; //Command: Generator breaker open by protection
   var01 : BOOL ;
   var02 : BOOL ;
   var03 : BOOL ;
   c_unitLock : BOOL ;  //Command: Block generator set
   c_simulLock : BOOL ; //Command: Simultaneous lock activating
   c_uncUBLoff : BOOL ; //Command: force UBL mode off
   c_shoreMode : BOOL ; //Command: Shore connection mode activating
   var04 : BOOL ;
   c_takePreSeOrd : BOOL ;  //Command: Take over pre select order via MPI
   c_preSeLock : BOOL ; //Command: Preselection lock activating
   c_life : BOOL ;  //Life-Flag
   var051 : BYTE ;
   var052 : BYTE ;
   a_cmdMirror : DINT ; //Command mirror (bit 0 ..31)
   var052a : BOOL ;
   var052b : BOOL ;
   var052c : BOOL ;
   var052d : BOOL ;
   var052e : BOOL ;
   var052f : BOOL ;
   var052g : BOOL ;
   var052h : BOOL ;
   f_simulLock : BOOL ; //Feedback: Simultaneous lock
   f_preSeLock : BOOL ; //Feedback: Preselection lock activating
   var052i : BOOL ;
   f_busy_Gset : BOOL ; //Feedback: Preselection lock request not possible in the moment
   var053a : BOOL ;
   var053b : BOOL ;
   var053c : BOOL ;
   var053d : BOOL ;
   var053e : BOOL ;
   var053f : BOOL ;
   var054g : BOOL ; //
   var055 : BOOL ;
   var055a : BOOL ;
   c_lockShtdwn : BOOL ;    //Command: no stop in case of underload (=1)
   c_takeLckShtdn : BOOL ;  //Command: take over command 'no stop in case of underload'
   var055b : BOOL ;
   c_LckCtrl : BOOL ; //Command: Lock controller (load & frequency) -TIE BREAKER ONLY-
   c_takeLckCtrl : BOOL ;   //Command: take over 'Lock controller' -TIE BREAKER ONLY-
   f_tieBrkOn : BOOL ;  //Feedback: tie breaker on -TIE BREAKER ONLY-
   f_tieBrkTrip : BOOL ;    //Feedback: tie breaker tripped -TIE BREAKER ONLY-
   var056a : BOOL ;
   f_2ndTieBrkOn : BOOL ;   //Feedback: 2nd tie breaker on -TIE BREAKER ONLY-
   f_2ndTieBrkTrip : BOOL ; //Feedback: 2nd tie breaker tripped -TIE BREAKER ONLY-
   var056d : BOOL ;
   a_load : INT ;   // Actual value: Active power
   s_ordSq1_8 : DINT ;  //setpoint: Start stop sequence of the actual configuration - (Gen.1 -8) -
   s_ordSq9_15 : DINT ; //Setpoint: Start stop sequence of the actual configuration - (Gen.9 -15) -
   var131 : BYTE ;
   var14 : BYTE ;
   var15 : BYTE ;
   var16 : BYTE ;
   var17 : INT ;
   var18 : INT ;    // EMPFANGSFACH
   c_reqStrtT1 : BOOL ; //Command: Request next generator set
   c_req2StrtT1 : BOOL ;    //Command: Request second generator set
   c_reqEStrtT1 : BOOL ;    //Command: Emergency request next generator set
   c_req2EStrtT1 : BOOL ;   //Command: Emergency request second generator set
   c_genBrkOpnT1 : BOOL ;   //Command: Generator breaker open by protection
   var01T1 : BOOL ;
   var02T1 : BOOL ;
   var03T1 : BOOL ;
   c_unitLockT1 : BOOL ;    //Command: Block generator set
   c_simulLockT1 : BOOL ;   //Command: Simultaneous lock activating
   c_uncUBLoffT1 : BOOL ;   //Command: force UBL mode off
   c_shoreModeT1 : BOOL ;   //Command: Shore connection mode activating
   var04T1 : BOOL ;
   c_takePreSeOrdT1 : BOOL ;    //Command: Take over pre select order via MPI
   c_preSeLockT1 : BOOL ;   //Command: Preselection lock activating
   c_lifeT1 : BOOL ;    //Life-Flag
   var051T1 : BYTE ;
   var052T1 : BYTE ;
   a_cmdMirrorT1 : DINT ;   //Command mirror (bit 0 ..31)
   var052aT1 : BOOL ;
   var052bT1 : BOOL ;
   var052cT1 : BOOL ;
   var052dT1 : BOOL ;
   var052eT1 : BOOL ;
   var052fT1 : BOOL ;
   var052gT1 : BOOL ;
   var052hT1 : BOOL ;
   f_simulLockT1 : BOOL ;   //Feedback: Simultaneous lock
   f_preSeLockT1 : BOOL ;   //Feedback: Preselection lock activating
   var052iT1 : BOOL ;
   f_busy_GsetT1 : BOOL ;   //Feedback: Preselection lock request not possible in the moment
   var053aT1 : BOOL ;
   var053bT1 : BOOL ;
   var053cT1 : BOOL ;
   var053dT1 : BOOL ;
   var053eT1 : BOOL ;
   var053fT1 : BOOL ;
   var053gT1 : BOOL ;
   var055T1 : BOOL ;
   var053hT1 : BOOL ;
   c_lockShtdwnT1 : BOOL ;  //Command: no stop in case of underload (=1)
   c_takeLckShtdnT1 : BOOL ;    //Command: take over command 'no stop in case of underload'
   var053iT1 : BOOL ;
   c_LckCtrlT1 : BOOL ; //Command: Lock controller (load & frequency) -TIE BREAKER ONLY -
   c_takeLckCtrlT1 : BOOL ; //Command: take over 'Lock controller' -TIE BREAKER ONLY-
   f_tieBrkOnT1 : BOOL ;    //Feedback: tie breaker on -TIE BREAKER ONLY-
   f_tieBrkTripT1 : BOOL ;  //Feedback: tie breaker tripped -TIE BREAKER ONLY-
   var056aT1 : BOOL ;
   f_2ndTieBrkOnT1 : BOOL ; //Feedback: 2nd tie breaker on -TIE BREAKER ONLY-
   f_2ndTieBrkTripT1 : BOOL ;   //Feedback: 2nd tie breaker tripped -TIE BREAKER ONLY-
   var056dT1 : BOOL ;
   a_loadT1 : INT ; // Actual value: Active power
   s_ordSq1_8T1 : DINT ;    //setpoint: Start stop sequence of the actual configuration - (Gen.1 -8) -
   s_ordSq9_15T1 : DINT ;   // Setpoint: Start stop sequence of the actual configuration - (Gen.9 -15) -
   var131T1 : BYTE ;
   var14T1 : BYTE ;
   var15T1 : BYTE ;
   var16T1 : BYTE ;
   var19T1 : INT ;
   var20T1 : INT ;
  END_STRUCT ;
BEGIN
   c_reqStrt := FALSE;
   c_req2Strt := FALSE;
   c_reqEStrt := FALSE;
   c_req2EStrt := FALSE;
   c_genBrkOpn := FALSE;
   var01 := FALSE;
   var02 := FALSE;
   var03 := FALSE;
   c_unitLock := FALSE;
   c_simulLock := FALSE;
   c_uncUBLoff := FALSE;
   c_shoreMode := FALSE;
   var04 := FALSE;
   c_takePreSeOrd := FALSE;
   c_preSeLock := FALSE;
   c_life := FALSE;
   var051 := B#16#0;
   var052 := B#16#0;
   a_cmdMirror := L#0;
   var052a := FALSE;
   var052b := FALSE;
   var052c := FALSE;
   var052d := FALSE;
   var052e := FALSE;
   var052f := FALSE;
   var052g := FALSE;
   var052h := FALSE;
   f_simulLock := FALSE;
   f_preSeLock := FALSE;
   var052i := FALSE;
   f_busy_Gset := FALSE;
   var053a := FALSE;
   var053b := FALSE;
   var053c := FALSE;
   var053d := FALSE;
   var053e := FALSE;
   var053f := FALSE;
   var054g := FALSE;
   var055 := FALSE;
   var055a := FALSE;
   c_lockShtdwn := FALSE;
   c_takeLckShtdn := FALSE;
   var055b := FALSE;
   c_LckCtrl := FALSE;
   c_takeLckCtrl := FALSE;
   f_tieBrkOn := FALSE;
   f_tieBrkTrip := FALSE;
   var056a := FALSE;
   f_2ndTieBrkOn := FALSE;
   f_2ndTieBrkTrip := FALSE;
   var056d := FALSE;
   a_load := 0;
   s_ordSq1_8 := L#0;
   s_ordSq9_15 := L#0;
   var131 := B#16#0;
   var14 := B#16#0;
   var15 := B#16#0;
   var16 := B#16#0;
   var17 := 0;
   var18 := 0;
   c_reqStrtT1 := FALSE;
   c_req2StrtT1 := FALSE;
   c_reqEStrtT1 := FALSE;
   c_req2EStrtT1 := FALSE;
   c_genBrkOpnT1 := FALSE;
   var01T1 := FALSE;
   var02T1 := FALSE;
   var03T1 := FALSE;
   c_unitLockT1 := FALSE;
   c_simulLockT1 := FALSE;
   c_uncUBLoffT1 := FALSE;
   c_shoreModeT1 := FALSE;
   var04T1 := FALSE;
   c_takePreSeOrdT1 := FALSE;
   c_preSeLockT1 := FALSE;
   c_lifeT1 := FALSE;
   var051T1 := B#16#0;
   var052T1 := B#16#0;
   a_cmdMirrorT1 := L#0;
   var052aT1 := FALSE;
   var052bT1 := FALSE;
   var052cT1 := FALSE;
   var052dT1 := FALSE;
   var052eT1 := FALSE;
   var052fT1 := FALSE;
   var052gT1 := FALSE;
   var052hT1 := FALSE;
   f_simulLockT1 := FALSE;
   f_preSeLockT1 := FALSE;
   var052iT1 := FALSE;
   f_busy_GsetT1 := FALSE;
   var053aT1 := FALSE;
   var053bT1 := FALSE;
   var053cT1 := FALSE;
   var053dT1 := FALSE;
   var053eT1 := FALSE;
   var053fT1 := FALSE;
   var053gT1 := FALSE;
   var055T1 := FALSE;
   var053hT1 := FALSE;
   c_lockShtdwnT1 := FALSE;
   c_takeLckShtdnT1 := FALSE;
   var053iT1 := FALSE;
   c_LckCtrlT1 := FALSE;
   c_takeLckCtrlT1 := FALSE;
   f_tieBrkOnT1 := FALSE;
   f_tieBrkTripT1 := FALSE;
   var056aT1 := FALSE;
   f_2ndTieBrkOnT1 := FALSE;
   f_2ndTieBrkTripT1 := FALSE;
   var056dT1 := FALSE;
   a_loadT1 := 0;
   s_ordSq1_8T1 := L#0;
   s_ordSq9_15T1 := L#0;
   var131T1 := B#16#0;
   var14T1 := B#16#0;
   var15T1 := B#16#0;
   var16T1 := B#16#0;
   var19T1 := 0;
   var20T1 := 0;
END_DATA_BLOCK



DATA_BLOCK "I_tie2SR"
TITLE =Interface tie breaker 2. The 1. part contains the send
//area, the 2.part the receive area.                                                !
//
// I_Tie2SR
// Sende-/Empfangsfach MPI Kuppelschalter 2
// Der Datenaustausch von oder zum Kuppelschalter 2 erfolgt über diesen DB. Das Sendefach liegt im
// ersten Teil, das Empfangsteil liegt im zweiten Teil.
//
// Dieser DB ist für den TYP GENERATOR.
//
//
//  Siemens AG ATD IS3T, Kahle +494028892022, jens.kahle@hbg.siemens.de
//  PMA71
//  = Sende-/Empfangsfach MPI Generator 1
//  Datum aktuelle Version: 04.03.99
//  Version, Änd-Datum, Bearbeiter, geänderte Variablen
//  01.01,   31.01.99,  Kahle,      erste Version
//  01.02,   10.03.99,  Kahle,      Start/StoppReihenfolge,Kommando-
//                                  Spiegel, binäre Signale umsortieren
//
//KNOW_HOW_PROTECT
// (If specified, no more changes can be made once the block is generated)
//UNLINKED
// (If specified, the generated block is only available in the PLC load
//  memory)
//READ_ONLY
// (If specified, the generated block cannot be changed in the programmable
//  controller)
AUTHOR : Kahle
FAMILY : PMA71
NAME : I_Tie2SR
VERSION : 1.3


  STRUCT    // SENDEFACH
   c_reqStrt : BOOL ;   //Command: Request next generator set
   c_req2Strt : BOOL ;  //Command: Request second generator set
   c_reqEStrt : BOOL ;  //Command: Emergency request next generator set
   c_req2EStrt : BOOL ; //Command: Emergency request second generator set
   c_genBrkOpn : BOOL ; //Command: Generator breaker open by protection
   var01 : BOOL ;
   var02 : BOOL ;
   var03 : BOOL ;
   c_unitLock : BOOL ;  //Command: Block generator set
   c_simulLock : BOOL ; //Command: Simultaneous lock activating
   c_uncUBLoff : BOOL ; //Command: force UBL mode off
   c_shoreMode : BOOL ; //Command: Shore connection mode activating
   var04 : BOOL ;
   c_takePreSeOrd : BOOL ;  //Command: Take over pre select order via MPI
   c_preSeLock : BOOL ; //Command: Preselection lock activating
   c_life : BOOL ;  //Life-Flag
   var051 : BYTE ;
   var052 : BYTE ;
   a_cmdMirror : DINT ; //Command mirror (bit 0 ..31)
   var052a : BOOL ;
   var052b : BOOL ;
   var052c : BOOL ;
   var052d : BOOL ;
   var052e : BOOL ;
   var052f : BOOL ;
   var052g : BOOL ;
   var052h : BOOL ;
   f_simulLock : BOOL ; //Feedback: Simultaneous lock
   f_preSeLock : BOOL ; //Feedback: Preselection lock activating
   var052i : BOOL ;
   f_busy_Gset : BOOL ; //Feedback: Preselection lock request not possible in the moment
   var053a : BOOL ;
   var053b : BOOL ;
   var053c : BOOL ;
   var053d : BOOL ;
   var053e : BOOL ;
   var053f : BOOL ;
   var054g : BOOL ; //
   var055 : BOOL ;
   var055a : BOOL ;
   c_lockShtdwn : BOOL ;    //Command: no stop in case of underload (=1)
   c_takeLckShtdn : BOOL ;  //Command: take over command 'no stop in case of underload'
   var055b : BOOL ;
   c_LckCtrl : BOOL ;   //Command: Lock controller (load & frequency) -TIE BREAKER ONLY-
   c_takeLckCtrl : BOOL ;   //Command: take over 'Lock controller' -TIE BREAKER ONLY-
   f_tieBrkOn : BOOL ;  //Feedback: tie breaker on -TIE BREAKER ONLY-
   f_tieBrkTrip : BOOL ;    //Feedback: tie breaker tripped -TIE BREAKER ONLY-
   var056a : BOOL ;
   f_2ndTieBrkOn : BOOL ;   //Feedback: 2nd tie breaker on -TIE BREAKER ONLY-
   f_2ndTieBrkTrip : BOOL ; //Feedback: 2nd tie breaker tripped -TIE BREAKER ONLY-
   var056d : BOOL ;
   a_load : INT ;   // Actual value: Active power
   s_ordSq1_8 : DINT ;  //setpoint: Start stop sequence of the actual configuration - (Gen.1 -8) -
   s_ordSq9_15 : DINT ; //Setpoint: Start stop sequence of the actual configuration - (Gen.9 -15) -
   var131 : BYTE ;
   var14 : BYTE ;
   var15 : BYTE ;
   var16 : BYTE ;
   var17 : INT ;
   var18 : INT ;    // EMPFANGSFACH
   c_reqStrtT2 : BOOL ; //Command: Request next generator set
   c_req2StrtT2 : BOOL ;    //Command: Request second generator set
   c_reqEStrtT2 : BOOL ;    //Command: Emergency request next generator set
   c_req2EStrtT2 : BOOL ;   //Command: Emergency request second generator set
   c_genBrkOpnT2 : BOOL ;   //Command: Generator breaker open by protection
   var01T2 : BOOL ;
   var02T2 : BOOL ;
   var03T2 : BOOL ;
   c_unitLockT2 : BOOL ;    //Command: Block generator set
   c_simulLockT2 : BOOL ;   //Command: Simultaneous lock activating
   c_uncUBLoffT2 : BOOL ;   //Command: force UBL mode off
   c_shoreModeT2 : BOOL ;    //Command: Shore connection mode activating
   var04T2 : BOOL ;
   c_takePreSeOrdT2 : BOOL ;    //Command: Take over pre select order via MPI
   c_preSeLockT2 : BOOL ;   //Command: Preselection lock activating
   c_lifeT2 : BOOL ;    //Life-Flag
   var051T2 : BYTE ;
   var052T2 : BYTE ;
   a_cmdMirrorT2 : DINT ;   //Command mirror (bit 0 ..31)
   var052aT2 : BOOL ;
   var052bT2 : BOOL ;
   var052cT2 : BOOL ;
   var052dT2 : BOOL ;
   var052eT2 : BOOL ;
   var052fT2 : BOOL ;
   var052gT2 : BOOL ;
   var052hT2 : BOOL ;
   f_simulLockT2 : BOOL ;   //Feedback: Simultaneous lock
   f_preSeLockT2 : BOOL ;   //Feedback: Preselection lock activating
   var052iT2 : BOOL ;
   f_busy_GsetT2 : BOOL ;   //Feedback: Preselection lock request not possible in the moment
   var053aT2 : BOOL ;
   var053bT2 : BOOL ;
   var053cT2 : BOOL ;
   var053dT2 : BOOL ;
   var053eT2 : BOOL ;
   var053fT2 : BOOL ;
   var053gT2 : BOOL ;
   var055T2 : BOOL ;
   var053hT2 : BOOL ;
   c_lockShtdwnT2 : BOOL ;    //Command: no stop in case of underload (=1)
   c_takeLckShtdnT2 : BOOL ;    //Command: take over command 'no stop in case of underload'
   var053iT2 : BOOL ;
   c_LckCtrlT2 : BOOL ; //Command: Lock controller (load & frequency) -TIE BREAKER ONLY -
   c_takeLckCtrlT2 : BOOL ; //Command: take over 'Lock controller' -TIE BREAKER ONLY-
   f_tieBrkOnT2 : BOOL ;    //Feedback: tie breaker on -TIE BREAKER ONLY-
   f_tieBrkTripT2 : BOOL ;  //Feedback: tie breaker tripped -TIE BREAKER ONLY-
   var056aT2 : BOOL ;
   f_2ndTieBrkOnT2 : BOOL ; //Feedback: 2nd tie breaker on -TIE BREAKER ONLY-
   f_2ndTieBrkTripT2 : BOOL ;   //Feedback: 2nd tie breaker tripped -TIE BREAKER ONLY-
   var056dT2 : BOOL ;
   a_loadT2 : INT ; // Actual value: Active power
   s_ordSq1_8T2 : DINT ;    //setpoint: Start stop sequence of the actual configuration - (Gen.1 -8) -
   s_ordSq9_15T2 : DINT ;   // Setpoint: Start stop sequence of the actual configuration - (Gen.9 -15) -
   var131T2 : BYTE ;
   var14T2 : BYTE ;
   var15T2 : BYTE ;
   var16T2 : BYTE ;
   var19T2 : INT ;
   var20T2 : INT ;
  END_STRUCT ;
BEGIN
   c_reqStrt := FALSE;
   c_req2Strt := FALSE;
   c_reqEStrt := FALSE;
   c_req2EStrt := FALSE;
   c_genBrkOpn := FALSE;
   var01 := FALSE;
   var02 := FALSE;
   var03 := FALSE;
   c_unitLock := FALSE;
   c_simulLock := FALSE;
   c_uncUBLoff := FALSE;
   c_shoreMode := FALSE;
   var04 := FALSE;
   c_takePreSeOrd := FALSE;
   c_preSeLock := FALSE;
   c_life := FALSE;
   var051 := B#16#0;
   var052 := B#16#0;
   a_cmdMirror := L#0;
   var052a := FALSE;
   var052b := FALSE;
   var052c := FALSE;
   var052d := FALSE;
   var052e := FALSE;
   var052f := FALSE;
   var052g := FALSE;
   var052h := FALSE;
   f_simulLock := FALSE;
   f_preSeLock := FALSE;
   var052i := FALSE;
   f_busy_Gset := FALSE;
   var053a := FALSE;
   var053b := FALSE;
   var053c := FALSE;
   var053d := FALSE;
   var053e := FALSE;
   var053f := FALSE;
   var054g := FALSE;
   var055 := FALSE;
   var055a := FALSE;
   c_lockShtdwn := FALSE;
   c_takeLckShtdn := FALSE;
   var055b := FALSE;
   c_LckCtrl := FALSE;
   c_takeLckCtrl := FALSE;
   f_tieBrkOn := FALSE;
   f_tieBrkTrip := FALSE;
   var056a := FALSE;
   f_2ndTieBrkOn := FALSE;
   f_2ndTieBrkTrip := FALSE;
   var056d := FALSE;
   a_load := 0;
   s_ordSq1_8 := L#0;
   s_ordSq9_15 := L#0;
   var131 := B#16#0;
   var14 := B#16#0;
   var15 := B#16#0;
   var16 := B#16#0;
   var17 := 0;
   var18 := 0;
   c_reqStrtT2 := FALSE;
   c_req2StrtT2 := FALSE;
   c_reqEStrtT2 := FALSE;
   c_req2EStrtT2 := FALSE;
   c_genBrkOpnT2 := FALSE;
   var01T2 := FALSE;
   var02T2 := FALSE;
   var03T2 := FALSE;
   c_unitLockT2 := FALSE;
   c_simulLockT2 := FALSE;
   c_uncUBLoffT2 := FALSE;
   c_shoreModeT2 := FALSE;
   var04T2 := FALSE;
   c_takePreSeOrdT2 := FALSE;
   c_preSeLockT2 := FALSE;
   c_lifeT2 := FALSE;
   var051T2 := B#16#0;
   var052T2 := B#16#0;
   a_cmdMirrorT2 := L#0;
   var052aT2 := FALSE;
   var052bT2 := FALSE;
   var052cT2 := FALSE;
   var052dT2 := FALSE;
   var052eT2 := FALSE;
   var052fT2 := FALSE;
   var052gT2 := FALSE;
   var052hT2 := FALSE;
   f_simulLockT2 := FALSE;
   f_preSeLockT2 := FALSE;
   var052iT2 := FALSE;
   f_busy_GsetT2 := FALSE;
   var053aT2 := FALSE;
   var053bT2 := FALSE;
   var053cT2 := FALSE;
   var053dT2 := FALSE;
   var053eT2 := FALSE;
   var053fT2 := FALSE;
   var053gT2 := FALSE;
   var055T2 := FALSE;
   var053hT2 := FALSE;
   c_lockShtdwnT2 := FALSE;
   c_takeLckShtdnT2 := FALSE;
   var053iT2 := FALSE;
   c_LckCtrlT2 := FALSE;
   c_takeLckCtrlT2 := FALSE;
   f_tieBrkOnT2 := FALSE;
   f_tieBrkTripT2 := FALSE;
   var056aT2 := FALSE;
   f_2ndTieBrkOnT2 := FALSE;
   f_2ndTieBrkTripT2 := FALSE;
   var056dT2 := FALSE;
   a_loadT2 := 0;
   s_ordSq1_8T2 := L#0;
   s_ordSq9_15T2 := L#0;
   var131T2 := B#16#0;
   var14T2 := B#16#0;
   var15T2 := B#16#0;
   var16T2 := B#16#0;
   var19T2 := 0;
   var20T2 := 0;
END_DATA_BLOCK



DATA_BLOCK "I_tie3SR"
TITLE =Interface tie breaker 3. The 1. part contains the send
//area, the 2.part the receive area.                                                !
//
// I_Tie3SR
// Sende-/Empfangsfach MPI Kuppelschalter 3
// Der Datenaustausch von oder zum Kuppelschalter 3 erfolgt über diesen DB. Das Sendefach liegt im
// ersten Teil, das Empfangsteil liegt im zweiten Teil.
//
// Dieser DB ist für den TYP GENERATOR.
//
//
//  Siemens AG ATD IS3T, Kahle +494028892022, jens.kahle@hbg.siemens.de
//  PMA71
//  = Sende-/Empfangsfach MPI Generator 1
//  Datum aktuelle Version: 04.03.99
//  Version, Änd-Datum, Bearbeiter, geänderte Variablen
//  01.01,   31.01.99,  Kahle,      erste Version
//  01.02,   10.03.99,  Kahle,      Start/StoppReihenfolge,Kommando-
//                                  Spiegel, binäre Signale umsortieren
//
//KNOW_HOW_PROTECT
// (If specified, no more changes can be made once the block is generated)
//UNLINKED
// (If specified, the generated block is only available in the PLC load
//  memory)
//READ_ONLY
// (If specified, the generated block cannot be changed in the programmable
//  controller)
AUTHOR : Kahle
FAMILY : PMA71
NAME : I_Tie3SR
VERSION : 1.3


  STRUCT    // SENDEFACH
   c_reqStrt : BOOL ;   //Command: Request next generator set
   c_req2Strt : BOOL ;  //Command: Request second generator set
   c_reqEStrt : BOOL ;  //Command: Emergency request next generator set
   c_req2EStrt : BOOL ; //Command: Emergency request second generator set
   c_genBrkOpn : BOOL ; //Command: Generator breaker open by protection
   var01 : BOOL ;
   var02 : BOOL ;
   var03 : BOOL ;
   c_unitLock : BOOL ;  //Command: Block generator set
   c_simulLock : BOOL ; //Command: Simultaneous lock activating
   c_uncUBLoff : BOOL ; //Command: force UBL mode off
   c_shoreMode : BOOL ; //Command: Shore connection mode activating
   var04 : BOOL ;
   c_takePreSeOrd : BOOL ;    //Command: Take over pre select order via MPI
   c_preSeLock : BOOL ; //Command: Preselection lock activating
   c_life : BOOL ;  //Life-Flag
   var051 : BYTE ;
   var052 : BYTE ;
   a_cmdMirror : DINT ; //Command mirror (bit 0 ..31)
   var052a : BOOL ;
   var052b : BOOL ;
   var052c : BOOL ;
   var052d : BOOL ;
   var052e : BOOL ;
   var052f : BOOL ;
   var052g : BOOL ;
   var052h : BOOL ;
   f_simulLock : BOOL ; //Feedback: Simultaneous lock
   f_preSeLock : BOOL ; //Feedback: Preselection lock activating
   var052i : BOOL ;
   f_busy_Gset : BOOL ; //Feedback: Preselection lock request not possible in the moment
   var053a : BOOL ;
   var053b : BOOL ;
   var053c : BOOL ;
   var053d : BOOL ;
   var053e : BOOL ;
   var053f : BOOL ;
   var054g : BOOL ; //
   var055 : BOOL ;
   var055a : BOOL ;
   c_lockShtdwn : BOOL ;    //Command: no stop in case of underload (=1)
   c_takeLckShtdn : BOOL ;  //Command: take over command 'no stop in case of underload'
   var055b : BOOL ;
   c_LckCtrl : BOOL ;   //Command: Lock controller (load & frequency) -TIE BREAKER ONLY-
   c_takeLckCtrl : BOOL ;   //Command: take over 'Lock controller' -TIE BREAKER ONLY-
   f_tieBrkOn : BOOL ;  //Feedback: tie breaker on -TIE BREAKER ONLY-
   f_tieBrkTrip : BOOL ;    //Feedback: tie breaker tripped -TIE BREAKER ONLY-
   var056a : BOOL ;
   f_2ndTieBrkOn : BOOL ;   //Feedback: 2nd tie breaker on -TIE BREAKER ONLY-
   f_2ndTieBrkTrip : BOOL ; //Feedback: 2nd tie breaker tripped -TIE BREAKER ONLY-
   var056d : BOOL ;
   a_load : INT ;   // Actual value: Active power
   s_ordSq1_8 : DINT ;  //setpoint: Start stop sequence of the actual configuration - (Gen.1 -8) -
   s_ordSq9_15 : DINT ; //Setpoint: Start stop sequence of the actual configuration - (Gen.9 -15) -
   var131 : BYTE ;
   var14 : BYTE ;
   var15 : BYTE ;
   var16 : BYTE ;
   var17 : INT ;
   var18 : INT ;    // EMPFANGSFACH
   c_reqStrtT3 : BOOL ; //Command: Request next generator set
   c_req2StrtT3 : BOOL ; //Command: Request second generator set
   c_reqEStrtT3 : BOOL ;    //Command: Emergency request next generator set
   c_req2EStrtT3 : BOOL ;   //Command: Emergency request second generator set
   c_genBrkOpnT3 : BOOL ;   //Command: Generator breaker open by protection
   var01T3 : BOOL ;
   var02T3 : BOOL ;
   var03T3 : BOOL ;
   c_unitLockT3 : BOOL ;    //Command: Block generator set
   c_simulLockT3 : BOOL ;   //Command: Simultaneous lock activating
   c_uncUBLoffT3 : BOOL ;   //Command: force UBL mode off
   c_shoreModeT3 : BOOL ;   //Command: Shore connection mode activating
   var04T3 : BOOL ;
   c_takePreSeOrdT3 : BOOL ;    //Command: Take over pre select order via MPI
   c_preSeLockT3 : BOOL ;   //Command: Preselection lock activating
   c_lifeT3 : BOOL ;    //Life-Flag
   var051T3 : BYTE ;
   var052T3 : BYTE ;
   a_cmdMirrorT3 : DINT ;   //Command mirror (bit 0 ..31)
   var052aT3 : BOOL ;
   var052bT3 : BOOL ;
   var052cT3 : BOOL ;
   var052dT3 : BOOL ;
   var052eT3 : BOOL ;
   var052fT3 : BOOL ;
   var052gT3 : BOOL ;
   var052hT3 : BOOL ;
   f_simulLockT3 : BOOL ;   //Feedback: Simultaneous lock
   f_preSeLockT3 : BOOL ;   //Feedback: Preselection lock activating
   var052iT3 : BOOL ;
   f_busy_GsetT3 : BOOL ;   //Feedback: Preselection lock request not possible in the moment
   var053aT3 : BOOL ;
   var053bT3 : BOOL ;
   var053cT3 : BOOL ;
   var053dT3 : BOOL ;
   var053eT3 : BOOL ;
   var053fT3 : BOOL ;
   var053gT3 : BOOL ;
   var055T3 : BOOL ;
   var053hT3 : BOOL ;
   c_lockShtdwnT3 : BOOL ;  //Command: no stop in case of underload (=1)
   c_takeLckShtdnT3 : BOOL ;    //Command: take over command 'no stop in case of underload'
   var053iT3 : BOOL ;
   c_LckCtrlT3 : BOOL ; //Command: Lock controller (load & frequency) -TIE BREAKER ONLY -
   c_takeLckCtrlT3 : BOOL ; //Command: take over 'Lock controller' -TIE BREAKER ONLY-
   f_tieBrkOnT3 : BOOL ;    //Feedback: tie breaker on -TIE BREAKER ONLY-
   f_tieBrkTripT3 : BOOL ;  //Feedback: tie breaker tripped -TIE BREAKER ONLY-
   var056aT3 : BOOL ;
   f_2ndTieBrkOnT3 : BOOL ; //Feedback: 2nd tie breaker on -TIE BREAKER ONLY-
   f_2ndTieBrkTripT3 : BOOL ;   //Feedback: 2nd tie breaker tripped -TIE BREAKER ONLY-
   var056dT3 : BOOL ;
   a_loadT3 : INT ; // Actual value: Active power
   s_ordSq1_8T3 : DINT ;    //setpoint: Start stop sequence of the actual configuration - (Gen.1 -8) -
   s_ordSq9_15T3 : DINT ;   // Setpoint: Start stop sequence of the actual configuration - (Gen.9 -15) -
   var131T3 : BYTE ;
   var14T3 : BYTE ;
   var15T3 : BYTE ;
   var16T3 : BYTE ;
   var19T3 : INT ;
   var20T3 : INT ;
  END_STRUCT ;
BEGIN
   c_reqStrt := FALSE;
   c_req2Strt := FALSE;
   c_reqEStrt := FALSE;
   c_req2EStrt := FALSE;
   c_genBrkOpn := FALSE;
   var01 := FALSE;
   var02 := FALSE;
   var03 := FALSE;
   c_unitLock := FALSE;
   c_simulLock := FALSE;
   c_uncUBLoff := FALSE;
   c_shoreMode := FALSE;
   var04 := FALSE;
   c_takePreSeOrd := FALSE;
   c_preSeLock := FALSE;
   c_life := FALSE;
   var051 := B#16#0;
   var052 := B#16#0;
   a_cmdMirror := L#0;
   var052a := FALSE;
   var052b := FALSE;
   var052c := FALSE;
   var052d := FALSE;
   var052e := FALSE;
   var052f := FALSE;
   var052g := FALSE;
   var052h := FALSE;
   f_simulLock := FALSE;
   f_preSeLock := FALSE;
   var052i := FALSE;
   f_busy_Gset := FALSE;
   var053a := FALSE;
   var053b := FALSE;
   var053c := FALSE;
   var053d := FALSE;
   var053e := FALSE;
   var053f := FALSE;
   var054g := FALSE;
   var055 := FALSE;
   var055a := FALSE;
   c_lockShtdwn := FALSE;
   c_takeLckShtdn := FALSE;
   var055b := FALSE;
   c_LckCtrl := FALSE;
   c_takeLckCtrl := FALSE;
   f_tieBrkOn := FALSE;
   f_tieBrkTrip := FALSE;
   var056a := FALSE;
   f_2ndTieBrkOn := FALSE;
   f_2ndTieBrkTrip := FALSE;
   var056d := FALSE;
   a_load := 0;
   s_ordSq1_8 := L#0;
   s_ordSq9_15 := L#0;
   var131 := B#16#0;
   var14 := B#16#0;
   var15 := B#16#0;
   var16 := B#16#0;
   var17 := 0;
   var18 := 0;
   c_reqStrtT3 := FALSE;
   c_req2StrtT3 := FALSE;
   c_reqEStrtT3 := FALSE;
   c_req2EStrtT3 := FALSE;
   c_genBrkOpnT3 := FALSE;
   var01T3 := FALSE;
   var02T3 := FALSE;
   var03T3 := FALSE;
   c_unitLockT3 := FALSE;
   c_simulLockT3 := FALSE;
   c_uncUBLoffT3 := FALSE;
   c_shoreModeT3 := FALSE;
   var04T3 := FALSE;
   c_takePreSeOrdT3 := FALSE;
   c_preSeLockT3 := FALSE;
   c_lifeT3 := FALSE;
   var051T3 := B#16#0;
   var052T3 := B#16#0;
   a_cmdMirrorT3 := L#0;
   var052aT3 := FALSE;
   var052bT3 := FALSE;
   var052cT3 := FALSE;
   var052dT3 := FALSE;
   var052eT3 := FALSE;
   var052fT3 := FALSE;
   var052gT3 := FALSE;
   var052hT3 := FALSE;
   f_simulLockT3 := FALSE;
   f_preSeLockT3 := FALSE;
   var052iT3 := FALSE;
   f_busy_GsetT3 := FALSE;
   var053aT3 := FALSE;
   var053bT3 := FALSE;
   var053cT3 := FALSE;
   var053dT3 := FALSE;
   var053eT3 := FALSE;
   var053fT3 := FALSE;
   var053gT3 := FALSE;
   var055T3 := FALSE;
   var053hT3 := FALSE;
   c_lockShtdwnT3 := FALSE;
   c_takeLckShtdnT3 := FALSE;
   var053iT3 := FALSE;
   c_LckCtrlT3 := FALSE;
   c_takeLckCtrlT3 := FALSE;
   f_tieBrkOnT3 := FALSE;
   f_tieBrkTripT3 := FALSE;
   var056aT3 := FALSE;
   f_2ndTieBrkOnT3 := FALSE;
   f_2ndTieBrkTripT3 := FALSE;
   var056dT3 := FALSE;
   a_loadT3 := 0;
   s_ordSq1_8T3 := L#0;
   s_ordSq9_15T3 := L#0;
   var131T3 := B#16#0;
   var14T3 := B#16#0;
   var15T3 := B#16#0;
   var16T3 := B#16#0;
   var19T3 := 0;
   var20T3 := 0;
END_DATA_BLOCK



DATA_BLOCK "I_tie4SR"
TITLE =Interface tie breaker 4. The 1. part contains the send
//area, the 2.part the receive area.                                                !
//
// I_Tie4SR
// Sende-/Empfangsfach MPI Kuppelschalter 4
// Der Datenaustausch von oder zum Kuppelschalter 4 erfolgt über diesen DB. Das Sendefach liegt im
// ersten Teil, das Empfangsteil liegt im zweiten Teil.
//
// Dieser DB ist für den TYP GENERATOR.
//
//
//  Siemens AG ATD IS3T, Kahle +494028892022, jens.kahle@hbg.siemens.de
//  PMA71
//  = Sende-/Empfangsfach MPI Generator 1
//  Datum aktuelle Version: 04.03.99
//  Version, Änd-Datum, Bearbeiter, geänderte Variablen
//  01.01,   31.01.99,  Kahle,      erste Version
//  01.02,   10.03.99,  Kahle,      Start/StoppReihenfolge,Kommando-
//                                  Spiegel, binäre Signale umsortieren
//
//KNOW_HOW_PROTECT
// (If specified, no more changes can be made once the block is generated)
//UNLINKED
// (If specified, the generated block is only available in the PLC load
//  memory)
//READ_ONLY
// (If specified, the generated block cannot be changed in the programmable
//  controller)
AUTHOR : Kahle
FAMILY : PMA71
NAME : I_Tie4SR
VERSION : 1.3


  STRUCT    // SENDEFACH
   c_reqStrt : BOOL ;   //Command: Request next generator set
   c_req2Strt : BOOL ;  //Command: Request second generator set
   c_reqEStrt : BOOL ; //Command: Emergency request next generator set
   c_req2EStrt : BOOL ; //Command: Emergency request second generator set
   c_genBrkOpn : BOOL ; //Command: Generator breaker open by protection
   var01 : BOOL ;
   var02 : BOOL ;
   var03 : BOOL ;
   c_unitLock : BOOL ;  //Command: Block generator set
   c_simulLock : BOOL ; //Command: Simultaneous lock activating
   c_uncUBLoff : BOOL ; //Command: force UBL mode off
   c_shoreMode : BOOL ; //Command: Shore connection mode activating
   var04 : BOOL ;
   c_takePreSeOrd : BOOL ;  //Command: Take over pre select order via MPI
   c_preSeLock : BOOL ; //Command: Preselection lock activating
   c_life : BOOL ;  //Life-Flag
   var051 : BYTE ;
   var052 : BYTE ;
   a_cmdMirror : DINT ; //Command mirror (bit 0 ..31)
   var052a : BOOL ;
   var052b : BOOL ;
   var052c : BOOL ;
   var052d : BOOL ;
   var052e : BOOL ;
   var052f : BOOL ;
   var052g : BOOL ;
   var052h : BOOL ;
   f_simulLock : BOOL ; //Feedback: Simultaneous lock
   f_preSeLock : BOOL ;  //Feedback: Preselection lock activating
   var052i : BOOL ;
   f_busy_Gset : BOOL ; //Feedback: Preselection lock request not possible in the moment
   var053a : BOOL ;
   var053b : BOOL ;
   var053c : BOOL ;
   var053d : BOOL ;
   var053e : BOOL ;
   var053f : BOOL ;
   var054g : BOOL ; //
   var055 : BOOL ;
   var055a : BOOL ;
   c_lockShtdwn : BOOL ;    //Command: no stop in case of underload (=1)
   c_takeLckShtdn : BOOL ;  //Command: take over command 'no stop in case of underload'
   var055b : BOOL ;
   c_LckCtrl : BOOL ;   //Command: Lock controller (load & frequency) -TIE BREAKER ONLY-
   c_takeLckCtrl : BOOL ;   //Command: take over 'Lock controller' -TIE BREAKER ONLY-
   f_tieBrkOn : BOOL ;  //Feedback: tie breaker on -TIE BREAKER ONLY-
   f_tieBrkTrip : BOOL ;    //Feedback: tie breaker tripped -TIE BREAKER ONLY-
   var056a : BOOL ;
   f_2ndTieBrkOn : BOOL ;   //Feedback: 2nd tie breaker on -TIE BREAKER ONLY-
   f_2ndTieBrkTrip : BOOL ; //Feedback: 2nd tie breaker tripped -TIE BREAKER ONLY-
   var056d : BOOL ;
   a_load : INT ;   // Actual value: Active power
   s_ordSq1_8 : DINT ;  //setpoint: Start stop sequence of the actual configuration - (Gen.1 -8) -
   s_ordSq9_15 : DINT ; //Setpoint: Start stop sequence of the actual configuration - (Gen.9 -15) -
   var131 : BYTE ;
   var14 : BYTE ;
   var15 : BYTE ;
   var16 : BYTE ;
   var17 : INT ;
   var18 : INT ;    // EMPFANGSFACH
   c_reqStrtT4 : BOOL ; //Command: Request next generator set
   c_req2StrtT4 : BOOL ;    //Command: Request second generator set
   c_reqEStrtT4 : BOOL ;    //Command: Emergency request next generator set
   c_req2EStrtT4 : BOOL ;   //Command: Emergency request second generator set
   c_genBrkOpnT4 : BOOL ;   //Command: Generator breaker open by protection
   var01T4 : BOOL ;
   var02T4 : BOOL ;
   var03T4 : BOOL ;
   c_unitLockT4 : BOOL ;    //Command: Block generator set
   c_simulLockT4 : BOOL ;   //Command: Simultaneous lock activating
   c_uncUBLoffT4 : BOOL ;   //Command: force UBL mode off
   c_shoreModeT4 : BOOL ;   //Command: Shore connection mode activating
   var04T4 : BOOL ;
   c_takePreSeOrdT4 : BOOL ;    //Command: Take over pre select order via MPI
   c_preSeLockT4 : BOOL ;   //Command: Preselection lock activating
   c_lifeT4 : BOOL ;    //Life-Flag
   var051T4 : BYTE ;
   var052T4 : BYTE ;
   a_cmdMirrorT4 : DINT ;   //Command mirror (bit 0 ..31)
   var052aT4 : BOOL ;
   var052bT4 : BOOL ;
   var052cT4 : BOOL ;
   var052dT4 : BOOL ;
   var052eT4 : BOOL ;
   var052fT4 : BOOL ;
   var052gT4 : BOOL ;
   var052hT4 : BOOL ;
   f_simulLockT4 : BOOL ;   //Feedback: Simultaneous lock
   f_preSeLockT4 : BOOL ;   //Feedback: Preselection lock activating
   var052iT4 : BOOL ;
   f_busy_GsetT4 : BOOL ;   //Feedback: Preselection lock request not possible in the moment
   var053aT4 : BOOL ;
   var053bT4 : BOOL ;
   var053cT4 : BOOL ;
   var053dT4 : BOOL ;
   var053eT4 : BOOL ;
   var053fT4 : BOOL ;
   var053gT4 : BOOL ;
   var055T4 : BOOL ;
   var053hT4 : BOOL ;
   c_lockShtdwnT4 : BOOL ;  //Command: no stop in case of underload (=1)
   c_takeLckShtdnT4 : BOOL ;    //Command: take over command 'no stop in case of underload'
   var053iT4 : BOOL ;
   c_LckCtrlT4 : BOOL ; //Command: Lock controller (load & frequency) -TIE BREAKER ONLY -
   c_takeLckCtrlT4 : BOOL ; //Command: take over 'Lock controller' -TIE BREAKER ONLY-
   f_tieBrkOnT4 : BOOL ;    //Feedback: tie breaker on -TIE BREAKER ONLY-
   f_tieBrkTripT4 : BOOL ;  //Feedback: tie breaker tripped -TIE BREAKER ONLY-
   var056aT4 : BOOL ;
   f_2ndTieBrkOnT4 : BOOL ; //Feedback: 2nd tie breaker on -TIE BREAKER ONLY-
   f_2ndTieBrkTripT4 : BOOL ;   //Feedback: 2nd tie breaker tripped -TIE BREAKER ONLY-
   var056dT4 : BOOL ;
   a_loadT4 : INT ; // Actual value: Active power
   s_ordSq1_8T4 : DINT ;    //setpoint: Start stop sequence of the actual configuration - (Gen.1 -8) -
   s_ordSq9_15T4 : DINT ;   // Setpoint: Start stop sequence of the actual configuration - (Gen.9 -15) -
   var131T4 : BYTE ;
   var14T4 : BYTE ;
   var15T4 : BYTE ;
   var16T4 : BYTE ;
   var19T4 : INT ;
   var20T4 : INT ;
  END_STRUCT ;
BEGIN
   c_reqStrt := FALSE;
   c_req2Strt := FALSE;
   c_reqEStrt := FALSE;
   c_req2EStrt := FALSE;
   c_genBrkOpn := FALSE;
   var01 := FALSE;
   var02 := FALSE;
   var03 := FALSE;
   c_unitLock := FALSE;
   c_simulLock := FALSE;
   c_uncUBLoff := FALSE;
   c_shoreMode := FALSE;
   var04 := FALSE;
   c_takePreSeOrd := FALSE;
   c_preSeLock := FALSE;
   c_life := FALSE;
   var051 := B#16#0;
   var052 := B#16#0;
   a_cmdMirror := L#0;
   var052a := FALSE;
   var052b := FALSE;
   var052c := FALSE;
   var052d := FALSE;
   var052e := FALSE;
   var052f := FALSE;
   var052g := FALSE;
   var052h := FALSE;
   f_simulLock := FALSE;
   f_preSeLock := FALSE;
   var052i := FALSE;
   f_busy_Gset := FALSE;
   var053a := FALSE;
   var053b := FALSE;
   var053c := FALSE;
   var053d := FALSE;
   var053e := FALSE;
   var053f := FALSE;
   var054g := FALSE;
   var055 := FALSE;
   var055a := FALSE;
   c_lockShtdwn := FALSE;
   c_takeLckShtdn := FALSE;
   var055b := FALSE;
   c_LckCtrl := FALSE;
   c_takeLckCtrl := FALSE;
   f_tieBrkOn := FALSE;
   f_tieBrkTrip := FALSE;
   var056a := FALSE;
   f_2ndTieBrkOn := FALSE;
   f_2ndTieBrkTrip := FALSE;
   var056d := FALSE;
   a_load := 0;
   s_ordSq1_8 := L#0;
   s_ordSq9_15 := L#0;
   var131 := B#16#0;
   var14 := B#16#0;
   var15 := B#16#0;
   var16 := B#16#0;
   var17 := 0;
   var18 := 0;
   c_reqStrtT4 := FALSE;
   c_req2StrtT4 := FALSE;
   c_reqEStrtT4 := FALSE;
   c_req2EStrtT4 := FALSE;
   c_genBrkOpnT4 := FALSE;
   var01T4 := FALSE;
   var02T4 := FALSE;
   var03T4 := FALSE;
   c_unitLockT4 := FALSE;
   c_simulLockT4 := FALSE;
   c_uncUBLoffT4 := FALSE;
   c_shoreModeT4 := FALSE;
   var04T4 := FALSE;
   c_takePreSeOrdT4 := FALSE;
   c_preSeLockT4 := FALSE;
   c_lifeT4 := FALSE;
   var051T4 := B#16#0;
   var052T4 := B#16#0;
   a_cmdMirrorT4 := L#0;
   var052aT4 := FALSE;
   var052bT4 := FALSE;
   var052cT4 := FALSE;
   var052dT4 := FALSE;
   var052eT4 := FALSE;
   var052fT4 := FALSE;
   var052gT4 := FALSE;
   var052hT4 := FALSE;
   f_simulLockT4 := FALSE;
   f_preSeLockT4 := FALSE;
   var052iT4 := FALSE;
   f_busy_GsetT4 := FALSE;
   var053aT4 := FALSE;
   var053bT4 := FALSE;
   var053cT4 := FALSE;
   var053dT4 := FALSE;
   var053eT4 := FALSE;
   var053fT4 := FALSE;
   var053gT4 := FALSE;
   var055T4 := FALSE;
   var053hT4 := FALSE;
   c_lockShtdwnT4 := FALSE;
   c_takeLckShtdnT4 := FALSE;
   var053iT4 := FALSE;
   c_LckCtrlT4 := FALSE;
   c_takeLckCtrlT4 := FALSE;
   f_tieBrkOnT4 := FALSE;
   f_tieBrkTripT4 := FALSE;
   var056aT4 := FALSE;
   f_2ndTieBrkOnT4 := FALSE;
   f_2ndTieBrkTripT4 := FALSE;
   var056dT4 := FALSE;
   a_loadT4 := 0;
   s_ordSq1_8T4 := L#0;
   s_ordSq9_15T4 := L#0;
   var131T4 := B#16#0;
   var14T4 := B#16#0;
   var15T4 := B#16#0;
   var16T4 := B#16#0;
   var19T4 := 0;
   var20T4 := 0;
END_DATA_BLOCK



DATA_BLOCK "I_Gen1SR"
TITLE =Interface generator set 1. The 1. part contains the send
//area, the 2.part the receive area.                                                !
//
// I_Gen1SR
// Sende-/Empfangsfach MPI Generator 1
// Der Datenaustausch von oder zum Generator 1 erfolgt über diesen DB. Das Sendefach liegt im
// ersten Teil, das Empfangsteil liegt im zweiten Teil.
//
// Dieser DB ist für den TYP GENERATOR.
//
//
//  Siemens AG ATD IS3T, Kahle +494028892022, jens.kahle@hbg.siemens.de
//  PMA71
//  = Sende-/Empfangsfach MPI Generator 1
//  Datum aktuelle Version: 04.03.99
//  Version, Änd-Datum, Bearbeiter, geänderte Variablen
//  01.01,   31.01.99,  Kahle,      erste Version
//  01.02,   10.03.99,  Kahle,      Start/StoppReihenfolge,Kommando-
//                                  Spiegel, binäre Signale umsortieren
//
//KNOW_HOW_PROTECT
// (If specified, no more changes can be made once the block is generated)
//UNLINKED
// (If specified, the generated block is only available in the PLC load
//  memory)
//READ_ONLY
// (If specified, the generated block cannot be changed in the programmable
//  controller)
AUTHOR : Kahle
FAMILY : PMA71
NAME : I_Gen1SR
VERSION : 1.3


  STRUCT    // SENDEFACH
   c_reqStrt : BOOL ;   //Command: Request next generator set
   c_req2Strt : BOOL ;  //Command: Request second generator set
   c_reqEStrt : BOOL ;  //Command: Emergency request next generator set
   c_req2EStrt : BOOL ; //Command: Emergency request second generator set
   c_genBrkOpn : BOOL ; //Command: Generator breaker open by protection
   var01 : BOOL ;
   var02 : BOOL ;
   var03 : BOOL ;
   c_unitLock : BOOL ;  //Command: Block generator set
   c_simulLock : BOOL ; //Command: Simultaneous lock activating
   c_uncUBLoff : BOOL ; //Command: force UBL mode off
   c_shoreMode : BOOL ; //Command: Shore connection mode activating
   var04 : BOOL ;
   c_takePreSeOrd : BOOL ;  //Command: Take over pre select order via MPI
   c_preSeLock : BOOL ; //Command: Preselection lock activating
   c_life : BOOL ;  //Life-Flag
   var051 : BYTE ;
   var052 : BYTE ;
   a_cmdMirror : DINT ; //Command mirror (bit 0 ..31)
   f_auto : BOOL ;  //Feedback: Generator set in automatic
   f_rdyStandby : BOOL ;    //Feedback: Generator set ready for standby
   f_brk_clse : BOOL ;  //Feedback: Generator breaker closed
   f_onbus : BOOL ; //Feedback: Generator set on busbar in automatic
   f_lock : BOOL ;  //Feedback: Generator set blocked
   f_stp : BOOL ;   //Feedback: Diesel is stopped
   f_blackout : BOOL ;  //Feedback: blackout
   f_SGonbus : BOOL ;   //Feedback: This generator is as a SG on bus
   f_simulLock : BOOL ; //Feedback: Simultaneous lock
   f_preSeLock : BOOL ; //Feedback: Preselection lock activating
   f_i_SC : BOOL ;  //Feedback: generator breaker was opened becauce of short curcuit
   f_busy_Gset : BOOL ; //Feedback: Preselection lock request not possible in the moment
   var053a : BOOL ;
   f_shoreMode : BOOL ; //Feedback: Shore connection mode is activated
   f_rdy_swtchOn : BOOL ;   //Feedback: Generator set ready for switch on
   f_shore_act : BOOL ; //Feedback: Shore connection is activing (one or more)
   f_LCtrlLock : BOOL ; //Feedback: Load controller is locked
   f_FCtrlLock : BOOL ; //Feedback: Frequency controller is locked
   f_UBLmax_act : BOOL ;    //Feedback: UBLmax is active
   var055 : BOOL ;
   f_UBL_MinLock : BOOL ;   //Command: UBL mode lock because of minimum load
   c_lockShtdwn : BOOL ;    //Command: no stop in case of underload (=1)
   c_takeLckShtdn : BOOL ;  //Command: take over command 'no stop in case of underload'
   c_AllTieBrkOn : BOOL ;   //Feedback: tie breaker on
   c_LckCtrl : BOOL ;   //Command: Lock controller (load & frequency) -TIE BREAKER ONLY-
   c_takeLckCtrl : BOOL ;   //Command: take over 'Lock controller' -TIE BREAKER ONLY-
   f_tieBrkOn : BOOL ;  //Feedback: tie breaker on -TIE BREAKER ONLY-
   f_tieBrkTrip : BOOL ;    //Feedback: tie breaker tripped -TIE BREAKER ONLY-
   var056a : BOOL ;
   var056b : BOOL ;
   var056c : BOOL ;
   var056d : BOOL ;
   a_load : INT ;   // Actual value: Active power
   s_ordSq1_8 : DINT ;  //setpoint: Start stop sequence of the actual configuration - (Gen.1 -8) -
   s_ordSq9_15 : DINT ; //Setpoint: Start stop sequence of the actual configuration - (Gen.9 -15) -
   var131 : BYTE ;
   var14 : BYTE ;
   var15 : BYTE ;
   var16 : BYTE ;
   var17 : INT ;
   var18 : INT ;    // EMPFANGSFACH
   c_reqStrtG1 : BOOL ; //Command: Request next generator set
   c_req2StrtG1 : BOOL ;    //Command: Request second generator set
   c_reqEStrtG1 : BOOL ;    //Command: Emergency request next generator set
   c_req2EStrtG1 : BOOL ;   //Command: Emergency request second generator set
   c_genBrkOpnG1 : BOOL ;   //Command: Generator breaker open by protection
   var01G1 : BOOL ;
   var02G1 : BOOL ;
   var03G1 : BOOL ;
   c_unitLockG1 : BOOL ;    //Command: Block generator set
   c_simulLockG1 : BOOL ;   //Command: Simultaneous lock activating
   c_uncUBLoffG1 : BOOL ;   //Command: force UBL mode off
   c_shoreModeG1 : BOOL ;   //Command: Shore connection mode activating
   var04G1 : BOOL ;
   c_takePreSeOrdG1 : BOOL ;    //Command: Take over pre select order via MPI
   c_preSeLockG1 : BOOL ;   //Command: Preselection lock activating
   c_lifeG1 : BOOL ;    //Life-Flag
   var051G1 : BYTE ;
   var052G1 : BYTE ;
   a_cmdMirrorG1 : DINT ;   //Command mirror (bit 0 ..31)
   f_autoG1 : BOOL ;    //Feedback: Generator set in automatic
   f_rdyStdbyG1 : BOOL ;    //Feedback: Generator set ready for standby
   f_brk_clseG1 : BOOL ;    //Feedback: Generator breaker closed
   f_onbusG1 : BOOL ;   //Feedback: Generator set on busbar in automatic
   f_lockG1 : BOOL ;    //Feedback: Generator set blocked
   f_stpG1 : BOOL ; //Feedback: Diesel is stopped
   f_blackoutG1 : BOOL ;    //Feedback: blackout
   f_SGonbusG1 : BOOL ; //Feedback: Generator is as a SG on bus
   f_simulLockG1 : BOOL ;   //Feedback: Simultaneous lock
   f_preSeLockG1 : BOOL ;   //Feedback: Preselection lock activating
   f_i_SC_G1 : BOOL ;   //Feedback: generator breaker was opened becauce of short curcuit
   f_busy_GsetG1 : BOOL ;   //Feedback: Preselection lock request not possible in the moment
   var053aG1 : BOOL ;
   f_shoreModeG1 : BOOL ;   //Feedback: Shore connection mode is activated
   f_rdy_swtchOnG1 : BOOL ; //Feedback: Generator set ready for switch on
   f_shore_actG1 : BOOL ;   //Feedback: Shore connection is activing (one or more)
   f_LCtrlLockG1 : BOOL ;   //Feedback: Load controller is locked
   f_FCtrlLockG1 : BOOL ;   //Feedback: Frequency controller is locked
   f_UBLmax_actG1 : BOOL ;  //Feedback: UBLmax is active
   var055G1 : BOOL ;
   f_UBL_MinLockG1 : BOOL ; //Command: UBL mode lock because of minimum load
   c_lockShtdwnG1 : BOOL ;  //Command: no stop in case of underload (=1)
   c_takeLckShtdnG1 : BOOL ;    //Command: take over command 'no stop in case of underload'
   c_AllTieBrkOnG1 : BOOL ; //Feedback: tie breaker on
   c_LckCtrlG1 : BOOL ; //Command: Lock controller (load & frequency)
   c_takeLckCtrlG1 : BOOL ; //Command: take over 'Lock controller'
   f_tieBrkOnG1 : BOOL ;    //Feedback: tie breaker on
   f_tieBrkTripG1 : BOOL ;  //Feedback: tie breaker tripped
   var056aG1 : BOOL ;
   var056bG1 : BOOL ;
   var056cG1 : BOOL ;
   var056dG1 : BOOL ;
   a_loadG1 : INT ; // Actual value: Active power
   s_ordSq1_8G1 : DINT ;    //setpoint: Start stop sequence of the actual configuration - (Gen.1 -8) -
   s_ordSq9_15G1 : DINT ;   // Setpoint: Start stop sequence of the actual configuration - (Gen.9 -15) -
   var131G1 : BYTE ;
   var14G1 : BYTE ;
   var15G1 : BYTE ;
   var16G1 : BYTE ;
   var19G1 : INT ;
   var20G1 : INT ;
  END_STRUCT ;
BEGIN
   c_reqStrt := FALSE;
   c_req2Strt := FALSE;
   c_reqEStrt := FALSE;
   c_req2EStrt := FALSE;
   c_genBrkOpn := FALSE;
   var01 := FALSE;
   var02 := FALSE;
   var03 := FALSE;
   c_unitLock := FALSE;
   c_simulLock := FALSE;
   c_uncUBLoff := FALSE;
   c_shoreMode := FALSE;
   var04 := FALSE;
   c_takePreSeOrd := FALSE;
   c_preSeLock := FALSE;
   c_life := FALSE;
   var051 := B#16#0;
   var052 := B#16#0;
   a_cmdMirror := L#0;
   f_auto := FALSE;
   f_rdyStandby := FALSE;
   f_brk_clse := FALSE;
   f_onbus := FALSE;
   f_lock := FALSE;
   f_stp := FALSE;
   f_blackout := FALSE;
   f_SGonbus := FALSE;
   f_simulLock := FALSE;
   f_preSeLock := FALSE;
   f_i_SC := FALSE;
   f_busy_Gset := FALSE;
   var053a := FALSE;
   f_shoreMode := FALSE;
   f_rdy_swtchOn := FALSE;
   f_shore_act := FALSE;
   f_LCtrlLock := FALSE;
   f_FCtrlLock := FALSE;
   f_UBLmax_act := FALSE;
   var055 := FALSE;
   f_UBL_MinLock := FALSE;
   c_lockShtdwn := FALSE;
   c_takeLckShtdn := FALSE;
   c_AllTieBrkOn := FALSE;
   c_LckCtrl := FALSE;
   c_takeLckCtrl := FALSE;
   f_tieBrkOn := FALSE;
   f_tieBrkTrip := FALSE;
   var056a := FALSE;
   var056b := FALSE;
   var056c := FALSE;
   var056d := FALSE;
   a_load := 0;
   s_ordSq1_8 := L#0;
   s_ordSq9_15 := L#0;
   var131 := B#16#0;
   var14 := B#16#0;
   var15 := B#16#0;
   var16 := B#16#0;
   var17 := 0;
   var18 := 0;
   c_reqStrtG1 := FALSE;
   c_req2StrtG1 := FALSE;
   c_reqEStrtG1 := FALSE;
   c_req2EStrtG1 := FALSE;
   c_genBrkOpnG1 := FALSE;
   var01G1 := FALSE;
   var02G1 := FALSE;
   var03G1 := FALSE;
   c_unitLockG1 := FALSE;
   c_simulLockG1 := FALSE;
   c_uncUBLoffG1 := FALSE;
   c_shoreModeG1 := FALSE;
   var04G1 := FALSE;
   c_takePreSeOrdG1 := FALSE;
   c_preSeLockG1 := FALSE;
   c_lifeG1 := FALSE;
   var051G1 := B#16#0;
   var052G1 := B#16#0;
   a_cmdMirrorG1 := L#0;
   f_autoG1 := FALSE;
   f_rdyStdbyG1 := FALSE;
   f_brk_clseG1 := FALSE;
   f_onbusG1 := FALSE;
   f_lockG1 := FALSE;
   f_stpG1 := FALSE;
   f_blackoutG1 := FALSE;
   f_SGonbusG1 := FALSE;
   f_simulLockG1 := FALSE;
   f_preSeLockG1 := FALSE;
   f_i_SC_G1 := FALSE;
   f_busy_GsetG1 := FALSE;
   var053aG1 := FALSE;
   f_shoreModeG1 := FALSE;
   f_rdy_swtchOnG1 := FALSE;
   f_shore_actG1 := FALSE;
   f_LCtrlLockG1 := FALSE;
   f_FCtrlLockG1 := FALSE;
   f_UBLmax_actG1 := FALSE;
   var055G1 := FALSE;
   f_UBL_MinLockG1 := FALSE;
   c_lockShtdwnG1 := FALSE;
   c_takeLckShtdnG1 := FALSE;
   c_AllTieBrkOnG1 := FALSE;
   c_LckCtrlG1 := FALSE;
   c_takeLckCtrlG1 := FALSE;
   f_tieBrkOnG1 := FALSE;
   f_tieBrkTripG1 := FALSE;
   var056aG1 := FALSE;
   var056bG1 := FALSE;
   var056cG1 := FALSE;
   var056dG1 := FALSE;
   a_loadG1 := 0;
   s_ordSq1_8G1 := L#0;
   s_ordSq9_15G1 := L#0;
   var131G1 := B#16#0;
   var14G1 := B#16#0;
   var15G1 := B#16#0;
   var16G1 := B#16#0;
   var19G1 := 0;
   var20G1 := 0;
END_DATA_BLOCK


DATA_BLOCK "I_Gen2SR"
TITLE =Interface generator set 2. The 1. part contains the send
//area, the 2.part the receive area.                                                !
//
// I_Gen2SR
// Sende-/Empfangsfach MPI Generator 2
// Der Datenaustausch von oder zum Generator 2 erfolgt über diesen DB. Das Sendefach liegt im
// ersten Teil, das Empfangsteil liegt im zweiten Teil.
//
// Dieser DB ist für den TYP GENERATOR.
//
//
//  Siemens AG ATD IS3T, Kahle +494028892022, jens.kahle@hbg.siemens.de
//  PMA71
//  = Sende-/Empfangsfach MPI Generator 1
//  Datum aktuelle Version: 04.03.99
//  Version, Änd-Datum, Bearbeiter, geänderte Variablen
//  01.01,   31.01.99,  Kahle,      erste Version
//  01.02,   10.03.99,  Kahle,      Start/StoppReihenfolge,Kommando-
//                                  Spiegel, binäre Signale umsortieren
//
//KNOW_HOW_PROTECT
// (If specified, no more changes can be made once the block is generated)
//UNLINKED
// (If specified, the generated block is only available in the PLC load
//  memory)
//READ_ONLY
// (If specified, the generated block cannot be changed in the programmable
//  controller)
AUTHOR : Kahle
FAMILY : PMA71
NAME : I_Gen2SR
VERSION : 1.3


  STRUCT    // SENDEFACH
   c_reqStrt : BOOL ;   //Command: Request next generator set
   c_req2Strt : BOOL ;  //Command: Request second generator set
   c_reqEStrt : BOOL ;  //Command: Emergency request next generator set
   c_req2EStrt : BOOL ; //Command: Emergency request second generator set
   c_genBrkOpn : BOOL ; //Command: Generator breaker open by protection
   var01 : BOOL ;
   var02 : BOOL ;
   var03 : BOOL ;
   c_unitLock : BOOL ;  //Command: Block generator set
   c_simulLock : BOOL ; //Command: Simultaneous lock activating
   c_uncUBLoff : BOOL ; //Command: force UBL mode off
   c_shoreMode : BOOL ; //Command: Shore connection mode activating
   var04 : BOOL ;
   c_takePreSeOrd : BOOL ;  //Command: Take over pre select order via MPI
   c_preSeLock : BOOL ; //Command: Preselection lock activating
   c_life : BOOL ;  //Life-Flag
   var051 : BYTE ;
   var052 : BYTE ;
   a_cmdMirror : DINT ; //Command mirror (bit 0 ..31)
   f_auto : BOOL ;  //Feedback: Generator set in automatic
   f_rdyStandby : BOOL ;    //Feedback: Generator set ready for standby
   f_brk_clse : BOOL ;  //Feedback: Generator breaker closed
   f_onbus : BOOL ; //Feedback: Generator set on busbar in automatic
   f_lock : BOOL ;  //Feedback: Generator set blocked
   f_stp : BOOL ;   //Feedback: Diesel is stopped
   f_blackout : BOOL ;  //Feedback: blackout
   f_SGonbus : BOOL ;   //Feedback: This generator is as a SG on bus
   f_simulLock : BOOL ; //Feedback: Simultaneous lock
   f_preSeLock : BOOL ; //Feedback: Preselection lock activating
   f_i_SC : BOOL ;  //Feedback: generator breaker was opened becauce of short curcuit
   f_busy_Gset : BOOL ; //Feedback: Preselection lock request not possible in the moment
   var053a : BOOL ;
   f_shoreMode : BOOL ; //Feedback: Shore connection mode is activated
   f_rdy_swtchOn : BOOL ;   //Feedback: Generator set ready for switch on
   f_shore_act : BOOL ; //Feedback: Shore connection is activing (one or more)
   f_LCtrlLock : BOOL ; //Feedback: Load controller is locked
   f_FCtrlLock : BOOL ; //Feedback: Frequency controller is locked
   f_UBLmax_act : BOOL ;    //Feedback: UBLmax is active
   var055 : BOOL ;
   f_UBL_MinLock : BOOL ;   //Command: UBL mode lock because of minimum load
   c_lockShtdwn : BOOL ;    //Command: no stop in case of underload (=1)
   c_takeLckShtdn : BOOL ;  //Command: take over command 'no stop in case of underload'
   c_AllTieBrkOn : BOOL ;   //Feedback: tie breaker on
   c_LckCtrl : BOOL ;   //Command: Lock controller (load & frequency) -TIE BREAKER ONLY-
   c_takeLckCtrl : BOOL ;   //Command: take over 'Lock controller' -TIE BREAKER ONLY-
   f_tieBrkOn : BOOL ;  //Feedback: tie breaker on -TIE BREAKER ONLY-
   f_tieBrkTrip : BOOL ;    //Feedback: tie breaker tripped -TIE BREAKER ONLY-
   var056a : BOOL ;
   var056b : BOOL ;
   var056c : BOOL ;
   var056d : BOOL ;
   a_load : INT ;   // Actual value: Active power
   s_ordSq1_8 : DINT ;  //setpoint: Start stop sequence of the actual configuration - (Gen.1 -8) -
   s_ordSq9_15 : DINT ; //Setpoint: Start stop sequence of the actual configuration - (Gen.9 -15) -
   var131 : BYTE ;
   var14 : BYTE ;
   var15 : BYTE ;
   var16 : BYTE ;
   var17 : INT ;
   var18 : INT ;    // EMPFANGSFACH
   c_reqStrtG2 : BOOL ; //Command: Request next generator set
   c_req2StrtG2 : BOOL ;    //Command: Request second generator set
   c_reqEStrtG2 : BOOL ;    //Command: Emergency request next generator set
   c_req2EStrtG2 : BOOL ;   //Command: Emergency request second generator set
   c_genBrkOpnG2 : BOOL ;   //Command: Generator breaker open by protection
   var01G2 : BOOL ;
   var02G2 : BOOL ;
   var03G2 : BOOL ;
   c_unitLockG2 : BOOL ;    //Command: Block generator set
   c_simulLockG2 : BOOL ;   //Command: Simultaneous lock activating
   c_uncUBLoffG2 : BOOL ;   //Command: force UBL mode off
   c_shoreModeG2 : BOOL ;   //Command: Shore connection mode activating
   var04G2 : BOOL ;
   c_takePreSeOrdG2 : BOOL ;    //Command: Take over pre select order via MPI
   c_preSeLockG2 : BOOL ;    //Command: Preselection lock activating
   c_lifeG2 : BOOL ;    //Life-Flag
   var051G2 : BYTE ;
   var052G2 : BYTE ;
   a_cmdMirrorG2 : DINT ;   //Command mirror (bit 0 ..31)
   f_autoG2 : BOOL ;    //Feedback: Generator set in automatic
   f_rdyStdbyG2 : BOOL ;    //Feedback: Generator set ready for standby
   f_brk_clseG2 : BOOL ;    //Feedback: Generator breaker closed
   f_onbusG2 : BOOL ;   //Feedback: Generator set on busbar in automatic
   f_lockG2 : BOOL ;    //Feedback: Generator set blocked
   f_stpG2 : BOOL ; //Feedback: Diesel is stopped
   f_blackoutG2 : BOOL ;    //Feedback: blackout
   f_SGonbusG2 : BOOL ; //Feedback: Generator is as a SG on bus
   f_simulLockG2 : BOOL ;   //Feedback: Simultaneous lock
   f_preSeLockG2 : BOOL ;   //Feedback: Preselection lock activating
   f_i_SC_G2 : BOOL ;   //Feedback: generator breaker was opened becauce of short curcuit
   f_busy_GsetG2 : BOOL ;   //Feedback: Preselection lock request not possible in the moment
   var053aG2 : BOOL ;
   f_shoreModeG2 : BOOL ; //Feedback: Shore connection mode is activated
   f_rdy_swtchOnG2 : BOOL ; //Feedback: Generator set ready for switch on
   f_shore_actG2 : BOOL ;   //Feedback: Shore connection is activing (one or more)
   f_LCtrlLockG2 : BOOL ;   //Feedback: Load controller is locked
   f_FCtrlLockG2 : BOOL ;   //Feedback: Frequency controller is locked
   f_UBLmax_actG2 : BOOL ;  //Feedback: UBLmax is active
   var055G2 : BOOL ;
   f_UBL_MinLockG2 : BOOL ; //Command: UBL mode lock because of minimum load
   c_lockShtdwnG2 : BOOL ;  //Command: no stop in case of underload (=1)
   c_takeLckShtdnG2 : BOOL ;    //Command: take over command 'no stop in case of underload'
   c_AllTieBrkOnG2 : BOOL ; //Feedback: tie breaker on
   c_LckCtrlG2 : BOOL ; //Command: Lock controller (load & frequency)
   c_takeLckCtrlG2 : BOOL ; //Command: take over 'Lock controller'
   f_tieBrkOnG2 : BOOL ;    //Feedback: tie breaker on
   f_tieBrkTripG2 : BOOL ;  //Feedback: tie breaker tripped
   var056aG2 : BOOL ;
   var056bG2 : BOOL ;
   var056cG2 : BOOL ;
   var056dG2 : BOOL ;
   a_loadG2 : INT ; // Actual value: Active power
   s_ordSq1_8G2 : DINT ;    //setpoint: Start stop sequence of the actual configuration - (Gen.1 -8) -
   s_ordSq9_15G2 : DINT ;   // Setpoint: Start stop sequence of the actual configuration - (Gen.9 -15) -
   var131G2 : BYTE ;
   var14G2 : BYTE ;
   var15G2 : BYTE ;
   var16G2 : BYTE ;
   var19G2 : INT ;
   var20G2 : INT ;
  END_STRUCT ;
BEGIN
   c_reqStrt := FALSE;
   c_req2Strt := FALSE;
   c_reqEStrt := FALSE;
   c_req2EStrt := FALSE;
   c_genBrkOpn := FALSE;
   var01 := FALSE;
   var02 := FALSE;
   var03 := FALSE;
   c_unitLock := FALSE;
   c_simulLock := FALSE;
   c_uncUBLoff := FALSE;
   c_shoreMode := FALSE;
   var04 := FALSE;
   c_takePreSeOrd := FALSE;
   c_preSeLock := FALSE;
   c_life := FALSE;
   var051 := B#16#0;
   var052 := B#16#0;
   a_cmdMirror := L#0;
   f_auto := FALSE;
   f_rdyStandby := FALSE;
   f_brk_clse := FALSE;
   f_onbus := FALSE;
   f_lock := FALSE;
   f_stp := FALSE;
   f_blackout := FALSE;
   f_SGonbus := FALSE;
   f_simulLock := FALSE;
   f_preSeLock := FALSE;
   f_i_SC := FALSE;
   f_busy_Gset := FALSE;
   var053a := FALSE;
   f_shoreMode := FALSE;
   f_rdy_swtchOn := FALSE;
   f_shore_act := FALSE;
   f_LCtrlLock := FALSE;
   f_FCtrlLock := FALSE;
   f_UBLmax_act := FALSE;
   var055 := FALSE;
   f_UBL_MinLock := FALSE;
   c_lockShtdwn := FALSE;
   c_takeLckShtdn := FALSE;
   c_AllTieBrkOn := FALSE;
   c_LckCtrl := FALSE;
   c_takeLckCtrl := FALSE;
   f_tieBrkOn := FALSE;
   f_tieBrkTrip := FALSE;
   var056a := FALSE;
   var056b := FALSE;
   var056c := FALSE;
   var056d := FALSE;
   a_load := 0;
   s_ordSq1_8 := L#0;
   s_ordSq9_15 := L#0;
   var131 := B#16#0;
   var14 := B#16#0;
   var15 := B#16#0;
   var16 := B#16#0;
   var17 := 0;
   var18 := 0;
   c_reqStrtG2 := FALSE;
   c_req2StrtG2 := FALSE;
   c_reqEStrtG2 := FALSE;
   c_req2EStrtG2 := FALSE;
   c_genBrkOpnG2 := FALSE;
   var01G2 := FALSE;
   var02G2 := FALSE;
   var03G2 := FALSE;
   c_unitLockG2 := FALSE;
   c_simulLockG2 := FALSE;
   c_uncUBLoffG2 := FALSE;
   c_shoreModeG2 := FALSE;
   var04G2 := FALSE;
   c_takePreSeOrdG2 := FALSE;
   c_preSeLockG2 := FALSE;
   c_lifeG2 := FALSE;
   var051G2 := B#16#0;
   var052G2 := B#16#0;
   a_cmdMirrorG2 := L#0;
   f_autoG2 := FALSE;
   f_rdyStdbyG2 := FALSE;
   f_brk_clseG2 := FALSE;
   f_onbusG2 := FALSE;
   f_lockG2 := FALSE;
   f_stpG2 := FALSE;
   f_blackoutG2 := FALSE;
   f_SGonbusG2 := FALSE;
   f_simulLockG2 := FALSE;
   f_preSeLockG2 := FALSE;
   f_i_SC_G2 := FALSE;
   f_busy_GsetG2 := FALSE;
   var053aG2 := FALSE;
   f_shoreModeG2 := FALSE;
   f_rdy_swtchOnG2 := FALSE;
   f_shore_actG2 := FALSE;
   f_LCtrlLockG2 := FALSE;
   f_FCtrlLockG2 := FALSE;
   f_UBLmax_actG2 := FALSE;
   var055G2 := FALSE;
   f_UBL_MinLockG2 := FALSE;
   c_lockShtdwnG2 := FALSE;
   c_takeLckShtdnG2 := FALSE;
   c_AllTieBrkOnG2 := FALSE;
   c_LckCtrlG2 := FALSE;
   c_takeLckCtrlG2 := FALSE;
   f_tieBrkOnG2 := FALSE;
   f_tieBrkTripG2 := FALSE;
   var056aG2 := FALSE;
   var056bG2 := FALSE;
   var056cG2 := FALSE;
   var056dG2 := FALSE;
   a_loadG2 := 0;
   s_ordSq1_8G2 := L#0;
   s_ordSq9_15G2 := L#0;
   var131G2 := B#16#0;
   var14G2 := B#16#0;
   var15G2 := B#16#0;
   var16G2 := B#16#0;
   var19G2 := 0;
   var20G2 := 0;
END_DATA_BLOCK


DATA_BLOCK "I_Gen3SR"
TITLE =Interface generator set 3. The 1. part contains the send
//area, the 2.part the receive area.                                                !
//
// I_Gen3SR
// Sende-/Empfangsfach MPI Generator 3
// Der Datenaustausch von oder zum Generator 1 erfolgt über diesen DB. Das Sendefach liegt im
// ersten Teil, das Empfangsteil liegt im zweiten Teil.
//
// Dieser DB ist für den TYP GENERATOR.
//
//
//  Siemens AG ATD IS3T, Kahle +494028892022, jens.kahle@hbg.siemens.de
//  PMA71
//  = Sende-/Empfangsfach MPI Generator 1
//  Datum aktuelle Version: 04.03.99
//  Version, Änd-Datum, Bearbeiter, geänderte Variablen
//  01.01,   31.01.99,  Kahle,      erste Version
//  01.02,   10.03.99,  Kahle,      Start/StoppReihenfolge,Kommando-
//                                  Spiegel, binäre Signale umsortieren
//
//KNOW_HOW_PROTECT
// (If specified, no more changes can be made once the block is generated)
//UNLINKED
// (If specified, the generated block is only available in the PLC load
//  memory)
//READ_ONLY
// (If specified, the generated block cannot be changed in the programmable
//  controller)
AUTHOR : Kahle
FAMILY : PMA71
NAME : I_Gen3SR
VERSION : 1.3


  STRUCT    // SENDEFACH
   c_reqStrt : BOOL ;   //Command: Request next generator set
   c_req2Strt : BOOL ;  //Command: Request second generator set
   c_reqEStrt : BOOL ;  //Command: Emergency request next generator set
   c_req2EStrt : BOOL ; //Command: Emergency request second generator set
   c_genBrkOpn : BOOL ; //Command: Generator breaker open by protection
   var01 : BOOL ;
   var02 : BOOL ;
   var03 : BOOL ;
   c_unitLock : BOOL ;  //Command: Block generator set
   c_simulLock : BOOL ; //Command: Simultaneous lock activating
   c_uncUBLoff : BOOL ; //Command: force UBL mode off
   c_shoreMode : BOOL ; //Command: Shore connection mode activating
   var04 : BOOL ;
   c_takePreSeOrd : BOOL ;  //Command: Take over pre select order via MPI
   c_preSeLock : BOOL ; //Command: Preselection lock activating
   c_life : BOOL ;  //Life-Flag
   var051 : BYTE ;
   var052 : BYTE ;
   a_cmdMirror : DINT ; //Command mirror (bit 0 ..31)
   f_auto : BOOL ;  //Feedback: Generator set in automatic
   f_rdyStandby : BOOL ;    //Feedback: Generator set ready for standby
   f_brk_clse : BOOL ;  //Feedback: Generator breaker closed
   f_onbus : BOOL ; //Feedback: Generator set on busbar in automatic
   f_lock : BOOL ;  //Feedback: Generator set blocked
   f_stp : BOOL ;   //Feedback: Diesel is stopped
   f_blackout : BOOL ;  //Feedback: blackout
   f_SGonbus : BOOL ;   //Feedback: This generator is as a SG on bus
   f_simulLock : BOOL ; //Feedback: Simultaneous lock
   f_preSeLock : BOOL ; //Feedback: Preselection lock activating
   f_i_SC : BOOL ;  //Feedback: generator breaker was opened becauce of short curcuit
   f_busy_Gset : BOOL ; //Feedback: Preselection lock request not possible in the moment
   var053a : BOOL ;
   f_shoreMode : BOOL ; //Feedback: Shore connection mode is activated
   f_rdy_swtchOn : BOOL ;   //Feedback: Generator set ready for switch on
   f_shore_act : BOOL ; //Feedback: Shore connection is activing (one or more)
   f_LCtrlLock : BOOL ; //Feedback: Load controller is locked
   f_FCtrlLock : BOOL ; //Feedback: Frequency controller is locked
   f_UBLmax_act : BOOL ;    //Feedback: UBLmax is active
   var055 : BOOL ;
   f_UBL_MinLock : BOOL ;   //Command: UBL mode lock because of minimum load
   c_lockShtdwn : BOOL ;    //Command: no stop in case of underload (=1)
   c_takeLckShtdn : BOOL ;    //Command: take over command 'no stop in case of underload'
   c_AllTieBrkOn : BOOL ;   //Feedback: tie breaker on
   c_LckCtrl : BOOL ;   //Command: Lock controller (load & frequency) -TIE BREAKER ONLY-
   c_takeLckCtrl : BOOL ;   //Command: take over 'Lock controller' -TIE BREAKER ONLY-
   f_tieBrkOn : BOOL ;  //Feedback: tie breaker on -TIE BREAKER ONLY-
   f_tieBrkTrip : BOOL ;    //Feedback: tie breaker tripped -TIE BREAKER ONLY-
   var056a : BOOL ;
   var056b : BOOL ;
   var056c : BOOL ;
   var056d : BOOL ;
   a_load : INT ;   // Actual value: Active power
   s_ordSq1_8 : DINT ;  //setpoint: Start stop sequence of the actual configuration - (Gen.1 -8) -
   s_ordSq9_15 : DINT ; //Setpoint: Start stop sequence of the actual configuration - (Gen.9 -15) -
   var131 : BYTE ;
   var14 : BYTE ;
   var15 : BYTE ;
   var16 : BYTE ;
   var17 : INT ;
   var18 : INT ;    // EMPFANGSFACH
   c_reqStrtG3 : BOOL ; //Command: Request next generator set
   c_req2StrtG3 : BOOL ; //Command: Request second generator set
   c_reqEStrtG3 : BOOL ;    //Command: Emergency request next generator set
   c_req2EStrtG3 : BOOL ;   //Command: Emergency request second generator set
   c_genBrkOpnG3 : BOOL ;   //Command: Generator breaker open by protection
   var01G3 : BOOL ;
   var02G3 : BOOL ;
   var03G3 : BOOL ;
   c_unitLockG3 : BOOL ;    //Command: Block generator set
   c_simulLockG3 : BOOL ;   //Command: Simultaneous lock activating
   c_uncUBLoffG3 : BOOL ;   //Command: force UBL mode off
   c_shoreModeG3 : BOOL ;   //Command: Shore connection mode activating
   var04G3 : BOOL ;
   c_takePreSeOrdG3 : BOOL ;    //Command: Take over pre select order via MPI
   c_preSeLockG3 : BOOL ;   //Command: Preselection lock activating
   c_lifeG3 : BOOL ;    //Life-Flag
   var051G3 : BYTE ;
   var052G3 : BYTE ;
   a_cmdMirrorG3 : DINT ;   //Command mirror (bit 0 ..31)
   f_autoG3 : BOOL ;    //Feedback: Generator set in automatic
   f_rdyStdbyG3 : BOOL ;    //Feedback: Generator set ready for standby
   f_brk_clseG3 : BOOL ;   //Feedback: Generator breaker closed
   f_onbusG3 : BOOL ;   //Feedback: Generator set on busbar in automatic
   f_lockG3 : BOOL ;    //Feedback: Generator set blocked
   f_stpG3 : BOOL ; //Feedback: Diesel is stopped
   f_blackoutG3 : BOOL ;    //Feedback: blackout
   f_SGonbusG3 : BOOL ; //Feedback: Generator is as a SG on bus
   f_simulLockG3 : BOOL ;   //Feedback: Simultaneous lock
   f_preSeLockG3 : BOOL ;   //Feedback: Preselection lock activating
   f_i_SC_G3 : BOOL ;   //Feedback: generator breaker was opened becauce of short curcuit
   f_busy_GsetG3 : BOOL ;   //Feedback: Preselection lock request not possible in the moment
   var053aG3 : BOOL ;
   f_shoreModeG3 : BOOL ;   //Feedback: Shore connection mode is activated
   f_rdy_swtchOnG3 : BOOL ; //Feedback: Generator set ready for switch on
   f_shore_actG3 : BOOL ;   //Feedback: Shore connection is activing (one or more)
   f_LCtrlLockG3 : BOOL ;   //Feedback: Load controller is locked
   f_FCtrlLockG3 : BOOL ;   //Feedback: Frequency controller is locked
   f_UBLmax_actG3 : BOOL ;  //Feedback: UBLmax is active
   var055G3 : BOOL ;
   f_UBL_MinLockG3 : BOOL ; //Command: UBL mode lock because of minimum load
   c_lockShtdwnG3 : BOOL ;  //Command: no stop in case of underload (=1)
   c_takeLckShtdnG3 : BOOL ;    //Command: take over command 'no stop in case of underload'
   c_AllTieBrkOnG3 : BOOL ; //Feedback: tie breaker on
   c_LckCtrlG3 : BOOL ; //Command: Lock controller (load & frequency)
   c_takeLckCtrlG3 : BOOL ; //Command: take over 'Lock controller'
   f_tieBrkOnG3 : BOOL ;    //Feedback: tie breaker on
   f_tieBrkTripG3 : BOOL ;  //Feedback: tie breaker tripped
   var056aG3 : BOOL ;
   var056bG3 : BOOL ;
   var056cG3 : BOOL ;
   var056dG3 : BOOL ;
   a_loadG3 : INT ; // Actual value: Active power
   s_ordSq1_8G3 : DINT ;    //setpoint: Start stop sequence of the actual configuration - (Gen.1 -8) -
   s_ordSq9_15G3 : DINT ;   // Setpoint: Start stop sequence of the actual configuration - (Gen.9 -15) -
   var131G3 : BYTE ;
   var14G3 : BYTE ;
   var15G3 : BYTE ;
   var16G3 : BYTE ;
   var19G3 : INT ;
   var20G3 : INT ;
  END_STRUCT ;
BEGIN
   c_reqStrt := FALSE;
   c_req2Strt := FALSE;
   c_reqEStrt := FALSE;
   c_req2EStrt := FALSE;
   c_genBrkOpn := FALSE;
   var01 := FALSE;
   var02 := FALSE;
   var03 := FALSE;
   c_unitLock := FALSE;
   c_simulLock := FALSE;
   c_uncUBLoff := FALSE;
   c_shoreMode := FALSE;
   var04 := FALSE;
   c_takePreSeOrd := FALSE;
   c_preSeLock := FALSE;
   c_life := FALSE;
   var051 := B#16#0;
   var052 := B#16#0;
   a_cmdMirror := L#0;
   f_auto := FALSE;
   f_rdyStandby := FALSE;
   f_brk_clse := FALSE;
   f_onbus := FALSE;
   f_lock := FALSE;
   f_stp := FALSE;
   f_blackout := FALSE;
   f_SGonbus := FALSE;
   f_simulLock := FALSE;
   f_preSeLock := FALSE;
   f_i_SC := FALSE;
   f_busy_Gset := FALSE;
   var053a := FALSE;
   f_shoreMode := FALSE;
   f_rdy_swtchOn := FALSE;
   f_shore_act := FALSE;
   f_LCtrlLock := FALSE;
   f_FCtrlLock := FALSE;
   f_UBLmax_act := FALSE;
   var055 := FALSE;
   f_UBL_MinLock := FALSE;
   c_lockShtdwn := FALSE;
   c_takeLckShtdn := FALSE;
   c_AllTieBrkOn := FALSE;
   c_LckCtrl := FALSE;
   c_takeLckCtrl := FALSE;
   f_tieBrkOn := FALSE;
   f_tieBrkTrip := FALSE;
   var056a := FALSE;
   var056b := FALSE;
   var056c := FALSE;
   var056d := FALSE;
   a_load := 0;
   s_ordSq1_8 := L#0;
   s_ordSq9_15 := L#0;
   var131 := B#16#0;
   var14 := B#16#0;
   var15 := B#16#0;
   var16 := B#16#0;
   var17 := 0;
   var18 := 0;
   c_reqStrtG3 := FALSE;
   c_req2StrtG3 := FALSE;
   c_reqEStrtG3 := FALSE;
   c_req2EStrtG3 := FALSE;
   c_genBrkOpnG3 := FALSE;
   var01G3 := FALSE;
   var02G3 := FALSE;
   var03G3 := FALSE;
   c_unitLockG3 := FALSE;
   c_simulLockG3 := FALSE;
   c_uncUBLoffG3 := FALSE;
   c_shoreModeG3 := FALSE;
   var04G3 := FALSE;
   c_takePreSeOrdG3 := FALSE;
   c_preSeLockG3 := FALSE;
   c_lifeG3 := FALSE;
   var051G3 := B#16#0;
   var052G3 := B#16#0;
   a_cmdMirrorG3 := L#0;
   f_autoG3 := FALSE;
   f_rdyStdbyG3 := FALSE;
   f_brk_clseG3 := FALSE;
   f_onbusG3 := FALSE;
   f_lockG3 := FALSE;
   f_stpG3 := FALSE;
   f_blackoutG3 := FALSE;
   f_SGonbusG3 := FALSE;
   f_simulLockG3 := FALSE;
   f_preSeLockG3 := FALSE;
   f_i_SC_G3 := FALSE;
   f_busy_GsetG3 := FALSE;
   var053aG3 := FALSE;
   f_shoreModeG3 := FALSE;
   f_rdy_swtchOnG3 := FALSE;
   f_shore_actG3 := FALSE;
   f_LCtrlLockG3 := FALSE;
   f_FCtrlLockG3 := FALSE;
   f_UBLmax_actG3 := FALSE;
   var055G3 := FALSE;
   f_UBL_MinLockG3 := FALSE;
   c_lockShtdwnG3 := FALSE;
   c_takeLckShtdnG3 := FALSE;
   c_AllTieBrkOnG3 := FALSE;
   c_LckCtrlG3 := FALSE;
   c_takeLckCtrlG3 := FALSE;
   f_tieBrkOnG3 := FALSE;
   f_tieBrkTripG3 := FALSE;
   var056aG3 := FALSE;
   var056bG3 := FALSE;
   var056cG3 := FALSE;
   var056dG3 := FALSE;
   a_loadG3 := 0;
   s_ordSq1_8G3 := L#0;
   s_ordSq9_15G3 := L#0;
   var131G3 := B#16#0;
   var14G3 := B#16#0;
   var15G3 := B#16#0;
   var16G3 := B#16#0;
   var19G3 := 0;
   var20G3 := 0;
END_DATA_BLOCK


DATA_BLOCK "I_Gen4SR"
TITLE =Interface generator set 4. The 1. part contains the send
//area, the 2.part the receive area.                                                !
//
// I_Gen4SR
// Sende-/Empfangsfach MPI Generator 4
// Der Datenaustausch von oder zum Generator 1 erfolgt über diesen DB. Das Sendefach liegt im
// ersten Teil, das Empfangsteil liegt im zweiten Teil.
//
// Dieser DB ist für den TYP GENERATOR.
//
//
//  Siemens AG ATD IS3T, Kahle +494028892022, jens.kahle@hbg.siemens.de
//  PMA71
//  = Sende-/Empfangsfach MPI Generator 1
//  Datum aktuelle Version: 04.03.99
//  Version, Änd-Datum, Bearbeiter, geänderte Variablen
//  01.01,   31.01.99,  Kahle,      erste Version
//  01.02,   10.03.99,  Kahle,      Start/StoppReihenfolge,Kommando-
//                                  Spiegel, binäre Signale umsortieren
//
//KNOW_HOW_PROTECT
// (If specified, no more changes can be made once the block is generated)
//UNLINKED
// (If specified, the generated block is only available in the PLC load
//  memory)
//READ_ONLY
// (If specified, the generated block cannot be changed in the programmable
//  controller)
AUTHOR : Kahle
FAMILY : PMA71
NAME : I_Gen4SR
VERSION : 1.3


  STRUCT    // SENDEFACH
   c_reqStrt : BOOL ;   //Command: Request next generator set
   c_req2Strt : BOOL ;  //Command: Request second generator set
   c_reqEStrt : BOOL ;  //Command: Emergency request next generator set
   c_req2EStrt : BOOL ; //Command: Emergency request second generator set
   c_genBrkOpn : BOOL ; //Command: Generator breaker open by protection
   var01 : BOOL ;
   var02 : BOOL ;
   var03 : BOOL ;
   c_unitLock : BOOL ;  //Command: Block generator set
   c_simulLock : BOOL ; //Command: Simultaneous lock activating
   c_uncUBLoff : BOOL ; //Command: force UBL mode off
   c_shoreMode : BOOL ;  //Command: Shore connection mode activating
   var04 : BOOL ;
   c_takePreSeOrd : BOOL ;  //Command: Take over pre select order via MPI
   c_preSeLock : BOOL ; //Command: Preselection lock activating
   c_life : BOOL ;  //Life-Flag
   var051 : BYTE ;
   var052 : BYTE ;
   a_cmdMirror : DINT ; //Command mirror (bit 0 ..31)
   f_auto : BOOL ;  //Feedback: Generator set in automatic
   f_rdyStandby : BOOL ;    //Feedback: Generator set ready for standby
   f_brk_clse : BOOL ;  //Feedback: Generator breaker closed
   f_onbus : BOOL ; //Feedback: Generator set on busbar in automatic
   f_lock : BOOL ;  //Feedback: Generator set blocked
   f_stp : BOOL ;   //Feedback: Diesel is stopped
   f_blackout : BOOL ;  //Feedback: blackout
   f_SGonbus : BOOL ;   //Feedback: This generator is as a SG on bus
   f_simulLock : BOOL ; //Feedback: Simultaneous lock
   f_preSeLock : BOOL ; //Feedback: Preselection lock activating
   f_i_SC : BOOL ;  //Feedback: generator breaker was opened becauce of short curcuit
   f_busy_Gset : BOOL ; //Feedback: Preselection lock request not possible in the moment
   var053a : BOOL ;
   f_shoreMode : BOOL ; //Feedback: Shore connection mode is activated
   f_rdy_swtchOn : BOOL ;   //Feedback: Generator set ready for switch on
   f_shore_act : BOOL ; //Feedback: Shore connection is activing (one or more)
   f_LCtrlLock : BOOL ; //Feedback: Load controller is locked
   f_FCtrlLock : BOOL ; //Feedback: Frequency controller is locked
   f_UBLmax_act : BOOL ;    //Feedback: UBLmax is active
   var055 : BOOL ;
   f_UBL_MinLock : BOOL ;   //Command: UBL mode lock because of minimum load
   c_lockShtdwn : BOOL ;    //Command: no stop in case of underload (=1)
   c_takeLckShtdn : BOOL ;  //Command: take over command 'no stop in case of underload'
   c_AllTieBrkOn : BOOL ;   //Feedback: tie breaker on
   c_LckCtrl : BOOL ;   //Command: Lock controller (load & frequency) -TIE BREAKER ONLY-
   c_takeLckCtrl : BOOL ;   //Command: take over 'Lock controller' -TIE BREAKER ONLY-
   f_tieBrkOn : BOOL ;   //Feedback: tie breaker on -TIE BREAKER ONLY-
   f_tieBrkTrip : BOOL ;    //Feedback: tie breaker tripped -TIE BREAKER ONLY-
   var056a : BOOL ;
   var056b : BOOL ;
   var056c : BOOL ;
   var056d : BOOL ;
   a_load : INT ;   // Actual value: Active power
   s_ordSq1_8 : DINT ;  //setpoint: Start stop sequence of the actual configuration - (Gen.1 -8) -
   s_ordSq9_15 : DINT ; //Setpoint: Start stop sequence of the actual configuration - (Gen.9 -15) -
   var131 : BYTE ;
   var14 : BYTE ;
   var15 : BYTE ;
   var16 : BYTE ;
   var17 : INT ;
   var18 : INT ;    // EMPFANGSFACH
   c_reqStrtG4 : BOOL ; //Command: Request next generator set
   c_req2StrtG4 : BOOL ;    //Command: Request second generator set
   c_reqEStrtG4 : BOOL ;    //Command: Emergency request next generator set
   c_req2EStrtG4 : BOOL ;   //Command: Emergency request second generator set
   c_genBrkOpnG4 : BOOL ;   //Command: Generator breaker open by protection
   var01G4 : BOOL ;
   var02G4 : BOOL ;
   var03G4 : BOOL ;
   c_unitLockG4 : BOOL ;    //Command: Block generator set
   c_simulLockG4 : BOOL ;   //Command: Simultaneous lock activating
   c_uncUBLoffG4 : BOOL ;   //Command: force UBL mode off
   c_shoreModeG4 : BOOL ;   //Command: Shore connection mode activating
   var04G4 : BOOL ;
   c_takePreSeOrdG4 : BOOL ;    //Command: Take over pre select order via MPI
   c_preSeLockG4 : BOOL ;   //Command: Preselection lock activating
   c_lifeG4 : BOOL ;    //Life-Flag
   var051G4 : BYTE ;
   var052G4 : BYTE ;
   a_cmdMirrorG4 : DINT ;   //Command mirror (bit 0 ..31)
   f_autoG4 : BOOL ;    //Feedback: Generator set in automatic
   f_rdyStdbyG4 : BOOL ;    //Feedback: Generator set ready for standby
   f_brk_clseG4 : BOOL ;    //Feedback: Generator breaker closed
   f_onbusG4 : BOOL ;   //Feedback: Generator set on busbar in automatic
   f_lockG4 : BOOL ;    //Feedback: Generator set blocked
   f_stpG4 : BOOL ; //Feedback: Diesel is stopped
   f_blackoutG4 : BOOL ;    //Feedback: blackout
   f_SGonbusG4 : BOOL ; //Feedback: Generator is as a SG on bus
   f_simulLockG4 : BOOL ;   //Feedback: Simultaneous lock
   f_preSeLockG4 : BOOL ;   //Feedback: Preselection lock activating
   f_i_SC_G4 : BOOL ;   //Feedback: generator breaker was opened becauce of short curcuit
   f_busy_GsetG4 : BOOL ;   //Feedback: Preselection lock request not possible in the moment
   var053aG4 : BOOL ;
   f_shoreModeG4 : BOOL ;   //Feedback: Shore connection mode is activated
   f_rdy_swtchOnG4 : BOOL ; //Feedback: Generator set ready for switch on
   f_shore_actG4 : BOOL ;   //Feedback: Shore connection is activing (one or more)
   f_LCtrlLockG4 : BOOL ;   //Feedback: Load controller is locked
   f_FCtrlLockG4 : BOOL ;   //Feedback: Frequency controller is locked
   f_UBLmax_actG4 : BOOL ;  //Feedback: UBLmax is active
   var055G4 : BOOL ;
   f_UBL_MinLockG4 : BOOL ; //Command: UBL mode lock because of minimum load
   c_lockShtdwnG4 : BOOL ;  //Command: no stop in case of underload (=1)
   c_takeLckShtdnG4 : BOOL ;    //Command: take over command 'no stop in case of underload'
   c_AllTieBrkOnG4 : BOOL ; //Feedback: tie breaker on
   c_LckCtrlG4 : BOOL ; //Command: Lock controller (load & frequency)
   c_takeLckCtrlG4 : BOOL ; //Command: take over 'Lock controller'
   f_tieBrkOnG4 : BOOL ;    //Feedback: tie breaker on
   f_tieBrkTripG4 : BOOL ;  //Feedback: tie breaker tripped
   var056aG4 : BOOL ;
   var056bG4 : BOOL ;
   var056cG4 : BOOL ;
   var056dG4 : BOOL ;
   a_loadG4 : INT ; // Actual value: Active power
   s_ordSq1_8G4 : DINT ;    //setpoint: Start stop sequence of the actual configuration - (Gen.1 -8) -
   s_ordSq9_15G4 : DINT ;   // Setpoint: Start stop sequence of the actual configuration - (Gen.9 -15) -
   var131G4 : BYTE ;
   var14G4 : BYTE ;
   var15G4 : BYTE ;
   var16G4 : BYTE ;
   var19G4 : INT ;
   var20G4 : INT ;
  END_STRUCT ;
BEGIN
   c_reqStrt := FALSE;
   c_req2Strt := FALSE;
   c_reqEStrt := FALSE;
   c_req2EStrt := FALSE;
   c_genBrkOpn := FALSE;
   var01 := FALSE;
   var02 := FALSE;
   var03 := FALSE;
   c_unitLock := FALSE;
   c_simulLock := FALSE;
   c_uncUBLoff := FALSE;
   c_shoreMode := FALSE;
   var04 := FALSE;
   c_takePreSeOrd := FALSE;
   c_preSeLock := FALSE;
   c_life := FALSE;
   var051 := B#16#0;
   var052 := B#16#0;
   a_cmdMirror := L#0;
   f_auto := FALSE;
   f_rdyStandby := FALSE;
   f_brk_clse := FALSE;
   f_onbus := FALSE;
   f_lock := FALSE;
   f_stp := FALSE;
   f_blackout := FALSE;
   f_SGonbus := FALSE;
   f_simulLock := FALSE;
   f_preSeLock := FALSE;
   f_i_SC := FALSE;
   f_busy_Gset := FALSE;
   var053a := FALSE;
   f_shoreMode := FALSE;
   f_rdy_swtchOn := FALSE;
   f_shore_act := FALSE;
   f_LCtrlLock := FALSE;
   f_FCtrlLock := FALSE;
   f_UBLmax_act := FALSE;
   var055 := FALSE;
   f_UBL_MinLock := FALSE;
   c_lockShtdwn := FALSE;
   c_takeLckShtdn := FALSE;
   c_AllTieBrkOn := FALSE;
   c_LckCtrl := FALSE;
   c_takeLckCtrl := FALSE;
   f_tieBrkOn := FALSE;
   f_tieBrkTrip := FALSE;
   var056a := FALSE;
   var056b := FALSE;
   var056c := FALSE;
   var056d := FALSE;
   a_load := 0;
   s_ordSq1_8 := L#0;
   s_ordSq9_15 := L#0;
   var131 := B#16#0;
   var14 := B#16#0;
   var15 := B#16#0;
   var16 := B#16#0;
   var17 := 0;
   var18 := 0;
   c_reqStrtG4 := FALSE;
   c_req2StrtG4 := FALSE;
   c_reqEStrtG4 := FALSE;
   c_req2EStrtG4 := FALSE;
   c_genBrkOpnG4 := FALSE;
   var01G4 := FALSE;
   var02G4 := FALSE;
   var03G4 := FALSE;
   c_unitLockG4 := FALSE;
   c_simulLockG4 := FALSE;
   c_uncUBLoffG4 := FALSE;
   c_shoreModeG4 := FALSE;
   var04G4 := FALSE;
   c_takePreSeOrdG4 := FALSE;
   c_preSeLockG4 := FALSE;
   c_lifeG4 := FALSE;
   var051G4 := B#16#0;
   var052G4 := B#16#0;
   a_cmdMirrorG4 := L#0;
   f_autoG4 := FALSE;
   f_rdyStdbyG4 := FALSE;
   f_brk_clseG4 := FALSE;
   f_onbusG4 := FALSE;
   f_lockG4 := FALSE;
   f_stpG4 := FALSE;
   f_blackoutG4 := FALSE;
   f_SGonbusG4 := FALSE;
   f_simulLockG4 := FALSE;
   f_preSeLockG4 := FALSE;
   f_i_SC_G4 := FALSE;
   f_busy_GsetG4 := FALSE;
   var053aG4 := FALSE;
   f_shoreModeG4 := FALSE;
   f_rdy_swtchOnG4 := FALSE;
   f_shore_actG4 := FALSE;
   f_LCtrlLockG4 := FALSE;
   f_FCtrlLockG4 := FALSE;
   f_UBLmax_actG4 := FALSE;
   var055G4 := FALSE;
   f_UBL_MinLockG4 := FALSE;
   c_lockShtdwnG4 := FALSE;
   c_takeLckShtdnG4 := FALSE;
   c_AllTieBrkOnG4 := FALSE;
   c_LckCtrlG4 := FALSE;
   c_takeLckCtrlG4 := FALSE;
   f_tieBrkOnG4 := FALSE;
   f_tieBrkTripG4 := FALSE;
   var056aG4 := FALSE;
   var056bG4 := FALSE;
   var056cG4 := FALSE;
   var056dG4 := FALSE;
   a_loadG4 := 0;
   s_ordSq1_8G4 := L#0;
   s_ordSq9_15G4 := L#0;
   var131G4 := B#16#0;
   var14G4 := B#16#0;
   var15G4 := B#16#0;
   var16G4 := B#16#0;
   var19G4 := 0;
   var20G4 := 0;
END_DATA_BLOCK


DATA_BLOCK "I_Gen5SR"
TITLE =Interface generator set 5. The 1. part contains the send
//area, the 2.part the receive area.                                                !
//
// I_Gen5SR
// Sende-/Empfangsfach MPI Generator 5
// Der Datenaustausch von oder zum Generator 1 erfolgt über diesen DB. Das Sendefach liegt im
// ersten Teil, das Empfangsteil liegt im zweiten Teil.
//
// Dieser DB ist für den TYP GENERATOR.
//
//
//  Siemens AG ATD IS3T, Kahle +494028892022, jens.kahle@hbg.siemens.de
//  PMA71
//  = Sende-/Empfangsfach MPI Generator 1
//  Datum aktuelle Version: 04.03.99
//  Version, Änd-Datum, Bearbeiter, geänderte Variablen
//  01.01,   31.01.99,  Kahle,      erste Version
//  01.02,   10.03.99,  Kahle,      Start/StoppReihenfolge,Kommando-
//                                  Spiegel, binäre Signale umsortieren
//
//KNOW_HOW_PROTECT
// (If specified, no more changes can be made once the block is generated)
//UNLINKED
// (If specified, the generated block is only available in the PLC load
//  memory)
//READ_ONLY
// (If specified, the generated block cannot be changed in the programmable
//  controller)
AUTHOR : Kahle
FAMILY : PMA71
NAME : I_Gen5SR
VERSION : 1.3


  STRUCT    // SENDEFACH
   c_reqStrt : BOOL ;   //Command: Request next generator set
   c_req2Strt : BOOL ;  //Command: Request second generator set
   c_reqEStrt : BOOL ;  //Command: Emergency request next generator set
   c_req2EStrt : BOOL ; //Command: Emergency request second generator set
   c_genBrkOpn : BOOL ; //Command: Generator breaker open by protection
   var01 : BOOL ;
   var02 : BOOL ;
   var03 : BOOL ;
   c_unitLock : BOOL ;  //Command: Block generator set
   c_simulLock : BOOL ; //Command: Simultaneous lock activating
   c_uncUBLoff : BOOL ; //Command: force UBL mode off
   c_shoreMode : BOOL ; //Command: Shore connection mode activating
   var04 : BOOL ;
   c_takePreSeOrd : BOOL ;  //Command: Take over pre select order via MPI
   c_preSeLock : BOOL ; //Command: Preselection lock activating
   c_life : BOOL ;  //Life-Flag
   var051 : BYTE ;
   var052 : BYTE ;
   a_cmdMirror : DINT ; //Command mirror (bit 0 ..31)
   f_auto : BOOL ;  //Feedback: Generator set in automatic
   f_rdyStandby : BOOL ;    //Feedback: Generator set ready for standby
   f_brk_clse : BOOL ;  //Feedback: Generator breaker closed
   f_onbus : BOOL ; //Feedback: Generator set on busbar in automatic
   f_lock : BOOL ;  //Feedback: Generator set blocked
   f_stp : BOOL ;   //Feedback: Diesel is stopped
   f_blackout : BOOL ;  //Feedback: blackout
   f_SGonbus : BOOL ;   //Feedback: This generator is as a SG on bus
   f_simulLock : BOOL ; //Feedback: Simultaneous lock
   f_preSeLock : BOOL ; //Feedback: Preselection lock activating
   f_i_SC : BOOL ;  //Feedback: generator breaker was opened becauce of short curcuit
   f_busy_Gset : BOOL ; //Feedback: Preselection lock request not possible in the moment
   var053a : BOOL ;
   f_shoreMode : BOOL ; //Feedback: Shore connection mode is activated
   f_rdy_swtchOn : BOOL ;   //Feedback: Generator set ready for switch on
   f_shore_act : BOOL ; //Feedback: Shore connection is activing (one or more)
   f_LCtrlLock : BOOL ; //Feedback: Load controller is locked
   f_FCtrlLock : BOOL ; //Feedback: Frequency controller is locked
   f_UBLmax_act : BOOL ;    //Feedback: UBLmax is active
   var055 : BOOL ;
   f_UBL_MinLock : BOOL ;   //Command: UBL mode lock because of minimum load
   c_lockShtdwn : BOOL ;    //Command: no stop in case of underload (=1)
   c_takeLckShtdn : BOOL ;  //Command: take over command 'no stop in case of underload'
   c_AllTieBrkOn : BOOL ;   //Feedback: tie breaker on
   c_LckCtrl : BOOL ;   //Command: Lock controller (load & frequency) -TIE BREAKER ONLY-
   c_takeLckCtrl : BOOL ;   //Command: take over 'Lock controller' -TIE BREAKER ONLY-
   f_tieBrkOn : BOOL ;  //Feedback: tie breaker on -TIE BREAKER ONLY-
   f_tieBrkTrip : BOOL ;    //Feedback: tie breaker tripped -TIE BREAKER ONLY-
   var056a : BOOL ;
   var056b : BOOL ;
   var056c : BOOL ;
   var056d : BOOL ;
   a_load : INT ;   // Actual value: Active power
   s_ordSq1_8 : DINT ;  //setpoint: Start stop sequence of the actual configuration - (Gen.1 -8) -
   s_ordSq9_15 : DINT ; //Setpoint: Start stop sequence of the actual configuration - (Gen.9 -15) -
   var131 : BYTE ;
   var14 : BYTE ;
   var15 : BYTE ;
   var16 : BYTE ;
   var17 : INT ;
   var18 : INT ;    // EMPFANGSFACH
   c_reqStrtG5 : BOOL ; //Command: Request next generator set
   c_req2StrtG5 : BOOL ;    //Command: Request second generator set
   c_reqEStrtG5 : BOOL ;    //Command: Emergency request next generator set
   c_req2EStrtG5 : BOOL ;   //Command: Emergency request second generator set
   c_genBrkOpnG5 : BOOL ;   //Command: Generator breaker open by protection
   var01G5 : BOOL ;
   var02G5 : BOOL ;
   var03G5 : BOOL ;
   c_unitLockG5 : BOOL ;    //Command: Block generator set
   c_simulLockG5 : BOOL ;   //Command: Simultaneous lock activating
   c_uncUBLoffG5 : BOOL ;   //Command: force UBL mode off
   c_shoreModeG5 : BOOL ;   //Command: Shore connection mode activating
   var04G5 : BOOL ;
   c_takePreSeOrdG5 : BOOL ;    //Command: Take over pre select order via MPI
   c_preSeLockG5 : BOOL ;   //Command: Preselection lock activating
   c_lifeG5 : BOOL ;    //Life-Flag
   var051G5 : BYTE ;
   var052G5 : BYTE ;
   a_cmdMirrorG5 : DINT ;   //Command mirror (bit 0 ..31)
   f_autoG5 : BOOL ;    //Feedback: Generator set in automatic
   f_rdyStdbyG5 : BOOL ;    //Feedback: Generator set ready for standby
   f_brk_clseG5 : BOOL ;    //Feedback: Generator breaker closed
   f_onbusG5 : BOOL ;   //Feedback: Generator set on busbar in automatic
   f_lockG5 : BOOL ;    //Feedback: Generator set blocked
   f_stpG5 : BOOL ; //Feedback: Diesel is stopped
   f_blackoutG5 : BOOL ;    //Feedback: blackout
   f_SGonbusG5 : BOOL ; //Feedback: Generator is as a SG on bus
   f_simulLockG5 : BOOL ;   //Feedback: Simultaneous lock
   f_preSeLockG5 : BOOL ;   //Feedback: Preselection lock activating
   f_i_SC_G5 : BOOL ;   //Feedback: generator breaker was opened becauce of short curcuit
   f_busy_GsetG5 : BOOL ;   //Feedback: Preselection lock request not possible in the moment
   var053aG5 : BOOL ;
   f_shoreModeG5 : BOOL ;   //Feedback: Shore connection mode is activated
   f_rdy_swtchOnG5 : BOOL ; //Feedback: Generator set ready for switch on
   f_shore_actG5 : BOOL ;   //Feedback: Shore connection is activing (one or more)
   f_LCtrlLockG5 : BOOL ;   //Feedback: Load controller is locked
   f_FCtrlLockG5 : BOOL ;   //Feedback: Frequency controller is locked
   f_UBLmax_actG5 : BOOL ;  //Feedback: UBLmax is active
   var055G5 : BOOL ;
   f_UBL_MinLockG5 : BOOL ; //Command: UBL mode lock because of minimum load
   c_lockShtdwnG5 : BOOL ;  //Command: no stop in case of underload (=1)
   c_takeLckShtdnG5 : BOOL ;    //Command: take over command 'no stop in case of underload'
   c_AllTieBrkOnG5 : BOOL ; //Feedback: tie breaker on
   c_LckCtrlG5 : BOOL ; //Command: Lock controller (load & frequency)
   c_takeLckCtrlG5 : BOOL ; //Command: take over 'Lock controller'
   f_tieBrkOnG5 : BOOL ;    //Feedback: tie breaker on
   f_tieBrkTripG5 : BOOL ;  //Feedback: tie breaker tripped
   var056aG5 : BOOL ;
   var056bG5 : BOOL ;
   var056cG5 : BOOL ;
   var056dG5 : BOOL ;
   a_loadG5 : INT ; // Actual value: Active power
   s_ordSq1_8G5 : DINT ;    //setpoint: Start stop sequence of the actual configuration - (Gen.1 -8) -
   s_ordSq9_15G5 : DINT ;   // Setpoint: Start stop sequence of the actual configuration - (Gen.9 -15) -
   var131G5 : BYTE ;
   var14G5 : BYTE ;
   var15G5 : BYTE ;
   var16G5 : BYTE ;
   var19G5 : INT ;
   var20G5 : INT ;
  END_STRUCT ;
BEGIN
   c_reqStrt := FALSE;
   c_req2Strt := FALSE;
   c_reqEStrt := FALSE;
   c_req2EStrt := FALSE;
   c_genBrkOpn := FALSE;
   var01 := FALSE;
   var02 := FALSE;
   var03 := FALSE;
   c_unitLock := FALSE;
   c_simulLock := FALSE;
   c_uncUBLoff := FALSE;
   c_shoreMode := FALSE;
   var04 := FALSE;
   c_takePreSeOrd := FALSE;
   c_preSeLock := FALSE;
   c_life := FALSE;
   var051 := B#16#0;
   var052 := B#16#0;
   a_cmdMirror := L#0;
   f_auto := FALSE;
   f_rdyStandby := FALSE;
   f_brk_clse := FALSE;
   f_onbus := FALSE;
   f_lock := FALSE;
   f_stp := FALSE;
   f_blackout := FALSE;
   f_SGonbus := FALSE;
   f_simulLock := FALSE;
   f_preSeLock := FALSE;
   f_i_SC := FALSE;
   f_busy_Gset := FALSE;
   var053a := FALSE;
   f_shoreMode := FALSE;
   f_rdy_swtchOn := FALSE;
   f_shore_act := FALSE;
   f_LCtrlLock := FALSE;
   f_FCtrlLock := FALSE;
   f_UBLmax_act := FALSE;
   var055 := FALSE;
   f_UBL_MinLock := FALSE;
   c_lockShtdwn := FALSE;
   c_takeLckShtdn := FALSE;
   c_AllTieBrkOn := FALSE;
   c_LckCtrl := FALSE;
   c_takeLckCtrl := FALSE;
   f_tieBrkOn := FALSE;
   f_tieBrkTrip := FALSE;
   var056a := FALSE;
   var056b := FALSE;
   var056c := FALSE;
   var056d := FALSE;
   a_load := 0;
   s_ordSq1_8 := L#0;
   s_ordSq9_15 := L#0;
   var131 := B#16#0;
   var14 := B#16#0;
   var15 := B#16#0;
   var16 := B#16#0;
   var17 := 0;
   var18 := 0;
   c_reqStrtG5 := FALSE;
   c_req2StrtG5 := FALSE;
   c_reqEStrtG5 := FALSE;
   c_req2EStrtG5 := FALSE;
   c_genBrkOpnG5 := FALSE;
   var01G5 := FALSE;
   var02G5 := FALSE;
   var03G5 := FALSE;
   c_unitLockG5 := FALSE;
   c_simulLockG5 := FALSE;
   c_uncUBLoffG5 := FALSE;
   c_shoreModeG5 := FALSE;
   var04G5 := FALSE;
   c_takePreSeOrdG5 := FALSE;
   c_preSeLockG5 := FALSE;
   c_lifeG5 := FALSE;
   var051G5 := B#16#0;
   var052G5 := B#16#0;
   a_cmdMirrorG5 := L#0;
   f_autoG5 := FALSE;
   f_rdyStdbyG5 := FALSE;
   f_brk_clseG5 := FALSE;
   f_onbusG5 := FALSE;
   f_lockG5 := FALSE;
   f_stpG5 := FALSE;
   f_blackoutG5 := FALSE;
   f_SGonbusG5 := FALSE;
   f_simulLockG5 := FALSE;
   f_preSeLockG5 := FALSE;
   f_i_SC_G5 := FALSE;
   f_busy_GsetG5 := FALSE;
   var053aG5 := FALSE;
   f_shoreModeG5 := FALSE;
   f_rdy_swtchOnG5 := FALSE;
   f_shore_actG5 := FALSE;
   f_LCtrlLockG5 := FALSE;
   f_FCtrlLockG5 := FALSE;
   f_UBLmax_actG5 := FALSE;
   var055G5 := FALSE;
   f_UBL_MinLockG5 := FALSE;
   c_lockShtdwnG5 := FALSE;
   c_takeLckShtdnG5 := FALSE;
   c_AllTieBrkOnG5 := FALSE;
   c_LckCtrlG5 := FALSE;
   c_takeLckCtrlG5 := FALSE;
   f_tieBrkOnG5 := FALSE;
   f_tieBrkTripG5 := FALSE;
   var056aG5 := FALSE;
   var056bG5 := FALSE;
   var056cG5 := FALSE;
   var056dG5 := FALSE;
   a_loadG5 := 0;
   s_ordSq1_8G5 := L#0;
   s_ordSq9_15G5 := L#0;
   var131G5 := B#16#0;
   var14G5 := B#16#0;
   var15G5 := B#16#0;
   var16G5 := B#16#0;
   var19G5 := 0;
   var20G5 := 0;
END_DATA_BLOCK


DATA_BLOCK "I_Gen6SR"
TITLE =Interface generator set 6. The 1. part contains the send
//area, the 2.part the receive area.                                                !
//
// I_Gen6SR
// Sende-/Empfangsfach MPI Generator 6
// Der Datenaustausch von oder zum Generator 1 erfolgt über diesen DB. Das Sendefach liegt im
// ersten Teil, das Empfangsteil liegt im zweiten Teil.
//
// Dieser DB ist für den TYP GENERATOR.
//
//
//  Siemens AG ATD IS3T, Kahle +494028892022, jens.kahle@hbg.siemens.de
//  PMA71
//  = Sende-/Empfangsfach MPI Generator 1
//  Datum aktuelle Version: 04.03.99
//  Version, Änd-Datum, Bearbeiter, geänderte Variablen
//  01.01,   31.01.99,  Kahle,      erste Version
//  01.02,   10.03.99,  Kahle,      Start/StoppReihenfolge,Kommando-
//                                  Spiegel, binäre Signale umsortieren
//
//KNOW_HOW_PROTECT
// (If specified, no more changes can be made once the block is generated)
//UNLINKED
// (If specified, the generated block is only available in the PLC load
//  memory)
//READ_ONLY
// (If specified, the generated block cannot be changed in the programmable
//  controller)
AUTHOR : Kahle
FAMILY : PMA71
NAME : I_Gen6SR
VERSION : 1.3


  STRUCT    // SENDEFACH
   c_reqStrt : BOOL ;   //Command: Request next generator set
   c_req2Strt : BOOL ;  //Command: Request second generator set
   c_reqEStrt : BOOL ;  //Command: Emergency request next generator set
   c_req2EStrt : BOOL ;    //Command: Emergency request second generator set
   c_genBrkOpn : BOOL ; //Command: Generator breaker open by protection
   var01 : BOOL ;
   var02 : BOOL ;
   var03 : BOOL ;
   c_unitLock : BOOL ;  //Command: Block generator set
   c_simulLock : BOOL ; //Command: Simultaneous lock activating
   c_uncUBLoff : BOOL ; //Command: force UBL mode off
   c_shoreMode : BOOL ; //Command: Shore connection mode activating
   var04 : BOOL ;
   c_takePreSeOrd : BOOL ;  //Command: Take over pre select order via MPI
   c_preSeLock : BOOL ; //Command: Preselection lock activating
   c_life : BOOL ;  //Life-Flag
   var051 : BYTE ;
   var052 : BYTE ;
   a_cmdMirror : DINT ; //Command mirror (bit 0 ..31)
   f_auto : BOOL ;  //Feedback: Generator set in automatic
   f_rdyStandby : BOOL ;    //Feedback: Generator set ready for standby
   f_brk_clse : BOOL ;  //Feedback: Generator breaker closed
   f_onbus : BOOL ; //Feedback: Generator set on busbar in automatic
   f_lock : BOOL ;  //Feedback: Generator set blocked
   f_stp : BOOL ;   //Feedback: Diesel is stopped
   f_blackout : BOOL ;  //Feedback: blackout
   f_SGonbus : BOOL ;   //Feedback: This generator is as a SG on bus
   f_simulLock : BOOL ; //Feedback: Simultaneous lock
   f_preSeLock : BOOL ; //Feedback: Preselection lock activating
   f_i_SC : BOOL ;  //Feedback: generator breaker was opened becauce of short curcuit
   f_busy_Gset : BOOL ; //Feedback: Preselection lock request not possible in the moment
   var053a : BOOL ;
   f_shoreMode : BOOL ; //Feedback: Shore connection mode is activated
   f_rdy_swtchOn : BOOL ;   //Feedback: Generator set ready for switch on
   f_shore_act : BOOL ; //Feedback: Shore connection is activing (one or more)
   f_LCtrlLock : BOOL ; //Feedback: Load controller is locked
   f_FCtrlLock : BOOL ; //Feedback: Frequency controller is locked
   f_UBLmax_act : BOOL ;    //Feedback: UBLmax is active
   var055 : BOOL ;
   f_UBL_MinLock : BOOL ;   //Command: UBL mode lock because of minimum load
   c_lockShtdwn : BOOL ;  //Command: no stop in case of underload (=1)
   c_takeLckShtdn : BOOL ;  //Command: take over command 'no stop in case of underload'
   c_AllTieBrkOn : BOOL ;   //Feedback: tie breaker on
   c_LckCtrl : BOOL ;   //Command: Lock controller (load & frequency) -TIE BREAKER ONLY-
   c_takeLckCtrl : BOOL ;   //Command: take over 'Lock controller' -TIE BREAKER ONLY-
   f_tieBrkOn : BOOL ;  //Feedback: tie breaker on -TIE BREAKER ONLY-
   f_tieBrkTrip : BOOL ;    //Feedback: tie breaker tripped -TIE BREAKER ONLY-
   var056a : BOOL ;
   var056b : BOOL ;
   var056c : BOOL ;
   var056d : BOOL ;
   a_load : INT ;   // Actual value: Active power
   s_ordSq1_8 : DINT ;  //setpoint: Start stop sequence of the actual configuration - (Gen.1 -8) -
   s_ordSq9_15 : DINT ; //Setpoint: Start stop sequence of the actual configuration - (Gen.9 -15) -
   var131 : BYTE ;
   var14 : BYTE ;
   var15 : BYTE ;
   var16 : BYTE ;
   var17 : INT ;
   var18 : INT ;    // EMPFANGSFACH
   c_reqStrtG6 : BOOL ; //Command: Request next generator set
   c_req2StrtG6 : BOOL ;    //Command: Request second generator set
   c_reqEStrtG6 : BOOL ;    //Command: Emergency request next generator set
   c_req2EStrtG6 : BOOL ;   //Command: Emergency request second generator set
   c_genBrkOpnG6 : BOOL ;   //Command: Generator breaker open by protection
   var01G6 : BOOL ;
   var02G6 : BOOL ;
   var03G6 : BOOL ;
   c_unitLockG6 : BOOL ;    //Command: Block generator set
   c_simulLockG6 : BOOL ;   //Command: Simultaneous lock activating
   c_uncUBLoffG6 : BOOL ;   //Command: force UBL mode off
   c_shoreModeG6 : BOOL ;   //Command: Shore connection mode activating
   var04G6 : BOOL ;
   c_takePreSeOrdG6 : BOOL ;    //Command: Take over pre select order via MPI
   c_preSeLockG6 : BOOL ;   //Command: Preselection lock activating
   c_lifeG6 : BOOL ;    //Life-Flag
   var051G6 : BYTE ;
   var052G6 : BYTE ;
   a_cmdMirrorG6 : DINT ;   //Command mirror (bit 0 ..31)
   f_autoG6 : BOOL ;    //Feedback: Generator set in automatic
   f_rdyStdbyG6 : BOOL ;    //Feedback: Generator set ready for standby
   f_brk_clseG6 : BOOL ;    //Feedback: Generator breaker closed
   f_onbusG6 : BOOL ;   //Feedback: Generator set on busbar in automatic
   f_lockG6 : BOOL ;    //Feedback: Generator set blocked
   f_stpG6 : BOOL ; //Feedback: Diesel is stopped
   f_blackoutG6 : BOOL ;    //Feedback: blackout
   f_SGonbusG6 : BOOL ; //Feedback: Generator is as a SG on bus
   f_simulLockG6 : BOOL ;   //Feedback: Simultaneous lock
   f_preSeLockG6 : BOOL ;   //Feedback: Preselection lock activating
   f_i_SC_G6 : BOOL ;   //Feedback: generator breaker was opened becauce of short curcuit
   f_busy_GsetG6 : BOOL ;   //Feedback: Preselection lock request not possible in the moment
   var053aG6 : BOOL ;
   f_shoreModeG6 : BOOL ;   //Feedback: Shore connection mode is activated
   f_rdy_swtchOnG6 : BOOL ; //Feedback: Generator set ready for switch on
   f_shore_actG6 : BOOL ;   //Feedback: Shore connection is activing (one or more)
   f_LCtrlLockG6 : BOOL ;   //Feedback: Load controller is locked
   f_FCtrlLockG6 : BOOL ;   //Feedback: Frequency controller is locked
   f_UBLmax_actG6 : BOOL ;  //Feedback: UBLmax is active
   var055G6 : BOOL ;
   f_UBL_MinLockG6 : BOOL ; //Command: UBL mode lock because of minimum load
   c_lockShtdwnG6 : BOOL ;  //Command: no stop in case of underload (=1)
   c_takeLckShtdnG6 : BOOL ;    //Command: take over command 'no stop in case of underload'
   c_AllTieBrkOnG6 : BOOL ; //Feedback: tie breaker on
   c_LckCtrlG6 : BOOL ; //Command: Lock controller (load & frequency)
   c_takeLckCtrlG6 : BOOL ; //Command: take over 'Lock controller'
   f_tieBrkOnG6 : BOOL ;    //Feedback: tie breaker on
   f_tieBrkTripG6 : BOOL ;  //Feedback: tie breaker tripped
   var056aG6 : BOOL ;
   var056bG6 : BOOL ;
   var056cG6 : BOOL ;
   var056dG6 : BOOL ;
   a_loadG6 : INT ; // Actual value: Active power
   s_ordSq1_8G6 : DINT ;    //setpoint: Start stop sequence of the actual configuration - (Gen.1 -8) -
   s_ordSq9_15G6 : DINT ;   // Setpoint: Start stop sequence of the actual configuration - (Gen.9 -15) -
   var131G6 : BYTE ;
   var14G6 : BYTE ;
   var15G6 : BYTE ;
   var16G6 : BYTE ;
   var19G6 : INT ;
   var20G6 : INT ;
  END_STRUCT ;
BEGIN
   c_reqStrt := FALSE;
   c_req2Strt := FALSE;
   c_reqEStrt := FALSE;
   c_req2EStrt := FALSE;
   c_genBrkOpn := FALSE;
   var01 := FALSE;
   var02 := FALSE;
   var03 := FALSE;
   c_unitLock := FALSE;
   c_simulLock := FALSE;
   c_uncUBLoff := FALSE;
   c_shoreMode := FALSE;
   var04 := FALSE;
   c_takePreSeOrd := FALSE;
   c_preSeLock := FALSE;
   c_life := FALSE;
   var051 := B#16#0;
   var052 := B#16#0;
   a_cmdMirror := L#0;
   f_auto := FALSE;
   f_rdyStandby := FALSE;
   f_brk_clse := FALSE;
   f_onbus := FALSE;
   f_lock := FALSE;
   f_stp := FALSE;
   f_blackout := FALSE;
   f_SGonbus := FALSE;
   f_simulLock := FALSE;
   f_preSeLock := FALSE;
   f_i_SC := FALSE;
   f_busy_Gset := FALSE;
   var053a := FALSE;
   f_shoreMode := FALSE;
   f_rdy_swtchOn := FALSE;
   f_shore_act := FALSE;
   f_LCtrlLock := FALSE;
   f_FCtrlLock := FALSE;
   f_UBLmax_act := FALSE;
   var055 := FALSE;
   f_UBL_MinLock := FALSE;
   c_lockShtdwn := FALSE;
   c_takeLckShtdn := FALSE;
   c_AllTieBrkOn := FALSE;
   c_LckCtrl := FALSE;
   c_takeLckCtrl := FALSE;
   f_tieBrkOn := FALSE;
   f_tieBrkTrip := FALSE;
   var056a := FALSE;
   var056b := FALSE;
   var056c := FALSE;
   var056d := FALSE;
   a_load := 0;
   s_ordSq1_8 := L#0;
   s_ordSq9_15 := L#0;
   var131 := B#16#0;
   var14 := B#16#0;
   var15 := B#16#0;
   var16 := B#16#0;
   var17 := 0;
   var18 := 0;
   c_reqStrtG6 := FALSE;
   c_req2StrtG6 := FALSE;
   c_reqEStrtG6 := FALSE;
   c_req2EStrtG6 := FALSE;
   c_genBrkOpnG6 := FALSE;
   var01G6 := FALSE;
   var02G6 := FALSE;
   var03G6 := FALSE;
   c_unitLockG6 := FALSE;
   c_simulLockG6 := FALSE;
   c_uncUBLoffG6 := FALSE;
   c_shoreModeG6 := FALSE;
   var04G6 := FALSE;
   c_takePreSeOrdG6 := FALSE;
   c_preSeLockG6 := FALSE;
   c_lifeG6 := FALSE;
   var051G6 := B#16#0;
   var052G6 := B#16#0;
   a_cmdMirrorG6 := L#0;
   f_autoG6 := FALSE;
   f_rdyStdbyG6 := FALSE;
   f_brk_clseG6 := FALSE;
   f_onbusG6 := FALSE;
   f_lockG6 := FALSE;
   f_stpG6 := FALSE;
   f_blackoutG6 := FALSE;
   f_SGonbusG6 := FALSE;
   f_simulLockG6 := FALSE;
   f_preSeLockG6 := FALSE;
   f_i_SC_G6 := FALSE;
   f_busy_GsetG6 := FALSE;
   var053aG6 := FALSE;
   f_shoreModeG6 := FALSE;
   f_rdy_swtchOnG6 := FALSE;
   f_shore_actG6 := FALSE;
   f_LCtrlLockG6 := FALSE;
   f_FCtrlLockG6 := FALSE;
   f_UBLmax_actG6 := FALSE;
   var055G6 := FALSE;
   f_UBL_MinLockG6 := FALSE;
   c_lockShtdwnG6 := FALSE;
   c_takeLckShtdnG6 := FALSE;
   c_AllTieBrkOnG6 := FALSE;
   c_LckCtrlG6 := FALSE;
   c_takeLckCtrlG6 := FALSE;
   f_tieBrkOnG6 := FALSE;
   f_tieBrkTripG6 := FALSE;
   var056aG6 := FALSE;
   var056bG6 := FALSE;
   var056cG6 := FALSE;
   var056dG6 := FALSE;
   a_loadG6 := 0;
   s_ordSq1_8G6 := L#0;
   s_ordSq9_15G6 := L#0;
   var131G6 := B#16#0;
   var14G6 := B#16#0;
   var15G6 := B#16#0;
   var16G6 := B#16#0;
   var19G6 := 0;
   var20G6 := 0;
END_DATA_BLOCK


DATA_BLOCK "I_Gen7SR"
TITLE =Interface generator set 7. The 1. part contains the send
//area, the 2.part the receive area.                                                !
//
// I_Gen7SR
// Sende-/Empfangsfach MPI Generator 7
// Der Datenaustausch von oder zum Generator 1 erfolgt über diesen DB. Das Sendefach liegt im
// ersten Teil, das Empfangsteil liegt im zweiten Teil.
//
// Dieser DB ist für den TYP GENERATOR.
//
//
//  Siemens AG ATD IS3T, Kahle +494028892022, jens.kahle@hbg.siemens.de
//  PMA71
//  = Sende-/Empfangsfach MPI Generator 1
//  Datum aktuelle Version: 04.03.99
//  Version, Änd-Datum, Bearbeiter, geänderte Variablen
//  01.01,   31.01.99,  Kahle,      erste Version
//  01.02,   10.03.99,  Kahle,      Start/StoppReihenfolge,Kommando-
//                                  Spiegel, binäre Signale umsortieren
//
//KNOW_HOW_PROTECT
// (If specified, no more changes can be made once the block is generated)
//UNLINKED
// (If specified, the generated block is only available in the PLC load
//  memory)
//READ_ONLY
// (If specified, the generated block cannot be changed in the programmable
//  controller)
AUTHOR : Kahle
FAMILY : PMA71
NAME : I_Gen7SR
VERSION : 1.3


  STRUCT    // SENDEFACH
   c_reqStrt : BOOL ;   //Command: Request next generator set
   c_req2Strt : BOOL ;  //Command: Request second generator set
   c_reqEStrt : BOOL ;  //Command: Emergency request next generator set
   c_req2EStrt : BOOL ; //Command: Emergency request second generator set
   c_genBrkOpn : BOOL ; //Command: Generator breaker open by protection
   var01 : BOOL ;
   var02 : BOOL ;
   var03 : BOOL ;
   c_unitLock : BOOL ;  //Command: Block generator set
   c_simulLock : BOOL ; //Command: Simultaneous lock activating
   c_uncUBLoff : BOOL ;    //Command: force UBL mode off
   c_shoreMode : BOOL ; //Command: Shore connection mode activating
   var04 : BOOL ;
   c_takePreSeOrd : BOOL ;  //Command: Take over pre select order via MPI
   c_preSeLock : BOOL ; //Command: Preselection lock activating
   c_life : BOOL ;  //Life-Flag
   var051 : BYTE ;
   var052 : BYTE ;
   a_cmdMirror : DINT ; //Command mirror (bit 0 ..31)
   f_auto : BOOL ;  //Feedback: Generator set in automatic
   f_rdyStandby : BOOL ;    //Feedback: Generator set ready for standby
   f_brk_clse : BOOL ;  //Feedback: Generator breaker closed
   f_onbus : BOOL ; //Feedback: Generator set on busbar in automatic
   f_lock : BOOL ;  //Feedback: Generator set blocked
   f_stp : BOOL ;   //Feedback: Diesel is stopped
   f_blackout : BOOL ;  //Feedback: blackout
   f_SGonbus : BOOL ;   //Feedback: This generator is as a SG on bus
   f_simulLock : BOOL ; //Feedback: Simultaneous lock
   f_preSeLock : BOOL ; //Feedback: Preselection lock activating
   f_i_SC : BOOL ;  //Feedback: generator breaker was opened becauce of short curcuit
   f_busy_Gset : BOOL ; //Feedback: Preselection lock request not possible in the moment
   var053a : BOOL ;
   f_shoreMode : BOOL ; //Feedback: Shore connection mode is activated
   f_rdy_swtchOn : BOOL ;   //Feedback: Generator set ready for switch on
   f_shore_act : BOOL ; //Feedback: Shore connection is activing (one or more)
   f_LCtrlLock : BOOL ; //Feedback: Load controller is locked
   f_FCtrlLock : BOOL ; //Feedback: Frequency controller is locked
   f_UBLmax_act : BOOL ;    //Feedback: UBLmax is active
   var055 : BOOL ;
   f_UBL_MinLock : BOOL ;   //Command: UBL mode lock because of minimum load
   c_lockShtdwn : BOOL ;    //Command: no stop in case of underload (=1)
   c_takeLckShtdn : BOOL ;  //Command: take over command 'no stop in case of underload'
   c_AllTieBrkOn : BOOL ;   //Feedback: tie breaker on
   c_LckCtrl : BOOL ;   //Command: Lock controller (load & frequency) -TIE BREAKER ONLY-
   c_takeLckCtrl : BOOL ;   //Command: take over 'Lock controller' -TIE BREAKER ONLY-
   f_tieBrkOn : BOOL ;  //Feedback: tie breaker on -TIE BREAKER ONLY-
   f_tieBrkTrip : BOOL ;    //Feedback: tie breaker tripped -TIE BREAKER ONLY-
   var056a : BOOL ;
   var056b : BOOL ;
   var056c : BOOL ;
   var056d : BOOL ;
   a_load : INT ;   // Actual value: Active power
   s_ordSq1_8 : DINT ;  //setpoint: Start stop sequence of the actual configuration - (Gen.1 -8) -
   s_ordSq9_15 : DINT ; //Setpoint: Start stop sequence of the actual configuration - (Gen.9 -15) -
   var131 : BYTE ;
   var14 : BYTE ;
   var15 : BYTE ;
   var16 : BYTE ;
   var17 : INT ;
   var18 : INT ;    // EMPFANGSFACH
   c_reqStrtG7 : BOOL ; //Command: Request next generator set
   c_req2StrtG7 : BOOL ;    //Command: Request second generator set
   c_reqEStrtG7 : BOOL ;    //Command: Emergency request next generator set
   c_req2EStrtG7 : BOOL ;   //Command: Emergency request second generator set
   c_genBrkOpnG7 : BOOL ;   //Command: Generator breaker open by protection
   var01G7 : BOOL ;
   var02G7 : BOOL ;
   var03G7 : BOOL ;
   c_unitLockG7 : BOOL ;    //Command: Block generator set
   c_simulLockG7 : BOOL ;   //Command: Simultaneous lock activating
   c_uncUBLoffG7 : BOOL ;   //Command: force UBL mode off
   c_shoreModeG7 : BOOL ;   //Command: Shore connection mode activating
   var04G7 : BOOL ;
   c_takePreSeOrdG7 : BOOL ;    //Command: Take over pre select order via MPI
   c_preSeLockG7 : BOOL ;   //Command: Preselection lock activating
   c_lifeG7 : BOOL ;    //Life-Flag
   var051G7 : BYTE ;
   var052G7 : BYTE ;
   a_cmdMirrorG7 : DINT ;   //Command mirror (bit 0 ..31)
   f_autoG7 : BOOL ;    //Feedback: Generator set in automatic
   f_rdyStdbyG7 : BOOL ;    //Feedback: Generator set ready for standby
   f_brk_clseG7 : BOOL ;    //Feedback: Generator breaker closed
   f_onbusG7 : BOOL ;   //Feedback: Generator set on busbar in automatic
   f_lockG7 : BOOL ;    //Feedback: Generator set blocked
   f_stpG7 : BOOL ; //Feedback: Diesel is stopped
   f_blackoutG7 : BOOL ;    //Feedback: blackout
   f_SGonbusG7 : BOOL ; //Feedback: Generator is as a SG on bus
   f_simulLockG7 : BOOL ;   //Feedback: Simultaneous lock
   f_preSeLockG7 : BOOL ;   //Feedback: Preselection lock activating
   f_i_SC_G7 : BOOL ;   //Feedback: generator breaker was opened becauce of short curcuit
   f_busy_GsetG7 : BOOL ;   //Feedback: Preselection lock request not possible in the moment
   var053aG7 : BOOL ;
   f_shoreModeG7 : BOOL ;   //Feedback: Shore connection mode is activated
   f_rdy_swtchOnG7 : BOOL ; //Feedback: Generator set ready for switch on
   f_shore_actG7 : BOOL ;   //Feedback: Shore connection is activing (one or more)
   f_LCtrlLockG7 : BOOL ;   //Feedback: Load controller is locked
   f_FCtrlLockG7 : BOOL ;   //Feedback: Frequency controller is locked
   f_UBLmax_actG7 : BOOL ;  //Feedback: UBLmax is active
   var055G7 : BOOL ;
   f_UBL_MinLockG7 : BOOL ; //Command: UBL mode lock because of minimum load
   c_lockShtdwnG7 : BOOL ;  //Command: no stop in case of underload (=1)
   c_takeLckShtdnG7 : BOOL ;  //Command: take over command 'no stop in case of underload'
   c_AllTieBrkOnG7 : BOOL ; //Feedback: tie breaker on
   c_LckCtrlG7 : BOOL ; //Command: Lock controller (load & frequency)
   c_takeLckCtrlG7 : BOOL ; //Command: take over 'Lock controller'
   f_tieBrkOnG7 : BOOL ;    //Feedback: tie breaker on
   f_tieBrkTripG7 : BOOL ;  //Feedback: tie breaker tripped
   var056aG7 : BOOL ;
   var056bG7 : BOOL ;
   var056cG7 : BOOL ;
   var056dG7 : BOOL ;
   a_loadG7 : INT ; // Actual value: Active power
   s_ordSq1_8G7 : DINT ;    //setpoint: Start stop sequence of the actual configuration - (Gen.1 -8) -
   s_ordSq9_15G7 : DINT ;   // Setpoint: Start stop sequence of the actual configuration - (Gen.9 -15) -
   var131G7 : BYTE ;
   var14G7 : BYTE ;
   var15G7 : BYTE ;
   var16G7 : BYTE ;
   var19G7 : INT ;
   var20G7 : INT ;
  END_STRUCT ;
BEGIN
   c_reqStrt := FALSE;
   c_req2Strt := FALSE;
   c_reqEStrt := FALSE;
   c_req2EStrt := FALSE;
   c_genBrkOpn := FALSE;
   var01 := FALSE;
   var02 := FALSE;
   var03 := FALSE;
   c_unitLock := FALSE;
   c_simulLock := FALSE;
   c_uncUBLoff := FALSE;
   c_shoreMode := FALSE;
   var04 := FALSE;
   c_takePreSeOrd := FALSE;
   c_preSeLock := FALSE;
   c_life := FALSE;
   var051 := B#16#0;
   var052 := B#16#0;
   a_cmdMirror := L#0;
   f_auto := FALSE;
   f_rdyStandby := FALSE;
   f_brk_clse := FALSE;
   f_onbus := FALSE;
   f_lock := FALSE;
   f_stp := FALSE;
   f_blackout := FALSE;
   f_SGonbus := FALSE;
   f_simulLock := FALSE;
   f_preSeLock := FALSE;
   f_i_SC := FALSE;
   f_busy_Gset := FALSE;
   var053a := FALSE;
   f_shoreMode := FALSE;
   f_rdy_swtchOn := FALSE;
   f_shore_act := FALSE;
   f_LCtrlLock := FALSE;
   f_FCtrlLock := FALSE;
   f_UBLmax_act := FALSE;
   var055 := FALSE;
   f_UBL_MinLock := FALSE;
   c_lockShtdwn := FALSE;
   c_takeLckShtdn := FALSE;
   c_AllTieBrkOn := FALSE;
   c_LckCtrl := FALSE;
   c_takeLckCtrl := FALSE;
   f_tieBrkOn := FALSE;
   f_tieBrkTrip := FALSE;
   var056a := FALSE;
   var056b := FALSE;
   var056c := FALSE;
   var056d := FALSE;
   a_load := 0;
   s_ordSq1_8 := L#0;
   s_ordSq9_15 := L#0;
   var131 := B#16#0;
   var14 := B#16#0;
   var15 := B#16#0;
   var16 := B#16#0;
   var17 := 0;
   var18 := 0;
   c_reqStrtG7 := FALSE;
   c_req2StrtG7 := FALSE;
   c_reqEStrtG7 := FALSE;
   c_req2EStrtG7 := FALSE;
   c_genBrkOpnG7 := FALSE;
   var01G7 := FALSE;
   var02G7 := FALSE;
   var03G7 := FALSE;
   c_unitLockG7 := FALSE;
   c_simulLockG7 := FALSE;
   c_uncUBLoffG7 := FALSE;
   c_shoreModeG7 := FALSE;
   var04G7 := FALSE;
   c_takePreSeOrdG7 := FALSE;
   c_preSeLockG7 := FALSE;
   c_lifeG7 := FALSE;
   var051G7 := B#16#0;
   var052G7 := B#16#0;
   a_cmdMirrorG7 := L#0;
   f_autoG7 := FALSE;
   f_rdyStdbyG7 := FALSE;
   f_brk_clseG7 := FALSE;
   f_onbusG7 := FALSE;
   f_lockG7 := FALSE;
   f_stpG7 := FALSE;
   f_blackoutG7 := FALSE;
   f_SGonbusG7 := FALSE;
   f_simulLockG7 := FALSE;
   f_preSeLockG7 := FALSE;
   f_i_SC_G7 := FALSE;
   f_busy_GsetG7 := FALSE;
   var053aG7 := FALSE;
   f_shoreModeG7 := FALSE;
   f_rdy_swtchOnG7 := FALSE;
   f_shore_actG7 := FALSE;
   f_LCtrlLockG7 := FALSE;
   f_FCtrlLockG7 := FALSE;
   f_UBLmax_actG7 := FALSE;
   var055G7 := FALSE;
   f_UBL_MinLockG7 := FALSE;
   c_lockShtdwnG7 := FALSE;
   c_takeLckShtdnG7 := FALSE;
   c_AllTieBrkOnG7 := FALSE;
   c_LckCtrlG7 := FALSE;
   c_takeLckCtrlG7 := FALSE;
   f_tieBrkOnG7 := FALSE;
   f_tieBrkTripG7 := FALSE;
   var056aG7 := FALSE;
   var056bG7 := FALSE;
   var056cG7 := FALSE;
   var056dG7 := FALSE;
   a_loadG7 := 0;
   s_ordSq1_8G7 := L#0;
   s_ordSq9_15G7 := L#0;
   var131G7 := B#16#0;
   var14G7 := B#16#0;
   var15G7 := B#16#0;
   var16G7 := B#16#0;
   var19G7 := 0;
   var20G7 := 0;
END_DATA_BLOCK


DATA_BLOCK "I_Gen8SR"
TITLE =Interface generator set 8. The 1. part contains the send
//area, the 2.part the receive area.                                                !
//
// I_Gen8SR
// Sende-/Empfangsfach MPI Generator 8
// Der Datenaustausch von oder zum Generator 1 erfolgt über diesen DB. Das Sendefach liegt im
// ersten Teil, das Empfangsteil liegt im zweiten Teil.
//
// Dieser DB ist für den TYP GENERATOR.
//
//
//  Siemens AG ATD IS3T, Kahle +494028892022, jens.kahle@hbg.siemens.de
//  PMA71
//  = Sende-/Empfangsfach MPI Generator 1
//  Datum aktuelle Version: 04.03.99
//  Version, Änd-Datum, Bearbeiter, geänderte Variablen
//  01.01,   31.01.99,  Kahle,      erste Version
//  01.02,   10.03.99,  Kahle,      Start/StoppReihenfolge,Kommando-
//                                  Spiegel, binäre Signale umsortieren
//
//KNOW_HOW_PROTECT
// (If specified, no more changes can be made once the block is generated)
//UNLINKED
// (If specified, the generated block is only available in the PLC load
//  memory)
//READ_ONLY
// (If specified, the generated block cannot be changed in the programmable
//  controller)
AUTHOR : Kahle
FAMILY : PMA71
NAME : I_Gen8SR
VERSION : 1.3


  STRUCT    // SENDEFACH
   c_reqStrt : BOOL ;   //Command: Request next generator set
   c_req2Strt : BOOL ;  //Command: Request second generator set
   c_reqEStrt : BOOL ;  //Command: Emergency request next generator set
   c_req2EStrt : BOOL ; //Command: Emergency request second generator set
   c_genBrkOpn : BOOL ; //Command: Generator breaker open by protection
   var01 : BOOL ;
   var02 : BOOL ;
   var03 : BOOL ;
   c_unitLock : BOOL ;  //Command: Block generator set
   c_simulLock : BOOL ; //Command: Simultaneous lock activating
   c_uncUBLoff : BOOL ; //Command: force UBL mode off
   c_shoreMode : BOOL ; //Command: Shore connection mode activating
   var04 : BOOL ;
   c_takePreSeOrd : BOOL ;  //Command: Take over pre select order via MPI
   c_preSeLock : BOOL ; //Command: Preselection lock activating
   c_life : BOOL ;  //Life-Flag
   var051 : BYTE ;
   var052 : BYTE ;
   a_cmdMirror : DINT ; //Command mirror (bit 0 ..31)
   f_auto : BOOL ;  //Feedback: Generator set in automatic
   f_rdyStandby : BOOL ;    //Feedback: Generator set ready for standby
   f_brk_clse : BOOL ;  //Feedback: Generator breaker closed
   f_onbus : BOOL ; //Feedback: Generator set on busbar in automatic
   f_lock : BOOL ;  //Feedback: Generator set blocked
   f_stp : BOOL ;   //Feedback: Diesel is stopped
   f_blackout : BOOL ;  //Feedback: blackout
   f_SGonbus : BOOL ;   //Feedback: This generator is as a SG on bus
   f_simulLock : BOOL ; //Feedback: Simultaneous lock
   f_preSeLock : BOOL ; //Feedback: Preselection lock activating
   f_i_SC : BOOL ;  //Feedback: generator breaker was opened becauce of short curcuit
   f_busy_Gset : BOOL ; //Feedback: Preselection lock request not possible in the moment
   var053a : BOOL ;
   f_shoreMode : BOOL ; //Feedback: Shore connection mode is activated
   f_rdy_swtchOn : BOOL ;   //Feedback: Generator set ready for switch on
   f_shore_act : BOOL ;  //Feedback: Shore connection is activing (one or more)
   f_LCtrlLock : BOOL ; //Feedback: Load controller is locked
   f_FCtrlLock : BOOL ; //Feedback: Frequency controller is locked
   f_UBLmax_act : BOOL ;    //Feedback: UBLmax is active
   var055 : BOOL ;
   f_UBL_MinLock : BOOL ;   //Command: UBL mode lock because of minimum load
   c_lockShtdwn : BOOL ;    //Command: no stop in case of underload (=1)
   c_takeLckShtdn : BOOL ;  //Command: take over command 'no stop in case of underload'
   c_AllTieBrkOn : BOOL ;   //Feedback: tie breaker on
   c_LckCtrl : BOOL ;   //Command: Lock controller (load & frequency) -TIE BREAKER ONLY-
   c_takeLckCtrl : BOOL ;   //Command: take over 'Lock controller' -TIE BREAKER ONLY-
   f_tieBrkOn : BOOL ;  //Feedback: tie breaker on -TIE BREAKER ONLY-
   f_tieBrkTrip : BOOL ;    //Feedback: tie breaker tripped -TIE BREAKER ONLY-
   var056a : BOOL ;
   var056b : BOOL ;
   var056c : BOOL ;
   var056d : BOOL ;
   a_load : INT ;   // Actual value: Active power
   s_ordSq1_8 : DINT ;  //setpoint: Start stop sequence of the actual configuration - (Gen.1 -8) -
   s_ordSq9_15 : DINT ; //Setpoint: Start stop sequence of the actual configuration - (Gen.9 -15) -
   var131 : BYTE ;
   var14 : BYTE ;
   var15 : BYTE ;
   var16 : BYTE ;
   var17 : INT ;
   var18 : INT ;    // EMPFANGSFACH
   c_reqStrtG8 : BOOL ; //Command: Request next generator set
   c_req2StrtG8 : BOOL ;    //Command: Request second generator set
   c_reqEStrtG8 : BOOL ;    //Command: Emergency request next generator set
   c_req2EStrtG8 : BOOL ;   //Command: Emergency request second generator set
   c_genBrkOpnG8 : BOOL ;   //Command: Generator breaker open by protection
   var01G8 : BOOL ;
   var02G8 : BOOL ;
   var03G8 : BOOL ;
   c_unitLockG8 : BOOL ;    //Command: Block generator set
   c_simulLockG8 : BOOL ;   //Command: Simultaneous lock activating
   c_uncUBLoffG8 : BOOL ;   //Command: force UBL mode off
   c_shoreModeG8 : BOOL ;   //Command: Shore connection mode activating
   var04G8 : BOOL ;
   c_takePreSeOrdG8 : BOOL ;    //Command: Take over pre select order via MPI
   c_preSeLockG8 : BOOL ;   //Command: Preselection lock activating
   c_lifeG8 : BOOL ;    //Life-Flag
   var051G8 : BYTE ;
   var052G8 : BYTE ;
   a_cmdMirrorG8 : DINT ;   //Command mirror (bit 0 ..31)
   f_autoG8 : BOOL ;    //Feedback: Generator set in automatic
   f_rdyStdbyG8 : BOOL ;    //Feedback: Generator set ready for standby
   f_brk_clseG8 : BOOL ;    //Feedback: Generator breaker closed
   f_onbusG8 : BOOL ;   //Feedback: Generator set on busbar in automatic
   f_lockG8 : BOOL ;    //Feedback: Generator set blocked
   f_stpG8 : BOOL ; //Feedback: Diesel is stopped
   f_blackoutG8 : BOOL ;    //Feedback: blackout
   f_SGonbusG8 : BOOL ; //Feedback: Generator is as a SG on bus
   f_simulLockG8 : BOOL ;   //Feedback: Simultaneous lock
   f_preSeLockG8 : BOOL ;   //Feedback: Preselection lock activating
   f_i_SC_G8 : BOOL ;   //Feedback: generator breaker was opened becauce of short curcuit
   f_busy_GsetG8 : BOOL ;   //Feedback: Preselection lock request not possible in the moment
   var053aG8 : BOOL ;
   f_shoreModeG8 : BOOL ;   //Feedback: Shore connection mode is activated
   f_rdy_swtchOnG8 : BOOL ; //Feedback: Generator set ready for switch on
   f_shore_actG8 : BOOL ;   //Feedback: Shore connection is activing (one or more)
   f_LCtrlLockG8 : BOOL ;   //Feedback: Load controller is locked
   f_FCtrlLockG8 : BOOL ;   //Feedback: Frequency controller is locked
   f_UBLmax_actG8 : BOOL ;  //Feedback: UBLmax is active
   var055G8 : BOOL ;
   f_UBL_MinLockG8 : BOOL ; //Command: UBL mode lock because of minimum load
   c_lockShtdwnG8 : BOOL ;  //Command: no stop in case of underload (=1)
   c_takeLckShtdnG8 : BOOL ;    //Command: take over command 'no stop in case of underload'
   c_AllTieBrkOnG8 : BOOL ; //Feedback: tie breaker on
   c_LckCtrlG8 : BOOL ; //Command: Lock controller (load & frequency)
   c_takeLckCtrlG8 : BOOL ; //Command: take over 'Lock controller'
   f_tieBrkOnG8 : BOOL ;    //Feedback: tie breaker on
   f_tieBrkTripG8 : BOOL ;  //Feedback: tie breaker tripped
   var056aG8 : BOOL ;
   var056bG8 : BOOL ;
   var056cG8 : BOOL ;
   var056dG8 : BOOL ;
   a_loadG8 : INT ; // Actual value: Active power
   s_ordSq1_8G8 : DINT ;    //setpoint: Start stop sequence of the actual configuration - (Gen.1 -8) -
   s_ordSq9_15G8 : DINT ;   // Setpoint: Start stop sequence of the actual configuration - (Gen.9 -15) -
   var131G8 : BYTE ;
   var14G8 : BYTE ;
   var15G8 : BYTE ;
   var16G8 : BYTE ;
   var19G8 : INT ;
   var20G8 : INT ;
  END_STRUCT ;
BEGIN
   c_reqStrt := FALSE;
   c_req2Strt := FALSE;
   c_reqEStrt := FALSE;
   c_req2EStrt := FALSE;
   c_genBrkOpn := FALSE;
   var01 := FALSE;
   var02 := FALSE;
   var03 := FALSE;
   c_unitLock := FALSE;
   c_simulLock := FALSE;
   c_uncUBLoff := FALSE;
   c_shoreMode := FALSE;
   var04 := FALSE;
   c_takePreSeOrd := FALSE;
   c_preSeLock := FALSE;
   c_life := FALSE;
   var051 := B#16#0;
   var052 := B#16#0;
   a_cmdMirror := L#0;
   f_auto := FALSE;
   f_rdyStandby := FALSE;
   f_brk_clse := FALSE;
   f_onbus := FALSE;
   f_lock := FALSE;
   f_stp := FALSE;
   f_blackout := FALSE;
   f_SGonbus := FALSE;
   f_simulLock := FALSE;
   f_preSeLock := FALSE;
   f_i_SC := FALSE;
   f_busy_Gset := FALSE;
   var053a := FALSE;
   f_shoreMode := FALSE;
   f_rdy_swtchOn := FALSE;
   f_shore_act := FALSE;
   f_LCtrlLock := FALSE;
   f_FCtrlLock := FALSE;
   f_UBLmax_act := FALSE;
   var055 := FALSE;
   f_UBL_MinLock := FALSE;
   c_lockShtdwn := FALSE;
   c_takeLckShtdn := FALSE;
   c_AllTieBrkOn := FALSE;
   c_LckCtrl := FALSE;
   c_takeLckCtrl := FALSE;
   f_tieBrkOn := FALSE;
   f_tieBrkTrip := FALSE;
   var056a := FALSE;
   var056b := FALSE;
   var056c := FALSE;
   var056d := FALSE;
   a_load := 0;
   s_ordSq1_8 := L#0;
   s_ordSq9_15 := L#0;
   var131 := B#16#0;
   var14 := B#16#0;
   var15 := B#16#0;
   var16 := B#16#0;
   var17 := 0;
   var18 := 0;
   c_reqStrtG8 := FALSE;
   c_req2StrtG8 := FALSE;
   c_reqEStrtG8 := FALSE;
   c_req2EStrtG8 := FALSE;
   c_genBrkOpnG8 := FALSE;
   var01G8 := FALSE;
   var02G8 := FALSE;
   var03G8 := FALSE;
   c_unitLockG8 := FALSE;
   c_simulLockG8 := FALSE;
   c_uncUBLoffG8 := FALSE;
   c_shoreModeG8 := FALSE;
   var04G8 := FALSE;
   c_takePreSeOrdG8 := FALSE;
   c_preSeLockG8 := FALSE;
   c_lifeG8 := FALSE;
   var051G8 := B#16#0;
   var052G8 := B#16#0;
   a_cmdMirrorG8 := L#0;
   f_autoG8 := FALSE;
   f_rdyStdbyG8 := FALSE;
   f_brk_clseG8 := FALSE;
   f_onbusG8 := FALSE;
   f_lockG8 := FALSE;
   f_stpG8 := FALSE;
   f_blackoutG8 := FALSE;
   f_SGonbusG8 := FALSE;
   f_simulLockG8 := FALSE;
   f_preSeLockG8 := FALSE;
   f_i_SC_G8 := FALSE;
   f_busy_GsetG8 := FALSE;
   var053aG8 := FALSE;
   f_shoreModeG8 := FALSE;
   f_rdy_swtchOnG8 := FALSE;
   f_shore_actG8 := FALSE;
   f_LCtrlLockG8 := FALSE;
   f_FCtrlLockG8 := FALSE;
   f_UBLmax_actG8 := FALSE;
   var055G8 := FALSE;
   f_UBL_MinLockG8 := FALSE;
   c_lockShtdwnG8 := FALSE;
   c_takeLckShtdnG8 := FALSE;
   c_AllTieBrkOnG8 := FALSE;
   c_LckCtrlG8 := FALSE;
   c_takeLckCtrlG8 := FALSE;
   f_tieBrkOnG8 := FALSE;
   f_tieBrkTripG8 := FALSE;
   var056aG8 := FALSE;
   var056bG8 := FALSE;
   var056cG8 := FALSE;
   var056dG8 := FALSE;
   a_loadG8 := 0;
   s_ordSq1_8G8 := L#0;
   s_ordSq9_15G8 := L#0;
   var131G8 := B#16#0;
   var14G8 := B#16#0;
   var15G8 := B#16#0;
   var16G8 := B#16#0;
   var19G8 := 0;
   var20G8 := 0;
END_DATA_BLOCK


DATA_BLOCK "I_Gen9SR"
TITLE =Interface generator set 9. The 1. part contains the send
//area, the 2.part the receive area.                                                !
//
// I_Gen9SR
// Sende-/Empfangsfach MPI Generator 9
// Der Datenaustausch von oder zum Generator 1 erfolgt über diesen DB. Das Sendefach liegt im
// ersten Teil, das Empfangsteil liegt im zweiten Teil.
//
// Dieser DB ist für den TYP GENERATOR.
//
//
//  Siemens AG ATD IS3T, Kahle +494028892022, jens.kahle@hbg.siemens.de
//  PMA71
//  = Sende-/Empfangsfach MPI Generator 1
//  Datum aktuelle Version: 04.03.99
//  Version, Änd-Datum, Bearbeiter, geänderte Variablen
//  01.01,   31.01.99,  Kahle,      erste Version
//  01.02,   10.03.99,  Kahle,      Start/StoppReihenfolge,Kommando-
//                                  Spiegel, binäre Signale umsortieren
//
//KNOW_HOW_PROTECT
// (If specified, no more changes can be made once the block is generated)
//UNLINKED
// (If specified, the generated block is only available in the PLC load
//  memory)
//READ_ONLY
// (If specified, the generated block cannot be changed in the programmable
//  controller)
AUTHOR : Kahle
FAMILY : PMA71
NAME : I_Gen9SR
VERSION : 1.3


  STRUCT    // SENDEFACH
   c_reqStrt : BOOL ;   //Command: Request next generator set
   c_req2Strt : BOOL ;  //Command: Request second generator set
   c_reqEStrt : BOOL ;  //Command: Emergency request next generator set
   c_req2EStrt : BOOL ; //Command: Emergency request second generator set
   c_genBrkOpn : BOOL ; //Command: Generator breaker open by protection
   var01 : BOOL ;
   var02 : BOOL ;
   var03 : BOOL ;
   c_unitLock : BOOL ;  //Command: Block generator set
   c_simulLock : BOOL ; //Command: Simultaneous lock activating
   c_uncUBLoff : BOOL ; //Command: force UBL mode off
   c_shoreMode : BOOL ; //Command: Shore connection mode activating
   var04 : BOOL ;
   c_takePreSeOrd : BOOL ;  //Command: Take over pre select order via MPI
   c_preSeLock : BOOL ; //Command: Preselection lock activating
   c_life : BOOL ;  //Life-Flag
   var051 : BYTE ;
   var052 : BYTE ;
   a_cmdMirror : DINT ; //Command mirror (bit 0 ..31)
   f_auto : BOOL ;  //Feedback: Generator set in automatic
   f_rdyStandby : BOOL ;    //Feedback: Generator set ready for standby
   f_brk_clse : BOOL ;  //Feedback: Generator breaker closed
   f_onbus : BOOL ; //Feedback: Generator set on busbar in automatic
   f_lock : BOOL ;  //Feedback: Generator set blocked
   f_stp : BOOL ;   //Feedback: Diesel is stopped
   f_blackout : BOOL ;  //Feedback: blackout
   f_SGonbus : BOOL ;   //Feedback: This generator is as a SG on bus
   f_simulLock : BOOL ; //Feedback: Simultaneous lock
   f_preSeLock : BOOL ; //Feedback: Preselection lock activating
   f_i_SC : BOOL ;  //Feedback: generator breaker was opened becauce of short curcuit
   f_busy_Gset : BOOL ; //Feedback: Preselection lock request not possible in the moment
   var053a : BOOL ;
   f_shoreMode : BOOL ; //Feedback: Shore connection mode is activated
   f_rdy_swtchOn : BOOL ;   //Feedback: Generator set ready for switch on
   f_shore_act : BOOL ; //Feedback: Shore connection is activing (one or more)
   f_LCtrlLock : BOOL ; //Feedback: Load controller is locked
   f_FCtrlLock : BOOL ; //Feedback: Frequency controller is locked
   f_UBLmax_act : BOOL ;    //Feedback: UBLmax is active
   var055 : BOOL ;
   f_UBL_MinLock : BOOL ;   //Command: UBL mode lock because of minimum load
   c_lockShtdwn : BOOL ;    //Command: no stop in case of underload (=1)
   c_takeLckShtdn : BOOL ;  //Command: take over command 'no stop in case of underload'
   c_AllTieBrkOn : BOOL ;   //Feedback: tie breaker on
   c_LckCtrl : BOOL ;   //Command: Lock controller (load & frequency) -TIE BREAKER ONLY-
   c_takeLckCtrl : BOOL ;   //Command: take over 'Lock controller' -TIE BREAKER ONLY-
   f_tieBrkOn : BOOL ;  //Feedback: tie breaker on -TIE BREAKER ONLY-
   f_tieBrkTrip : BOOL ;    //Feedback: tie breaker tripped -TIE BREAKER ONLY-
   var056a : BOOL ;
   var056b : BOOL ;
   var056c : BOOL ;
   var056d : BOOL ;
   a_load : INT ;   // Actual value: Active power
   s_ordSq1_8 : DINT ;  //setpoint: Start stop sequence of the actual configuration - (Gen.1 -8) -
   s_ordSq9_15 : DINT ; //Setpoint: Start stop sequence of the actual configuration - (Gen.9 -15) -
   var131 : BYTE ;
   var14 : BYTE ;
   var15 : BYTE ;
   var16 : BYTE ;
   var17 : INT ;
   var18 : INT ;    // EMPFANGSFACH
   c_reqStrtG9 : BOOL ; //Command: Request next generator set
   c_req2StrtG9 : BOOL ;    //Command: Request second generator set
   c_reqEStrtG9 : BOOL ;    //Command: Emergency request next generator set
   c_req2EStrtG9 : BOOL ;   //Command: Emergency request second generator set
   c_genBrkOpnG9 : BOOL ;   //Command: Generator breaker open by protection
   var01G9 : BOOL ;
   var02G9 : BOOL ;
   var03G9 : BOOL ;
   c_unitLockG9 : BOOL ;    //Command: Block generator set
   c_simulLockG9 : BOOL ;   //Command: Simultaneous lock activating
   c_uncUBLoffG9 : BOOL ;   //Command: force UBL mode off
   c_shoreModeG9 : BOOL ;   //Command: Shore connection mode activating
   var04G9 : BOOL ;
   c_takePreSeOrdG9 : BOOL ;    //Command: Take over pre select order via MPI
   c_preSeLockG9 : BOOL ;   //Command: Preselection lock activating
   c_lifeG9 : BOOL ;    //Life-Flag
   var051G9 : BYTE ;
   var052G9 : BYTE ;
   a_cmdMirrorG9 : DINT ;   //Command mirror (bit 0 ..31)
   f_autoG9 : BOOL ;    //Feedback: Generator set in automatic
   f_rdyStdbyG9 : BOOL ;    //Feedback: Generator set ready for standby
   f_brk_clseG9 : BOOL ;    //Feedback: Generator breaker closed
   f_onbusG9 : BOOL ;   //Feedback: Generator set on busbar in automatic
   f_lockG9 : BOOL ;    //Feedback: Generator set blocked
   f_stpG9 : BOOL ; //Feedback: Diesel is stopped
   f_blackoutG9 : BOOL ;    //Feedback: blackout
   f_SGonbusG9 : BOOL ; //Feedback: Generator is as a SG on bus
   f_simulLockG9 : BOOL ;   //Feedback: Simultaneous lock
   f_preSeLockG9 : BOOL ;   //Feedback: Preselection lock activating
   f_i_SC_G9 : BOOL ;   //Feedback: generator breaker was opened becauce of short curcuit
   f_busy_GsetG9 : BOOL ;   //Feedback: Preselection lock request not possible in the moment
   var053aG9 : BOOL ;
   f_shoreModeG9 : BOOL ;   //Feedback: Shore connection mode is activated
   f_rdy_swtchOnG9 : BOOL ; //Feedback: Generator set ready for switch on
   f_shore_actG9 : BOOL ;   //Feedback: Shore connection is activing (one or more)
   f_LCtrlLockG9 : BOOL ;   //Feedback: Load controller is locked
   f_FCtrlLockG9 : BOOL ;   //Feedback: Frequency controller is locked
   f_UBLmax_actG9 : BOOL ;  //Feedback: UBLmax is active
   var055G9 : BOOL ;
   f_UBL_MinLockG9 : BOOL ; //Command: UBL mode lock because of minimum load
   c_lockShtdwnG9 : BOOL ;  //Command: no stop in case of underload (=1)
   c_takeLckShtdnG9 : BOOL ;    //Command: take over command 'no stop in case of underload'
   c_AllTieBrkOnG9 : BOOL ; //Feedback: tie breaker on
   c_LckCtrlG9 : BOOL ; //Command: Lock controller (load & frequency)
   c_takeLckCtrlG9 : BOOL ; //Command: take over 'Lock controller'
   f_tieBrkOnG9 : BOOL ;    //Feedback: tie breaker on
   f_tieBrkTripG9 : BOOL ;  //Feedback: tie breaker tripped
   var056aG9 : BOOL ;
   var056bG9 : BOOL ;
   var056cG9 : BOOL ;
   var056dG9 : BOOL ;
   a_loadG9 : INT ; // Actual value: Active power
   s_ordSq1_8G9 : DINT ;    //setpoint: Start stop sequence of the actual configuration - (Gen.1 -8) -
   s_ordSq9_15G9 : DINT ;   // Setpoint: Start stop sequence of the actual configuration - (Gen.9 -15) -
   var131G9 : BYTE ;
   var14G9 : BYTE ;
   var15G9 : BYTE ;
   var16G9 : BYTE ;
   var19G9 : INT ;
   var20G9 : INT ;
  END_STRUCT ;
BEGIN
   c_reqStrt := FALSE;
   c_req2Strt := FALSE;
   c_reqEStrt := FALSE;
   c_req2EStrt := FALSE;
   c_genBrkOpn := FALSE;
   var01 := FALSE;
   var02 := FALSE;
   var03 := FALSE;
   c_unitLock := FALSE;
   c_simulLock := FALSE;
   c_uncUBLoff := FALSE;
   c_shoreMode := FALSE;
   var04 := FALSE;
   c_takePreSeOrd := FALSE;
   c_preSeLock := FALSE;
   c_life := FALSE;
   var051 := B#16#0;
   var052 := B#16#0;
   a_cmdMirror := L#0;
   f_auto := FALSE;
   f_rdyStandby := FALSE;
   f_brk_clse := FALSE;
   f_onbus := FALSE;
   f_lock := FALSE;
   f_stp := FALSE;
   f_blackout := FALSE;
   f_SGonbus := FALSE;
   f_simulLock := FALSE;
   f_preSeLock := FALSE;
   f_i_SC := FALSE;
   f_busy_Gset := FALSE;
   var053a := FALSE;
   f_shoreMode := FALSE;
   f_rdy_swtchOn := FALSE;
   f_shore_act := FALSE;
   f_LCtrlLock := FALSE;
   f_FCtrlLock := FALSE;
   f_UBLmax_act := FALSE;
   var055 := FALSE;
   f_UBL_MinLock := FALSE;
   c_lockShtdwn := FALSE;
   c_takeLckShtdn := FALSE;
   c_AllTieBrkOn := FALSE;
   c_LckCtrl := FALSE;
   c_takeLckCtrl := FALSE;
   f_tieBrkOn := FALSE;
   f_tieBrkTrip := FALSE;
   var056a := FALSE;
   var056b := FALSE;
   var056c := FALSE;
   var056d := FALSE;
   a_load := 0;
   s_ordSq1_8 := L#0;
   s_ordSq9_15 := L#0;
   var131 := B#16#0;
   var14 := B#16#0;
   var15 := B#16#0;
   var16 := B#16#0;
   var17 := 0;
   var18 := 0;
   c_reqStrtG9 := FALSE;
   c_req2StrtG9 := FALSE;
   c_reqEStrtG9 := FALSE;
   c_req2EStrtG9 := FALSE;
   c_genBrkOpnG9 := FALSE;
   var01G9 := FALSE;
   var02G9 := FALSE;
   var03G9 := FALSE;
   c_unitLockG9 := FALSE;
   c_simulLockG9 := FALSE;
   c_uncUBLoffG9 := FALSE;
   c_shoreModeG9 := FALSE;
   var04G9 := FALSE;
   c_takePreSeOrdG9 := FALSE;
   c_preSeLockG9 := FALSE;
   c_lifeG9 := FALSE;
   var051G9 := B#16#0;
   var052G9 := B#16#0;
   a_cmdMirrorG9 := L#0;
   f_autoG9 := FALSE;
   f_rdyStdbyG9 := FALSE;
   f_brk_clseG9 := FALSE;
   f_onbusG9 := FALSE;
   f_lockG9 := FALSE;
   f_stpG9 := FALSE;
   f_blackoutG9 := FALSE;
   f_SGonbusG9 := FALSE;
   f_simulLockG9 := FALSE;
   f_preSeLockG9 := FALSE;
   f_i_SC_G9 := FALSE;
   f_busy_GsetG9 := FALSE;
   var053aG9 := FALSE;
   f_shoreModeG9 := FALSE;
   f_rdy_swtchOnG9 := FALSE;
   f_shore_actG9 := FALSE;
   f_LCtrlLockG9 := FALSE;
   f_FCtrlLockG9 := FALSE;
   f_UBLmax_actG9 := FALSE;
   var055G9 := FALSE;
   f_UBL_MinLockG9 := FALSE;
   c_lockShtdwnG9 := FALSE;
   c_takeLckShtdnG9 := FALSE;
   c_AllTieBrkOnG9 := FALSE;
   c_LckCtrlG9 := FALSE;
   c_takeLckCtrlG9 := FALSE;
   f_tieBrkOnG9 := FALSE;
   f_tieBrkTripG9 := FALSE;
   var056aG9 := FALSE;
   var056bG9 := FALSE;
   var056cG9 := FALSE;
   var056dG9 := FALSE;
   a_loadG9 := 0;
   s_ordSq1_8G9 := L#0;
   s_ordSq9_15G9 := L#0;
   var131G9 := B#16#0;
   var14G9 := B#16#0;
   var15G9 := B#16#0;
   var16G9 := B#16#0;
   var19G9 := 0;
   var20G9 := 0;
END_DATA_BLOCK


DATA_BLOCK "I_Gen10SR"
TITLE =Interface generator set 10. The 1. part contains the send
//area, the 2.part the receive area.                                                !
//
// I_Gen10SR
// Sende-/Empfangsfach MPI Generator 10
// Der Datenaustausch von oder zum Generator 1 erfolgt über diesen DB. Das Sendefach liegt im
// ersten Teil, das Empfangsteil liegt im zweiten Teil.
//
// Dieser DB ist für den TYP GENERATOR.
//
//
//  Siemens AG ATD IS3T, Kahle +494028892022, jens.kahle@hbg.siemens.de
//  PMA71
//  = Sende-/Empfangsfach MPI Generator 1
//  Datum aktuelle Version: 04.03.99
//  Version, Änd-Datum, Bearbeiter, geänderte Variablen
//  01.01,   31.01.99,  Kahle,      erste Version
//  01.02,   10.03.99,  Kahle,      Start/StoppReihenfolge,Kommando-
//                                  Spiegel, binäre Signale umsortieren
//
//KNOW_HOW_PROTECT
// (If specified, no more changes can be made once the block is generated)
//UNLINKED
// (If specified, the generated block is only available in the PLC load
//  memory)
//READ_ONLY
// (If specified, the generated block cannot be changed in the programmable
//  controller)
AUTHOR : Kahle
FAMILY : PMA71
NAME : I_Ge10SR
VERSION : 1.3


  STRUCT    // SENDEFACH
   c_reqStrt : BOOL ;   //Command: Request next generator set
   c_req2Strt : BOOL ;  //Command: Request second generator set
   c_reqEStrt : BOOL ;  //Command: Emergency request next generator set
   c_req2EStrt : BOOL ; //Command: Emergency request second generator set
   c_genBrkOpn : BOOL ; //Command: Generator breaker open by protection
   var01 : BOOL ;
   var02 : BOOL ;
   var03 : BOOL ;
   c_unitLock : BOOL ;  //Command: Block generator set
   c_simulLock : BOOL ; //Command: Simultaneous lock activating
   c_uncUBLoff : BOOL ; //Command: force UBL mode off
   c_shoreMode : BOOL ; //Command: Shore connection mode activating
   var04 : BOOL ;
   c_takePreSeOrd : BOOL ;  //Command: Take over pre select order via MPI
   c_preSeLock : BOOL ; //Command: Preselection lock activating
   c_life : BOOL ;  //Life-Flag
   var051 : BYTE ;
   var052 : BYTE ;
   a_cmdMirror : DINT ; //Command mirror (bit 0 ..31)
   f_auto : BOOL ;  //Feedback: Generator set in automatic
   f_rdyStandby : BOOL ;    //Feedback: Generator set ready for standby
   f_brk_clse : BOOL ;  //Feedback: Generator breaker closed
   f_onbus : BOOL ; //Feedback: Generator set on busbar in automatic
   f_lock : BOOL ;  //Feedback: Generator set blocked
   f_stp : BOOL ;   //Feedback: Diesel is stopped
   f_blackout : BOOL ;  //Feedback: blackout
   f_SGonbus : BOOL ;   //Feedback: This generator is as a SG on bus
   f_simulLock : BOOL ; //Feedback: Simultaneous lock
   f_preSeLock : BOOL ; //Feedback: Preselection lock activating
   f_i_SC : BOOL ;  //Feedback: generator breaker was opened becauce of short curcuit
   f_busy_Gset : BOOL ; //Feedback: Preselection lock request not possible in the moment
   var053a : BOOL ;
   f_shoreMode : BOOL ; //Feedback: Shore connection mode is activated
   f_rdy_swtchOn : BOOL ;   //Feedback: Generator set ready for switch on
   f_shore_act : BOOL ; //Feedback: Shore connection is activing (one or more)
   f_LCtrlLock : BOOL ; //Feedback: Load controller is locked
   f_FCtrlLock : BOOL ; //Feedback: Frequency controller is locked
   f_UBLmax_act : BOOL ;    //Feedback: UBLmax is active
   var055 : BOOL ;
   f_UBL_MinLock : BOOL ;   //Command: UBL mode lock because of minimum load
   c_lockShtdwn : BOOL ;    //Command: no stop in case of underload (=1)
   c_takeLckShtdn : BOOL ;  //Command: take over command 'no stop in case of underload'
   c_AllTieBrkOn : BOOL ;   //Feedback: tie breaker on
   c_LckCtrl : BOOL ;   //Command: Lock controller (load & frequency) -TIE BREAKER ONLY-
   c_takeLckCtrl : BOOL ;   //Command: take over 'Lock controller' -TIE BREAKER ONLY-
   f_tieBrkOn : BOOL ;  //Feedback: tie breaker on -TIE BREAKER ONLY-
   f_tieBrkTrip : BOOL ;    //Feedback: tie breaker tripped -TIE BREAKER ONLY-
   var056a : BOOL ;
   var056b : BOOL ;
   var056c : BOOL ;
   var056d : BOOL ;
   a_load : INT ;   // Actual value: Active power
   s_ordSq1_8 : DINT ;  //setpoint: Start stop sequence of the actual configuration - (Gen.1 -8) -
   s_ordSq9_15 : DINT ; //Setpoint: Start stop sequence of the actual configuration - (Gen.9 -15) -
   var131 : BYTE ;
   var14 : BYTE ;
   var15 : BYTE ;
   var16 : BYTE ;
   var17 : INT ;
   var18 : INT ;    // EMPFANGSFACH
   c_reqStrtG10 : BOOL ;    //Command: Request next generator set
   c_req2StrtG10 : BOOL ;   //Command: Request second generator set
   c_reqEStrtG10 : BOOL ;   //Command: Emergency request next generator set
   c_req2EStrtG10 : BOOL ;  //Command: Emergency request second generator set
   c_genBrkOpnG10 : BOOL ;   //Command: Generator breaker open by protection
   var01G10 : BOOL ;
   var02G10 : BOOL ;
   var03G10 : BOOL ;
   c_unitLockG10 : BOOL ;   //Command: Block generator set
   c_simulLockG10 : BOOL ;  //Command: Simultaneous lock activating
   c_uncUBLoffG10 : BOOL ;  //Command: force UBL mode off
   c_shoreModeG10 : BOOL ;  //Command: Shore connection mode activating
   var04G10 : BOOL ;
   c_takePreSeOrdG10 : BOOL ;   //Command: Take over pre select order via MPI
   c_preSeLockG10 : BOOL ;  //Command: Preselection lock activating
   c_lifeG10 : BOOL ;   //Life-Flag
   var051G10 : BYTE ;
   var052G10 : BYTE ;
   a_cmdMirrorG10 : DINT ;  //Command mirror (bit 0 ..31)
   f_autoG10 : BOOL ;   //Feedback: Generator set in automatic
   f_rdyStdbyG10 : BOOL ;   //Feedback: Generator set ready for standby
   f_brk_clseG10 : BOOL ;   //Feedback: Generator breaker closed
   f_onbusG10 : BOOL ;  //Feedback: Generator set on busbar in automatic
   f_lockG10 : BOOL ;   //Feedback: Generator set blocked
   f_stpG10 : BOOL ; //Feedback: Diesel is stopped
   f_blackoutG10 : BOOL ;   //Feedback: blackout
   f_SGonbusG10 : BOOL ;    //Feedback: Generator is as a SG on bus
   f_simulLockG10 : BOOL ;  //Feedback: Simultaneous lock
   f_preSeLockG10 : BOOL ;  //Feedback: Preselection lock activating
   f_i_SC_G10 : BOOL ;  //Feedback: generator breaker was opened becauce of short curcuit
   f_busy_GsetG10 : BOOL ;  //Feedback: Preselection lock request not possible in the moment
   var053aG10 : BOOL ;
   f_shoreModeG10 : BOOL ;  //Feedback: Shore connection mode is activated
   f_rdy_swtchOnG10 : BOOL ;    //Feedback: Generator set ready for switch on
   f_shore_actG10 : BOOL ;  //Feedback: Shore connection is activing (one or more)
   f_LCtrlLockG10 : BOOL ;  //Feedback: Load controller is locked
   f_FCtrlLockG10 : BOOL ;  //Feedback: Frequency controller is locked
   f_UBLmax_actG10 : BOOL ; //Feedback: UBLmax is active
   var055G10 : BOOL ;
   f_UBL_MinLockG10 : BOOL ;    //Command: UBL mode lock because of minimum load
   c_lockShtdwnG10 : BOOL ; //Command: no stop in case of underload (=1)
   c_takeLckShtdnG10 : BOOL ;   //Command: take over command 'no stop in case of underload'
   c_AllTieBrkOnG10 : BOOL ;    //Feedback: tie breaker on
   c_LckCtrlG10 : BOOL ;    //Command: Lock controller (load & frequency)
   c_takeLckCtrlG10 : BOOL ;    //Command: take over 'Lock controller'
   f_tieBrkOnG10 : BOOL ;   //Feedback: tie breaker on
   f_tieBrkTripG10 : BOOL ; //Feedback: tie breaker tripped
   var056aG10 : BOOL ;
   var056bG10 : BOOL ;
   var056cG10 : BOOL ;
   var056dG10 : BOOL ;
   a_loadG10 : INT ;    // Actual value: Active power
   s_ordSq1_8G10 : DINT ;   //setpoint: Start stop sequence of the actual configuration - (Gen.1 -8) -
   s_ordSq9_15G10 : DINT ;  // Setpoint: Start stop sequence of the actual configuration - (Gen.9 -15) -
   var131G10 : BYTE ;
   var14G10 : BYTE ;
   var15G10 : BYTE ;
   var16G10 : BYTE ;
   var19G10 : INT ;
   var20G10 : INT ;
  END_STRUCT ;
BEGIN
   c_reqStrt := FALSE;
   c_req2Strt := FALSE;
   c_reqEStrt := FALSE;
   c_req2EStrt := FALSE;
   c_genBrkOpn := FALSE;
   var01 := FALSE;
   var02 := FALSE;
   var03 := FALSE;
   c_unitLock := FALSE;
   c_simulLock := FALSE;
   c_uncUBLoff := FALSE;
   c_shoreMode := FALSE;
   var04 := FALSE;
   c_takePreSeOrd := FALSE;
   c_preSeLock := FALSE;
   c_life := FALSE;
   var051 := B#16#0;
   var052 := B#16#0;
   a_cmdMirror := L#0;
   f_auto := FALSE;
   f_rdyStandby := FALSE;
   f_brk_clse := FALSE;
   f_onbus := FALSE;
   f_lock := FALSE;
   f_stp := FALSE;
   f_blackout := FALSE;
   f_SGonbus := FALSE;
   f_simulLock := FALSE;
   f_preSeLock := FALSE;
   f_i_SC := FALSE;
   f_busy_Gset := FALSE;
   var053a := FALSE;
   f_shoreMode := FALSE;
   f_rdy_swtchOn := FALSE;
   f_shore_act := FALSE;
   f_LCtrlLock := FALSE;
   f_FCtrlLock := FALSE;
   f_UBLmax_act := FALSE;
   var055 := FALSE;
   f_UBL_MinLock := FALSE;
   c_lockShtdwn := FALSE;
   c_takeLckShtdn := FALSE;
   c_AllTieBrkOn := FALSE;
   c_LckCtrl := FALSE;
   c_takeLckCtrl := FALSE;
   f_tieBrkOn := FALSE;
   f_tieBrkTrip := FALSE;
   var056a := FALSE;
   var056b := FALSE;
   var056c := FALSE;
   var056d := FALSE;
   a_load := 0;
   s_ordSq1_8 := L#0;
   s_ordSq9_15 := L#0;
   var131 := B#16#0;
   var14 := B#16#0;
   var15 := B#16#0;
   var16 := B#16#0;
   var17 := 0;
   var18 := 0;
   c_reqStrtG10 := FALSE;
   c_req2StrtG10 := FALSE;
   c_reqEStrtG10 := FALSE;
   c_req2EStrtG10 := FALSE;
   c_genBrkOpnG10 := FALSE;
   var01G10 := FALSE;
   var02G10 := FALSE;
   var03G10 := FALSE;
   c_unitLockG10 := FALSE;
   c_simulLockG10 := FALSE;
   c_uncUBLoffG10 := FALSE;
   c_shoreModeG10 := FALSE;
   var04G10 := FALSE;
   c_takePreSeOrdG10 := FALSE;
   c_preSeLockG10 := FALSE;
   c_lifeG10 := FALSE;
   var051G10 := B#16#0;
   var052G10 := B#16#0;
   a_cmdMirrorG10 := L#0;
   f_autoG10 := FALSE;
   f_rdyStdbyG10 := FALSE;
   f_brk_clseG10 := FALSE;
   f_onbusG10 := FALSE;
   f_lockG10 := FALSE;
   f_stpG10 := FALSE;
   f_blackoutG10 := FALSE;
   f_SGonbusG10 := FALSE;
   f_simulLockG10 := FALSE;
   f_preSeLockG10 := FALSE;
   f_i_SC_G10 := FALSE;
   f_busy_GsetG10 := FALSE;
   var053aG10 := FALSE;
   f_shoreModeG10 := FALSE;
   f_rdy_swtchOnG10 := FALSE;
   f_shore_actG10 := FALSE;
   f_LCtrlLockG10 := FALSE;
   f_FCtrlLockG10 := FALSE;
   f_UBLmax_actG10 := FALSE;
   var055G10 := FALSE;
   f_UBL_MinLockG10 := FALSE;
   c_lockShtdwnG10 := FALSE;
   c_takeLckShtdnG10 := FALSE;
   c_AllTieBrkOnG10 := FALSE;
   c_LckCtrlG10 := FALSE;
   c_takeLckCtrlG10 := FALSE;
   f_tieBrkOnG10 := FALSE;
   f_tieBrkTripG10 := FALSE;
   var056aG10 := FALSE;
   var056bG10 := FALSE;
   var056cG10 := FALSE;
   var056dG10 := FALSE;
   a_loadG10 := 0;
   s_ordSq1_8G10 := L#0;
   s_ordSq9_15G10 := L#0;
   var131G10 := B#16#0;
   var14G10 := B#16#0;
   var15G10 := B#16#0;
   var16G10 := B#16#0;
   var19G10 := 0;
   var20G10 := 0;
END_DATA_BLOCK


DATA_BLOCK "I_Gen11SR"
TITLE =Interface generator set 11. The 1. part contains the send
//area, the 2.part the receive area.                                                !
//
// I_Gen11SR
// Sende-/Empfangsfach MPI Generator 11
// Der Datenaustausch von oder zum Generator 1 erfolgt über diesen DB. Das Sendefach liegt im
// ersten Teil, das Empfangsteil liegt im zweiten Teil.
//
// Dieser DB ist für den TYP GENERATOR.
//
//
//  Siemens AG ATD IS3T, Kahle +494028892022, jens.kahle@hbg.siemens.de
//  PMA71
//  = Sende-/Empfangsfach MPI Generator 1
//  Datum aktuelle Version: 04.03.99
//  Version, Änd-Datum, Bearbeiter, geänderte Variablen
//  01.01,   31.01.99,  Kahle,      erste Version
//  01.02,   10.03.99,  Kahle,      Start/StoppReihenfolge,Kommando-
//                                  Spiegel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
